VERSION 5.8 ;
BUSBITCHARS "[]" ;
DIVIDERCHAR "/" ;
UNITS
    DATABASE MICRONS 1000 ;
END UNITS

VIA ino_exec_entier_via1_2_1000_440_1_2_410_410
  VIARULE via1Array ;
  CUTSIZE 0.19 0.19 ;
  LAYERS Metal1 Via1 Metal2 ;
  CUTSPACING 0.22 0.22 ;
  ENCLOSURE 0.05 0.125 0.005 0.05 ;
  ROWCOL 1 2 ;
END ino_exec_entier_via1_2_1000_440_1_2_410_410

VIA ino_exec_entier_via2_3_1000_440_1_2_410_410
  VIARULE via2Array ;
  CUTSIZE 0.19 0.19 ;
  LAYERS Metal2 Via2 Metal3 ;
  CUTSPACING 0.22 0.22 ;
  ENCLOSURE 0.005 0.05 0.05 0.005 ;
  ROWCOL 1 2 ;
END ino_exec_entier_via2_3_1000_440_1_2_410_410

VIA ino_exec_entier_via3_4_1000_440_1_2_410_410
  VIARULE via3Array ;
  CUTSIZE 0.19 0.19 ;
  LAYERS Metal3 Via3 Metal4 ;
  CUTSPACING 0.22 0.22 ;
  ENCLOSURE 0.05 0.005 0.2 0.05 ;
  ROWCOL 1 2 ;
END ino_exec_entier_via3_4_1000_440_1_2_410_410

VIA ino_exec_entier_via4_5_1000_2000_1_1_840_840
  VIARULE viaTop1Array ;
  CUTSIZE 0.42 0.42 ;
  LAYERS Metal4 TopVia1 TopMetal1 ;
  CUTSPACING 0.42 0.42 ;
  ENCLOSURE 0.29 0.1 0.42 0.79 ;
END ino_exec_entier_via4_5_1000_2000_1_1_840_840

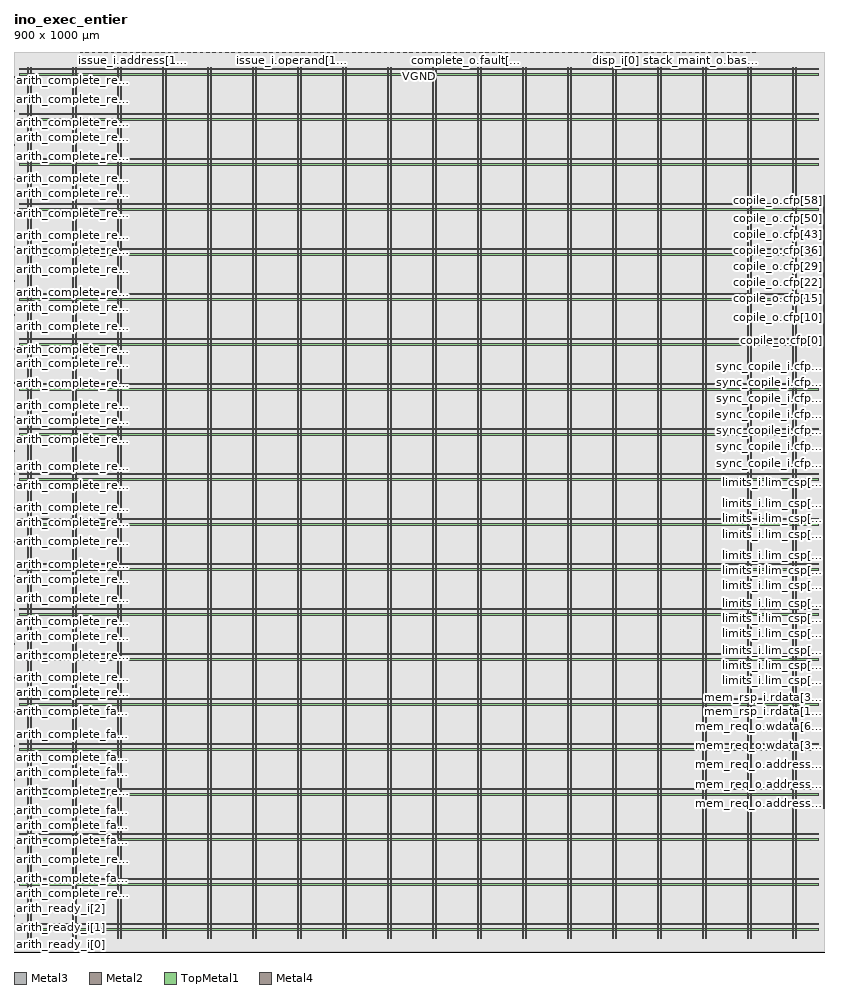
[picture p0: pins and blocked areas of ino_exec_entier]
MACRO ino_exec_entier
  FOREIGN ino_exec_entier 0 0 ;
  CLASS BLOCK ;
  SIZE 900 BY 1000 ;
  PIN arith_complete_fault_i.code[0]
    DIRECTION INPUT ;
    USE SIGNAL ;
    PORT
      LAYER Metal3 ;
        RECT  0 90.1 0.4 90.5 ;
    END
  END arith_complete_fault_i.code[0]
  PIN arith_complete_fault_i.code[1]
    DIRECTION INPUT ;
    USE SIGNAL ;
    PORT
      LAYER Metal3 ;
        RECT  0 115.3 0.4 115.7 ;
    END
  END arith_complete_fault_i.code[1]
  PIN arith_complete_fault_i.code[2]
    DIRECTION INPUT ;
    USE SIGNAL ;
    PORT
      LAYER Metal3 ;
        RECT  0 140.5 0.4 140.9 ;
    END
  END arith_complete_fault_i.code[2]
  PIN arith_complete_fault_i.code[3]
    DIRECTION INPUT ;
    USE SIGNAL ;
    PORT
      LAYER Metal3 ;
        RECT  0 165.7 0.4 166.1 ;
    END
  END arith_complete_fault_i.code[3]
  PIN arith_complete_fault_i.code[4]
    DIRECTION INPUT ;
    USE SIGNAL ;
    PORT
      LAYER Metal3 ;
        RECT  0 190.9 0.4 191.3 ;
    END
  END arith_complete_fault_i.code[4]
  PIN arith_complete_fault_i.code[5]
    DIRECTION INPUT ;
    USE SIGNAL ;
    PORT
      LAYER Metal3 ;
        RECT  0 216.1 0.4 216.5 ;
    END
  END arith_complete_fault_i.code[5]
  PIN arith_complete_fault_i.code[6]
    DIRECTION INPUT ;
    USE SIGNAL ;
    PORT
      LAYER Metal3 ;
        RECT  0 241.3 0.4 241.7 ;
    END
  END arith_complete_fault_i.code[6]
  PIN arith_complete_fault_i.code[7]
    DIRECTION INPUT ;
    USE SIGNAL ;
    PORT
      LAYER Metal3 ;
        RECT  0 266.5 0.4 266.9 ;
    END
  END arith_complete_fault_i.code[7]
  PIN arith_complete_fault_i.valid
    DIRECTION INPUT ;
    USE SIGNAL ;
    PORT
      LAYER Metal3 ;
        RECT  0 52.3 0.4 52.7 ;
    END
  END arith_complete_fault_i.valid
  PIN arith_complete_result_i[0]
    DIRECTION INPUT ;
    USE SIGNAL ;
    PORT
      LAYER Metal3 ;
        RECT  0 102.7 0.4 103.1 ;
    END
  END arith_complete_result_i[0]
  PIN arith_complete_result_i[10]
    DIRECTION INPUT ;
    USE SIGNAL ;
    PORT
      LAYER Metal3 ;
        RECT  0 316.9 0.4 317.3 ;
    END
  END arith_complete_result_i[10]
  PIN arith_complete_result_i[11]
    DIRECTION INPUT ;
    USE SIGNAL ;
    PORT
      LAYER Metal3 ;
        RECT  0 329.5 0.4 329.9 ;
    END
  END arith_complete_result_i[11]
  PIN arith_complete_result_i[12]
    DIRECTION INPUT ;
    USE SIGNAL ;
    PORT
      LAYER Metal3 ;
        RECT  0 342.1 0.4 342.5 ;
    END
  END arith_complete_result_i[12]
  PIN arith_complete_result_i[13]
    DIRECTION INPUT ;
    USE SIGNAL ;
    PORT
      LAYER Metal3 ;
        RECT  0 354.7 0.4 355.1 ;
    END
  END arith_complete_result_i[13]
  PIN arith_complete_result_i[14]
    DIRECTION INPUT ;
    USE SIGNAL ;
    PORT
      LAYER Metal3 ;
        RECT  0 367.3 0.4 367.7 ;
    END
  END arith_complete_result_i[14]
  PIN arith_complete_result_i[15]
    DIRECTION INPUT ;
    USE SIGNAL ;
    PORT
      LAYER Metal3 ;
        RECT  0 379.9 0.4 380.3 ;
    END
  END arith_complete_result_i[15]
  PIN arith_complete_result_i[16]
    DIRECTION INPUT ;
    USE SIGNAL ;
    PORT
      LAYER Metal3 ;
        RECT  0 392.5 0.4 392.9 ;
    END
  END arith_complete_result_i[16]
  PIN arith_complete_result_i[17]
    DIRECTION INPUT ;
    USE SIGNAL ;
    PORT
      LAYER Metal3 ;
        RECT  0 405.1 0.4 405.5 ;
    END
  END arith_complete_result_i[17]
  PIN arith_complete_result_i[18]
    DIRECTION INPUT ;
    USE SIGNAL ;
    PORT
      LAYER Metal3 ;
        RECT  0 417.7 0.4 418.1 ;
    END
  END arith_complete_result_i[18]
  PIN arith_complete_result_i[19]
    DIRECTION INPUT ;
    USE SIGNAL ;
    PORT
      LAYER Metal3 ;
        RECT  0 430.3 0.4 430.7 ;
    END
  END arith_complete_result_i[19]
  PIN arith_complete_result_i[1]
    DIRECTION INPUT ;
    USE SIGNAL ;
    PORT
      LAYER Metal3 ;
        RECT  0 127.9 0.4 128.3 ;
    END
  END arith_complete_result_i[1]
  PIN arith_complete_result_i[20]
    DIRECTION INPUT ;
    USE SIGNAL ;
    PORT
      LAYER Metal3 ;
        RECT  0 442.9 0.4 443.3 ;
    END
  END arith_complete_result_i[20]
  PIN arith_complete_result_i[21]
    DIRECTION INPUT ;
    USE SIGNAL ;
    PORT
      LAYER Metal3 ;
        RECT  0 455.5 0.4 455.9 ;
    END
  END arith_complete_result_i[21]
  PIN arith_complete_result_i[22]
    DIRECTION INPUT ;
    USE SIGNAL ;
    PORT
      LAYER Metal3 ;
        RECT  0 468.1 0.4 468.5 ;
    END
  END arith_complete_result_i[22]
  PIN arith_complete_result_i[23]
    DIRECTION INPUT ;
    USE SIGNAL ;
    PORT
      LAYER Metal3 ;
        RECT  0 480.7 0.4 481.1 ;
    END
  END arith_complete_result_i[23]
  PIN arith_complete_result_i[24]
    DIRECTION INPUT ;
    USE SIGNAL ;
    PORT
      LAYER Metal3 ;
        RECT  0 493.3 0.4 493.7 ;
    END
  END arith_complete_result_i[24]
  PIN arith_complete_result_i[25]
    DIRECTION INPUT ;
    USE SIGNAL ;
    PORT
      LAYER Metal3 ;
        RECT  0 505.9 0.4 506.3 ;
    END
  END arith_complete_result_i[25]
  PIN arith_complete_result_i[26]
    DIRECTION INPUT ;
    USE SIGNAL ;
    PORT
      LAYER Metal3 ;
        RECT  0 518.5 0.4 518.9 ;
    END
  END arith_complete_result_i[26]
  PIN arith_complete_result_i[27]
    DIRECTION INPUT ;
    USE SIGNAL ;
    PORT
      LAYER Metal3 ;
        RECT  0 531.1 0.4 531.5 ;
    END
  END arith_complete_result_i[27]
  PIN arith_complete_result_i[28]
    DIRECTION INPUT ;
    USE SIGNAL ;
    PORT
      LAYER Metal3 ;
        RECT  0 543.7 0.4 544.1 ;
    END
  END arith_complete_result_i[28]
  PIN arith_complete_result_i[29]
    DIRECTION INPUT ;
    USE SIGNAL ;
    PORT
      LAYER Metal3 ;
        RECT  0 556.3 0.4 556.7 ;
    END
  END arith_complete_result_i[29]
  PIN arith_complete_result_i[2]
    DIRECTION INPUT ;
    USE SIGNAL ;
    PORT
      LAYER Metal3 ;
        RECT  0 153.1 0.4 153.5 ;
    END
  END arith_complete_result_i[2]
  PIN arith_complete_result_i[30]
    DIRECTION INPUT ;
    USE SIGNAL ;
    PORT
      LAYER Metal3 ;
        RECT  0 568.9 0.4 569.3 ;
    END
  END arith_complete_result_i[30]
  PIN arith_complete_result_i[31]
    DIRECTION INPUT ;
    USE SIGNAL ;
    PORT
      LAYER Metal3 ;
        RECT  0 581.5 0.4 581.9 ;
    END
  END arith_complete_result_i[31]
  PIN arith_complete_result_i[32]
    DIRECTION INPUT ;
    USE SIGNAL ;
    PORT
      LAYER Metal3 ;
        RECT  0 594.1 0.4 594.5 ;
    END
  END arith_complete_result_i[32]
  PIN arith_complete_result_i[33]
    DIRECTION INPUT ;
    USE SIGNAL ;
    PORT
      LAYER Metal3 ;
        RECT  0 606.7 0.4 607.1 ;
    END
  END arith_complete_result_i[33]
  PIN arith_complete_result_i[34]
    DIRECTION INPUT ;
    USE SIGNAL ;
    PORT
      LAYER Metal3 ;
        RECT  0 619.3 0.4 619.7 ;
    END
  END arith_complete_result_i[34]
  PIN arith_complete_result_i[35]
    DIRECTION INPUT ;
    USE SIGNAL ;
    PORT
      LAYER Metal3 ;
        RECT  0 631.9 0.4 632.3 ;
    END
  END arith_complete_result_i[35]
  PIN arith_complete_result_i[36]
    DIRECTION INPUT ;
    USE SIGNAL ;
    PORT
      LAYER Metal3 ;
        RECT  0 644.5 0.4 644.9 ;
    END
  END arith_complete_result_i[36]
  PIN arith_complete_result_i[37]
    DIRECTION INPUT ;
    USE SIGNAL ;
    PORT
      LAYER Metal3 ;
        RECT  0 657.1 0.4 657.5 ;
    END
  END arith_complete_result_i[37]
  PIN arith_complete_result_i[38]
    DIRECTION INPUT ;
    USE SIGNAL ;
    PORT
      LAYER Metal3 ;
        RECT  0 669.7 0.4 670.1 ;
    END
  END arith_complete_result_i[38]
  PIN arith_complete_result_i[39]
    DIRECTION INPUT ;
    USE SIGNAL ;
    PORT
      LAYER Metal3 ;
        RECT  0 682.3 0.4 682.7 ;
    END
  END arith_complete_result_i[39]
  PIN arith_complete_result_i[3]
    DIRECTION INPUT ;
    USE SIGNAL ;
    PORT
      LAYER Metal3 ;
        RECT  0 178.3 0.4 178.7 ;
    END
  END arith_complete_result_i[3]
  PIN arith_complete_result_i[40]
    DIRECTION INPUT ;
    USE SIGNAL ;
    PORT
      LAYER Metal3 ;
        RECT  0 694.9 0.4 695.3 ;
    END
  END arith_complete_result_i[40]
  PIN arith_complete_result_i[41]
    DIRECTION INPUT ;
    USE SIGNAL ;
    PORT
      LAYER Metal3 ;
        RECT  0 707.5 0.4 707.9 ;
    END
  END arith_complete_result_i[41]
  PIN arith_complete_result_i[42]
    DIRECTION INPUT ;
    USE SIGNAL ;
    PORT
      LAYER Metal3 ;
        RECT  0 720.1 0.4 720.5 ;
    END
  END arith_complete_result_i[42]
  PIN arith_complete_result_i[43]
    DIRECTION INPUT ;
    USE SIGNAL ;
    PORT
      LAYER Metal3 ;
        RECT  0 732.7 0.4 733.1 ;
    END
  END arith_complete_result_i[43]
  PIN arith_complete_result_i[44]
    DIRECTION INPUT ;
    USE SIGNAL ;
    PORT
      LAYER Metal3 ;
        RECT  0 745.3 0.4 745.7 ;
    END
  END arith_complete_result_i[44]
  PIN arith_complete_result_i[45]
    DIRECTION INPUT ;
    USE SIGNAL ;
    PORT
      LAYER Metal3 ;
        RECT  0 757.9 0.4 758.3 ;
    END
  END arith_complete_result_i[45]
  PIN arith_complete_result_i[46]
    DIRECTION INPUT ;
    USE SIGNAL ;
    PORT
      LAYER Metal3 ;
        RECT  0 770.5 0.4 770.9 ;
    END
  END arith_complete_result_i[46]
  PIN arith_complete_result_i[47]
    DIRECTION INPUT ;
    USE SIGNAL ;
    PORT
      LAYER Metal3 ;
        RECT  0 783.1 0.4 783.5 ;
    END
  END arith_complete_result_i[47]
  PIN arith_complete_result_i[48]
    DIRECTION INPUT ;
    USE SIGNAL ;
    PORT
      LAYER Metal3 ;
        RECT  0 795.7 0.4 796.1 ;
    END
  END arith_complete_result_i[48]
  PIN arith_complete_result_i[49]
    DIRECTION INPUT ;
    USE SIGNAL ;
    PORT
      LAYER Metal3 ;
        RECT  0 808.3 0.4 808.7 ;
    END
  END arith_complete_result_i[49]
  PIN arith_complete_result_i[4]
    DIRECTION INPUT ;
    USE SIGNAL ;
    PORT
      LAYER Metal3 ;
        RECT  0 203.5 0.4 203.9 ;
    END
  END arith_complete_result_i[4]
  PIN arith_complete_result_i[50]
    DIRECTION INPUT ;
    USE SIGNAL ;
    PORT
      LAYER Metal3 ;
        RECT  0 820.9 0.4 821.3 ;
    END
  END arith_complete_result_i[50]
  PIN arith_complete_result_i[51]
    DIRECTION INPUT ;
    USE SIGNAL ;
    PORT
      LAYER Metal3 ;
        RECT  0 833.5 0.4 833.9 ;
    END
  END arith_complete_result_i[51]
  PIN arith_complete_result_i[52]
    DIRECTION INPUT ;
    USE SIGNAL ;
    PORT
      LAYER Metal3 ;
        RECT  0 846.1 0.4 846.5 ;
    END
  END arith_complete_result_i[52]
  PIN arith_complete_result_i[53]
    DIRECTION INPUT ;
    USE SIGNAL ;
    PORT
      LAYER Metal3 ;
        RECT  0 858.7 0.4 859.1 ;
    END
  END arith_complete_result_i[53]
  PIN arith_complete_result_i[54]
    DIRECTION INPUT ;
    USE SIGNAL ;
    PORT
      LAYER Metal3 ;
        RECT  0 871.3 0.4 871.7 ;
    END
  END arith_complete_result_i[54]
  PIN arith_complete_result_i[55]
    DIRECTION INPUT ;
    USE SIGNAL ;
    PORT
      LAYER Metal3 ;
        RECT  0 883.9 0.4 884.3 ;
    END
  END arith_complete_result_i[55]
  PIN arith_complete_result_i[56]
    DIRECTION INPUT ;
    USE SIGNAL ;
    PORT
      LAYER Metal3 ;
        RECT  0 896.5 0.4 896.9 ;
    END
  END arith_complete_result_i[56]
  PIN arith_complete_result_i[57]
    DIRECTION INPUT ;
    USE SIGNAL ;
    PORT
      LAYER Metal3 ;
        RECT  0 909.1 0.4 909.5 ;
    END
  END arith_complete_result_i[57]
  PIN arith_complete_result_i[58]
    DIRECTION INPUT ;
    USE SIGNAL ;
    PORT
      LAYER Metal3 ;
        RECT  0 921.7 0.4 922.1 ;
    END
  END arith_complete_result_i[58]
  PIN arith_complete_result_i[59]
    DIRECTION INPUT ;
    USE SIGNAL ;
    PORT
      LAYER Metal3 ;
        RECT  0 934.3 0.4 934.7 ;
    END
  END arith_complete_result_i[59]
  PIN arith_complete_result_i[5]
    DIRECTION INPUT ;
    USE SIGNAL ;
    PORT
      LAYER Metal3 ;
        RECT  0 228.7 0.4 229.1 ;
    END
  END arith_complete_result_i[5]
  PIN arith_complete_result_i[60]
    DIRECTION INPUT ;
    USE SIGNAL ;
    PORT
      LAYER Metal3 ;
        RECT  0 946.9 0.4 947.3 ;
    END
  END arith_complete_result_i[60]
  PIN arith_complete_result_i[61]
    DIRECTION INPUT ;
    USE SIGNAL ;
    PORT
      LAYER Metal3 ;
        RECT  0 959.5 0.4 959.9 ;
    END
  END arith_complete_result_i[61]
  PIN arith_complete_result_i[62]
    DIRECTION INPUT ;
    USE SIGNAL ;
    PORT
      LAYER Metal3 ;
        RECT  0 972.1 0.4 972.5 ;
    END
  END arith_complete_result_i[62]
  PIN arith_complete_result_i[63]
    DIRECTION INPUT ;
    USE SIGNAL ;
    PORT
      LAYER Metal3 ;
        RECT  0 984.7 0.4 985.1 ;
    END
  END arith_complete_result_i[63]
  PIN arith_complete_result_i[6]
    DIRECTION INPUT ;
    USE SIGNAL ;
    PORT
      LAYER Metal3 ;
        RECT  0 253.9 0.4 254.3 ;
    END
  END arith_complete_result_i[6]
  PIN arith_complete_result_i[7]
    DIRECTION INPUT ;
    USE SIGNAL ;
    PORT
      LAYER Metal3 ;
        RECT  0 279.1 0.4 279.5 ;
    END
  END arith_complete_result_i[7]
  PIN arith_complete_result_i[8]
    DIRECTION INPUT ;
    USE SIGNAL ;
    PORT
      LAYER Metal3 ;
        RECT  0 291.7 0.4 292.1 ;
    END
  END arith_complete_result_i[8]
  PIN arith_complete_result_i[9]
    DIRECTION INPUT ;
    USE SIGNAL ;
    PORT
      LAYER Metal3 ;
        RECT  0 304.3 0.4 304.7 ;
    END
  END arith_complete_result_i[9]
  PIN arith_complete_result_valid_i
    DIRECTION INPUT ;
    USE SIGNAL ;
    PORT
      LAYER Metal3 ;
        RECT  0 64.9 0.4 65.3 ;
    END
  END arith_complete_result_valid_i
  PIN arith_complete_valid_i
    DIRECTION INPUT ;
    USE SIGNAL ;
    PORT
      LAYER Metal3 ;
        RECT  0 77.5 0.4 77.9 ;
    END
  END arith_complete_valid_i
  PIN arith_ready_i[0]
    DIRECTION INPUT ;
    USE SIGNAL ;
    PORT
      LAYER Metal3 ;
        RECT  0 14.5 0.4 14.9 ;
    END
  END arith_ready_i[0]
  PIN arith_ready_i[1]
    DIRECTION INPUT ;
    USE SIGNAL ;
    PORT
      LAYER Metal3 ;
        RECT  0 27.1 0.4 27.5 ;
    END
  END arith_ready_i[1]
  PIN arith_ready_i[2]
    DIRECTION INPUT ;
    USE SIGNAL ;
    PORT
      LAYER Metal3 ;
        RECT  0 39.7 0.4 40.1 ;
    END
  END arith_ready_i[2]
  PIN clk_i
    DIRECTION INPUT ;
    USE SIGNAL ;
    PORT
      LAYER Metal2 ;
        RECT  75.16 999.6 75.56 1000 ;
    END
  END clk_i
  PIN complete_o.fault[0]
    DIRECTION OUTPUT ;
    USE SIGNAL ;
    PORT
      LAYER Metal2 ;
        RECT  502.36 999.6 502.76 1000 ;
    END
  END complete_o.fault[0]
  PIN complete_o.fault[1]
    DIRECTION OUTPUT ;
    USE SIGNAL ;
    PORT
      LAYER Metal2 ;
        RECT  505.24 999.6 505.64 1000 ;
    END
  END complete_o.fault[1]
  PIN complete_o.fault[2]
    DIRECTION OUTPUT ;
    USE SIGNAL ;
    PORT
      LAYER Metal2 ;
        RECT  508.12 999.6 508.52 1000 ;
    END
  END complete_o.fault[2]
  PIN complete_o.fault[3]
    DIRECTION OUTPUT ;
    USE SIGNAL ;
    PORT
      LAYER Metal2 ;
        RECT  511 999.6 511.4 1000 ;
    END
  END complete_o.fault[3]
  PIN complete_o.fault[4]
    DIRECTION OUTPUT ;
    USE SIGNAL ;
    PORT
      LAYER Metal2 ;
        RECT  513.88 999.6 514.28 1000 ;
    END
  END complete_o.fault[4]
  PIN complete_o.fault[5]
    DIRECTION OUTPUT ;
    USE SIGNAL ;
    PORT
      LAYER Metal2 ;
        RECT  516.76 999.6 517.16 1000 ;
    END
  END complete_o.fault[5]
  PIN complete_o.fault[6]
    DIRECTION OUTPUT ;
    USE SIGNAL ;
    PORT
      LAYER Metal2 ;
        RECT  519.64 999.6 520.04 1000 ;
    END
  END complete_o.fault[6]
  PIN complete_o.fault[7]
    DIRECTION OUTPUT ;
    USE SIGNAL ;
    PORT
      LAYER Metal2 ;
        RECT  522.52 999.6 522.92 1000 ;
    END
  END complete_o.fault[7]
  PIN complete_o.fault[8]
    DIRECTION OUTPUT ;
    USE SIGNAL ;
    PORT
      LAYER Metal2 ;
        RECT  525.4 999.6 525.8 1000 ;
    END
  END complete_o.fault[8]
  PIN complete_o.result[0]
    DIRECTION OUTPUT ;
    USE SIGNAL ;
    PORT
      LAYER Metal2 ;
        RECT  503.32 999.6 503.72 1000 ;
    END
  END complete_o.result[0]
  PIN complete_o.result[10]
    DIRECTION OUTPUT ;
    USE SIGNAL ;
    PORT
      LAYER Metal2 ;
        RECT  530.2 999.6 530.6 1000 ;
    END
  END complete_o.result[10]
  PIN complete_o.result[11]
    DIRECTION OUTPUT ;
    USE SIGNAL ;
    PORT
      LAYER Metal2 ;
        RECT  532.12 999.6 532.52 1000 ;
    END
  END complete_o.result[11]
  PIN complete_o.result[12]
    DIRECTION OUTPUT ;
    USE SIGNAL ;
    PORT
      LAYER Metal2 ;
        RECT  534.04 999.6 534.44 1000 ;
    END
  END complete_o.result[12]
  PIN complete_o.result[13]
    DIRECTION OUTPUT ;
    USE SIGNAL ;
    PORT
      LAYER Metal2 ;
        RECT  535.96 999.6 536.36 1000 ;
    END
  END complete_o.result[13]
  PIN complete_o.result[14]
    DIRECTION OUTPUT ;
    USE SIGNAL ;
    PORT
      LAYER Metal2 ;
        RECT  537.88 999.6 538.28 1000 ;
    END
  END complete_o.result[14]
  PIN complete_o.result[15]
    DIRECTION OUTPUT ;
    USE SIGNAL ;
    PORT
      LAYER Metal2 ;
        RECT  539.8 999.6 540.2 1000 ;
    END
  END complete_o.result[15]
  PIN complete_o.result[16]
    DIRECTION OUTPUT ;
    USE SIGNAL ;
    PORT
      LAYER Metal2 ;
        RECT  541.72 999.6 542.12 1000 ;
    END
  END complete_o.result[16]
  PIN complete_o.result[17]
    DIRECTION OUTPUT ;
    USE SIGNAL ;
    PORT
      LAYER Metal2 ;
        RECT  543.64 999.6 544.04 1000 ;
    END
  END complete_o.result[17]
  PIN complete_o.result[18]
    DIRECTION OUTPUT ;
    USE SIGNAL ;
    PORT
      LAYER Metal2 ;
        RECT  545.56 999.6 545.96 1000 ;
    END
  END complete_o.result[18]
  PIN complete_o.result[19]
    DIRECTION OUTPUT ;
    USE SIGNAL ;
    PORT
      LAYER Metal2 ;
        RECT  547.48 999.6 547.88 1000 ;
    END
  END complete_o.result[19]
  PIN complete_o.result[1]
    DIRECTION OUTPUT ;
    USE SIGNAL ;
    PORT
      LAYER Metal2 ;
        RECT  506.2 999.6 506.6 1000 ;
    END
  END complete_o.result[1]
  PIN complete_o.result[20]
    DIRECTION OUTPUT ;
    USE SIGNAL ;
    PORT
      LAYER Metal2 ;
        RECT  549.4 999.6 549.8 1000 ;
    END
  END complete_o.result[20]
  PIN complete_o.result[21]
    DIRECTION OUTPUT ;
    USE SIGNAL ;
    PORT
      LAYER Metal2 ;
        RECT  551.32 999.6 551.72 1000 ;
    END
  END complete_o.result[21]
  PIN complete_o.result[22]
    DIRECTION OUTPUT ;
    USE SIGNAL ;
    PORT
      LAYER Metal2 ;
        RECT  553.24 999.6 553.64 1000 ;
    END
  END complete_o.result[22]
  PIN complete_o.result[23]
    DIRECTION OUTPUT ;
    USE SIGNAL ;
    PORT
      LAYER Metal2 ;
        RECT  555.16 999.6 555.56 1000 ;
    END
  END complete_o.result[23]
  PIN complete_o.result[24]
    DIRECTION OUTPUT ;
    USE SIGNAL ;
    PORT
      LAYER Metal2 ;
        RECT  557.08 999.6 557.48 1000 ;
    END
  END complete_o.result[24]
  PIN complete_o.result[25]
    DIRECTION OUTPUT ;
    USE SIGNAL ;
    PORT
      LAYER Metal2 ;
        RECT  559 999.6 559.4 1000 ;
    END
  END complete_o.result[25]
  PIN complete_o.result[26]
    DIRECTION OUTPUT ;
    USE SIGNAL ;
    PORT
      LAYER Metal2 ;
        RECT  560.92 999.6 561.32 1000 ;
    END
  END complete_o.result[26]
  PIN complete_o.result[27]
    DIRECTION OUTPUT ;
    USE SIGNAL ;
    PORT
      LAYER Metal2 ;
        RECT  562.84 999.6 563.24 1000 ;
    END
  END complete_o.result[27]
  PIN complete_o.result[28]
    DIRECTION OUTPUT ;
    USE SIGNAL ;
    PORT
      LAYER Metal2 ;
        RECT  564.76 999.6 565.16 1000 ;
    END
  END complete_o.result[28]
  PIN complete_o.result[29]
    DIRECTION OUTPUT ;
    USE SIGNAL ;
    PORT
      LAYER Metal2 ;
        RECT  566.68 999.6 567.08 1000 ;
    END
  END complete_o.result[29]
  PIN complete_o.result[2]
    DIRECTION OUTPUT ;
    USE SIGNAL ;
    PORT
      LAYER Metal2 ;
        RECT  509.08 999.6 509.48 1000 ;
    END
  END complete_o.result[2]
  PIN complete_o.result[30]
    DIRECTION OUTPUT ;
    USE SIGNAL ;
    PORT
      LAYER Metal2 ;
        RECT  568.6 999.6 569 1000 ;
    END
  END complete_o.result[30]
  PIN complete_o.result[31]
    DIRECTION OUTPUT ;
    USE SIGNAL ;
    PORT
      LAYER Metal2 ;
        RECT  570.52 999.6 570.92 1000 ;
    END
  END complete_o.result[31]
  PIN complete_o.result[32]
    DIRECTION OUTPUT ;
    USE SIGNAL ;
    PORT
      LAYER Metal2 ;
        RECT  572.44 999.6 572.84 1000 ;
    END
  END complete_o.result[32]
  PIN complete_o.result[33]
    DIRECTION OUTPUT ;
    USE SIGNAL ;
    PORT
      LAYER Metal2 ;
        RECT  573.4 999.6 573.8 1000 ;
    END
  END complete_o.result[33]
  PIN complete_o.result[34]
    DIRECTION OUTPUT ;
    USE SIGNAL ;
    PORT
      LAYER Metal2 ;
        RECT  574.36 999.6 574.76 1000 ;
    END
  END complete_o.result[34]
  PIN complete_o.result[35]
    DIRECTION OUTPUT ;
    USE SIGNAL ;
    PORT
      LAYER Metal2 ;
        RECT  575.32 999.6 575.72 1000 ;
    END
  END complete_o.result[35]
  PIN complete_o.result[36]
    DIRECTION OUTPUT ;
    USE SIGNAL ;
    PORT
      LAYER Metal2 ;
        RECT  576.28 999.6 576.68 1000 ;
    END
  END complete_o.result[36]
  PIN complete_o.result[37]
    DIRECTION OUTPUT ;
    USE SIGNAL ;
    PORT
      LAYER Metal2 ;
        RECT  577.24 999.6 577.64 1000 ;
    END
  END complete_o.result[37]
  PIN complete_o.result[38]
    DIRECTION OUTPUT ;
    USE SIGNAL ;
    PORT
      LAYER Metal2 ;
        RECT  578.2 999.6 578.6 1000 ;
    END
  END complete_o.result[38]
  PIN complete_o.result[39]
    DIRECTION OUTPUT ;
    USE SIGNAL ;
    PORT
      LAYER Metal2 ;
        RECT  579.16 999.6 579.56 1000 ;
    END
  END complete_o.result[39]
  PIN complete_o.result[3]
    DIRECTION OUTPUT ;
    USE SIGNAL ;
    PORT
      LAYER Metal2 ;
        RECT  511.96 999.6 512.36 1000 ;
    END
  END complete_o.result[3]
  PIN complete_o.result[40]
    DIRECTION OUTPUT ;
    USE SIGNAL ;
    PORT
      LAYER Metal2 ;
        RECT  580.12 999.6 580.52 1000 ;
    END
  END complete_o.result[40]
  PIN complete_o.result[41]
    DIRECTION OUTPUT ;
    USE SIGNAL ;
    PORT
      LAYER Metal2 ;
        RECT  581.08 999.6 581.48 1000 ;
    END
  END complete_o.result[41]
  PIN complete_o.result[42]
    DIRECTION OUTPUT ;
    USE SIGNAL ;
    PORT
      LAYER Metal2 ;
        RECT  582.04 999.6 582.44 1000 ;
    END
  END complete_o.result[42]
  PIN complete_o.result[43]
    DIRECTION OUTPUT ;
    USE SIGNAL ;
    PORT
      LAYER Metal2 ;
        RECT  583 999.6 583.4 1000 ;
    END
  END complete_o.result[43]
  PIN complete_o.result[44]
    DIRECTION OUTPUT ;
    USE SIGNAL ;
    PORT
      LAYER Metal2 ;
        RECT  583.96 999.6 584.36 1000 ;
    END
  END complete_o.result[44]
  PIN complete_o.result[45]
    DIRECTION OUTPUT ;
    USE SIGNAL ;
    PORT
      LAYER Metal2 ;
        RECT  584.92 999.6 585.32 1000 ;
    END
  END complete_o.result[45]
  PIN complete_o.result[46]
    DIRECTION OUTPUT ;
    USE SIGNAL ;
    PORT
      LAYER Metal2 ;
        RECT  585.88 999.6 586.28 1000 ;
    END
  END complete_o.result[46]
  PIN complete_o.result[47]
    DIRECTION OUTPUT ;
    USE SIGNAL ;
    PORT
      LAYER Metal2 ;
        RECT  586.84 999.6 587.24 1000 ;
    END
  END complete_o.result[47]
  PIN complete_o.result[48]
    DIRECTION OUTPUT ;
    USE SIGNAL ;
    PORT
      LAYER Metal2 ;
        RECT  587.8 999.6 588.2 1000 ;
    END
  END complete_o.result[48]
  PIN complete_o.result[49]
    DIRECTION OUTPUT ;
    USE SIGNAL ;
    PORT
      LAYER Metal2 ;
        RECT  588.76 999.6 589.16 1000 ;
    END
  END complete_o.result[49]
  PIN complete_o.result[4]
    DIRECTION OUTPUT ;
    USE SIGNAL ;
    PORT
      LAYER Metal2 ;
        RECT  514.84 999.6 515.24 1000 ;
    END
  END complete_o.result[4]
  PIN complete_o.result[50]
    DIRECTION OUTPUT ;
    USE SIGNAL ;
    PORT
      LAYER Metal2 ;
        RECT  589.72 999.6 590.12 1000 ;
    END
  END complete_o.result[50]
  PIN complete_o.result[51]
    DIRECTION OUTPUT ;
    USE SIGNAL ;
    PORT
      LAYER Metal2 ;
        RECT  590.68 999.6 591.08 1000 ;
    END
  END complete_o.result[51]
  PIN complete_o.result[52]
    DIRECTION OUTPUT ;
    USE SIGNAL ;
    PORT
      LAYER Metal2 ;
        RECT  591.64 999.6 592.04 1000 ;
    END
  END complete_o.result[52]
  PIN complete_o.result[53]
    DIRECTION OUTPUT ;
    USE SIGNAL ;
    PORT
      LAYER Metal2 ;
        RECT  592.6 999.6 593 1000 ;
    END
  END complete_o.result[53]
  PIN complete_o.result[54]
    DIRECTION OUTPUT ;
    USE SIGNAL ;
    PORT
      LAYER Metal2 ;
        RECT  593.56 999.6 593.96 1000 ;
    END
  END complete_o.result[54]
  PIN complete_o.result[55]
    DIRECTION OUTPUT ;
    USE SIGNAL ;
    PORT
      LAYER Metal2 ;
        RECT  594.52 999.6 594.92 1000 ;
    END
  END complete_o.result[55]
  PIN complete_o.result[56]
    DIRECTION OUTPUT ;
    USE SIGNAL ;
    PORT
      LAYER Metal2 ;
        RECT  595.48 999.6 595.88 1000 ;
    END
  END complete_o.result[56]
  PIN complete_o.result[57]
    DIRECTION OUTPUT ;
    USE SIGNAL ;
    PORT
      LAYER Metal2 ;
        RECT  596.44 999.6 596.84 1000 ;
    END
  END complete_o.result[57]
  PIN complete_o.result[58]
    DIRECTION OUTPUT ;
    USE SIGNAL ;
    PORT
      LAYER Metal2 ;
        RECT  597.4 999.6 597.8 1000 ;
    END
  END complete_o.result[58]
  PIN complete_o.result[59]
    DIRECTION OUTPUT ;
    USE SIGNAL ;
    PORT
      LAYER Metal2 ;
        RECT  598.36 999.6 598.76 1000 ;
    END
  END complete_o.result[59]
  PIN complete_o.result[5]
    DIRECTION OUTPUT ;
    USE SIGNAL ;
    PORT
      LAYER Metal2 ;
        RECT  517.72 999.6 518.12 1000 ;
    END
  END complete_o.result[5]
  PIN complete_o.result[60]
    DIRECTION OUTPUT ;
    USE SIGNAL ;
    PORT
      LAYER Metal2 ;
        RECT  599.32 999.6 599.72 1000 ;
    END
  END complete_o.result[60]
  PIN complete_o.result[61]
    DIRECTION OUTPUT ;
    USE SIGNAL ;
    PORT
      LAYER Metal2 ;
        RECT  600.28 999.6 600.68 1000 ;
    END
  END complete_o.result[61]
  PIN complete_o.result[62]
    DIRECTION OUTPUT ;
    USE SIGNAL ;
    PORT
      LAYER Metal2 ;
        RECT  601.24 999.6 601.64 1000 ;
    END
  END complete_o.result[62]
  PIN complete_o.result[63]
    DIRECTION OUTPUT ;
    USE SIGNAL ;
    PORT
      LAYER Metal2 ;
        RECT  602.2 999.6 602.6 1000 ;
    END
  END complete_o.result[63]
  PIN complete_o.result[6]
    DIRECTION OUTPUT ;
    USE SIGNAL ;
    PORT
      LAYER Metal2 ;
        RECT  520.6 999.6 521 1000 ;
    END
  END complete_o.result[6]
  PIN complete_o.result[7]
    DIRECTION OUTPUT ;
    USE SIGNAL ;
    PORT
      LAYER Metal2 ;
        RECT  523.48 999.6 523.88 1000 ;
    END
  END complete_o.result[7]
  PIN complete_o.result[8]
    DIRECTION OUTPUT ;
    USE SIGNAL ;
    PORT
      LAYER Metal2 ;
        RECT  526.36 999.6 526.76 1000 ;
    END
  END complete_o.result[8]
  PIN complete_o.result[9]
    DIRECTION OUTPUT ;
    USE SIGNAL ;
    PORT
      LAYER Metal2 ;
        RECT  528.28 999.6 528.68 1000 ;
    END
  END complete_o.result[9]
  PIN complete_o.result_valid
    DIRECTION OUTPUT ;
    USE SIGNAL ;
    PORT
      LAYER Metal2 ;
        RECT  499.48 999.6 499.88 1000 ;
    END
  END complete_o.result_valid
  PIN complete_o.taken
    DIRECTION OUTPUT ;
    USE SIGNAL ;
    PORT
      LAYER Metal2 ;
        RECT  500.44 999.6 500.84 1000 ;
    END
  END complete_o.taken
  PIN complete_o.target[0]
    DIRECTION OUTPUT ;
    USE SIGNAL ;
    PORT
      LAYER Metal2 ;
        RECT  504.28 999.6 504.68 1000 ;
    END
  END complete_o.target[0]
  PIN complete_o.target[10]
    DIRECTION OUTPUT ;
    USE SIGNAL ;
    PORT
      LAYER Metal2 ;
        RECT  531.16 999.6 531.56 1000 ;
    END
  END complete_o.target[10]
  PIN complete_o.target[11]
    DIRECTION OUTPUT ;
    USE SIGNAL ;
    PORT
      LAYER Metal2 ;
        RECT  533.08 999.6 533.48 1000 ;
    END
  END complete_o.target[11]
  PIN complete_o.target[12]
    DIRECTION OUTPUT ;
    USE SIGNAL ;
    PORT
      LAYER Metal2 ;
        RECT  535 999.6 535.4 1000 ;
    END
  END complete_o.target[12]
  PIN complete_o.target[13]
    DIRECTION OUTPUT ;
    USE SIGNAL ;
    PORT
      LAYER Metal2 ;
        RECT  536.92 999.6 537.32 1000 ;
    END
  END complete_o.target[13]
  PIN complete_o.target[14]
    DIRECTION OUTPUT ;
    USE SIGNAL ;
    PORT
      LAYER Metal2 ;
        RECT  538.84 999.6 539.24 1000 ;
    END
  END complete_o.target[14]
  PIN complete_o.target[15]
    DIRECTION OUTPUT ;
    USE SIGNAL ;
    PORT
      LAYER Metal2 ;
        RECT  540.76 999.6 541.16 1000 ;
    END
  END complete_o.target[15]
  PIN complete_o.target[16]
    DIRECTION OUTPUT ;
    USE SIGNAL ;
    PORT
      LAYER Metal2 ;
        RECT  542.68 999.6 543.08 1000 ;
    END
  END complete_o.target[16]
  PIN complete_o.target[17]
    DIRECTION OUTPUT ;
    USE SIGNAL ;
    PORT
      LAYER Metal2 ;
        RECT  544.6 999.6 545 1000 ;
    END
  END complete_o.target[17]
  PIN complete_o.target[18]
    DIRECTION OUTPUT ;
    USE SIGNAL ;
    PORT
      LAYER Metal2 ;
        RECT  546.52 999.6 546.92 1000 ;
    END
  END complete_o.target[18]
  PIN complete_o.target[19]
    DIRECTION OUTPUT ;
    USE SIGNAL ;
    PORT
      LAYER Metal2 ;
        RECT  548.44 999.6 548.84 1000 ;
    END
  END complete_o.target[19]
  PIN complete_o.target[1]
    DIRECTION OUTPUT ;
    USE SIGNAL ;
    PORT
      LAYER Metal2 ;
        RECT  507.16 999.6 507.56 1000 ;
    END
  END complete_o.target[1]
  PIN complete_o.target[20]
    DIRECTION OUTPUT ;
    USE SIGNAL ;
    PORT
      LAYER Metal2 ;
        RECT  550.36 999.6 550.76 1000 ;
    END
  END complete_o.target[20]
  PIN complete_o.target[21]
    DIRECTION OUTPUT ;
    USE SIGNAL ;
    PORT
      LAYER Metal2 ;
        RECT  552.28 999.6 552.68 1000 ;
    END
  END complete_o.target[21]
  PIN complete_o.target[22]
    DIRECTION OUTPUT ;
    USE SIGNAL ;
    PORT
      LAYER Metal2 ;
        RECT  554.2 999.6 554.6 1000 ;
    END
  END complete_o.target[22]
  PIN complete_o.target[23]
    DIRECTION OUTPUT ;
    USE SIGNAL ;
    PORT
      LAYER Metal2 ;
        RECT  556.12 999.6 556.52 1000 ;
    END
  END complete_o.target[23]
  PIN complete_o.target[24]
    DIRECTION OUTPUT ;
    USE SIGNAL ;
    PORT
      LAYER Metal2 ;
        RECT  558.04 999.6 558.44 1000 ;
    END
  END complete_o.target[24]
  PIN complete_o.target[25]
    DIRECTION OUTPUT ;
    USE SIGNAL ;
    PORT
      LAYER Metal2 ;
        RECT  559.96 999.6 560.36 1000 ;
    END
  END complete_o.target[25]
  PIN complete_o.target[26]
    DIRECTION OUTPUT ;
    USE SIGNAL ;
    PORT
      LAYER Metal2 ;
        RECT  561.88 999.6 562.28 1000 ;
    END
  END complete_o.target[26]
  PIN complete_o.target[27]
    DIRECTION OUTPUT ;
    USE SIGNAL ;
    PORT
      LAYER Metal2 ;
        RECT  563.8 999.6 564.2 1000 ;
    END
  END complete_o.target[27]
  PIN complete_o.target[28]
    DIRECTION OUTPUT ;
    USE SIGNAL ;
    PORT
      LAYER Metal2 ;
        RECT  565.72 999.6 566.12 1000 ;
    END
  END complete_o.target[28]
  PIN complete_o.target[29]
    DIRECTION OUTPUT ;
    USE SIGNAL ;
    PORT
      LAYER Metal2 ;
        RECT  567.64 999.6 568.04 1000 ;
    END
  END complete_o.target[29]
  PIN complete_o.target[2]
    DIRECTION OUTPUT ;
    USE SIGNAL ;
    PORT
      LAYER Metal2 ;
        RECT  510.04 999.6 510.44 1000 ;
    END
  END complete_o.target[2]
  PIN complete_o.target[30]
    DIRECTION OUTPUT ;
    USE SIGNAL ;
    PORT
      LAYER Metal2 ;
        RECT  569.56 999.6 569.96 1000 ;
    END
  END complete_o.target[30]
  PIN complete_o.target[31]
    DIRECTION OUTPUT ;
    USE SIGNAL ;
    PORT
      LAYER Metal2 ;
        RECT  571.48 999.6 571.88 1000 ;
    END
  END complete_o.target[31]
  PIN complete_o.target[3]
    DIRECTION OUTPUT ;
    USE SIGNAL ;
    PORT
      LAYER Metal2 ;
        RECT  512.92 999.6 513.32 1000 ;
    END
  END complete_o.target[3]
  PIN complete_o.target[4]
    DIRECTION OUTPUT ;
    USE SIGNAL ;
    PORT
      LAYER Metal2 ;
        RECT  515.8 999.6 516.2 1000 ;
    END
  END complete_o.target[4]
  PIN complete_o.target[5]
    DIRECTION OUTPUT ;
    USE SIGNAL ;
    PORT
      LAYER Metal2 ;
        RECT  518.68 999.6 519.08 1000 ;
    END
  END complete_o.target[5]
  PIN complete_o.target[6]
    DIRECTION OUTPUT ;
    USE SIGNAL ;
    PORT
      LAYER Metal2 ;
        RECT  521.56 999.6 521.96 1000 ;
    END
  END complete_o.target[6]
  PIN complete_o.target[7]
    DIRECTION OUTPUT ;
    USE SIGNAL ;
    PORT
      LAYER Metal2 ;
        RECT  524.44 999.6 524.84 1000 ;
    END
  END complete_o.target[7]
  PIN complete_o.target[8]
    DIRECTION OUTPUT ;
    USE SIGNAL ;
    PORT
      LAYER Metal2 ;
        RECT  527.32 999.6 527.72 1000 ;
    END
  END complete_o.target[8]
  PIN complete_o.target[9]
    DIRECTION OUTPUT ;
    USE SIGNAL ;
    PORT
      LAYER Metal2 ;
        RECT  529.24 999.6 529.64 1000 ;
    END
  END complete_o.target[9]
  PIN complete_o.valid
    DIRECTION OUTPUT ;
    USE SIGNAL ;
    PORT
      LAYER Metal2 ;
        RECT  501.4 999.6 501.8 1000 ;
    END
  END complete_o.valid
  PIN copile_o.cfp[0]
    DIRECTION OUTPUT ;
    USE SIGNAL ;
    PORT
      LAYER Metal3 ;
        RECT  899.6 679.78 900 680.18 ;
    END
  END copile_o.cfp[0]
  PIN copile_o.cfp[10]
    DIRECTION OUTPUT ;
    USE SIGNAL ;
    PORT
      LAYER Metal3 ;
        RECT  899.6 704.98 900 705.38 ;
    END
  END copile_o.cfp[10]
  PIN copile_o.cfp[11]
    DIRECTION OUTPUT ;
    USE SIGNAL ;
    PORT
      LAYER Metal3 ;
        RECT  899.6 707.5 900 707.9 ;
    END
  END copile_o.cfp[11]
  PIN copile_o.cfp[12]
    DIRECTION OUTPUT ;
    USE SIGNAL ;
    PORT
      LAYER Metal3 ;
        RECT  899.6 710.02 900 710.42 ;
    END
  END copile_o.cfp[12]
  PIN copile_o.cfp[13]
    DIRECTION OUTPUT ;
    USE SIGNAL ;
    PORT
      LAYER Metal3 ;
        RECT  899.6 712.54 900 712.94 ;
    END
  END copile_o.cfp[13]
  PIN copile_o.cfp[14]
    DIRECTION OUTPUT ;
    USE SIGNAL ;
    PORT
      LAYER Metal3 ;
        RECT  899.6 715.06 900 715.46 ;
    END
  END copile_o.cfp[14]
  PIN copile_o.cfp[15]
    DIRECTION OUTPUT ;
    USE SIGNAL ;
    PORT
      LAYER Metal3 ;
        RECT  899.6 717.58 900 717.98 ;
    END
  END copile_o.cfp[15]
  PIN copile_o.cfp[16]
    DIRECTION OUTPUT ;
    USE SIGNAL ;
    PORT
      LAYER Metal3 ;
        RECT  899.6 720.1 900 720.5 ;
    END
  END copile_o.cfp[16]
  PIN copile_o.cfp[17]
    DIRECTION OUTPUT ;
    USE SIGNAL ;
    PORT
      LAYER Metal3 ;
        RECT  899.6 722.62 900 723.02 ;
    END
  END copile_o.cfp[17]
  PIN copile_o.cfp[18]
    DIRECTION OUTPUT ;
    USE SIGNAL ;
    PORT
      LAYER Metal3 ;
        RECT  899.6 725.14 900 725.54 ;
    END
  END copile_o.cfp[18]
  PIN copile_o.cfp[19]
    DIRECTION OUTPUT ;
    USE SIGNAL ;
    PORT
      LAYER Metal3 ;
        RECT  899.6 727.66 900 728.06 ;
    END
  END copile_o.cfp[19]
  PIN copile_o.cfp[1]
    DIRECTION OUTPUT ;
    USE SIGNAL ;
    PORT
      LAYER Metal3 ;
        RECT  899.6 682.3 900 682.7 ;
    END
  END copile_o.cfp[1]
  PIN copile_o.cfp[20]
    DIRECTION OUTPUT ;
    USE SIGNAL ;
    PORT
      LAYER Metal3 ;
        RECT  899.6 730.18 900 730.58 ;
    END
  END copile_o.cfp[20]
  PIN copile_o.cfp[21]
    DIRECTION OUTPUT ;
    USE SIGNAL ;
    PORT
      LAYER Metal3 ;
        RECT  899.6 732.7 900 733.1 ;
    END
  END copile_o.cfp[21]
  PIN copile_o.cfp[22]
    DIRECTION OUTPUT ;
    USE SIGNAL ;
    PORT
      LAYER Metal3 ;
        RECT  899.6 735.22 900 735.62 ;
    END
  END copile_o.cfp[22]
  PIN copile_o.cfp[23]
    DIRECTION OUTPUT ;
    USE SIGNAL ;
    PORT
      LAYER Metal3 ;
        RECT  899.6 737.74 900 738.14 ;
    END
  END copile_o.cfp[23]
  PIN copile_o.cfp[24]
    DIRECTION OUTPUT ;
    USE SIGNAL ;
    PORT
      LAYER Metal3 ;
        RECT  899.6 740.26 900 740.66 ;
    END
  END copile_o.cfp[24]
  PIN copile_o.cfp[25]
    DIRECTION OUTPUT ;
    USE SIGNAL ;
    PORT
      LAYER Metal3 ;
        RECT  899.6 742.78 900 743.18 ;
    END
  END copile_o.cfp[25]
  PIN copile_o.cfp[26]
    DIRECTION OUTPUT ;
    USE SIGNAL ;
    PORT
      LAYER Metal3 ;
        RECT  899.6 745.3 900 745.7 ;
    END
  END copile_o.cfp[26]
  PIN copile_o.cfp[27]
    DIRECTION OUTPUT ;
    USE SIGNAL ;
    PORT
      LAYER Metal3 ;
        RECT  899.6 747.82 900 748.22 ;
    END
  END copile_o.cfp[27]
  PIN copile_o.cfp[28]
    DIRECTION OUTPUT ;
    USE SIGNAL ;
    PORT
      LAYER Metal3 ;
        RECT  899.6 750.34 900 750.74 ;
    END
  END copile_o.cfp[28]
  PIN copile_o.cfp[29]
    DIRECTION OUTPUT ;
    USE SIGNAL ;
    PORT
      LAYER Metal3 ;
        RECT  899.6 752.86 900 753.26 ;
    END
  END copile_o.cfp[29]
  PIN copile_o.cfp[2]
    DIRECTION OUTPUT ;
    USE SIGNAL ;
    PORT
      LAYER Metal3 ;
        RECT  899.6 684.82 900 685.22 ;
    END
  END copile_o.cfp[2]
  PIN copile_o.cfp[30]
    DIRECTION OUTPUT ;
    USE SIGNAL ;
    PORT
      LAYER Metal3 ;
        RECT  899.6 755.38 900 755.78 ;
    END
  END copile_o.cfp[30]
  PIN copile_o.cfp[31]
    DIRECTION OUTPUT ;
    USE SIGNAL ;
    PORT
      LAYER Metal3 ;
        RECT  899.6 757.9 900 758.3 ;
    END
  END copile_o.cfp[31]
  PIN copile_o.cfp[32]
    DIRECTION OUTPUT ;
    USE SIGNAL ;
    PORT
      LAYER Metal3 ;
        RECT  899.6 760.42 900 760.82 ;
    END
  END copile_o.cfp[32]
  PIN copile_o.cfp[33]
    DIRECTION OUTPUT ;
    USE SIGNAL ;
    PORT
      LAYER Metal3 ;
        RECT  899.6 762.94 900 763.34 ;
    END
  END copile_o.cfp[33]
  PIN copile_o.cfp[34]
    DIRECTION OUTPUT ;
    USE SIGNAL ;
    PORT
      LAYER Metal3 ;
        RECT  899.6 765.46 900 765.86 ;
    END
  END copile_o.cfp[34]
  PIN copile_o.cfp[35]
    DIRECTION OUTPUT ;
    USE SIGNAL ;
    PORT
      LAYER Metal3 ;
        RECT  899.6 767.98 900 768.38 ;
    END
  END copile_o.cfp[35]
  PIN copile_o.cfp[36]
    DIRECTION OUTPUT ;
    USE SIGNAL ;
    PORT
      LAYER Metal3 ;
        RECT  899.6 770.5 900 770.9 ;
    END
  END copile_o.cfp[36]
  PIN copile_o.cfp[37]
    DIRECTION OUTPUT ;
    USE SIGNAL ;
    PORT
      LAYER Metal3 ;
        RECT  899.6 773.02 900 773.42 ;
    END
  END copile_o.cfp[37]
  PIN copile_o.cfp[38]
    DIRECTION OUTPUT ;
    USE SIGNAL ;
    PORT
      LAYER Metal3 ;
        RECT  899.6 775.54 900 775.94 ;
    END
  END copile_o.cfp[38]
  PIN copile_o.cfp[39]
    DIRECTION OUTPUT ;
    USE SIGNAL ;
    PORT
      LAYER Metal3 ;
        RECT  899.6 778.06 900 778.46 ;
    END
  END copile_o.cfp[39]
  PIN copile_o.cfp[3]
    DIRECTION OUTPUT ;
    USE SIGNAL ;
    PORT
      LAYER Metal3 ;
        RECT  899.6 687.34 900 687.74 ;
    END
  END copile_o.cfp[3]
  PIN copile_o.cfp[40]
    DIRECTION OUTPUT ;
    USE SIGNAL ;
    PORT
      LAYER Metal3 ;
        RECT  899.6 780.58 900 780.98 ;
    END
  END copile_o.cfp[40]
  PIN copile_o.cfp[41]
    DIRECTION OUTPUT ;
    USE SIGNAL ;
    PORT
      LAYER Metal3 ;
        RECT  899.6 783.1 900 783.5 ;
    END
  END copile_o.cfp[41]
  PIN copile_o.cfp[42]
    DIRECTION OUTPUT ;
    USE SIGNAL ;
    PORT
      LAYER Metal3 ;
        RECT  899.6 785.62 900 786.02 ;
    END
  END copile_o.cfp[42]
  PIN copile_o.cfp[43]
    DIRECTION OUTPUT ;
    USE SIGNAL ;
    PORT
      LAYER Metal3 ;
        RECT  899.6 788.14 900 788.54 ;
    END
  END copile_o.cfp[43]
  PIN copile_o.cfp[44]
    DIRECTION OUTPUT ;
    USE SIGNAL ;
    PORT
      LAYER Metal3 ;
        RECT  899.6 790.66 900 791.06 ;
    END
  END copile_o.cfp[44]
  PIN copile_o.cfp[45]
    DIRECTION OUTPUT ;
    USE SIGNAL ;
    PORT
      LAYER Metal3 ;
        RECT  899.6 793.18 900 793.58 ;
    END
  END copile_o.cfp[45]
  PIN copile_o.cfp[46]
    DIRECTION OUTPUT ;
    USE SIGNAL ;
    PORT
      LAYER Metal3 ;
        RECT  899.6 795.7 900 796.1 ;
    END
  END copile_o.cfp[46]
  PIN copile_o.cfp[47]
    DIRECTION OUTPUT ;
    USE SIGNAL ;
    PORT
      LAYER Metal3 ;
        RECT  899.6 798.22 900 798.62 ;
    END
  END copile_o.cfp[47]
  PIN copile_o.cfp[48]
    DIRECTION OUTPUT ;
    USE SIGNAL ;
    PORT
      LAYER Metal3 ;
        RECT  899.6 800.74 900 801.14 ;
    END
  END copile_o.cfp[48]
  PIN copile_o.cfp[49]
    DIRECTION OUTPUT ;
    USE SIGNAL ;
    PORT
      LAYER Metal3 ;
        RECT  899.6 803.26 900 803.66 ;
    END
  END copile_o.cfp[49]
  PIN copile_o.cfp[4]
    DIRECTION OUTPUT ;
    USE SIGNAL ;
    PORT
      LAYER Metal3 ;
        RECT  899.6 689.86 900 690.26 ;
    END
  END copile_o.cfp[4]
  PIN copile_o.cfp[50]
    DIRECTION OUTPUT ;
    USE SIGNAL ;
    PORT
      LAYER Metal3 ;
        RECT  899.6 805.78 900 806.18 ;
    END
  END copile_o.cfp[50]
  PIN copile_o.cfp[51]
    DIRECTION OUTPUT ;
    USE SIGNAL ;
    PORT
      LAYER Metal3 ;
        RECT  899.6 808.3 900 808.7 ;
    END
  END copile_o.cfp[51]
  PIN copile_o.cfp[52]
    DIRECTION OUTPUT ;
    USE SIGNAL ;
    PORT
      LAYER Metal3 ;
        RECT  899.6 810.82 900 811.22 ;
    END
  END copile_o.cfp[52]
  PIN copile_o.cfp[53]
    DIRECTION OUTPUT ;
    USE SIGNAL ;
    PORT
      LAYER Metal3 ;
        RECT  899.6 813.34 900 813.74 ;
    END
  END copile_o.cfp[53]
  PIN copile_o.cfp[54]
    DIRECTION OUTPUT ;
    USE SIGNAL ;
    PORT
      LAYER Metal3 ;
        RECT  899.6 815.86 900 816.26 ;
    END
  END copile_o.cfp[54]
  PIN copile_o.cfp[55]
    DIRECTION OUTPUT ;
    USE SIGNAL ;
    PORT
      LAYER Metal3 ;
        RECT  899.6 818.38 900 818.78 ;
    END
  END copile_o.cfp[55]
  PIN copile_o.cfp[56]
    DIRECTION OUTPUT ;
    USE SIGNAL ;
    PORT
      LAYER Metal3 ;
        RECT  899.6 820.9 900 821.3 ;
    END
  END copile_o.cfp[56]
  PIN copile_o.cfp[57]
    DIRECTION OUTPUT ;
    USE SIGNAL ;
    PORT
      LAYER Metal3 ;
        RECT  899.6 823.42 900 823.82 ;
    END
  END copile_o.cfp[57]
  PIN copile_o.cfp[58]
    DIRECTION OUTPUT ;
    USE SIGNAL ;
    PORT
      LAYER Metal3 ;
        RECT  899.6 825.94 900 826.34 ;
    END
  END copile_o.cfp[58]
  PIN copile_o.cfp[59]
    DIRECTION OUTPUT ;
    USE SIGNAL ;
    PORT
      LAYER Metal3 ;
        RECT  899.6 828.46 900 828.86 ;
    END
  END copile_o.cfp[59]
  PIN copile_o.cfp[5]
    DIRECTION OUTPUT ;
    USE SIGNAL ;
    PORT
      LAYER Metal3 ;
        RECT  899.6 692.38 900 692.78 ;
    END
  END copile_o.cfp[5]
  PIN copile_o.cfp[60]
    DIRECTION OUTPUT ;
    USE SIGNAL ;
    PORT
      LAYER Metal3 ;
        RECT  899.6 830.98 900 831.38 ;
    END
  END copile_o.cfp[60]
  PIN copile_o.cfp[61]
    DIRECTION OUTPUT ;
    USE SIGNAL ;
    PORT
      LAYER Metal3 ;
        RECT  899.6 833.5 900 833.9 ;
    END
  END copile_o.cfp[61]
  PIN copile_o.cfp[62]
    DIRECTION OUTPUT ;
    USE SIGNAL ;
    PORT
      LAYER Metal3 ;
        RECT  899.6 836.02 900 836.42 ;
    END
  END copile_o.cfp[62]
  PIN copile_o.cfp[63]
    DIRECTION OUTPUT ;
    USE SIGNAL ;
    PORT
      LAYER Metal3 ;
        RECT  899.6 838.54 900 838.94 ;
    END
  END copile_o.cfp[63]
  PIN copile_o.cfp[6]
    DIRECTION OUTPUT ;
    USE SIGNAL ;
    PORT
      LAYER Metal3 ;
        RECT  899.6 694.9 900 695.3 ;
    END
  END copile_o.cfp[6]
  PIN copile_o.cfp[7]
    DIRECTION OUTPUT ;
    USE SIGNAL ;
    PORT
      LAYER Metal3 ;
        RECT  899.6 697.42 900 697.82 ;
    END
  END copile_o.cfp[7]
  PIN copile_o.cfp[8]
    DIRECTION OUTPUT ;
    USE SIGNAL ;
    PORT
      LAYER Metal3 ;
        RECT  899.6 699.94 900 700.34 ;
    END
  END copile_o.cfp[8]
  PIN copile_o.cfp[9]
    DIRECTION OUTPUT ;
    USE SIGNAL ;
    PORT
      LAYER Metal3 ;
        RECT  899.6 702.46 900 702.86 ;
    END
  END copile_o.cfp[9]
  PIN copile_o.csp[0]
    DIRECTION OUTPUT ;
    USE SIGNAL ;
    PORT
      LAYER Metal3 ;
        RECT  899.6 680.62 900 681.02 ;
    END
  END copile_o.csp[0]
  PIN copile_o.csp[10]
    DIRECTION OUTPUT ;
    USE SIGNAL ;
    PORT
      LAYER Metal3 ;
        RECT  899.6 705.82 900 706.22 ;
    END
  END copile_o.csp[10]
  PIN copile_o.csp[11]
    DIRECTION OUTPUT ;
    USE SIGNAL ;
    PORT
      LAYER Metal3 ;
        RECT  899.6 708.34 900 708.74 ;
    END
  END copile_o.csp[11]
  PIN copile_o.csp[12]
    DIRECTION OUTPUT ;
    USE SIGNAL ;
    PORT
      LAYER Metal3 ;
        RECT  899.6 710.86 900 711.26 ;
    END
  END copile_o.csp[12]
  PIN copile_o.csp[13]
    DIRECTION OUTPUT ;
    USE SIGNAL ;
    PORT
      LAYER Metal3 ;
        RECT  899.6 713.38 900 713.78 ;
    END
  END copile_o.csp[13]
  PIN copile_o.csp[14]
    DIRECTION OUTPUT ;
    USE SIGNAL ;
    PORT
      LAYER Metal3 ;
        RECT  899.6 715.9 900 716.3 ;
    END
  END copile_o.csp[14]
  PIN copile_o.csp[15]
    DIRECTION OUTPUT ;
    USE SIGNAL ;
    PORT
      LAYER Metal3 ;
        RECT  899.6 718.42 900 718.82 ;
    END
  END copile_o.csp[15]
  PIN copile_o.csp[16]
    DIRECTION OUTPUT ;
    USE SIGNAL ;
    PORT
      LAYER Metal3 ;
        RECT  899.6 720.94 900 721.34 ;
    END
  END copile_o.csp[16]
  PIN copile_o.csp[17]
    DIRECTION OUTPUT ;
    USE SIGNAL ;
    PORT
      LAYER Metal3 ;
        RECT  899.6 723.46 900 723.86 ;
    END
  END copile_o.csp[17]
  PIN copile_o.csp[18]
    DIRECTION OUTPUT ;
    USE SIGNAL ;
    PORT
      LAYER Metal3 ;
        RECT  899.6 725.98 900 726.38 ;
    END
  END copile_o.csp[18]
  PIN copile_o.csp[19]
    DIRECTION OUTPUT ;
    USE SIGNAL ;
    PORT
      LAYER Metal3 ;
        RECT  899.6 728.5 900 728.9 ;
    END
  END copile_o.csp[19]
  PIN copile_o.csp[1]
    DIRECTION OUTPUT ;
    USE SIGNAL ;
    PORT
      LAYER Metal3 ;
        RECT  899.6 683.14 900 683.54 ;
    END
  END copile_o.csp[1]
  PIN copile_o.csp[20]
    DIRECTION OUTPUT ;
    USE SIGNAL ;
    PORT
      LAYER Metal3 ;
        RECT  899.6 731.02 900 731.42 ;
    END
  END copile_o.csp[20]
  PIN copile_o.csp[21]
    DIRECTION OUTPUT ;
    USE SIGNAL ;
    PORT
      LAYER Metal3 ;
        RECT  899.6 733.54 900 733.94 ;
    END
  END copile_o.csp[21]
  PIN copile_o.csp[22]
    DIRECTION OUTPUT ;
    USE SIGNAL ;
    PORT
      LAYER Metal3 ;
        RECT  899.6 736.06 900 736.46 ;
    END
  END copile_o.csp[22]
  PIN copile_o.csp[23]
    DIRECTION OUTPUT ;
    USE SIGNAL ;
    PORT
      LAYER Metal3 ;
        RECT  899.6 738.58 900 738.98 ;
    END
  END copile_o.csp[23]
  PIN copile_o.csp[24]
    DIRECTION OUTPUT ;
    USE SIGNAL ;
    PORT
      LAYER Metal3 ;
        RECT  899.6 741.1 900 741.5 ;
    END
  END copile_o.csp[24]
  PIN copile_o.csp[25]
    DIRECTION OUTPUT ;
    USE SIGNAL ;
    PORT
      LAYER Metal3 ;
        RECT  899.6 743.62 900 744.02 ;
    END
  END copile_o.csp[25]
  PIN copile_o.csp[26]
    DIRECTION OUTPUT ;
    USE SIGNAL ;
    PORT
      LAYER Metal3 ;
        RECT  899.6 746.14 900 746.54 ;
    END
  END copile_o.csp[26]
  PIN copile_o.csp[27]
    DIRECTION OUTPUT ;
    USE SIGNAL ;
    PORT
      LAYER Metal3 ;
        RECT  899.6 748.66 900 749.06 ;
    END
  END copile_o.csp[27]
  PIN copile_o.csp[28]
    DIRECTION OUTPUT ;
    USE SIGNAL ;
    PORT
      LAYER Metal3 ;
        RECT  899.6 751.18 900 751.58 ;
    END
  END copile_o.csp[28]
  PIN copile_o.csp[29]
    DIRECTION OUTPUT ;
    USE SIGNAL ;
    PORT
      LAYER Metal3 ;
        RECT  899.6 753.7 900 754.1 ;
    END
  END copile_o.csp[29]
  PIN copile_o.csp[2]
    DIRECTION OUTPUT ;
    USE SIGNAL ;
    PORT
      LAYER Metal3 ;
        RECT  899.6 685.66 900 686.06 ;
    END
  END copile_o.csp[2]
  PIN copile_o.csp[30]
    DIRECTION OUTPUT ;
    USE SIGNAL ;
    PORT
      LAYER Metal3 ;
        RECT  899.6 756.22 900 756.62 ;
    END
  END copile_o.csp[30]
  PIN copile_o.csp[31]
    DIRECTION OUTPUT ;
    USE SIGNAL ;
    PORT
      LAYER Metal3 ;
        RECT  899.6 758.74 900 759.14 ;
    END
  END copile_o.csp[31]
  PIN copile_o.csp[32]
    DIRECTION OUTPUT ;
    USE SIGNAL ;
    PORT
      LAYER Metal3 ;
        RECT  899.6 761.26 900 761.66 ;
    END
  END copile_o.csp[32]
  PIN copile_o.csp[33]
    DIRECTION OUTPUT ;
    USE SIGNAL ;
    PORT
      LAYER Metal3 ;
        RECT  899.6 763.78 900 764.18 ;
    END
  END copile_o.csp[33]
  PIN copile_o.csp[34]
    DIRECTION OUTPUT ;
    USE SIGNAL ;
    PORT
      LAYER Metal3 ;
        RECT  899.6 766.3 900 766.7 ;
    END
  END copile_o.csp[34]
  PIN copile_o.csp[35]
    DIRECTION OUTPUT ;
    USE SIGNAL ;
    PORT
      LAYER Metal3 ;
        RECT  899.6 768.82 900 769.22 ;
    END
  END copile_o.csp[35]
  PIN copile_o.csp[36]
    DIRECTION OUTPUT ;
    USE SIGNAL ;
    PORT
      LAYER Metal3 ;
        RECT  899.6 771.34 900 771.74 ;
    END
  END copile_o.csp[36]
  PIN copile_o.csp[37]
    DIRECTION OUTPUT ;
    USE SIGNAL ;
    PORT
      LAYER Metal3 ;
        RECT  899.6 773.86 900 774.26 ;
    END
  END copile_o.csp[37]
  PIN copile_o.csp[38]
    DIRECTION OUTPUT ;
    USE SIGNAL ;
    PORT
      LAYER Metal3 ;
        RECT  899.6 776.38 900 776.78 ;
    END
  END copile_o.csp[38]
  PIN copile_o.csp[39]
    DIRECTION OUTPUT ;
    USE SIGNAL ;
    PORT
      LAYER Metal3 ;
        RECT  899.6 778.9 900 779.3 ;
    END
  END copile_o.csp[39]
  PIN copile_o.csp[3]
    DIRECTION OUTPUT ;
    USE SIGNAL ;
    PORT
      LAYER Metal3 ;
        RECT  899.6 688.18 900 688.58 ;
    END
  END copile_o.csp[3]
  PIN copile_o.csp[40]
    DIRECTION OUTPUT ;
    USE SIGNAL ;
    PORT
      LAYER Metal3 ;
        RECT  899.6 781.42 900 781.82 ;
    END
  END copile_o.csp[40]
  PIN copile_o.csp[41]
    DIRECTION OUTPUT ;
    USE SIGNAL ;
    PORT
      LAYER Metal3 ;
        RECT  899.6 783.94 900 784.34 ;
    END
  END copile_o.csp[41]
  PIN copile_o.csp[42]
    DIRECTION OUTPUT ;
    USE SIGNAL ;
    PORT
      LAYER Metal3 ;
        RECT  899.6 786.46 900 786.86 ;
    END
  END copile_o.csp[42]
  PIN copile_o.csp[43]
    DIRECTION OUTPUT ;
    USE SIGNAL ;
    PORT
      LAYER Metal3 ;
        RECT  899.6 788.98 900 789.38 ;
    END
  END copile_o.csp[43]
  PIN copile_o.csp[44]
    DIRECTION OUTPUT ;
    USE SIGNAL ;
    PORT
      LAYER Metal3 ;
        RECT  899.6 791.5 900 791.9 ;
    END
  END copile_o.csp[44]
  PIN copile_o.csp[45]
    DIRECTION OUTPUT ;
    USE SIGNAL ;
    PORT
      LAYER Metal3 ;
        RECT  899.6 794.02 900 794.42 ;
    END
  END copile_o.csp[45]
  PIN copile_o.csp[46]
    DIRECTION OUTPUT ;
    USE SIGNAL ;
    PORT
      LAYER Metal3 ;
        RECT  899.6 796.54 900 796.94 ;
    END
  END copile_o.csp[46]
  PIN copile_o.csp[47]
    DIRECTION OUTPUT ;
    USE SIGNAL ;
    PORT
      LAYER Metal3 ;
        RECT  899.6 799.06 900 799.46 ;
    END
  END copile_o.csp[47]
  PIN copile_o.csp[48]
    DIRECTION OUTPUT ;
    USE SIGNAL ;
    PORT
      LAYER Metal3 ;
        RECT  899.6 801.58 900 801.98 ;
    END
  END copile_o.csp[48]
  PIN copile_o.csp[49]
    DIRECTION OUTPUT ;
    USE SIGNAL ;
    PORT
      LAYER Metal3 ;
        RECT  899.6 804.1 900 804.5 ;
    END
  END copile_o.csp[49]
  PIN copile_o.csp[4]
    DIRECTION OUTPUT ;
    USE SIGNAL ;
    PORT
      LAYER Metal3 ;
        RECT  899.6 690.7 900 691.1 ;
    END
  END copile_o.csp[4]
  PIN copile_o.csp[50]
    DIRECTION OUTPUT ;
    USE SIGNAL ;
    PORT
      LAYER Metal3 ;
        RECT  899.6 806.62 900 807.02 ;
    END
  END copile_o.csp[50]
  PIN copile_o.csp[51]
    DIRECTION OUTPUT ;
    USE SIGNAL ;
    PORT
      LAYER Metal3 ;
        RECT  899.6 809.14 900 809.54 ;
    END
  END copile_o.csp[51]
  PIN copile_o.csp[52]
    DIRECTION OUTPUT ;
    USE SIGNAL ;
    PORT
      LAYER Metal3 ;
        RECT  899.6 811.66 900 812.06 ;
    END
  END copile_o.csp[52]
  PIN copile_o.csp[53]
    DIRECTION OUTPUT ;
    USE SIGNAL ;
    PORT
      LAYER Metal3 ;
        RECT  899.6 814.18 900 814.58 ;
    END
  END copile_o.csp[53]
  PIN copile_o.csp[54]
    DIRECTION OUTPUT ;
    USE SIGNAL ;
    PORT
      LAYER Metal3 ;
        RECT  899.6 816.7 900 817.1 ;
    END
  END copile_o.csp[54]
  PIN copile_o.csp[55]
    DIRECTION OUTPUT ;
    USE SIGNAL ;
    PORT
      LAYER Metal3 ;
        RECT  899.6 819.22 900 819.62 ;
    END
  END copile_o.csp[55]
  PIN copile_o.csp[56]
    DIRECTION OUTPUT ;
    USE SIGNAL ;
    PORT
      LAYER Metal3 ;
        RECT  899.6 821.74 900 822.14 ;
    END
  END copile_o.csp[56]
  PIN copile_o.csp[57]
    DIRECTION OUTPUT ;
    USE SIGNAL ;
    PORT
      LAYER Metal3 ;
        RECT  899.6 824.26 900 824.66 ;
    END
  END copile_o.csp[57]
  PIN copile_o.csp[58]
    DIRECTION OUTPUT ;
    USE SIGNAL ;
    PORT
      LAYER Metal3 ;
        RECT  899.6 826.78 900 827.18 ;
    END
  END copile_o.csp[58]
  PIN copile_o.csp[59]
    DIRECTION OUTPUT ;
    USE SIGNAL ;
    PORT
      LAYER Metal3 ;
        RECT  899.6 829.3 900 829.7 ;
    END
  END copile_o.csp[59]
  PIN copile_o.csp[5]
    DIRECTION OUTPUT ;
    USE SIGNAL ;
    PORT
      LAYER Metal3 ;
        RECT  899.6 693.22 900 693.62 ;
    END
  END copile_o.csp[5]
  PIN copile_o.csp[60]
    DIRECTION OUTPUT ;
    USE SIGNAL ;
    PORT
      LAYER Metal3 ;
        RECT  899.6 831.82 900 832.22 ;
    END
  END copile_o.csp[60]
  PIN copile_o.csp[61]
    DIRECTION OUTPUT ;
    USE SIGNAL ;
    PORT
      LAYER Metal3 ;
        RECT  899.6 834.34 900 834.74 ;
    END
  END copile_o.csp[61]
  PIN copile_o.csp[62]
    DIRECTION OUTPUT ;
    USE SIGNAL ;
    PORT
      LAYER Metal3 ;
        RECT  899.6 836.86 900 837.26 ;
    END
  END copile_o.csp[62]
  PIN copile_o.csp[63]
    DIRECTION OUTPUT ;
    USE SIGNAL ;
    PORT
      LAYER Metal3 ;
        RECT  899.6 839.38 900 839.78 ;
    END
  END copile_o.csp[63]
  PIN copile_o.csp[6]
    DIRECTION OUTPUT ;
    USE SIGNAL ;
    PORT
      LAYER Metal3 ;
        RECT  899.6 695.74 900 696.14 ;
    END
  END copile_o.csp[6]
  PIN copile_o.csp[7]
    DIRECTION OUTPUT ;
    USE SIGNAL ;
    PORT
      LAYER Metal3 ;
        RECT  899.6 698.26 900 698.66 ;
    END
  END copile_o.csp[7]
  PIN copile_o.csp[8]
    DIRECTION OUTPUT ;
    USE SIGNAL ;
    PORT
      LAYER Metal3 ;
        RECT  899.6 700.78 900 701.18 ;
    END
  END copile_o.csp[8]
  PIN copile_o.csp[9]
    DIRECTION OUTPUT ;
    USE SIGNAL ;
    PORT
      LAYER Metal3 ;
        RECT  899.6 703.3 900 703.7 ;
    END
  END copile_o.csp[9]
  PIN copile_o.hp[0]
    DIRECTION OUTPUT ;
    USE SIGNAL ;
    PORT
      LAYER Metal3 ;
        RECT  899.6 681.46 900 681.86 ;
    END
  END copile_o.hp[0]
  PIN copile_o.hp[10]
    DIRECTION OUTPUT ;
    USE SIGNAL ;
    PORT
      LAYER Metal3 ;
        RECT  899.6 706.66 900 707.06 ;
    END
  END copile_o.hp[10]
  PIN copile_o.hp[11]
    DIRECTION OUTPUT ;
    USE SIGNAL ;
    PORT
      LAYER Metal3 ;
        RECT  899.6 709.18 900 709.58 ;
    END
  END copile_o.hp[11]
  PIN copile_o.hp[12]
    DIRECTION OUTPUT ;
    USE SIGNAL ;
    PORT
      LAYER Metal3 ;
        RECT  899.6 711.7 900 712.1 ;
    END
  END copile_o.hp[12]
  PIN copile_o.hp[13]
    DIRECTION OUTPUT ;
    USE SIGNAL ;
    PORT
      LAYER Metal3 ;
        RECT  899.6 714.22 900 714.62 ;
    END
  END copile_o.hp[13]
  PIN copile_o.hp[14]
    DIRECTION OUTPUT ;
    USE SIGNAL ;
    PORT
      LAYER Metal3 ;
        RECT  899.6 716.74 900 717.14 ;
    END
  END copile_o.hp[14]
  PIN copile_o.hp[15]
    DIRECTION OUTPUT ;
    USE SIGNAL ;
    PORT
      LAYER Metal3 ;
        RECT  899.6 719.26 900 719.66 ;
    END
  END copile_o.hp[15]
  PIN copile_o.hp[16]
    DIRECTION OUTPUT ;
    USE SIGNAL ;
    PORT
      LAYER Metal3 ;
        RECT  899.6 721.78 900 722.18 ;
    END
  END copile_o.hp[16]
  PIN copile_o.hp[17]
    DIRECTION OUTPUT ;
    USE SIGNAL ;
    PORT
      LAYER Metal3 ;
        RECT  899.6 724.3 900 724.7 ;
    END
  END copile_o.hp[17]
  PIN copile_o.hp[18]
    DIRECTION OUTPUT ;
    USE SIGNAL ;
    PORT
      LAYER Metal3 ;
        RECT  899.6 726.82 900 727.22 ;
    END
  END copile_o.hp[18]
  PIN copile_o.hp[19]
    DIRECTION OUTPUT ;
    USE SIGNAL ;
    PORT
      LAYER Metal3 ;
        RECT  899.6 729.34 900 729.74 ;
    END
  END copile_o.hp[19]
  PIN copile_o.hp[1]
    DIRECTION OUTPUT ;
    USE SIGNAL ;
    PORT
      LAYER Metal3 ;
        RECT  899.6 683.98 900 684.38 ;
    END
  END copile_o.hp[1]
  PIN copile_o.hp[20]
    DIRECTION OUTPUT ;
    USE SIGNAL ;
    PORT
      LAYER Metal3 ;
        RECT  899.6 731.86 900 732.26 ;
    END
  END copile_o.hp[20]
  PIN copile_o.hp[21]
    DIRECTION OUTPUT ;
    USE SIGNAL ;
    PORT
      LAYER Metal3 ;
        RECT  899.6 734.38 900 734.78 ;
    END
  END copile_o.hp[21]
  PIN copile_o.hp[22]
    DIRECTION OUTPUT ;
    USE SIGNAL ;
    PORT
      LAYER Metal3 ;
        RECT  899.6 736.9 900 737.3 ;
    END
  END copile_o.hp[22]
  PIN copile_o.hp[23]
    DIRECTION OUTPUT ;
    USE SIGNAL ;
    PORT
      LAYER Metal3 ;
        RECT  899.6 739.42 900 739.82 ;
    END
  END copile_o.hp[23]
  PIN copile_o.hp[24]
    DIRECTION OUTPUT ;
    USE SIGNAL ;
    PORT
      LAYER Metal3 ;
        RECT  899.6 741.94 900 742.34 ;
    END
  END copile_o.hp[24]
  PIN copile_o.hp[25]
    DIRECTION OUTPUT ;
    USE SIGNAL ;
    PORT
      LAYER Metal3 ;
        RECT  899.6 744.46 900 744.86 ;
    END
  END copile_o.hp[25]
  PIN copile_o.hp[26]
    DIRECTION OUTPUT ;
    USE SIGNAL ;
    PORT
      LAYER Metal3 ;
        RECT  899.6 746.98 900 747.38 ;
    END
  END copile_o.hp[26]
  PIN copile_o.hp[27]
    DIRECTION OUTPUT ;
    USE SIGNAL ;
    PORT
      LAYER Metal3 ;
        RECT  899.6 749.5 900 749.9 ;
    END
  END copile_o.hp[27]
  PIN copile_o.hp[28]
    DIRECTION OUTPUT ;
    USE SIGNAL ;
    PORT
      LAYER Metal3 ;
        RECT  899.6 752.02 900 752.42 ;
    END
  END copile_o.hp[28]
  PIN copile_o.hp[29]
    DIRECTION OUTPUT ;
    USE SIGNAL ;
    PORT
      LAYER Metal3 ;
        RECT  899.6 754.54 900 754.94 ;
    END
  END copile_o.hp[29]
  PIN copile_o.hp[2]
    DIRECTION OUTPUT ;
    USE SIGNAL ;
    PORT
      LAYER Metal3 ;
        RECT  899.6 686.5 900 686.9 ;
    END
  END copile_o.hp[2]
  PIN copile_o.hp[30]
    DIRECTION OUTPUT ;
    USE SIGNAL ;
    PORT
      LAYER Metal3 ;
        RECT  899.6 757.06 900 757.46 ;
    END
  END copile_o.hp[30]
  PIN copile_o.hp[31]
    DIRECTION OUTPUT ;
    USE SIGNAL ;
    PORT
      LAYER Metal3 ;
        RECT  899.6 759.58 900 759.98 ;
    END
  END copile_o.hp[31]
  PIN copile_o.hp[32]
    DIRECTION OUTPUT ;
    USE SIGNAL ;
    PORT
      LAYER Metal3 ;
        RECT  899.6 762.1 900 762.5 ;
    END
  END copile_o.hp[32]
  PIN copile_o.hp[33]
    DIRECTION OUTPUT ;
    USE SIGNAL ;
    PORT
      LAYER Metal3 ;
        RECT  899.6 764.62 900 765.02 ;
    END
  END copile_o.hp[33]
  PIN copile_o.hp[34]
    DIRECTION OUTPUT ;
    USE SIGNAL ;
    PORT
      LAYER Metal3 ;
        RECT  899.6 767.14 900 767.54 ;
    END
  END copile_o.hp[34]
  PIN copile_o.hp[35]
    DIRECTION OUTPUT ;
    USE SIGNAL ;
    PORT
      LAYER Metal3 ;
        RECT  899.6 769.66 900 770.06 ;
    END
  END copile_o.hp[35]
  PIN copile_o.hp[36]
    DIRECTION OUTPUT ;
    USE SIGNAL ;
    PORT
      LAYER Metal3 ;
        RECT  899.6 772.18 900 772.58 ;
    END
  END copile_o.hp[36]
  PIN copile_o.hp[37]
    DIRECTION OUTPUT ;
    USE SIGNAL ;
    PORT
      LAYER Metal3 ;
        RECT  899.6 774.7 900 775.1 ;
    END
  END copile_o.hp[37]
  PIN copile_o.hp[38]
    DIRECTION OUTPUT ;
    USE SIGNAL ;
    PORT
      LAYER Metal3 ;
        RECT  899.6 777.22 900 777.62 ;
    END
  END copile_o.hp[38]
  PIN copile_o.hp[39]
    DIRECTION OUTPUT ;
    USE SIGNAL ;
    PORT
      LAYER Metal3 ;
        RECT  899.6 779.74 900 780.14 ;
    END
  END copile_o.hp[39]
  PIN copile_o.hp[3]
    DIRECTION OUTPUT ;
    USE SIGNAL ;
    PORT
      LAYER Metal3 ;
        RECT  899.6 689.02 900 689.42 ;
    END
  END copile_o.hp[3]
  PIN copile_o.hp[40]
    DIRECTION OUTPUT ;
    USE SIGNAL ;
    PORT
      LAYER Metal3 ;
        RECT  899.6 782.26 900 782.66 ;
    END
  END copile_o.hp[40]
  PIN copile_o.hp[41]
    DIRECTION OUTPUT ;
    USE SIGNAL ;
    PORT
      LAYER Metal3 ;
        RECT  899.6 784.78 900 785.18 ;
    END
  END copile_o.hp[41]
  PIN copile_o.hp[42]
    DIRECTION OUTPUT ;
    USE SIGNAL ;
    PORT
      LAYER Metal3 ;
        RECT  899.6 787.3 900 787.7 ;
    END
  END copile_o.hp[42]
  PIN copile_o.hp[43]
    DIRECTION OUTPUT ;
    USE SIGNAL ;
    PORT
      LAYER Metal3 ;
        RECT  899.6 789.82 900 790.22 ;
    END
  END copile_o.hp[43]
  PIN copile_o.hp[44]
    DIRECTION OUTPUT ;
    USE SIGNAL ;
    PORT
      LAYER Metal3 ;
        RECT  899.6 792.34 900 792.74 ;
    END
  END copile_o.hp[44]
  PIN copile_o.hp[45]
    DIRECTION OUTPUT ;
    USE SIGNAL ;
    PORT
      LAYER Metal3 ;
        RECT  899.6 794.86 900 795.26 ;
    END
  END copile_o.hp[45]
  PIN copile_o.hp[46]
    DIRECTION OUTPUT ;
    USE SIGNAL ;
    PORT
      LAYER Metal3 ;
        RECT  899.6 797.38 900 797.78 ;
    END
  END copile_o.hp[46]
  PIN copile_o.hp[47]
    DIRECTION OUTPUT ;
    USE SIGNAL ;
    PORT
      LAYER Metal3 ;
        RECT  899.6 799.9 900 800.3 ;
    END
  END copile_o.hp[47]
  PIN copile_o.hp[48]
    DIRECTION OUTPUT ;
    USE SIGNAL ;
    PORT
      LAYER Metal3 ;
        RECT  899.6 802.42 900 802.82 ;
    END
  END copile_o.hp[48]
  PIN copile_o.hp[49]
    DIRECTION OUTPUT ;
    USE SIGNAL ;
    PORT
      LAYER Metal3 ;
        RECT  899.6 804.94 900 805.34 ;
    END
  END copile_o.hp[49]
  PIN copile_o.hp[4]
    DIRECTION OUTPUT ;
    USE SIGNAL ;
    PORT
      LAYER Metal3 ;
        RECT  899.6 691.54 900 691.94 ;
    END
  END copile_o.hp[4]
  PIN copile_o.hp[50]
    DIRECTION OUTPUT ;
    USE SIGNAL ;
    PORT
      LAYER Metal3 ;
        RECT  899.6 807.46 900 807.86 ;
    END
  END copile_o.hp[50]
  PIN copile_o.hp[51]
    DIRECTION OUTPUT ;
    USE SIGNAL ;
    PORT
      LAYER Metal3 ;
        RECT  899.6 809.98 900 810.38 ;
    END
  END copile_o.hp[51]
  PIN copile_o.hp[52]
    DIRECTION OUTPUT ;
    USE SIGNAL ;
    PORT
      LAYER Metal3 ;
        RECT  899.6 812.5 900 812.9 ;
    END
  END copile_o.hp[52]
  PIN copile_o.hp[53]
    DIRECTION OUTPUT ;
    USE SIGNAL ;
    PORT
      LAYER Metal3 ;
        RECT  899.6 815.02 900 815.42 ;
    END
  END copile_o.hp[53]
  PIN copile_o.hp[54]
    DIRECTION OUTPUT ;
    USE SIGNAL ;
    PORT
      LAYER Metal3 ;
        RECT  899.6 817.54 900 817.94 ;
    END
  END copile_o.hp[54]
  PIN copile_o.hp[55]
    DIRECTION OUTPUT ;
    USE SIGNAL ;
    PORT
      LAYER Metal3 ;
        RECT  899.6 820.06 900 820.46 ;
    END
  END copile_o.hp[55]
  PIN copile_o.hp[56]
    DIRECTION OUTPUT ;
    USE SIGNAL ;
    PORT
      LAYER Metal3 ;
        RECT  899.6 822.58 900 822.98 ;
    END
  END copile_o.hp[56]
  PIN copile_o.hp[57]
    DIRECTION OUTPUT ;
    USE SIGNAL ;
    PORT
      LAYER Metal3 ;
        RECT  899.6 825.1 900 825.5 ;
    END
  END copile_o.hp[57]
  PIN copile_o.hp[58]
    DIRECTION OUTPUT ;
    USE SIGNAL ;
    PORT
      LAYER Metal3 ;
        RECT  899.6 827.62 900 828.02 ;
    END
  END copile_o.hp[58]
  PIN copile_o.hp[59]
    DIRECTION OUTPUT ;
    USE SIGNAL ;
    PORT
      LAYER Metal3 ;
        RECT  899.6 830.14 900 830.54 ;
    END
  END copile_o.hp[59]
  PIN copile_o.hp[5]
    DIRECTION OUTPUT ;
    USE SIGNAL ;
    PORT
      LAYER Metal3 ;
        RECT  899.6 694.06 900 694.46 ;
    END
  END copile_o.hp[5]
  PIN copile_o.hp[60]
    DIRECTION OUTPUT ;
    USE SIGNAL ;
    PORT
      LAYER Metal3 ;
        RECT  899.6 832.66 900 833.06 ;
    END
  END copile_o.hp[60]
  PIN copile_o.hp[61]
    DIRECTION OUTPUT ;
    USE SIGNAL ;
    PORT
      LAYER Metal3 ;
        RECT  899.6 835.18 900 835.58 ;
    END
  END copile_o.hp[61]
  PIN copile_o.hp[62]
    DIRECTION OUTPUT ;
    USE SIGNAL ;
    PORT
      LAYER Metal3 ;
        RECT  899.6 837.7 900 838.1 ;
    END
  END copile_o.hp[62]
  PIN copile_o.hp[63]
    DIRECTION OUTPUT ;
    USE SIGNAL ;
    PORT
      LAYER Metal3 ;
        RECT  899.6 840.22 900 840.62 ;
    END
  END copile_o.hp[63]
  PIN copile_o.hp[6]
    DIRECTION OUTPUT ;
    USE SIGNAL ;
    PORT
      LAYER Metal3 ;
        RECT  899.6 696.58 900 696.98 ;
    END
  END copile_o.hp[6]
  PIN copile_o.hp[7]
    DIRECTION OUTPUT ;
    USE SIGNAL ;
    PORT
      LAYER Metal3 ;
        RECT  899.6 699.1 900 699.5 ;
    END
  END copile_o.hp[7]
  PIN copile_o.hp[8]
    DIRECTION OUTPUT ;
    USE SIGNAL ;
    PORT
      LAYER Metal3 ;
        RECT  899.6 701.62 900 702.02 ;
    END
  END copile_o.hp[8]
  PIN copile_o.hp[9]
    DIRECTION OUTPUT ;
    USE SIGNAL ;
    PORT
      LAYER Metal3 ;
        RECT  899.6 704.14 900 704.54 ;
    END
  END copile_o.hp[9]
  PIN copile_o.hp_valid
    DIRECTION OUTPUT ;
    USE SIGNAL ;
    PORT
      LAYER Metal3 ;
        RECT  899.6 678.94 900 679.34 ;
    END
  END copile_o.hp_valid
  PIN disp_i[0]
    DIRECTION INPUT ;
    USE SIGNAL ;
    PORT
      LAYER Metal2 ;
        RECT  668.44 999.6 668.84 1000 ;
    END
  END disp_i[0]
  PIN disp_i[10]
    DIRECTION INPUT ;
    USE SIGNAL ;
    PORT
      LAYER Metal2 ;
        RECT  678.04 999.6 678.44 1000 ;
    END
  END disp_i[10]
  PIN disp_i[11]
    DIRECTION INPUT ;
    USE SIGNAL ;
    PORT
      LAYER Metal2 ;
        RECT  679 999.6 679.4 1000 ;
    END
  END disp_i[11]
  PIN disp_i[12]
    DIRECTION INPUT ;
    USE SIGNAL ;
    PORT
      LAYER Metal2 ;
        RECT  679.96 999.6 680.36 1000 ;
    END
  END disp_i[12]
  PIN disp_i[13]
    DIRECTION INPUT ;
    USE SIGNAL ;
    PORT
      LAYER Metal2 ;
        RECT  680.92 999.6 681.32 1000 ;
    END
  END disp_i[13]
  PIN disp_i[14]
    DIRECTION INPUT ;
    USE SIGNAL ;
    PORT
      LAYER Metal2 ;
        RECT  681.88 999.6 682.28 1000 ;
    END
  END disp_i[14]
  PIN disp_i[15]
    DIRECTION INPUT ;
    USE SIGNAL ;
    PORT
      LAYER Metal2 ;
        RECT  682.84 999.6 683.24 1000 ;
    END
  END disp_i[15]
  PIN disp_i[16]
    DIRECTION INPUT ;
    USE SIGNAL ;
    PORT
      LAYER Metal2 ;
        RECT  683.8 999.6 684.2 1000 ;
    END
  END disp_i[16]
  PIN disp_i[17]
    DIRECTION INPUT ;
    USE SIGNAL ;
    PORT
      LAYER Metal2 ;
        RECT  684.76 999.6 685.16 1000 ;
    END
  END disp_i[17]
  PIN disp_i[18]
    DIRECTION INPUT ;
    USE SIGNAL ;
    PORT
      LAYER Metal2 ;
        RECT  685.72 999.6 686.12 1000 ;
    END
  END disp_i[18]
  PIN disp_i[19]
    DIRECTION INPUT ;
    USE SIGNAL ;
    PORT
      LAYER Metal2 ;
        RECT  686.68 999.6 687.08 1000 ;
    END
  END disp_i[19]
  PIN disp_i[1]
    DIRECTION INPUT ;
    USE SIGNAL ;
    PORT
      LAYER Metal2 ;
        RECT  669.4 999.6 669.8 1000 ;
    END
  END disp_i[1]
  PIN disp_i[20]
    DIRECTION INPUT ;
    USE SIGNAL ;
    PORT
      LAYER Metal2 ;
        RECT  687.64 999.6 688.04 1000 ;
    END
  END disp_i[20]
  PIN disp_i[21]
    DIRECTION INPUT ;
    USE SIGNAL ;
    PORT
      LAYER Metal2 ;
        RECT  688.6 999.6 689 1000 ;
    END
  END disp_i[21]
  PIN disp_i[22]
    DIRECTION INPUT ;
    USE SIGNAL ;
    PORT
      LAYER Metal2 ;
        RECT  689.56 999.6 689.96 1000 ;
    END
  END disp_i[22]
  PIN disp_i[23]
    DIRECTION INPUT ;
    USE SIGNAL ;
    PORT
      LAYER Metal2 ;
        RECT  690.52 999.6 690.92 1000 ;
    END
  END disp_i[23]
  PIN disp_i[24]
    DIRECTION INPUT ;
    USE SIGNAL ;
    PORT
      LAYER Metal2 ;
        RECT  691.48 999.6 691.88 1000 ;
    END
  END disp_i[24]
  PIN disp_i[25]
    DIRECTION INPUT ;
    USE SIGNAL ;
    PORT
      LAYER Metal2 ;
        RECT  692.44 999.6 692.84 1000 ;
    END
  END disp_i[25]
  PIN disp_i[26]
    DIRECTION INPUT ;
    USE SIGNAL ;
    PORT
      LAYER Metal2 ;
        RECT  693.4 999.6 693.8 1000 ;
    END
  END disp_i[26]
  PIN disp_i[27]
    DIRECTION INPUT ;
    USE SIGNAL ;
    PORT
      LAYER Metal2 ;
        RECT  694.36 999.6 694.76 1000 ;
    END
  END disp_i[27]
  PIN disp_i[28]
    DIRECTION INPUT ;
    USE SIGNAL ;
    PORT
      LAYER Metal2 ;
        RECT  695.32 999.6 695.72 1000 ;
    END
  END disp_i[28]
  PIN disp_i[29]
    DIRECTION INPUT ;
    USE SIGNAL ;
    PORT
      LAYER Metal2 ;
        RECT  696.28 999.6 696.68 1000 ;
    END
  END disp_i[29]
  PIN disp_i[2]
    DIRECTION INPUT ;
    USE SIGNAL ;
    PORT
      LAYER Metal2 ;
        RECT  670.36 999.6 670.76 1000 ;
    END
  END disp_i[2]
  PIN disp_i[30]
    DIRECTION INPUT ;
    USE SIGNAL ;
    PORT
      LAYER Metal2 ;
        RECT  697.24 999.6 697.64 1000 ;
    END
  END disp_i[30]
  PIN disp_i[31]
    DIRECTION INPUT ;
    USE SIGNAL ;
    PORT
      LAYER Metal2 ;
        RECT  698.2 999.6 698.6 1000 ;
    END
  END disp_i[31]
  PIN disp_i[3]
    DIRECTION INPUT ;
    USE SIGNAL ;
    PORT
      LAYER Metal2 ;
        RECT  671.32 999.6 671.72 1000 ;
    END
  END disp_i[3]
  PIN disp_i[4]
    DIRECTION INPUT ;
    USE SIGNAL ;
    PORT
      LAYER Metal2 ;
        RECT  672.28 999.6 672.68 1000 ;
    END
  END disp_i[4]
  PIN disp_i[5]
    DIRECTION INPUT ;
    USE SIGNAL ;
    PORT
      LAYER Metal2 ;
        RECT  673.24 999.6 673.64 1000 ;
    END
  END disp_i[5]
  PIN disp_i[6]
    DIRECTION INPUT ;
    USE SIGNAL ;
    PORT
      LAYER Metal2 ;
        RECT  674.2 999.6 674.6 1000 ;
    END
  END disp_i[6]
  PIN disp_i[7]
    DIRECTION INPUT ;
    USE SIGNAL ;
    PORT
      LAYER Metal2 ;
        RECT  675.16 999.6 675.56 1000 ;
    END
  END disp_i[7]
  PIN disp_i[8]
    DIRECTION INPUT ;
    USE SIGNAL ;
    PORT
      LAYER Metal2 ;
        RECT  676.12 999.6 676.52 1000 ;
    END
  END disp_i[8]
  PIN disp_i[9]
    DIRECTION INPUT ;
    USE SIGNAL ;
    PORT
      LAYER Metal2 ;
        RECT  677.08 999.6 677.48 1000 ;
    END
  END disp_i[9]
  PIN disp_sel_o[0]
    DIRECTION OUTPUT ;
    USE SIGNAL ;
    PORT
      LAYER Metal2 ;
        RECT  664.6 999.6 665 1000 ;
    END
  END disp_sel_o[0]
  PIN disp_sel_o[1]
    DIRECTION OUTPUT ;
    USE SIGNAL ;
    PORT
      LAYER Metal2 ;
        RECT  665.56 999.6 665.96 1000 ;
    END
  END disp_sel_o[1]
  PIN disp_sel_o[2]
    DIRECTION OUTPUT ;
    USE SIGNAL ;
    PORT
      LAYER Metal2 ;
        RECT  666.52 999.6 666.92 1000 ;
    END
  END disp_sel_o[2]
  PIN disp_sel_o[3]
    DIRECTION OUTPUT ;
    USE SIGNAL ;
    PORT
      LAYER Metal2 ;
        RECT  667.48 999.6 667.88 1000 ;
    END
  END disp_sel_o[3]
  PIN frame_dsp_i[0]
    DIRECTION INPUT ;
    USE SIGNAL ;
    PORT
      LAYER Metal2 ;
        RECT  603.16 999.6 603.56 1000 ;
    END
  END frame_dsp_i[0]
  PIN frame_dsp_i[10]
    DIRECTION INPUT ;
    USE SIGNAL ;
    PORT
      LAYER Metal2 ;
        RECT  612.76 999.6 613.16 1000 ;
    END
  END frame_dsp_i[10]
  PIN frame_dsp_i[11]
    DIRECTION INPUT ;
    USE SIGNAL ;
    PORT
      LAYER Metal2 ;
        RECT  613.72 999.6 614.12 1000 ;
    END
  END frame_dsp_i[11]
  PIN frame_dsp_i[12]
    DIRECTION INPUT ;
    USE SIGNAL ;
    PORT
      LAYER Metal2 ;
        RECT  614.68 999.6 615.08 1000 ;
    END
  END frame_dsp_i[12]
  PIN frame_dsp_i[13]
    DIRECTION INPUT ;
    USE SIGNAL ;
    PORT
      LAYER Metal2 ;
        RECT  615.64 999.6 616.04 1000 ;
    END
  END frame_dsp_i[13]
  PIN frame_dsp_i[14]
    DIRECTION INPUT ;
    USE SIGNAL ;
    PORT
      LAYER Metal2 ;
        RECT  616.6 999.6 617 1000 ;
    END
  END frame_dsp_i[14]
  PIN frame_dsp_i[15]
    DIRECTION INPUT ;
    USE SIGNAL ;
    PORT
      LAYER Metal2 ;
        RECT  617.56 999.6 617.96 1000 ;
    END
  END frame_dsp_i[15]
  PIN frame_dsp_i[16]
    DIRECTION INPUT ;
    USE SIGNAL ;
    PORT
      LAYER Metal2 ;
        RECT  618.52 999.6 618.92 1000 ;
    END
  END frame_dsp_i[16]
  PIN frame_dsp_i[17]
    DIRECTION INPUT ;
    USE SIGNAL ;
    PORT
      LAYER Metal2 ;
        RECT  619.48 999.6 619.88 1000 ;
    END
  END frame_dsp_i[17]
  PIN frame_dsp_i[18]
    DIRECTION INPUT ;
    USE SIGNAL ;
    PORT
      LAYER Metal2 ;
        RECT  620.44 999.6 620.84 1000 ;
    END
  END frame_dsp_i[18]
  PIN frame_dsp_i[19]
    DIRECTION INPUT ;
    USE SIGNAL ;
    PORT
      LAYER Metal2 ;
        RECT  621.4 999.6 621.8 1000 ;
    END
  END frame_dsp_i[19]
  PIN frame_dsp_i[1]
    DIRECTION INPUT ;
    USE SIGNAL ;
    PORT
      LAYER Metal2 ;
        RECT  604.12 999.6 604.52 1000 ;
    END
  END frame_dsp_i[1]
  PIN frame_dsp_i[20]
    DIRECTION INPUT ;
    USE SIGNAL ;
    PORT
      LAYER Metal2 ;
        RECT  622.36 999.6 622.76 1000 ;
    END
  END frame_dsp_i[20]
  PIN frame_dsp_i[21]
    DIRECTION INPUT ;
    USE SIGNAL ;
    PORT
      LAYER Metal2 ;
        RECT  623.32 999.6 623.72 1000 ;
    END
  END frame_dsp_i[21]
  PIN frame_dsp_i[22]
    DIRECTION INPUT ;
    USE SIGNAL ;
    PORT
      LAYER Metal2 ;
        RECT  624.28 999.6 624.68 1000 ;
    END
  END frame_dsp_i[22]
  PIN frame_dsp_i[23]
    DIRECTION INPUT ;
    USE SIGNAL ;
    PORT
      LAYER Metal2 ;
        RECT  625.24 999.6 625.64 1000 ;
    END
  END frame_dsp_i[23]
  PIN frame_dsp_i[24]
    DIRECTION INPUT ;
    USE SIGNAL ;
    PORT
      LAYER Metal2 ;
        RECT  626.2 999.6 626.6 1000 ;
    END
  END frame_dsp_i[24]
  PIN frame_dsp_i[25]
    DIRECTION INPUT ;
    USE SIGNAL ;
    PORT
      LAYER Metal2 ;
        RECT  627.16 999.6 627.56 1000 ;
    END
  END frame_dsp_i[25]
  PIN frame_dsp_i[26]
    DIRECTION INPUT ;
    USE SIGNAL ;
    PORT
      LAYER Metal2 ;
        RECT  628.12 999.6 628.52 1000 ;
    END
  END frame_dsp_i[26]
  PIN frame_dsp_i[27]
    DIRECTION INPUT ;
    USE SIGNAL ;
    PORT
      LAYER Metal2 ;
        RECT  629.08 999.6 629.48 1000 ;
    END
  END frame_dsp_i[27]
  PIN frame_dsp_i[28]
    DIRECTION INPUT ;
    USE SIGNAL ;
    PORT
      LAYER Metal2 ;
        RECT  630.04 999.6 630.44 1000 ;
    END
  END frame_dsp_i[28]
  PIN frame_dsp_i[29]
    DIRECTION INPUT ;
    USE SIGNAL ;
    PORT
      LAYER Metal2 ;
        RECT  631 999.6 631.4 1000 ;
    END
  END frame_dsp_i[29]
  PIN frame_dsp_i[2]
    DIRECTION INPUT ;
    USE SIGNAL ;
    PORT
      LAYER Metal2 ;
        RECT  605.08 999.6 605.48 1000 ;
    END
  END frame_dsp_i[2]
  PIN frame_dsp_i[30]
    DIRECTION INPUT ;
    USE SIGNAL ;
    PORT
      LAYER Metal2 ;
        RECT  631.96 999.6 632.36 1000 ;
    END
  END frame_dsp_i[30]
  PIN frame_dsp_i[31]
    DIRECTION INPUT ;
    USE SIGNAL ;
    PORT
      LAYER Metal2 ;
        RECT  632.92 999.6 633.32 1000 ;
    END
  END frame_dsp_i[31]
  PIN frame_dsp_i[3]
    DIRECTION INPUT ;
    USE SIGNAL ;
    PORT
      LAYER Metal2 ;
        RECT  606.04 999.6 606.44 1000 ;
    END
  END frame_dsp_i[3]
  PIN frame_dsp_i[4]
    DIRECTION INPUT ;
    USE SIGNAL ;
    PORT
      LAYER Metal2 ;
        RECT  607 999.6 607.4 1000 ;
    END
  END frame_dsp_i[4]
  PIN frame_dsp_i[5]
    DIRECTION INPUT ;
    USE SIGNAL ;
    PORT
      LAYER Metal2 ;
        RECT  607.96 999.6 608.36 1000 ;
    END
  END frame_dsp_i[5]
  PIN frame_dsp_i[6]
    DIRECTION INPUT ;
    USE SIGNAL ;
    PORT
      LAYER Metal2 ;
        RECT  608.92 999.6 609.32 1000 ;
    END
  END frame_dsp_i[6]
  PIN frame_dsp_i[7]
    DIRECTION INPUT ;
    USE SIGNAL ;
    PORT
      LAYER Metal2 ;
        RECT  609.88 999.6 610.28 1000 ;
    END
  END frame_dsp_i[7]
  PIN frame_dsp_i[8]
    DIRECTION INPUT ;
    USE SIGNAL ;
    PORT
      LAYER Metal2 ;
        RECT  610.84 999.6 611.24 1000 ;
    END
  END frame_dsp_i[8]
  PIN frame_dsp_i[9]
    DIRECTION INPUT ;
    USE SIGNAL ;
    PORT
      LAYER Metal2 ;
        RECT  611.8 999.6 612.2 1000 ;
    END
  END frame_dsp_i[9]
  PIN frame_rsp_i[0]
    DIRECTION INPUT ;
    USE SIGNAL ;
    PORT
      LAYER Metal2 ;
        RECT  633.88 999.6 634.28 1000 ;
    END
  END frame_rsp_i[0]
  PIN frame_rsp_i[10]
    DIRECTION INPUT ;
    USE SIGNAL ;
    PORT
      LAYER Metal2 ;
        RECT  643.48 999.6 643.88 1000 ;
    END
  END frame_rsp_i[10]
  PIN frame_rsp_i[11]
    DIRECTION INPUT ;
    USE SIGNAL ;
    PORT
      LAYER Metal2 ;
        RECT  644.44 999.6 644.84 1000 ;
    END
  END frame_rsp_i[11]
  PIN frame_rsp_i[12]
    DIRECTION INPUT ;
    USE SIGNAL ;
    PORT
      LAYER Metal2 ;
        RECT  645.4 999.6 645.8 1000 ;
    END
  END frame_rsp_i[12]
  PIN frame_rsp_i[13]
    DIRECTION INPUT ;
    USE SIGNAL ;
    PORT
      LAYER Metal2 ;
        RECT  646.36 999.6 646.76 1000 ;
    END
  END frame_rsp_i[13]
  PIN frame_rsp_i[14]
    DIRECTION INPUT ;
    USE SIGNAL ;
    PORT
      LAYER Metal2 ;
        RECT  647.32 999.6 647.72 1000 ;
    END
  END frame_rsp_i[14]
  PIN frame_rsp_i[15]
    DIRECTION INPUT ;
    USE SIGNAL ;
    PORT
      LAYER Metal2 ;
        RECT  648.28 999.6 648.68 1000 ;
    END
  END frame_rsp_i[15]
  PIN frame_rsp_i[16]
    DIRECTION INPUT ;
    USE SIGNAL ;
    PORT
      LAYER Metal2 ;
        RECT  649.24 999.6 649.64 1000 ;
    END
  END frame_rsp_i[16]
  PIN frame_rsp_i[17]
    DIRECTION INPUT ;
    USE SIGNAL ;
    PORT
      LAYER Metal2 ;
        RECT  650.2 999.6 650.6 1000 ;
    END
  END frame_rsp_i[17]
  PIN frame_rsp_i[18]
    DIRECTION INPUT ;
    USE SIGNAL ;
    PORT
      LAYER Metal2 ;
        RECT  651.16 999.6 651.56 1000 ;
    END
  END frame_rsp_i[18]
  PIN frame_rsp_i[19]
    DIRECTION INPUT ;
    USE SIGNAL ;
    PORT
      LAYER Metal2 ;
        RECT  652.12 999.6 652.52 1000 ;
    END
  END frame_rsp_i[19]
  PIN frame_rsp_i[1]
    DIRECTION INPUT ;
    USE SIGNAL ;
    PORT
      LAYER Metal2 ;
        RECT  634.84 999.6 635.24 1000 ;
    END
  END frame_rsp_i[1]
  PIN frame_rsp_i[20]
    DIRECTION INPUT ;
    USE SIGNAL ;
    PORT
      LAYER Metal2 ;
        RECT  653.08 999.6 653.48 1000 ;
    END
  END frame_rsp_i[20]
  PIN frame_rsp_i[21]
    DIRECTION INPUT ;
    USE SIGNAL ;
    PORT
      LAYER Metal2 ;
        RECT  654.04 999.6 654.44 1000 ;
    END
  END frame_rsp_i[21]
  PIN frame_rsp_i[22]
    DIRECTION INPUT ;
    USE SIGNAL ;
    PORT
      LAYER Metal2 ;
        RECT  655 999.6 655.4 1000 ;
    END
  END frame_rsp_i[22]
  PIN frame_rsp_i[23]
    DIRECTION INPUT ;
    USE SIGNAL ;
    PORT
      LAYER Metal2 ;
        RECT  655.96 999.6 656.36 1000 ;
    END
  END frame_rsp_i[23]
  PIN frame_rsp_i[24]
    DIRECTION INPUT ;
    USE SIGNAL ;
    PORT
      LAYER Metal2 ;
        RECT  656.92 999.6 657.32 1000 ;
    END
  END frame_rsp_i[24]
  PIN frame_rsp_i[25]
    DIRECTION INPUT ;
    USE SIGNAL ;
    PORT
      LAYER Metal2 ;
        RECT  657.88 999.6 658.28 1000 ;
    END
  END frame_rsp_i[25]
  PIN frame_rsp_i[26]
    DIRECTION INPUT ;
    USE SIGNAL ;
    PORT
      LAYER Metal2 ;
        RECT  658.84 999.6 659.24 1000 ;
    END
  END frame_rsp_i[26]
  PIN frame_rsp_i[27]
    DIRECTION INPUT ;
    USE SIGNAL ;
    PORT
      LAYER Metal2 ;
        RECT  659.8 999.6 660.2 1000 ;
    END
  END frame_rsp_i[27]
  PIN frame_rsp_i[28]
    DIRECTION INPUT ;
    USE SIGNAL ;
    PORT
      LAYER Metal2 ;
        RECT  660.76 999.6 661.16 1000 ;
    END
  END frame_rsp_i[28]
  PIN frame_rsp_i[29]
    DIRECTION INPUT ;
    USE SIGNAL ;
    PORT
      LAYER Metal2 ;
        RECT  661.72 999.6 662.12 1000 ;
    END
  END frame_rsp_i[29]
  PIN frame_rsp_i[2]
    DIRECTION INPUT ;
    USE SIGNAL ;
    PORT
      LAYER Metal2 ;
        RECT  635.8 999.6 636.2 1000 ;
    END
  END frame_rsp_i[2]
  PIN frame_rsp_i[30]
    DIRECTION INPUT ;
    USE SIGNAL ;
    PORT
      LAYER Metal2 ;
        RECT  662.68 999.6 663.08 1000 ;
    END
  END frame_rsp_i[30]
  PIN frame_rsp_i[31]
    DIRECTION INPUT ;
    USE SIGNAL ;
    PORT
      LAYER Metal2 ;
        RECT  663.64 999.6 664.04 1000 ;
    END
  END frame_rsp_i[31]
  PIN frame_rsp_i[3]
    DIRECTION INPUT ;
    USE SIGNAL ;
    PORT
      LAYER Metal2 ;
        RECT  636.76 999.6 637.16 1000 ;
    END
  END frame_rsp_i[3]
  PIN frame_rsp_i[4]
    DIRECTION INPUT ;
    USE SIGNAL ;
    PORT
      LAYER Metal2 ;
        RECT  637.72 999.6 638.12 1000 ;
    END
  END frame_rsp_i[4]
  PIN frame_rsp_i[5]
    DIRECTION INPUT ;
    USE SIGNAL ;
    PORT
      LAYER Metal2 ;
        RECT  638.68 999.6 639.08 1000 ;
    END
  END frame_rsp_i[5]
  PIN frame_rsp_i[6]
    DIRECTION INPUT ;
    USE SIGNAL ;
    PORT
      LAYER Metal2 ;
        RECT  639.64 999.6 640.04 1000 ;
    END
  END frame_rsp_i[6]
  PIN frame_rsp_i[7]
    DIRECTION INPUT ;
    USE SIGNAL ;
    PORT
      LAYER Metal2 ;
        RECT  640.6 999.6 641 1000 ;
    END
  END frame_rsp_i[7]
  PIN frame_rsp_i[8]
    DIRECTION INPUT ;
    USE SIGNAL ;
    PORT
      LAYER Metal2 ;
        RECT  641.56 999.6 641.96 1000 ;
    END
  END frame_rsp_i[8]
  PIN frame_rsp_i[9]
    DIRECTION INPUT ;
    USE SIGNAL ;
    PORT
      LAYER Metal2 ;
        RECT  642.52 999.6 642.92 1000 ;
    END
  END frame_rsp_i[9]
  PIN issue_i.address[0]
    DIRECTION INPUT ;
    USE SIGNAL ;
    PORT
      LAYER Metal2 ;
        RECT  79.96 999.6 80.36 1000 ;
    END
  END issue_i.address[0]
  PIN issue_i.address[10]
    DIRECTION INPUT ;
    USE SIGNAL ;
    PORT
      LAYER Metal2 ;
        RECT  114.52 999.6 114.92 1000 ;
    END
  END issue_i.address[10]
  PIN issue_i.address[11]
    DIRECTION INPUT ;
    USE SIGNAL ;
    PORT
      LAYER Metal2 ;
        RECT  117.4 999.6 117.8 1000 ;
    END
  END issue_i.address[11]
  PIN issue_i.address[12]
    DIRECTION INPUT ;
    USE SIGNAL ;
    PORT
      LAYER Metal2 ;
        RECT  120.28 999.6 120.68 1000 ;
    END
  END issue_i.address[12]
  PIN issue_i.address[13]
    DIRECTION INPUT ;
    USE SIGNAL ;
    PORT
      LAYER Metal2 ;
        RECT  123.16 999.6 123.56 1000 ;
    END
  END issue_i.address[13]
  PIN issue_i.address[14]
    DIRECTION INPUT ;
    USE SIGNAL ;
    PORT
      LAYER Metal2 ;
        RECT  126.04 999.6 126.44 1000 ;
    END
  END issue_i.address[14]
  PIN issue_i.address[15]
    DIRECTION INPUT ;
    USE SIGNAL ;
    PORT
      LAYER Metal2 ;
        RECT  128.92 999.6 129.32 1000 ;
    END
  END issue_i.address[15]
  PIN issue_i.address[16]
    DIRECTION INPUT ;
    USE SIGNAL ;
    PORT
      LAYER Metal2 ;
        RECT  131.8 999.6 132.2 1000 ;
    END
  END issue_i.address[16]
  PIN issue_i.address[17]
    DIRECTION INPUT ;
    USE SIGNAL ;
    PORT
      LAYER Metal2 ;
        RECT  134.68 999.6 135.08 1000 ;
    END
  END issue_i.address[17]
  PIN issue_i.address[18]
    DIRECTION INPUT ;
    USE SIGNAL ;
    PORT
      LAYER Metal2 ;
        RECT  137.56 999.6 137.96 1000 ;
    END
  END issue_i.address[18]
  PIN issue_i.address[19]
    DIRECTION INPUT ;
    USE SIGNAL ;
    PORT
      LAYER Metal2 ;
        RECT  140.44 999.6 140.84 1000 ;
    END
  END issue_i.address[19]
  PIN issue_i.address[1]
    DIRECTION INPUT ;
    USE SIGNAL ;
    PORT
      LAYER Metal2 ;
        RECT  84.76 999.6 85.16 1000 ;
    END
  END issue_i.address[1]
  PIN issue_i.address[20]
    DIRECTION INPUT ;
    USE SIGNAL ;
    PORT
      LAYER Metal2 ;
        RECT  143.32 999.6 143.72 1000 ;
    END
  END issue_i.address[20]
  PIN issue_i.address[21]
    DIRECTION INPUT ;
    USE SIGNAL ;
    PORT
      LAYER Metal2 ;
        RECT  146.2 999.6 146.6 1000 ;
    END
  END issue_i.address[21]
  PIN issue_i.address[22]
    DIRECTION INPUT ;
    USE SIGNAL ;
    PORT
      LAYER Metal2 ;
        RECT  149.08 999.6 149.48 1000 ;
    END
  END issue_i.address[22]
  PIN issue_i.address[23]
    DIRECTION INPUT ;
    USE SIGNAL ;
    PORT
      LAYER Metal2 ;
        RECT  151.96 999.6 152.36 1000 ;
    END
  END issue_i.address[23]
  PIN issue_i.address[24]
    DIRECTION INPUT ;
    USE SIGNAL ;
    PORT
      LAYER Metal2 ;
        RECT  154.84 999.6 155.24 1000 ;
    END
  END issue_i.address[24]
  PIN issue_i.address[25]
    DIRECTION INPUT ;
    USE SIGNAL ;
    PORT
      LAYER Metal2 ;
        RECT  157.72 999.6 158.12 1000 ;
    END
  END issue_i.address[25]
  PIN issue_i.address[26]
    DIRECTION INPUT ;
    USE SIGNAL ;
    PORT
      LAYER Metal2 ;
        RECT  160.6 999.6 161 1000 ;
    END
  END issue_i.address[26]
  PIN issue_i.address[27]
    DIRECTION INPUT ;
    USE SIGNAL ;
    PORT
      LAYER Metal2 ;
        RECT  163.48 999.6 163.88 1000 ;
    END
  END issue_i.address[27]
  PIN issue_i.address[28]
    DIRECTION INPUT ;
    USE SIGNAL ;
    PORT
      LAYER Metal2 ;
        RECT  166.36 999.6 166.76 1000 ;
    END
  END issue_i.address[28]
  PIN issue_i.address[29]
    DIRECTION INPUT ;
    USE SIGNAL ;
    PORT
      LAYER Metal2 ;
        RECT  169.24 999.6 169.64 1000 ;
    END
  END issue_i.address[29]
  PIN issue_i.address[2]
    DIRECTION INPUT ;
    USE SIGNAL ;
    PORT
      LAYER Metal2 ;
        RECT  89.56 999.6 89.96 1000 ;
    END
  END issue_i.address[2]
  PIN issue_i.address[30]
    DIRECTION INPUT ;
    USE SIGNAL ;
    PORT
      LAYER Metal2 ;
        RECT  172.12 999.6 172.52 1000 ;
    END
  END issue_i.address[30]
  PIN issue_i.address[31]
    DIRECTION INPUT ;
    USE SIGNAL ;
    PORT
      LAYER Metal2 ;
        RECT  175 999.6 175.4 1000 ;
    END
  END issue_i.address[31]
  PIN issue_i.address[3]
    DIRECTION INPUT ;
    USE SIGNAL ;
    PORT
      LAYER Metal2 ;
        RECT  94.36 999.6 94.76 1000 ;
    END
  END issue_i.address[3]
  PIN issue_i.address[4]
    DIRECTION INPUT ;
    USE SIGNAL ;
    PORT
      LAYER Metal2 ;
        RECT  97.24 999.6 97.64 1000 ;
    END
  END issue_i.address[4]
  PIN issue_i.address[5]
    DIRECTION INPUT ;
    USE SIGNAL ;
    PORT
      LAYER Metal2 ;
        RECT  100.12 999.6 100.52 1000 ;
    END
  END issue_i.address[5]
  PIN issue_i.address[6]
    DIRECTION INPUT ;
    USE SIGNAL ;
    PORT
      LAYER Metal2 ;
        RECT  103 999.6 103.4 1000 ;
    END
  END issue_i.address[6]
  PIN issue_i.address[7]
    DIRECTION INPUT ;
    USE SIGNAL ;
    PORT
      LAYER Metal2 ;
        RECT  105.88 999.6 106.28 1000 ;
    END
  END issue_i.address[7]
  PIN issue_i.address[8]
    DIRECTION INPUT ;
    USE SIGNAL ;
    PORT
      LAYER Metal2 ;
        RECT  108.76 999.6 109.16 1000 ;
    END
  END issue_i.address[8]
  PIN issue_i.address[9]
    DIRECTION INPUT ;
    USE SIGNAL ;
    PORT
      LAYER Metal2 ;
        RECT  111.64 999.6 112.04 1000 ;
    END
  END issue_i.address[9]
  PIN issue_i.address_known
    DIRECTION INPUT ;
    USE SIGNAL ;
    PORT
      LAYER Metal2 ;
        RECT  78.04 999.6 78.44 1000 ;
    END
  END issue_i.address_known
  PIN issue_i.address_ofs
    DIRECTION INPUT ;
    USE SIGNAL ;
    PORT
      LAYER Metal2 ;
        RECT  79 999.6 79.4 1000 ;
    END
  END issue_i.address_ofs
  PIN issue_i.issue_class[0]
    DIRECTION INPUT ;
    USE SIGNAL ;
    PORT
      LAYER Metal2 ;
        RECT  80.92 999.6 81.32 1000 ;
    END
  END issue_i.issue_class[0]
  PIN issue_i.issue_class[1]
    DIRECTION INPUT ;
    USE SIGNAL ;
    PORT
      LAYER Metal2 ;
        RECT  85.72 999.6 86.12 1000 ;
    END
  END issue_i.issue_class[1]
  PIN issue_i.issue_class[2]
    DIRECTION INPUT ;
    USE SIGNAL ;
    PORT
      LAYER Metal2 ;
        RECT  90.52 999.6 90.92 1000 ;
    END
  END issue_i.issue_class[2]
  PIN issue_i.operand[0]
    DIRECTION INPUT ;
    USE SIGNAL ;
    PORT
      LAYER Metal2 ;
        RECT  81.88 999.6 82.28 1000 ;
    END
  END issue_i.operand[0]
  PIN issue_i.operand[100]
    DIRECTION INPUT ;
    USE SIGNAL ;
    PORT
      LAYER Metal2 ;
        RECT  308.44 999.6 308.84 1000 ;
    END
  END issue_i.operand[100]
  PIN issue_i.operand[101]
    DIRECTION INPUT ;
    USE SIGNAL ;
    PORT
      LAYER Metal2 ;
        RECT  310.36 999.6 310.76 1000 ;
    END
  END issue_i.operand[101]
  PIN issue_i.operand[102]
    DIRECTION INPUT ;
    USE SIGNAL ;
    PORT
      LAYER Metal2 ;
        RECT  312.28 999.6 312.68 1000 ;
    END
  END issue_i.operand[102]
  PIN issue_i.operand[103]
    DIRECTION INPUT ;
    USE SIGNAL ;
    PORT
      LAYER Metal2 ;
        RECT  314.2 999.6 314.6 1000 ;
    END
  END issue_i.operand[103]
  PIN issue_i.operand[104]
    DIRECTION INPUT ;
    USE SIGNAL ;
    PORT
      LAYER Metal2 ;
        RECT  316.12 999.6 316.52 1000 ;
    END
  END issue_i.operand[104]
  PIN issue_i.operand[105]
    DIRECTION INPUT ;
    USE SIGNAL ;
    PORT
      LAYER Metal2 ;
        RECT  318.04 999.6 318.44 1000 ;
    END
  END issue_i.operand[105]
  PIN issue_i.operand[106]
    DIRECTION INPUT ;
    USE SIGNAL ;
    PORT
      LAYER Metal2 ;
        RECT  319.96 999.6 320.36 1000 ;
    END
  END issue_i.operand[106]
  PIN issue_i.operand[107]
    DIRECTION INPUT ;
    USE SIGNAL ;
    PORT
      LAYER Metal2 ;
        RECT  321.88 999.6 322.28 1000 ;
    END
  END issue_i.operand[107]
  PIN issue_i.operand[108]
    DIRECTION INPUT ;
    USE SIGNAL ;
    PORT
      LAYER Metal2 ;
        RECT  323.8 999.6 324.2 1000 ;
    END
  END issue_i.operand[108]
  PIN issue_i.operand[109]
    DIRECTION INPUT ;
    USE SIGNAL ;
    PORT
      LAYER Metal2 ;
        RECT  325.72 999.6 326.12 1000 ;
    END
  END issue_i.operand[109]
  PIN issue_i.operand[10]
    DIRECTION INPUT ;
    USE SIGNAL ;
    PORT
      LAYER Metal2 ;
        RECT  115.48 999.6 115.88 1000 ;
    END
  END issue_i.operand[10]
  PIN issue_i.operand[110]
    DIRECTION INPUT ;
    USE SIGNAL ;
    PORT
      LAYER Metal2 ;
        RECT  327.64 999.6 328.04 1000 ;
    END
  END issue_i.operand[110]
  PIN issue_i.operand[111]
    DIRECTION INPUT ;
    USE SIGNAL ;
    PORT
      LAYER Metal2 ;
        RECT  329.56 999.6 329.96 1000 ;
    END
  END issue_i.operand[111]
  PIN issue_i.operand[112]
    DIRECTION INPUT ;
    USE SIGNAL ;
    PORT
      LAYER Metal2 ;
        RECT  331.48 999.6 331.88 1000 ;
    END
  END issue_i.operand[112]
  PIN issue_i.operand[113]
    DIRECTION INPUT ;
    USE SIGNAL ;
    PORT
      LAYER Metal2 ;
        RECT  333.4 999.6 333.8 1000 ;
    END
  END issue_i.operand[113]
  PIN issue_i.operand[114]
    DIRECTION INPUT ;
    USE SIGNAL ;
    PORT
      LAYER Metal2 ;
        RECT  335.32 999.6 335.72 1000 ;
    END
  END issue_i.operand[114]
  PIN issue_i.operand[115]
    DIRECTION INPUT ;
    USE SIGNAL ;
    PORT
      LAYER Metal2 ;
        RECT  337.24 999.6 337.64 1000 ;
    END
  END issue_i.operand[115]
  PIN issue_i.operand[116]
    DIRECTION INPUT ;
    USE SIGNAL ;
    PORT
      LAYER Metal2 ;
        RECT  339.16 999.6 339.56 1000 ;
    END
  END issue_i.operand[116]
  PIN issue_i.operand[117]
    DIRECTION INPUT ;
    USE SIGNAL ;
    PORT
      LAYER Metal2 ;
        RECT  341.08 999.6 341.48 1000 ;
    END
  END issue_i.operand[117]
  PIN issue_i.operand[118]
    DIRECTION INPUT ;
    USE SIGNAL ;
    PORT
      LAYER Metal2 ;
        RECT  343 999.6 343.4 1000 ;
    END
  END issue_i.operand[118]
  PIN issue_i.operand[119]
    DIRECTION INPUT ;
    USE SIGNAL ;
    PORT
      LAYER Metal2 ;
        RECT  344.92 999.6 345.32 1000 ;
    END
  END issue_i.operand[119]
  PIN issue_i.operand[11]
    DIRECTION INPUT ;
    USE SIGNAL ;
    PORT
      LAYER Metal2 ;
        RECT  118.36 999.6 118.76 1000 ;
    END
  END issue_i.operand[11]
  PIN issue_i.operand[120]
    DIRECTION INPUT ;
    USE SIGNAL ;
    PORT
      LAYER Metal2 ;
        RECT  346.84 999.6 347.24 1000 ;
    END
  END issue_i.operand[120]
  PIN issue_i.operand[121]
    DIRECTION INPUT ;
    USE SIGNAL ;
    PORT
      LAYER Metal2 ;
        RECT  348.76 999.6 349.16 1000 ;
    END
  END issue_i.operand[121]
  PIN issue_i.operand[122]
    DIRECTION INPUT ;
    USE SIGNAL ;
    PORT
      LAYER Metal2 ;
        RECT  350.68 999.6 351.08 1000 ;
    END
  END issue_i.operand[122]
  PIN issue_i.operand[123]
    DIRECTION INPUT ;
    USE SIGNAL ;
    PORT
      LAYER Metal2 ;
        RECT  352.6 999.6 353 1000 ;
    END
  END issue_i.operand[123]
  PIN issue_i.operand[124]
    DIRECTION INPUT ;
    USE SIGNAL ;
    PORT
      LAYER Metal2 ;
        RECT  354.52 999.6 354.92 1000 ;
    END
  END issue_i.operand[124]
  PIN issue_i.operand[125]
    DIRECTION INPUT ;
    USE SIGNAL ;
    PORT
      LAYER Metal2 ;
        RECT  356.44 999.6 356.84 1000 ;
    END
  END issue_i.operand[125]
  PIN issue_i.operand[126]
    DIRECTION INPUT ;
    USE SIGNAL ;
    PORT
      LAYER Metal2 ;
        RECT  358.36 999.6 358.76 1000 ;
    END
  END issue_i.operand[126]
  PIN issue_i.operand[127]
    DIRECTION INPUT ;
    USE SIGNAL ;
    PORT
      LAYER Metal2 ;
        RECT  360.28 999.6 360.68 1000 ;
    END
  END issue_i.operand[127]
  PIN issue_i.operand[128]
    DIRECTION INPUT ;
    USE SIGNAL ;
    PORT
      LAYER Metal2 ;
        RECT  362.2 999.6 362.6 1000 ;
    END
  END issue_i.operand[128]
  PIN issue_i.operand[129]
    DIRECTION INPUT ;
    USE SIGNAL ;
    PORT
      LAYER Metal2 ;
        RECT  364.12 999.6 364.52 1000 ;
    END
  END issue_i.operand[129]
  PIN issue_i.operand[12]
    DIRECTION INPUT ;
    USE SIGNAL ;
    PORT
      LAYER Metal2 ;
        RECT  121.24 999.6 121.64 1000 ;
    END
  END issue_i.operand[12]
  PIN issue_i.operand[130]
    DIRECTION INPUT ;
    USE SIGNAL ;
    PORT
      LAYER Metal2 ;
        RECT  366.04 999.6 366.44 1000 ;
    END
  END issue_i.operand[130]
  PIN issue_i.operand[131]
    DIRECTION INPUT ;
    USE SIGNAL ;
    PORT
      LAYER Metal2 ;
        RECT  367.96 999.6 368.36 1000 ;
    END
  END issue_i.operand[131]
  PIN issue_i.operand[132]
    DIRECTION INPUT ;
    USE SIGNAL ;
    PORT
      LAYER Metal2 ;
        RECT  369.88 999.6 370.28 1000 ;
    END
  END issue_i.operand[132]
  PIN issue_i.operand[133]
    DIRECTION INPUT ;
    USE SIGNAL ;
    PORT
      LAYER Metal2 ;
        RECT  371.8 999.6 372.2 1000 ;
    END
  END issue_i.operand[133]
  PIN issue_i.operand[134]
    DIRECTION INPUT ;
    USE SIGNAL ;
    PORT
      LAYER Metal2 ;
        RECT  373.72 999.6 374.12 1000 ;
    END
  END issue_i.operand[134]
  PIN issue_i.operand[135]
    DIRECTION INPUT ;
    USE SIGNAL ;
    PORT
      LAYER Metal2 ;
        RECT  375.64 999.6 376.04 1000 ;
    END
  END issue_i.operand[135]
  PIN issue_i.operand[136]
    DIRECTION INPUT ;
    USE SIGNAL ;
    PORT
      LAYER Metal2 ;
        RECT  377.56 999.6 377.96 1000 ;
    END
  END issue_i.operand[136]
  PIN issue_i.operand[137]
    DIRECTION INPUT ;
    USE SIGNAL ;
    PORT
      LAYER Metal2 ;
        RECT  379.48 999.6 379.88 1000 ;
    END
  END issue_i.operand[137]
  PIN issue_i.operand[138]
    DIRECTION INPUT ;
    USE SIGNAL ;
    PORT
      LAYER Metal2 ;
        RECT  381.4 999.6 381.8 1000 ;
    END
  END issue_i.operand[138]
  PIN issue_i.operand[139]
    DIRECTION INPUT ;
    USE SIGNAL ;
    PORT
      LAYER Metal2 ;
        RECT  383.32 999.6 383.72 1000 ;
    END
  END issue_i.operand[139]
  PIN issue_i.operand[13]
    DIRECTION INPUT ;
    USE SIGNAL ;
    PORT
      LAYER Metal2 ;
        RECT  124.12 999.6 124.52 1000 ;
    END
  END issue_i.operand[13]
  PIN issue_i.operand[140]
    DIRECTION INPUT ;
    USE SIGNAL ;
    PORT
      LAYER Metal2 ;
        RECT  385.24 999.6 385.64 1000 ;
    END
  END issue_i.operand[140]
  PIN issue_i.operand[141]
    DIRECTION INPUT ;
    USE SIGNAL ;
    PORT
      LAYER Metal2 ;
        RECT  387.16 999.6 387.56 1000 ;
    END
  END issue_i.operand[141]
  PIN issue_i.operand[142]
    DIRECTION INPUT ;
    USE SIGNAL ;
    PORT
      LAYER Metal2 ;
        RECT  389.08 999.6 389.48 1000 ;
    END
  END issue_i.operand[142]
  PIN issue_i.operand[143]
    DIRECTION INPUT ;
    USE SIGNAL ;
    PORT
      LAYER Metal2 ;
        RECT  391 999.6 391.4 1000 ;
    END
  END issue_i.operand[143]
  PIN issue_i.operand[144]
    DIRECTION INPUT ;
    USE SIGNAL ;
    PORT
      LAYER Metal2 ;
        RECT  391.96 999.6 392.36 1000 ;
    END
  END issue_i.operand[144]
  PIN issue_i.operand[145]
    DIRECTION INPUT ;
    USE SIGNAL ;
    PORT
      LAYER Metal2 ;
        RECT  392.92 999.6 393.32 1000 ;
    END
  END issue_i.operand[145]
  PIN issue_i.operand[146]
    DIRECTION INPUT ;
    USE SIGNAL ;
    PORT
      LAYER Metal2 ;
        RECT  393.88 999.6 394.28 1000 ;
    END
  END issue_i.operand[146]
  PIN issue_i.operand[147]
    DIRECTION INPUT ;
    USE SIGNAL ;
    PORT
      LAYER Metal2 ;
        RECT  394.84 999.6 395.24 1000 ;
    END
  END issue_i.operand[147]
  PIN issue_i.operand[148]
    DIRECTION INPUT ;
    USE SIGNAL ;
    PORT
      LAYER Metal2 ;
        RECT  395.8 999.6 396.2 1000 ;
    END
  END issue_i.operand[148]
  PIN issue_i.operand[149]
    DIRECTION INPUT ;
    USE SIGNAL ;
    PORT
      LAYER Metal2 ;
        RECT  396.76 999.6 397.16 1000 ;
    END
  END issue_i.operand[149]
  PIN issue_i.operand[14]
    DIRECTION INPUT ;
    USE SIGNAL ;
    PORT
      LAYER Metal2 ;
        RECT  127 999.6 127.4 1000 ;
    END
  END issue_i.operand[14]
  PIN issue_i.operand[150]
    DIRECTION INPUT ;
    USE SIGNAL ;
    PORT
      LAYER Metal2 ;
        RECT  397.72 999.6 398.12 1000 ;
    END
  END issue_i.operand[150]
  PIN issue_i.operand[151]
    DIRECTION INPUT ;
    USE SIGNAL ;
    PORT
      LAYER Metal2 ;
        RECT  398.68 999.6 399.08 1000 ;
    END
  END issue_i.operand[151]
  PIN issue_i.operand[152]
    DIRECTION INPUT ;
    USE SIGNAL ;
    PORT
      LAYER Metal2 ;
        RECT  399.64 999.6 400.04 1000 ;
    END
  END issue_i.operand[152]
  PIN issue_i.operand[153]
    DIRECTION INPUT ;
    USE SIGNAL ;
    PORT
      LAYER Metal2 ;
        RECT  400.6 999.6 401 1000 ;
    END
  END issue_i.operand[153]
  PIN issue_i.operand[154]
    DIRECTION INPUT ;
    USE SIGNAL ;
    PORT
      LAYER Metal2 ;
        RECT  401.56 999.6 401.96 1000 ;
    END
  END issue_i.operand[154]
  PIN issue_i.operand[155]
    DIRECTION INPUT ;
    USE SIGNAL ;
    PORT
      LAYER Metal2 ;
        RECT  402.52 999.6 402.92 1000 ;
    END
  END issue_i.operand[155]
  PIN issue_i.operand[156]
    DIRECTION INPUT ;
    USE SIGNAL ;
    PORT
      LAYER Metal2 ;
        RECT  403.48 999.6 403.88 1000 ;
    END
  END issue_i.operand[156]
  PIN issue_i.operand[157]
    DIRECTION INPUT ;
    USE SIGNAL ;
    PORT
      LAYER Metal2 ;
        RECT  404.44 999.6 404.84 1000 ;
    END
  END issue_i.operand[157]
  PIN issue_i.operand[158]
    DIRECTION INPUT ;
    USE SIGNAL ;
    PORT
      LAYER Metal2 ;
        RECT  405.4 999.6 405.8 1000 ;
    END
  END issue_i.operand[158]
  PIN issue_i.operand[159]
    DIRECTION INPUT ;
    USE SIGNAL ;
    PORT
      LAYER Metal2 ;
        RECT  406.36 999.6 406.76 1000 ;
    END
  END issue_i.operand[159]
  PIN issue_i.operand[15]
    DIRECTION INPUT ;
    USE SIGNAL ;
    PORT
      LAYER Metal2 ;
        RECT  129.88 999.6 130.28 1000 ;
    END
  END issue_i.operand[15]
  PIN issue_i.operand[160]
    DIRECTION INPUT ;
    USE SIGNAL ;
    PORT
      LAYER Metal2 ;
        RECT  407.32 999.6 407.72 1000 ;
    END
  END issue_i.operand[160]
  PIN issue_i.operand[161]
    DIRECTION INPUT ;
    USE SIGNAL ;
    PORT
      LAYER Metal2 ;
        RECT  408.28 999.6 408.68 1000 ;
    END
  END issue_i.operand[161]
  PIN issue_i.operand[162]
    DIRECTION INPUT ;
    USE SIGNAL ;
    PORT
      LAYER Metal2 ;
        RECT  409.24 999.6 409.64 1000 ;
    END
  END issue_i.operand[162]
  PIN issue_i.operand[163]
    DIRECTION INPUT ;
    USE SIGNAL ;
    PORT
      LAYER Metal2 ;
        RECT  410.2 999.6 410.6 1000 ;
    END
  END issue_i.operand[163]
  PIN issue_i.operand[164]
    DIRECTION INPUT ;
    USE SIGNAL ;
    PORT
      LAYER Metal2 ;
        RECT  411.16 999.6 411.56 1000 ;
    END
  END issue_i.operand[164]
  PIN issue_i.operand[165]
    DIRECTION INPUT ;
    USE SIGNAL ;
    PORT
      LAYER Metal2 ;
        RECT  412.12 999.6 412.52 1000 ;
    END
  END issue_i.operand[165]
  PIN issue_i.operand[166]
    DIRECTION INPUT ;
    USE SIGNAL ;
    PORT
      LAYER Metal2 ;
        RECT  413.08 999.6 413.48 1000 ;
    END
  END issue_i.operand[166]
  PIN issue_i.operand[167]
    DIRECTION INPUT ;
    USE SIGNAL ;
    PORT
      LAYER Metal2 ;
        RECT  414.04 999.6 414.44 1000 ;
    END
  END issue_i.operand[167]
  PIN issue_i.operand[168]
    DIRECTION INPUT ;
    USE SIGNAL ;
    PORT
      LAYER Metal2 ;
        RECT  415 999.6 415.4 1000 ;
    END
  END issue_i.operand[168]
  PIN issue_i.operand[169]
    DIRECTION INPUT ;
    USE SIGNAL ;
    PORT
      LAYER Metal2 ;
        RECT  415.96 999.6 416.36 1000 ;
    END
  END issue_i.operand[169]
  PIN issue_i.operand[16]
    DIRECTION INPUT ;
    USE SIGNAL ;
    PORT
      LAYER Metal2 ;
        RECT  132.76 999.6 133.16 1000 ;
    END
  END issue_i.operand[16]
  PIN issue_i.operand[170]
    DIRECTION INPUT ;
    USE SIGNAL ;
    PORT
      LAYER Metal2 ;
        RECT  416.92 999.6 417.32 1000 ;
    END
  END issue_i.operand[170]
  PIN issue_i.operand[171]
    DIRECTION INPUT ;
    USE SIGNAL ;
    PORT
      LAYER Metal2 ;
        RECT  417.88 999.6 418.28 1000 ;
    END
  END issue_i.operand[171]
  PIN issue_i.operand[172]
    DIRECTION INPUT ;
    USE SIGNAL ;
    PORT
      LAYER Metal2 ;
        RECT  418.84 999.6 419.24 1000 ;
    END
  END issue_i.operand[172]
  PIN issue_i.operand[173]
    DIRECTION INPUT ;
    USE SIGNAL ;
    PORT
      LAYER Metal2 ;
        RECT  419.8 999.6 420.2 1000 ;
    END
  END issue_i.operand[173]
  PIN issue_i.operand[174]
    DIRECTION INPUT ;
    USE SIGNAL ;
    PORT
      LAYER Metal2 ;
        RECT  420.76 999.6 421.16 1000 ;
    END
  END issue_i.operand[174]
  PIN issue_i.operand[175]
    DIRECTION INPUT ;
    USE SIGNAL ;
    PORT
      LAYER Metal2 ;
        RECT  421.72 999.6 422.12 1000 ;
    END
  END issue_i.operand[175]
  PIN issue_i.operand[176]
    DIRECTION INPUT ;
    USE SIGNAL ;
    PORT
      LAYER Metal2 ;
        RECT  422.68 999.6 423.08 1000 ;
    END
  END issue_i.operand[176]
  PIN issue_i.operand[177]
    DIRECTION INPUT ;
    USE SIGNAL ;
    PORT
      LAYER Metal2 ;
        RECT  423.64 999.6 424.04 1000 ;
    END
  END issue_i.operand[177]
  PIN issue_i.operand[178]
    DIRECTION INPUT ;
    USE SIGNAL ;
    PORT
      LAYER Metal2 ;
        RECT  424.6 999.6 425 1000 ;
    END
  END issue_i.operand[178]
  PIN issue_i.operand[179]
    DIRECTION INPUT ;
    USE SIGNAL ;
    PORT
      LAYER Metal2 ;
        RECT  425.56 999.6 425.96 1000 ;
    END
  END issue_i.operand[179]
  PIN issue_i.operand[17]
    DIRECTION INPUT ;
    USE SIGNAL ;
    PORT
      LAYER Metal2 ;
        RECT  135.64 999.6 136.04 1000 ;
    END
  END issue_i.operand[17]
  PIN issue_i.operand[180]
    DIRECTION INPUT ;
    USE SIGNAL ;
    PORT
      LAYER Metal2 ;
        RECT  426.52 999.6 426.92 1000 ;
    END
  END issue_i.operand[180]
  PIN issue_i.operand[181]
    DIRECTION INPUT ;
    USE SIGNAL ;
    PORT
      LAYER Metal2 ;
        RECT  427.48 999.6 427.88 1000 ;
    END
  END issue_i.operand[181]
  PIN issue_i.operand[182]
    DIRECTION INPUT ;
    USE SIGNAL ;
    PORT
      LAYER Metal2 ;
        RECT  428.44 999.6 428.84 1000 ;
    END
  END issue_i.operand[182]
  PIN issue_i.operand[183]
    DIRECTION INPUT ;
    USE SIGNAL ;
    PORT
      LAYER Metal2 ;
        RECT  429.4 999.6 429.8 1000 ;
    END
  END issue_i.operand[183]
  PIN issue_i.operand[184]
    DIRECTION INPUT ;
    USE SIGNAL ;
    PORT
      LAYER Metal2 ;
        RECT  430.36 999.6 430.76 1000 ;
    END
  END issue_i.operand[184]
  PIN issue_i.operand[185]
    DIRECTION INPUT ;
    USE SIGNAL ;
    PORT
      LAYER Metal2 ;
        RECT  431.32 999.6 431.72 1000 ;
    END
  END issue_i.operand[185]
  PIN issue_i.operand[186]
    DIRECTION INPUT ;
    USE SIGNAL ;
    PORT
      LAYER Metal2 ;
        RECT  432.28 999.6 432.68 1000 ;
    END
  END issue_i.operand[186]
  PIN issue_i.operand[187]
    DIRECTION INPUT ;
    USE SIGNAL ;
    PORT
      LAYER Metal2 ;
        RECT  433.24 999.6 433.64 1000 ;
    END
  END issue_i.operand[187]
  PIN issue_i.operand[188]
    DIRECTION INPUT ;
    USE SIGNAL ;
    PORT
      LAYER Metal2 ;
        RECT  434.2 999.6 434.6 1000 ;
    END
  END issue_i.operand[188]
  PIN issue_i.operand[189]
    DIRECTION INPUT ;
    USE SIGNAL ;
    PORT
      LAYER Metal2 ;
        RECT  435.16 999.6 435.56 1000 ;
    END
  END issue_i.operand[189]
  PIN issue_i.operand[18]
    DIRECTION INPUT ;
    USE SIGNAL ;
    PORT
      LAYER Metal2 ;
        RECT  138.52 999.6 138.92 1000 ;
    END
  END issue_i.operand[18]
  PIN issue_i.operand[190]
    DIRECTION INPUT ;
    USE SIGNAL ;
    PORT
      LAYER Metal2 ;
        RECT  436.12 999.6 436.52 1000 ;
    END
  END issue_i.operand[190]
  PIN issue_i.operand[191]
    DIRECTION INPUT ;
    USE SIGNAL ;
    PORT
      LAYER Metal2 ;
        RECT  437.08 999.6 437.48 1000 ;
    END
  END issue_i.operand[191]
  PIN issue_i.operand[192]
    DIRECTION INPUT ;
    USE SIGNAL ;
    PORT
      LAYER Metal2 ;
        RECT  438.04 999.6 438.44 1000 ;
    END
  END issue_i.operand[192]
  PIN issue_i.operand[193]
    DIRECTION INPUT ;
    USE SIGNAL ;
    PORT
      LAYER Metal2 ;
        RECT  439 999.6 439.4 1000 ;
    END
  END issue_i.operand[193]
  PIN issue_i.operand[194]
    DIRECTION INPUT ;
    USE SIGNAL ;
    PORT
      LAYER Metal2 ;
        RECT  439.96 999.6 440.36 1000 ;
    END
  END issue_i.operand[194]
  PIN issue_i.operand[195]
    DIRECTION INPUT ;
    USE SIGNAL ;
    PORT
      LAYER Metal2 ;
        RECT  440.92 999.6 441.32 1000 ;
    END
  END issue_i.operand[195]
  PIN issue_i.operand[196]
    DIRECTION INPUT ;
    USE SIGNAL ;
    PORT
      LAYER Metal2 ;
        RECT  441.88 999.6 442.28 1000 ;
    END
  END issue_i.operand[196]
  PIN issue_i.operand[197]
    DIRECTION INPUT ;
    USE SIGNAL ;
    PORT
      LAYER Metal2 ;
        RECT  442.84 999.6 443.24 1000 ;
    END
  END issue_i.operand[197]
  PIN issue_i.operand[198]
    DIRECTION INPUT ;
    USE SIGNAL ;
    PORT
      LAYER Metal2 ;
        RECT  443.8 999.6 444.2 1000 ;
    END
  END issue_i.operand[198]
  PIN issue_i.operand[199]
    DIRECTION INPUT ;
    USE SIGNAL ;
    PORT
      LAYER Metal2 ;
        RECT  444.76 999.6 445.16 1000 ;
    END
  END issue_i.operand[199]
  PIN issue_i.operand[19]
    DIRECTION INPUT ;
    USE SIGNAL ;
    PORT
      LAYER Metal2 ;
        RECT  141.4 999.6 141.8 1000 ;
    END
  END issue_i.operand[19]
  PIN issue_i.operand[1]
    DIRECTION INPUT ;
    USE SIGNAL ;
    PORT
      LAYER Metal2 ;
        RECT  86.68 999.6 87.08 1000 ;
    END
  END issue_i.operand[1]
  PIN issue_i.operand[200]
    DIRECTION INPUT ;
    USE SIGNAL ;
    PORT
      LAYER Metal2 ;
        RECT  445.72 999.6 446.12 1000 ;
    END
  END issue_i.operand[200]
  PIN issue_i.operand[201]
    DIRECTION INPUT ;
    USE SIGNAL ;
    PORT
      LAYER Metal2 ;
        RECT  446.68 999.6 447.08 1000 ;
    END
  END issue_i.operand[201]
  PIN issue_i.operand[202]
    DIRECTION INPUT ;
    USE SIGNAL ;
    PORT
      LAYER Metal2 ;
        RECT  447.64 999.6 448.04 1000 ;
    END
  END issue_i.operand[202]
  PIN issue_i.operand[203]
    DIRECTION INPUT ;
    USE SIGNAL ;
    PORT
      LAYER Metal2 ;
        RECT  448.6 999.6 449 1000 ;
    END
  END issue_i.operand[203]
  PIN issue_i.operand[204]
    DIRECTION INPUT ;
    USE SIGNAL ;
    PORT
      LAYER Metal2 ;
        RECT  449.56 999.6 449.96 1000 ;
    END
  END issue_i.operand[204]
  PIN issue_i.operand[205]
    DIRECTION INPUT ;
    USE SIGNAL ;
    PORT
      LAYER Metal2 ;
        RECT  450.52 999.6 450.92 1000 ;
    END
  END issue_i.operand[205]
  PIN issue_i.operand[206]
    DIRECTION INPUT ;
    USE SIGNAL ;
    PORT
      LAYER Metal2 ;
        RECT  451.48 999.6 451.88 1000 ;
    END
  END issue_i.operand[206]
  PIN issue_i.operand[207]
    DIRECTION INPUT ;
    USE SIGNAL ;
    PORT
      LAYER Metal2 ;
        RECT  452.44 999.6 452.84 1000 ;
    END
  END issue_i.operand[207]
  PIN issue_i.operand[208]
    DIRECTION INPUT ;
    USE SIGNAL ;
    PORT
      LAYER Metal2 ;
        RECT  453.4 999.6 453.8 1000 ;
    END
  END issue_i.operand[208]
  PIN issue_i.operand[209]
    DIRECTION INPUT ;
    USE SIGNAL ;
    PORT
      LAYER Metal2 ;
        RECT  454.36 999.6 454.76 1000 ;
    END
  END issue_i.operand[209]
  PIN issue_i.operand[20]
    DIRECTION INPUT ;
    USE SIGNAL ;
    PORT
      LAYER Metal2 ;
        RECT  144.28 999.6 144.68 1000 ;
    END
  END issue_i.operand[20]
  PIN issue_i.operand[210]
    DIRECTION INPUT ;
    USE SIGNAL ;
    PORT
      LAYER Metal2 ;
        RECT  455.32 999.6 455.72 1000 ;
    END
  END issue_i.operand[210]
  PIN issue_i.operand[211]
    DIRECTION INPUT ;
    USE SIGNAL ;
    PORT
      LAYER Metal2 ;
        RECT  456.28 999.6 456.68 1000 ;
    END
  END issue_i.operand[211]
  PIN issue_i.operand[212]
    DIRECTION INPUT ;
    USE SIGNAL ;
    PORT
      LAYER Metal2 ;
        RECT  457.24 999.6 457.64 1000 ;
    END
  END issue_i.operand[212]
  PIN issue_i.operand[213]
    DIRECTION INPUT ;
    USE SIGNAL ;
    PORT
      LAYER Metal2 ;
        RECT  458.2 999.6 458.6 1000 ;
    END
  END issue_i.operand[213]
  PIN issue_i.operand[214]
    DIRECTION INPUT ;
    USE SIGNAL ;
    PORT
      LAYER Metal2 ;
        RECT  459.16 999.6 459.56 1000 ;
    END
  END issue_i.operand[214]
  PIN issue_i.operand[215]
    DIRECTION INPUT ;
    USE SIGNAL ;
    PORT
      LAYER Metal2 ;
        RECT  460.12 999.6 460.52 1000 ;
    END
  END issue_i.operand[215]
  PIN issue_i.operand[216]
    DIRECTION INPUT ;
    USE SIGNAL ;
    PORT
      LAYER Metal2 ;
        RECT  461.08 999.6 461.48 1000 ;
    END
  END issue_i.operand[216]
  PIN issue_i.operand[217]
    DIRECTION INPUT ;
    USE SIGNAL ;
    PORT
      LAYER Metal2 ;
        RECT  462.04 999.6 462.44 1000 ;
    END
  END issue_i.operand[217]
  PIN issue_i.operand[218]
    DIRECTION INPUT ;
    USE SIGNAL ;
    PORT
      LAYER Metal2 ;
        RECT  463 999.6 463.4 1000 ;
    END
  END issue_i.operand[218]
  PIN issue_i.operand[219]
    DIRECTION INPUT ;
    USE SIGNAL ;
    PORT
      LAYER Metal2 ;
        RECT  463.96 999.6 464.36 1000 ;
    END
  END issue_i.operand[219]
  PIN issue_i.operand[21]
    DIRECTION INPUT ;
    USE SIGNAL ;
    PORT
      LAYER Metal2 ;
        RECT  147.16 999.6 147.56 1000 ;
    END
  END issue_i.operand[21]
  PIN issue_i.operand[220]
    DIRECTION INPUT ;
    USE SIGNAL ;
    PORT
      LAYER Metal2 ;
        RECT  464.92 999.6 465.32 1000 ;
    END
  END issue_i.operand[220]
  PIN issue_i.operand[221]
    DIRECTION INPUT ;
    USE SIGNAL ;
    PORT
      LAYER Metal2 ;
        RECT  465.88 999.6 466.28 1000 ;
    END
  END issue_i.operand[221]
  PIN issue_i.operand[222]
    DIRECTION INPUT ;
    USE SIGNAL ;
    PORT
      LAYER Metal2 ;
        RECT  466.84 999.6 467.24 1000 ;
    END
  END issue_i.operand[222]
  PIN issue_i.operand[223]
    DIRECTION INPUT ;
    USE SIGNAL ;
    PORT
      LAYER Metal2 ;
        RECT  467.8 999.6 468.2 1000 ;
    END
  END issue_i.operand[223]
  PIN issue_i.operand[224]
    DIRECTION INPUT ;
    USE SIGNAL ;
    PORT
      LAYER Metal2 ;
        RECT  468.76 999.6 469.16 1000 ;
    END
  END issue_i.operand[224]
  PIN issue_i.operand[225]
    DIRECTION INPUT ;
    USE SIGNAL ;
    PORT
      LAYER Metal2 ;
        RECT  469.72 999.6 470.12 1000 ;
    END
  END issue_i.operand[225]
  PIN issue_i.operand[226]
    DIRECTION INPUT ;
    USE SIGNAL ;
    PORT
      LAYER Metal2 ;
        RECT  470.68 999.6 471.08 1000 ;
    END
  END issue_i.operand[226]
  PIN issue_i.operand[227]
    DIRECTION INPUT ;
    USE SIGNAL ;
    PORT
      LAYER Metal2 ;
        RECT  471.64 999.6 472.04 1000 ;
    END
  END issue_i.operand[227]
  PIN issue_i.operand[228]
    DIRECTION INPUT ;
    USE SIGNAL ;
    PORT
      LAYER Metal2 ;
        RECT  472.6 999.6 473 1000 ;
    END
  END issue_i.operand[228]
  PIN issue_i.operand[229]
    DIRECTION INPUT ;
    USE SIGNAL ;
    PORT
      LAYER Metal2 ;
        RECT  473.56 999.6 473.96 1000 ;
    END
  END issue_i.operand[229]
  PIN issue_i.operand[22]
    DIRECTION INPUT ;
    USE SIGNAL ;
    PORT
      LAYER Metal2 ;
        RECT  150.04 999.6 150.44 1000 ;
    END
  END issue_i.operand[22]
  PIN issue_i.operand[230]
    DIRECTION INPUT ;
    USE SIGNAL ;
    PORT
      LAYER Metal2 ;
        RECT  474.52 999.6 474.92 1000 ;
    END
  END issue_i.operand[230]
  PIN issue_i.operand[231]
    DIRECTION INPUT ;
    USE SIGNAL ;
    PORT
      LAYER Metal2 ;
        RECT  475.48 999.6 475.88 1000 ;
    END
  END issue_i.operand[231]
  PIN issue_i.operand[232]
    DIRECTION INPUT ;
    USE SIGNAL ;
    PORT
      LAYER Metal2 ;
        RECT  476.44 999.6 476.84 1000 ;
    END
  END issue_i.operand[232]
  PIN issue_i.operand[233]
    DIRECTION INPUT ;
    USE SIGNAL ;
    PORT
      LAYER Metal2 ;
        RECT  477.4 999.6 477.8 1000 ;
    END
  END issue_i.operand[233]
  PIN issue_i.operand[234]
    DIRECTION INPUT ;
    USE SIGNAL ;
    PORT
      LAYER Metal2 ;
        RECT  478.36 999.6 478.76 1000 ;
    END
  END issue_i.operand[234]
  PIN issue_i.operand[235]
    DIRECTION INPUT ;
    USE SIGNAL ;
    PORT
      LAYER Metal2 ;
        RECT  479.32 999.6 479.72 1000 ;
    END
  END issue_i.operand[235]
  PIN issue_i.operand[236]
    DIRECTION INPUT ;
    USE SIGNAL ;
    PORT
      LAYER Metal2 ;
        RECT  480.28 999.6 480.68 1000 ;
    END
  END issue_i.operand[236]
  PIN issue_i.operand[237]
    DIRECTION INPUT ;
    USE SIGNAL ;
    PORT
      LAYER Metal2 ;
        RECT  481.24 999.6 481.64 1000 ;
    END
  END issue_i.operand[237]
  PIN issue_i.operand[238]
    DIRECTION INPUT ;
    USE SIGNAL ;
    PORT
      LAYER Metal2 ;
        RECT  482.2 999.6 482.6 1000 ;
    END
  END issue_i.operand[238]
  PIN issue_i.operand[239]
    DIRECTION INPUT ;
    USE SIGNAL ;
    PORT
      LAYER Metal2 ;
        RECT  483.16 999.6 483.56 1000 ;
    END
  END issue_i.operand[239]
  PIN issue_i.operand[23]
    DIRECTION INPUT ;
    USE SIGNAL ;
    PORT
      LAYER Metal2 ;
        RECT  152.92 999.6 153.32 1000 ;
    END
  END issue_i.operand[23]
  PIN issue_i.operand[240]
    DIRECTION INPUT ;
    USE SIGNAL ;
    PORT
      LAYER Metal2 ;
        RECT  484.12 999.6 484.52 1000 ;
    END
  END issue_i.operand[240]
  PIN issue_i.operand[241]
    DIRECTION INPUT ;
    USE SIGNAL ;
    PORT
      LAYER Metal2 ;
        RECT  485.08 999.6 485.48 1000 ;
    END
  END issue_i.operand[241]
  PIN issue_i.operand[242]
    DIRECTION INPUT ;
    USE SIGNAL ;
    PORT
      LAYER Metal2 ;
        RECT  486.04 999.6 486.44 1000 ;
    END
  END issue_i.operand[242]
  PIN issue_i.operand[243]
    DIRECTION INPUT ;
    USE SIGNAL ;
    PORT
      LAYER Metal2 ;
        RECT  487 999.6 487.4 1000 ;
    END
  END issue_i.operand[243]
  PIN issue_i.operand[244]
    DIRECTION INPUT ;
    USE SIGNAL ;
    PORT
      LAYER Metal2 ;
        RECT  487.96 999.6 488.36 1000 ;
    END
  END issue_i.operand[244]
  PIN issue_i.operand[245]
    DIRECTION INPUT ;
    USE SIGNAL ;
    PORT
      LAYER Metal2 ;
        RECT  488.92 999.6 489.32 1000 ;
    END
  END issue_i.operand[245]
  PIN issue_i.operand[246]
    DIRECTION INPUT ;
    USE SIGNAL ;
    PORT
      LAYER Metal2 ;
        RECT  489.88 999.6 490.28 1000 ;
    END
  END issue_i.operand[246]
  PIN issue_i.operand[247]
    DIRECTION INPUT ;
    USE SIGNAL ;
    PORT
      LAYER Metal2 ;
        RECT  490.84 999.6 491.24 1000 ;
    END
  END issue_i.operand[247]
  PIN issue_i.operand[248]
    DIRECTION INPUT ;
    USE SIGNAL ;
    PORT
      LAYER Metal2 ;
        RECT  491.8 999.6 492.2 1000 ;
    END
  END issue_i.operand[248]
  PIN issue_i.operand[249]
    DIRECTION INPUT ;
    USE SIGNAL ;
    PORT
      LAYER Metal2 ;
        RECT  492.76 999.6 493.16 1000 ;
    END
  END issue_i.operand[249]
  PIN issue_i.operand[24]
    DIRECTION INPUT ;
    USE SIGNAL ;
    PORT
      LAYER Metal2 ;
        RECT  155.8 999.6 156.2 1000 ;
    END
  END issue_i.operand[24]
  PIN issue_i.operand[250]
    DIRECTION INPUT ;
    USE SIGNAL ;
    PORT
      LAYER Metal2 ;
        RECT  493.72 999.6 494.12 1000 ;
    END
  END issue_i.operand[250]
  PIN issue_i.operand[251]
    DIRECTION INPUT ;
    USE SIGNAL ;
    PORT
      LAYER Metal2 ;
        RECT  494.68 999.6 495.08 1000 ;
    END
  END issue_i.operand[251]
  PIN issue_i.operand[252]
    DIRECTION INPUT ;
    USE SIGNAL ;
    PORT
      LAYER Metal2 ;
        RECT  495.64 999.6 496.04 1000 ;
    END
  END issue_i.operand[252]
  PIN issue_i.operand[253]
    DIRECTION INPUT ;
    USE SIGNAL ;
    PORT
      LAYER Metal2 ;
        RECT  496.6 999.6 497 1000 ;
    END
  END issue_i.operand[253]
  PIN issue_i.operand[254]
    DIRECTION INPUT ;
    USE SIGNAL ;
    PORT
      LAYER Metal2 ;
        RECT  497.56 999.6 497.96 1000 ;
    END
  END issue_i.operand[254]
  PIN issue_i.operand[255]
    DIRECTION INPUT ;
    USE SIGNAL ;
    PORT
      LAYER Metal2 ;
        RECT  498.52 999.6 498.92 1000 ;
    END
  END issue_i.operand[255]
  PIN issue_i.operand[25]
    DIRECTION INPUT ;
    USE SIGNAL ;
    PORT
      LAYER Metal2 ;
        RECT  158.68 999.6 159.08 1000 ;
    END
  END issue_i.operand[25]
  PIN issue_i.operand[26]
    DIRECTION INPUT ;
    USE SIGNAL ;
    PORT
      LAYER Metal2 ;
        RECT  161.56 999.6 161.96 1000 ;
    END
  END issue_i.operand[26]
  PIN issue_i.operand[27]
    DIRECTION INPUT ;
    USE SIGNAL ;
    PORT
      LAYER Metal2 ;
        RECT  164.44 999.6 164.84 1000 ;
    END
  END issue_i.operand[27]
  PIN issue_i.operand[28]
    DIRECTION INPUT ;
    USE SIGNAL ;
    PORT
      LAYER Metal2 ;
        RECT  167.32 999.6 167.72 1000 ;
    END
  END issue_i.operand[28]
  PIN issue_i.operand[29]
    DIRECTION INPUT ;
    USE SIGNAL ;
    PORT
      LAYER Metal2 ;
        RECT  170.2 999.6 170.6 1000 ;
    END
  END issue_i.operand[29]
  PIN issue_i.operand[2]
    DIRECTION INPUT ;
    USE SIGNAL ;
    PORT
      LAYER Metal2 ;
        RECT  91.48 999.6 91.88 1000 ;
    END
  END issue_i.operand[2]
  PIN issue_i.operand[30]
    DIRECTION INPUT ;
    USE SIGNAL ;
    PORT
      LAYER Metal2 ;
        RECT  173.08 999.6 173.48 1000 ;
    END
  END issue_i.operand[30]
  PIN issue_i.operand[31]
    DIRECTION INPUT ;
    USE SIGNAL ;
    PORT
      LAYER Metal2 ;
        RECT  175.96 999.6 176.36 1000 ;
    END
  END issue_i.operand[31]
  PIN issue_i.operand[32]
    DIRECTION INPUT ;
    USE SIGNAL ;
    PORT
      LAYER Metal2 ;
        RECT  177.88 999.6 178.28 1000 ;
    END
  END issue_i.operand[32]
  PIN issue_i.operand[33]
    DIRECTION INPUT ;
    USE SIGNAL ;
    PORT
      LAYER Metal2 ;
        RECT  179.8 999.6 180.2 1000 ;
    END
  END issue_i.operand[33]
  PIN issue_i.operand[34]
    DIRECTION INPUT ;
    USE SIGNAL ;
    PORT
      LAYER Metal2 ;
        RECT  181.72 999.6 182.12 1000 ;
    END
  END issue_i.operand[34]
  PIN issue_i.operand[35]
    DIRECTION INPUT ;
    USE SIGNAL ;
    PORT
      LAYER Metal2 ;
        RECT  183.64 999.6 184.04 1000 ;
    END
  END issue_i.operand[35]
  PIN issue_i.operand[36]
    DIRECTION INPUT ;
    USE SIGNAL ;
    PORT
      LAYER Metal2 ;
        RECT  185.56 999.6 185.96 1000 ;
    END
  END issue_i.operand[36]
  PIN issue_i.operand[37]
    DIRECTION INPUT ;
    USE SIGNAL ;
    PORT
      LAYER Metal2 ;
        RECT  187.48 999.6 187.88 1000 ;
    END
  END issue_i.operand[37]
  PIN issue_i.operand[38]
    DIRECTION INPUT ;
    USE SIGNAL ;
    PORT
      LAYER Metal2 ;
        RECT  189.4 999.6 189.8 1000 ;
    END
  END issue_i.operand[38]
  PIN issue_i.operand[39]
    DIRECTION INPUT ;
    USE SIGNAL ;
    PORT
      LAYER Metal2 ;
        RECT  191.32 999.6 191.72 1000 ;
    END
  END issue_i.operand[39]
  PIN issue_i.operand[3]
    DIRECTION INPUT ;
    USE SIGNAL ;
    PORT
      LAYER Metal2 ;
        RECT  95.32 999.6 95.72 1000 ;
    END
  END issue_i.operand[3]
  PIN issue_i.operand[40]
    DIRECTION INPUT ;
    USE SIGNAL ;
    PORT
      LAYER Metal2 ;
        RECT  193.24 999.6 193.64 1000 ;
    END
  END issue_i.operand[40]
  PIN issue_i.operand[41]
    DIRECTION INPUT ;
    USE SIGNAL ;
    PORT
      LAYER Metal2 ;
        RECT  195.16 999.6 195.56 1000 ;
    END
  END issue_i.operand[41]
  PIN issue_i.operand[42]
    DIRECTION INPUT ;
    USE SIGNAL ;
    PORT
      LAYER Metal2 ;
        RECT  197.08 999.6 197.48 1000 ;
    END
  END issue_i.operand[42]
  PIN issue_i.operand[43]
    DIRECTION INPUT ;
    USE SIGNAL ;
    PORT
      LAYER Metal2 ;
        RECT  199 999.6 199.4 1000 ;
    END
  END issue_i.operand[43]
  PIN issue_i.operand[44]
    DIRECTION INPUT ;
    USE SIGNAL ;
    PORT
      LAYER Metal2 ;
        RECT  200.92 999.6 201.32 1000 ;
    END
  END issue_i.operand[44]
  PIN issue_i.operand[45]
    DIRECTION INPUT ;
    USE SIGNAL ;
    PORT
      LAYER Metal2 ;
        RECT  202.84 999.6 203.24 1000 ;
    END
  END issue_i.operand[45]
  PIN issue_i.operand[46]
    DIRECTION INPUT ;
    USE SIGNAL ;
    PORT
      LAYER Metal2 ;
        RECT  204.76 999.6 205.16 1000 ;
    END
  END issue_i.operand[46]
  PIN issue_i.operand[47]
    DIRECTION INPUT ;
    USE SIGNAL ;
    PORT
      LAYER Metal2 ;
        RECT  206.68 999.6 207.08 1000 ;
    END
  END issue_i.operand[47]
  PIN issue_i.operand[48]
    DIRECTION INPUT ;
    USE SIGNAL ;
    PORT
      LAYER Metal2 ;
        RECT  208.6 999.6 209 1000 ;
    END
  END issue_i.operand[48]
  PIN issue_i.operand[49]
    DIRECTION INPUT ;
    USE SIGNAL ;
    PORT
      LAYER Metal2 ;
        RECT  210.52 999.6 210.92 1000 ;
    END
  END issue_i.operand[49]
  PIN issue_i.operand[4]
    DIRECTION INPUT ;
    USE SIGNAL ;
    PORT
      LAYER Metal2 ;
        RECT  98.2 999.6 98.6 1000 ;
    END
  END issue_i.operand[4]
  PIN issue_i.operand[50]
    DIRECTION INPUT ;
    USE SIGNAL ;
    PORT
      LAYER Metal2 ;
        RECT  212.44 999.6 212.84 1000 ;
    END
  END issue_i.operand[50]
  PIN issue_i.operand[51]
    DIRECTION INPUT ;
    USE SIGNAL ;
    PORT
      LAYER Metal2 ;
        RECT  214.36 999.6 214.76 1000 ;
    END
  END issue_i.operand[51]
  PIN issue_i.operand[52]
    DIRECTION INPUT ;
    USE SIGNAL ;
    PORT
      LAYER Metal2 ;
        RECT  216.28 999.6 216.68 1000 ;
    END
  END issue_i.operand[52]
  PIN issue_i.operand[53]
    DIRECTION INPUT ;
    USE SIGNAL ;
    PORT
      LAYER Metal2 ;
        RECT  218.2 999.6 218.6 1000 ;
    END
  END issue_i.operand[53]
  PIN issue_i.operand[54]
    DIRECTION INPUT ;
    USE SIGNAL ;
    PORT
      LAYER Metal2 ;
        RECT  220.12 999.6 220.52 1000 ;
    END
  END issue_i.operand[54]
  PIN issue_i.operand[55]
    DIRECTION INPUT ;
    USE SIGNAL ;
    PORT
      LAYER Metal2 ;
        RECT  222.04 999.6 222.44 1000 ;
    END
  END issue_i.operand[55]
  PIN issue_i.operand[56]
    DIRECTION INPUT ;
    USE SIGNAL ;
    PORT
      LAYER Metal2 ;
        RECT  223.96 999.6 224.36 1000 ;
    END
  END issue_i.operand[56]
  PIN issue_i.operand[57]
    DIRECTION INPUT ;
    USE SIGNAL ;
    PORT
      LAYER Metal2 ;
        RECT  225.88 999.6 226.28 1000 ;
    END
  END issue_i.operand[57]
  PIN issue_i.operand[58]
    DIRECTION INPUT ;
    USE SIGNAL ;
    PORT
      LAYER Metal2 ;
        RECT  227.8 999.6 228.2 1000 ;
    END
  END issue_i.operand[58]
  PIN issue_i.operand[59]
    DIRECTION INPUT ;
    USE SIGNAL ;
    PORT
      LAYER Metal2 ;
        RECT  229.72 999.6 230.12 1000 ;
    END
  END issue_i.operand[59]
  PIN issue_i.operand[5]
    DIRECTION INPUT ;
    USE SIGNAL ;
    PORT
      LAYER Metal2 ;
        RECT  101.08 999.6 101.48 1000 ;
    END
  END issue_i.operand[5]
  PIN issue_i.operand[60]
    DIRECTION INPUT ;
    USE SIGNAL ;
    PORT
      LAYER Metal2 ;
        RECT  231.64 999.6 232.04 1000 ;
    END
  END issue_i.operand[60]
  PIN issue_i.operand[61]
    DIRECTION INPUT ;
    USE SIGNAL ;
    PORT
      LAYER Metal2 ;
        RECT  233.56 999.6 233.96 1000 ;
    END
  END issue_i.operand[61]
  PIN issue_i.operand[62]
    DIRECTION INPUT ;
    USE SIGNAL ;
    PORT
      LAYER Metal2 ;
        RECT  235.48 999.6 235.88 1000 ;
    END
  END issue_i.operand[62]
  PIN issue_i.operand[63]
    DIRECTION INPUT ;
    USE SIGNAL ;
    PORT
      LAYER Metal2 ;
        RECT  237.4 999.6 237.8 1000 ;
    END
  END issue_i.operand[63]
  PIN issue_i.operand[64]
    DIRECTION INPUT ;
    USE SIGNAL ;
    PORT
      LAYER Metal2 ;
        RECT  239.32 999.6 239.72 1000 ;
    END
  END issue_i.operand[64]
  PIN issue_i.operand[65]
    DIRECTION INPUT ;
    USE SIGNAL ;
    PORT
      LAYER Metal2 ;
        RECT  241.24 999.6 241.64 1000 ;
    END
  END issue_i.operand[65]
  PIN issue_i.operand[66]
    DIRECTION INPUT ;
    USE SIGNAL ;
    PORT
      LAYER Metal2 ;
        RECT  243.16 999.6 243.56 1000 ;
    END
  END issue_i.operand[66]
  PIN issue_i.operand[67]
    DIRECTION INPUT ;
    USE SIGNAL ;
    PORT
      LAYER Metal2 ;
        RECT  245.08 999.6 245.48 1000 ;
    END
  END issue_i.operand[67]
  PIN issue_i.operand[68]
    DIRECTION INPUT ;
    USE SIGNAL ;
    PORT
      LAYER Metal2 ;
        RECT  247 999.6 247.4 1000 ;
    END
  END issue_i.operand[68]
  PIN issue_i.operand[69]
    DIRECTION INPUT ;
    USE SIGNAL ;
    PORT
      LAYER Metal2 ;
        RECT  248.92 999.6 249.32 1000 ;
    END
  END issue_i.operand[69]
  PIN issue_i.operand[6]
    DIRECTION INPUT ;
    USE SIGNAL ;
    PORT
      LAYER Metal2 ;
        RECT  103.96 999.6 104.36 1000 ;
    END
  END issue_i.operand[6]
  PIN issue_i.operand[70]
    DIRECTION INPUT ;
    USE SIGNAL ;
    PORT
      LAYER Metal2 ;
        RECT  250.84 999.6 251.24 1000 ;
    END
  END issue_i.operand[70]
  PIN issue_i.operand[71]
    DIRECTION INPUT ;
    USE SIGNAL ;
    PORT
      LAYER Metal2 ;
        RECT  252.76 999.6 253.16 1000 ;
    END
  END issue_i.operand[71]
  PIN issue_i.operand[72]
    DIRECTION INPUT ;
    USE SIGNAL ;
    PORT
      LAYER Metal2 ;
        RECT  254.68 999.6 255.08 1000 ;
    END
  END issue_i.operand[72]
  PIN issue_i.operand[73]
    DIRECTION INPUT ;
    USE SIGNAL ;
    PORT
      LAYER Metal2 ;
        RECT  256.6 999.6 257 1000 ;
    END
  END issue_i.operand[73]
  PIN issue_i.operand[74]
    DIRECTION INPUT ;
    USE SIGNAL ;
    PORT
      LAYER Metal2 ;
        RECT  258.52 999.6 258.92 1000 ;
    END
  END issue_i.operand[74]
  PIN issue_i.operand[75]
    DIRECTION INPUT ;
    USE SIGNAL ;
    PORT
      LAYER Metal2 ;
        RECT  260.44 999.6 260.84 1000 ;
    END
  END issue_i.operand[75]
  PIN issue_i.operand[76]
    DIRECTION INPUT ;
    USE SIGNAL ;
    PORT
      LAYER Metal2 ;
        RECT  262.36 999.6 262.76 1000 ;
    END
  END issue_i.operand[76]
  PIN issue_i.operand[77]
    DIRECTION INPUT ;
    USE SIGNAL ;
    PORT
      LAYER Metal2 ;
        RECT  264.28 999.6 264.68 1000 ;
    END
  END issue_i.operand[77]
  PIN issue_i.operand[78]
    DIRECTION INPUT ;
    USE SIGNAL ;
    PORT
      LAYER Metal2 ;
        RECT  266.2 999.6 266.6 1000 ;
    END
  END issue_i.operand[78]
  PIN issue_i.operand[79]
    DIRECTION INPUT ;
    USE SIGNAL ;
    PORT
      LAYER Metal2 ;
        RECT  268.12 999.6 268.52 1000 ;
    END
  END issue_i.operand[79]
  PIN issue_i.operand[7]
    DIRECTION INPUT ;
    USE SIGNAL ;
    PORT
      LAYER Metal2 ;
        RECT  106.84 999.6 107.24 1000 ;
    END
  END issue_i.operand[7]
  PIN issue_i.operand[80]
    DIRECTION INPUT ;
    USE SIGNAL ;
    PORT
      LAYER Metal2 ;
        RECT  270.04 999.6 270.44 1000 ;
    END
  END issue_i.operand[80]
  PIN issue_i.operand[81]
    DIRECTION INPUT ;
    USE SIGNAL ;
    PORT
      LAYER Metal2 ;
        RECT  271.96 999.6 272.36 1000 ;
    END
  END issue_i.operand[81]
  PIN issue_i.operand[82]
    DIRECTION INPUT ;
    USE SIGNAL ;
    PORT
      LAYER Metal2 ;
        RECT  273.88 999.6 274.28 1000 ;
    END
  END issue_i.operand[82]
  PIN issue_i.operand[83]
    DIRECTION INPUT ;
    USE SIGNAL ;
    PORT
      LAYER Metal2 ;
        RECT  275.8 999.6 276.2 1000 ;
    END
  END issue_i.operand[83]
  PIN issue_i.operand[84]
    DIRECTION INPUT ;
    USE SIGNAL ;
    PORT
      LAYER Metal2 ;
        RECT  277.72 999.6 278.12 1000 ;
    END
  END issue_i.operand[84]
  PIN issue_i.operand[85]
    DIRECTION INPUT ;
    USE SIGNAL ;
    PORT
      LAYER Metal2 ;
        RECT  279.64 999.6 280.04 1000 ;
    END
  END issue_i.operand[85]
  PIN issue_i.operand[86]
    DIRECTION INPUT ;
    USE SIGNAL ;
    PORT
      LAYER Metal2 ;
        RECT  281.56 999.6 281.96 1000 ;
    END
  END issue_i.operand[86]
  PIN issue_i.operand[87]
    DIRECTION INPUT ;
    USE SIGNAL ;
    PORT
      LAYER Metal2 ;
        RECT  283.48 999.6 283.88 1000 ;
    END
  END issue_i.operand[87]
  PIN issue_i.operand[88]
    DIRECTION INPUT ;
    USE SIGNAL ;
    PORT
      LAYER Metal2 ;
        RECT  285.4 999.6 285.8 1000 ;
    END
  END issue_i.operand[88]
  PIN issue_i.operand[89]
    DIRECTION INPUT ;
    USE SIGNAL ;
    PORT
      LAYER Metal2 ;
        RECT  287.32 999.6 287.72 1000 ;
    END
  END issue_i.operand[89]
  PIN issue_i.operand[8]
    DIRECTION INPUT ;
    USE SIGNAL ;
    PORT
      LAYER Metal2 ;
        RECT  109.72 999.6 110.12 1000 ;
    END
  END issue_i.operand[8]
  PIN issue_i.operand[90]
    DIRECTION INPUT ;
    USE SIGNAL ;
    PORT
      LAYER Metal2 ;
        RECT  289.24 999.6 289.64 1000 ;
    END
  END issue_i.operand[90]
  PIN issue_i.operand[91]
    DIRECTION INPUT ;
    USE SIGNAL ;
    PORT
      LAYER Metal2 ;
        RECT  291.16 999.6 291.56 1000 ;
    END
  END issue_i.operand[91]
  PIN issue_i.operand[92]
    DIRECTION INPUT ;
    USE SIGNAL ;
    PORT
      LAYER Metal2 ;
        RECT  293.08 999.6 293.48 1000 ;
    END
  END issue_i.operand[92]
  PIN issue_i.operand[93]
    DIRECTION INPUT ;
    USE SIGNAL ;
    PORT
      LAYER Metal2 ;
        RECT  295 999.6 295.4 1000 ;
    END
  END issue_i.operand[93]
  PIN issue_i.operand[94]
    DIRECTION INPUT ;
    USE SIGNAL ;
    PORT
      LAYER Metal2 ;
        RECT  296.92 999.6 297.32 1000 ;
    END
  END issue_i.operand[94]
  PIN issue_i.operand[95]
    DIRECTION INPUT ;
    USE SIGNAL ;
    PORT
      LAYER Metal2 ;
        RECT  298.84 999.6 299.24 1000 ;
    END
  END issue_i.operand[95]
  PIN issue_i.operand[96]
    DIRECTION INPUT ;
    USE SIGNAL ;
    PORT
      LAYER Metal2 ;
        RECT  300.76 999.6 301.16 1000 ;
    END
  END issue_i.operand[96]
  PIN issue_i.operand[97]
    DIRECTION INPUT ;
    USE SIGNAL ;
    PORT
      LAYER Metal2 ;
        RECT  302.68 999.6 303.08 1000 ;
    END
  END issue_i.operand[97]
  PIN issue_i.operand[98]
    DIRECTION INPUT ;
    USE SIGNAL ;
    PORT
      LAYER Metal2 ;
        RECT  304.6 999.6 305 1000 ;
    END
  END issue_i.operand[98]
  PIN issue_i.operand[99]
    DIRECTION INPUT ;
    USE SIGNAL ;
    PORT
      LAYER Metal2 ;
        RECT  306.52 999.6 306.92 1000 ;
    END
  END issue_i.operand[99]
  PIN issue_i.operand[9]
    DIRECTION INPUT ;
    USE SIGNAL ;
    PORT
      LAYER Metal2 ;
        RECT  112.6 999.6 113 1000 ;
    END
  END issue_i.operand[9]
  PIN issue_i.operand_count[0]
    DIRECTION INPUT ;
    USE SIGNAL ;
    PORT
      LAYER Metal2 ;
        RECT  82.84 999.6 83.24 1000 ;
    END
  END issue_i.operand_count[0]
  PIN issue_i.operand_count[1]
    DIRECTION INPUT ;
    USE SIGNAL ;
    PORT
      LAYER Metal2 ;
        RECT  87.64 999.6 88.04 1000 ;
    END
  END issue_i.operand_count[1]
  PIN issue_i.operand_count[2]
    DIRECTION INPUT ;
    USE SIGNAL ;
    PORT
      LAYER Metal2 ;
        RECT  92.44 999.6 92.84 1000 ;
    END
  END issue_i.operand_count[2]
  PIN issue_i.slot[0]
    DIRECTION INPUT ;
    USE SIGNAL ;
    PORT
      LAYER Metal2 ;
        RECT  83.8 999.6 84.2 1000 ;
    END
  END issue_i.slot[0]
  PIN issue_i.slot[100]
    DIRECTION INPUT ;
    USE SIGNAL ;
    PORT
      LAYER Metal2 ;
        RECT  309.4 999.6 309.8 1000 ;
    END
  END issue_i.slot[100]
  PIN issue_i.slot[101]
    DIRECTION INPUT ;
    USE SIGNAL ;
    PORT
      LAYER Metal2 ;
        RECT  311.32 999.6 311.72 1000 ;
    END
  END issue_i.slot[101]
  PIN issue_i.slot[102]
    DIRECTION INPUT ;
    USE SIGNAL ;
    PORT
      LAYER Metal2 ;
        RECT  313.24 999.6 313.64 1000 ;
    END
  END issue_i.slot[102]
  PIN issue_i.slot[103]
    DIRECTION INPUT ;
    USE SIGNAL ;
    PORT
      LAYER Metal2 ;
        RECT  315.16 999.6 315.56 1000 ;
    END
  END issue_i.slot[103]
  PIN issue_i.slot[104]
    DIRECTION INPUT ;
    USE SIGNAL ;
    PORT
      LAYER Metal2 ;
        RECT  317.08 999.6 317.48 1000 ;
    END
  END issue_i.slot[104]
  PIN issue_i.slot[105]
    DIRECTION INPUT ;
    USE SIGNAL ;
    PORT
      LAYER Metal2 ;
        RECT  319 999.6 319.4 1000 ;
    END
  END issue_i.slot[105]
  PIN issue_i.slot[106]
    DIRECTION INPUT ;
    USE SIGNAL ;
    PORT
      LAYER Metal2 ;
        RECT  320.92 999.6 321.32 1000 ;
    END
  END issue_i.slot[106]
  PIN issue_i.slot[107]
    DIRECTION INPUT ;
    USE SIGNAL ;
    PORT
      LAYER Metal2 ;
        RECT  322.84 999.6 323.24 1000 ;
    END
  END issue_i.slot[107]
  PIN issue_i.slot[108]
    DIRECTION INPUT ;
    USE SIGNAL ;
    PORT
      LAYER Metal2 ;
        RECT  324.76 999.6 325.16 1000 ;
    END
  END issue_i.slot[108]
  PIN issue_i.slot[109]
    DIRECTION INPUT ;
    USE SIGNAL ;
    PORT
      LAYER Metal2 ;
        RECT  326.68 999.6 327.08 1000 ;
    END
  END issue_i.slot[109]
  PIN issue_i.slot[10]
    DIRECTION INPUT ;
    USE SIGNAL ;
    PORT
      LAYER Metal2 ;
        RECT  116.44 999.6 116.84 1000 ;
    END
  END issue_i.slot[10]
  PIN issue_i.slot[110]
    DIRECTION INPUT ;
    USE SIGNAL ;
    PORT
      LAYER Metal2 ;
        RECT  328.6 999.6 329 1000 ;
    END
  END issue_i.slot[110]
  PIN issue_i.slot[111]
    DIRECTION INPUT ;
    USE SIGNAL ;
    PORT
      LAYER Metal2 ;
        RECT  330.52 999.6 330.92 1000 ;
    END
  END issue_i.slot[111]
  PIN issue_i.slot[112]
    DIRECTION INPUT ;
    USE SIGNAL ;
    PORT
      LAYER Metal2 ;
        RECT  332.44 999.6 332.84 1000 ;
    END
  END issue_i.slot[112]
  PIN issue_i.slot[113]
    DIRECTION INPUT ;
    USE SIGNAL ;
    PORT
      LAYER Metal2 ;
        RECT  334.36 999.6 334.76 1000 ;
    END
  END issue_i.slot[113]
  PIN issue_i.slot[114]
    DIRECTION INPUT ;
    USE SIGNAL ;
    PORT
      LAYER Metal2 ;
        RECT  336.28 999.6 336.68 1000 ;
    END
  END issue_i.slot[114]
  PIN issue_i.slot[115]
    DIRECTION INPUT ;
    USE SIGNAL ;
    PORT
      LAYER Metal2 ;
        RECT  338.2 999.6 338.6 1000 ;
    END
  END issue_i.slot[115]
  PIN issue_i.slot[116]
    DIRECTION INPUT ;
    USE SIGNAL ;
    PORT
      LAYER Metal2 ;
        RECT  340.12 999.6 340.52 1000 ;
    END
  END issue_i.slot[116]
  PIN issue_i.slot[117]
    DIRECTION INPUT ;
    USE SIGNAL ;
    PORT
      LAYER Metal2 ;
        RECT  342.04 999.6 342.44 1000 ;
    END
  END issue_i.slot[117]
  PIN issue_i.slot[118]
    DIRECTION INPUT ;
    USE SIGNAL ;
    PORT
      LAYER Metal2 ;
        RECT  343.96 999.6 344.36 1000 ;
    END
  END issue_i.slot[118]
  PIN issue_i.slot[119]
    DIRECTION INPUT ;
    USE SIGNAL ;
    PORT
      LAYER Metal2 ;
        RECT  345.88 999.6 346.28 1000 ;
    END
  END issue_i.slot[119]
  PIN issue_i.slot[11]
    DIRECTION INPUT ;
    USE SIGNAL ;
    PORT
      LAYER Metal2 ;
        RECT  119.32 999.6 119.72 1000 ;
    END
  END issue_i.slot[11]
  PIN issue_i.slot[120]
    DIRECTION INPUT ;
    USE SIGNAL ;
    PORT
      LAYER Metal2 ;
        RECT  347.8 999.6 348.2 1000 ;
    END
  END issue_i.slot[120]
  PIN issue_i.slot[121]
    DIRECTION INPUT ;
    USE SIGNAL ;
    PORT
      LAYER Metal2 ;
        RECT  349.72 999.6 350.12 1000 ;
    END
  END issue_i.slot[121]
  PIN issue_i.slot[122]
    DIRECTION INPUT ;
    USE SIGNAL ;
    PORT
      LAYER Metal2 ;
        RECT  351.64 999.6 352.04 1000 ;
    END
  END issue_i.slot[122]
  PIN issue_i.slot[123]
    DIRECTION INPUT ;
    USE SIGNAL ;
    PORT
      LAYER Metal2 ;
        RECT  353.56 999.6 353.96 1000 ;
    END
  END issue_i.slot[123]
  PIN issue_i.slot[124]
    DIRECTION INPUT ;
    USE SIGNAL ;
    PORT
      LAYER Metal2 ;
        RECT  355.48 999.6 355.88 1000 ;
    END
  END issue_i.slot[124]
  PIN issue_i.slot[125]
    DIRECTION INPUT ;
    USE SIGNAL ;
    PORT
      LAYER Metal2 ;
        RECT  357.4 999.6 357.8 1000 ;
    END
  END issue_i.slot[125]
  PIN issue_i.slot[126]
    DIRECTION INPUT ;
    USE SIGNAL ;
    PORT
      LAYER Metal2 ;
        RECT  359.32 999.6 359.72 1000 ;
    END
  END issue_i.slot[126]
  PIN issue_i.slot[127]
    DIRECTION INPUT ;
    USE SIGNAL ;
    PORT
      LAYER Metal2 ;
        RECT  361.24 999.6 361.64 1000 ;
    END
  END issue_i.slot[127]
  PIN issue_i.slot[128]
    DIRECTION INPUT ;
    USE SIGNAL ;
    PORT
      LAYER Metal2 ;
        RECT  363.16 999.6 363.56 1000 ;
    END
  END issue_i.slot[128]
  PIN issue_i.slot[129]
    DIRECTION INPUT ;
    USE SIGNAL ;
    PORT
      LAYER Metal2 ;
        RECT  365.08 999.6 365.48 1000 ;
    END
  END issue_i.slot[129]
  PIN issue_i.slot[12]
    DIRECTION INPUT ;
    USE SIGNAL ;
    PORT
      LAYER Metal2 ;
        RECT  122.2 999.6 122.6 1000 ;
    END
  END issue_i.slot[12]
  PIN issue_i.slot[130]
    DIRECTION INPUT ;
    USE SIGNAL ;
    PORT
      LAYER Metal2 ;
        RECT  367 999.6 367.4 1000 ;
    END
  END issue_i.slot[130]
  PIN issue_i.slot[131]
    DIRECTION INPUT ;
    USE SIGNAL ;
    PORT
      LAYER Metal2 ;
        RECT  368.92 999.6 369.32 1000 ;
    END
  END issue_i.slot[131]
  PIN issue_i.slot[132]
    DIRECTION INPUT ;
    USE SIGNAL ;
    PORT
      LAYER Metal2 ;
        RECT  370.84 999.6 371.24 1000 ;
    END
  END issue_i.slot[132]
  PIN issue_i.slot[133]
    DIRECTION INPUT ;
    USE SIGNAL ;
    PORT
      LAYER Metal2 ;
        RECT  372.76 999.6 373.16 1000 ;
    END
  END issue_i.slot[133]
  PIN issue_i.slot[134]
    DIRECTION INPUT ;
    USE SIGNAL ;
    PORT
      LAYER Metal2 ;
        RECT  374.68 999.6 375.08 1000 ;
    END
  END issue_i.slot[134]
  PIN issue_i.slot[135]
    DIRECTION INPUT ;
    USE SIGNAL ;
    PORT
      LAYER Metal2 ;
        RECT  376.6 999.6 377 1000 ;
    END
  END issue_i.slot[135]
  PIN issue_i.slot[136]
    DIRECTION INPUT ;
    USE SIGNAL ;
    PORT
      LAYER Metal2 ;
        RECT  378.52 999.6 378.92 1000 ;
    END
  END issue_i.slot[136]
  PIN issue_i.slot[137]
    DIRECTION INPUT ;
    USE SIGNAL ;
    PORT
      LAYER Metal2 ;
        RECT  380.44 999.6 380.84 1000 ;
    END
  END issue_i.slot[137]
  PIN issue_i.slot[138]
    DIRECTION INPUT ;
    USE SIGNAL ;
    PORT
      LAYER Metal2 ;
        RECT  382.36 999.6 382.76 1000 ;
    END
  END issue_i.slot[138]
  PIN issue_i.slot[139]
    DIRECTION INPUT ;
    USE SIGNAL ;
    PORT
      LAYER Metal2 ;
        RECT  384.28 999.6 384.68 1000 ;
    END
  END issue_i.slot[139]
  PIN issue_i.slot[13]
    DIRECTION INPUT ;
    USE SIGNAL ;
    PORT
      LAYER Metal2 ;
        RECT  125.08 999.6 125.48 1000 ;
    END
  END issue_i.slot[13]
  PIN issue_i.slot[140]
    DIRECTION INPUT ;
    USE SIGNAL ;
    PORT
      LAYER Metal2 ;
        RECT  386.2 999.6 386.6 1000 ;
    END
  END issue_i.slot[140]
  PIN issue_i.slot[141]
    DIRECTION INPUT ;
    USE SIGNAL ;
    PORT
      LAYER Metal2 ;
        RECT  388.12 999.6 388.52 1000 ;
    END
  END issue_i.slot[141]
  PIN issue_i.slot[142]
    DIRECTION INPUT ;
    USE SIGNAL ;
    PORT
      LAYER Metal2 ;
        RECT  390.04 999.6 390.44 1000 ;
    END
  END issue_i.slot[142]
  PIN issue_i.slot[14]
    DIRECTION INPUT ;
    USE SIGNAL ;
    PORT
      LAYER Metal2 ;
        RECT  127.96 999.6 128.36 1000 ;
    END
  END issue_i.slot[14]
  PIN issue_i.slot[15]
    DIRECTION INPUT ;
    USE SIGNAL ;
    PORT
      LAYER Metal2 ;
        RECT  130.84 999.6 131.24 1000 ;
    END
  END issue_i.slot[15]
  PIN issue_i.slot[16]
    DIRECTION INPUT ;
    USE SIGNAL ;
    PORT
      LAYER Metal2 ;
        RECT  133.72 999.6 134.12 1000 ;
    END
  END issue_i.slot[16]
  PIN issue_i.slot[17]
    DIRECTION INPUT ;
    USE SIGNAL ;
    PORT
      LAYER Metal2 ;
        RECT  136.6 999.6 137 1000 ;
    END
  END issue_i.slot[17]
  PIN issue_i.slot[18]
    DIRECTION INPUT ;
    USE SIGNAL ;
    PORT
      LAYER Metal2 ;
        RECT  139.48 999.6 139.88 1000 ;
    END
  END issue_i.slot[18]
  PIN issue_i.slot[19]
    DIRECTION INPUT ;
    USE SIGNAL ;
    PORT
      LAYER Metal2 ;
        RECT  142.36 999.6 142.76 1000 ;
    END
  END issue_i.slot[19]
  PIN issue_i.slot[1]
    DIRECTION INPUT ;
    USE SIGNAL ;
    PORT
      LAYER Metal2 ;
        RECT  88.6 999.6 89 1000 ;
    END
  END issue_i.slot[1]
  PIN issue_i.slot[20]
    DIRECTION INPUT ;
    USE SIGNAL ;
    PORT
      LAYER Metal2 ;
        RECT  145.24 999.6 145.64 1000 ;
    END
  END issue_i.slot[20]
  PIN issue_i.slot[21]
    DIRECTION INPUT ;
    USE SIGNAL ;
    PORT
      LAYER Metal2 ;
        RECT  148.12 999.6 148.52 1000 ;
    END
  END issue_i.slot[21]
  PIN issue_i.slot[22]
    DIRECTION INPUT ;
    USE SIGNAL ;
    PORT
      LAYER Metal2 ;
        RECT  151 999.6 151.4 1000 ;
    END
  END issue_i.slot[22]
  PIN issue_i.slot[23]
    DIRECTION INPUT ;
    USE SIGNAL ;
    PORT
      LAYER Metal2 ;
        RECT  153.88 999.6 154.28 1000 ;
    END
  END issue_i.slot[23]
  PIN issue_i.slot[24]
    DIRECTION INPUT ;
    USE SIGNAL ;
    PORT
      LAYER Metal2 ;
        RECT  156.76 999.6 157.16 1000 ;
    END
  END issue_i.slot[24]
  PIN issue_i.slot[25]
    DIRECTION INPUT ;
    USE SIGNAL ;
    PORT
      LAYER Metal2 ;
        RECT  159.64 999.6 160.04 1000 ;
    END
  END issue_i.slot[25]
  PIN issue_i.slot[26]
    DIRECTION INPUT ;
    USE SIGNAL ;
    PORT
      LAYER Metal2 ;
        RECT  162.52 999.6 162.92 1000 ;
    END
  END issue_i.slot[26]
  PIN issue_i.slot[27]
    DIRECTION INPUT ;
    USE SIGNAL ;
    PORT
      LAYER Metal2 ;
        RECT  165.4 999.6 165.8 1000 ;
    END
  END issue_i.slot[27]
  PIN issue_i.slot[28]
    DIRECTION INPUT ;
    USE SIGNAL ;
    PORT
      LAYER Metal2 ;
        RECT  168.28 999.6 168.68 1000 ;
    END
  END issue_i.slot[28]
  PIN issue_i.slot[29]
    DIRECTION INPUT ;
    USE SIGNAL ;
    PORT
      LAYER Metal2 ;
        RECT  171.16 999.6 171.56 1000 ;
    END
  END issue_i.slot[29]
  PIN issue_i.slot[2]
    DIRECTION INPUT ;
    USE SIGNAL ;
    PORT
      LAYER Metal2 ;
        RECT  93.4 999.6 93.8 1000 ;
    END
  END issue_i.slot[2]
  PIN issue_i.slot[30]
    DIRECTION INPUT ;
    USE SIGNAL ;
    PORT
      LAYER Metal2 ;
        RECT  174.04 999.6 174.44 1000 ;
    END
  END issue_i.slot[30]
  PIN issue_i.slot[31]
    DIRECTION INPUT ;
    USE SIGNAL ;
    PORT
      LAYER Metal2 ;
        RECT  176.92 999.6 177.32 1000 ;
    END
  END issue_i.slot[31]
  PIN issue_i.slot[32]
    DIRECTION INPUT ;
    USE SIGNAL ;
    PORT
      LAYER Metal2 ;
        RECT  178.84 999.6 179.24 1000 ;
    END
  END issue_i.slot[32]
  PIN issue_i.slot[33]
    DIRECTION INPUT ;
    USE SIGNAL ;
    PORT
      LAYER Metal2 ;
        RECT  180.76 999.6 181.16 1000 ;
    END
  END issue_i.slot[33]
  PIN issue_i.slot[34]
    DIRECTION INPUT ;
    USE SIGNAL ;
    PORT
      LAYER Metal2 ;
        RECT  182.68 999.6 183.08 1000 ;
    END
  END issue_i.slot[34]
  PIN issue_i.slot[35]
    DIRECTION INPUT ;
    USE SIGNAL ;
    PORT
      LAYER Metal2 ;
        RECT  184.6 999.6 185 1000 ;
    END
  END issue_i.slot[35]
  PIN issue_i.slot[36]
    DIRECTION INPUT ;
    USE SIGNAL ;
    PORT
      LAYER Metal2 ;
        RECT  186.52 999.6 186.92 1000 ;
    END
  END issue_i.slot[36]
  PIN issue_i.slot[37]
    DIRECTION INPUT ;
    USE SIGNAL ;
    PORT
      LAYER Metal2 ;
        RECT  188.44 999.6 188.84 1000 ;
    END
  END issue_i.slot[37]
  PIN issue_i.slot[38]
    DIRECTION INPUT ;
    USE SIGNAL ;
    PORT
      LAYER Metal2 ;
        RECT  190.36 999.6 190.76 1000 ;
    END
  END issue_i.slot[38]
  PIN issue_i.slot[39]
    DIRECTION INPUT ;
    USE SIGNAL ;
    PORT
      LAYER Metal2 ;
        RECT  192.28 999.6 192.68 1000 ;
    END
  END issue_i.slot[39]
  PIN issue_i.slot[3]
    DIRECTION INPUT ;
    USE SIGNAL ;
    PORT
      LAYER Metal2 ;
        RECT  96.28 999.6 96.68 1000 ;
    END
  END issue_i.slot[3]
  PIN issue_i.slot[40]
    DIRECTION INPUT ;
    USE SIGNAL ;
    PORT
      LAYER Metal2 ;
        RECT  194.2 999.6 194.6 1000 ;
    END
  END issue_i.slot[40]
  PIN issue_i.slot[41]
    DIRECTION INPUT ;
    USE SIGNAL ;
    PORT
      LAYER Metal2 ;
        RECT  196.12 999.6 196.52 1000 ;
    END
  END issue_i.slot[41]
  PIN issue_i.slot[42]
    DIRECTION INPUT ;
    USE SIGNAL ;
    PORT
      LAYER Metal2 ;
        RECT  198.04 999.6 198.44 1000 ;
    END
  END issue_i.slot[42]
  PIN issue_i.slot[43]
    DIRECTION INPUT ;
    USE SIGNAL ;
    PORT
      LAYER Metal2 ;
        RECT  199.96 999.6 200.36 1000 ;
    END
  END issue_i.slot[43]
  PIN issue_i.slot[44]
    DIRECTION INPUT ;
    USE SIGNAL ;
    PORT
      LAYER Metal2 ;
        RECT  201.88 999.6 202.28 1000 ;
    END
  END issue_i.slot[44]
  PIN issue_i.slot[45]
    DIRECTION INPUT ;
    USE SIGNAL ;
    PORT
      LAYER Metal2 ;
        RECT  203.8 999.6 204.2 1000 ;
    END
  END issue_i.slot[45]
  PIN issue_i.slot[46]
    DIRECTION INPUT ;
    USE SIGNAL ;
    PORT
      LAYER Metal2 ;
        RECT  205.72 999.6 206.12 1000 ;
    END
  END issue_i.slot[46]
  PIN issue_i.slot[47]
    DIRECTION INPUT ;
    USE SIGNAL ;
    PORT
      LAYER Metal2 ;
        RECT  207.64 999.6 208.04 1000 ;
    END
  END issue_i.slot[47]
  PIN issue_i.slot[48]
    DIRECTION INPUT ;
    USE SIGNAL ;
    PORT
      LAYER Metal2 ;
        RECT  209.56 999.6 209.96 1000 ;
    END
  END issue_i.slot[48]
  PIN issue_i.slot[49]
    DIRECTION INPUT ;
    USE SIGNAL ;
    PORT
      LAYER Metal2 ;
        RECT  211.48 999.6 211.88 1000 ;
    END
  END issue_i.slot[49]
  PIN issue_i.slot[4]
    DIRECTION INPUT ;
    USE SIGNAL ;
    PORT
      LAYER Metal2 ;
        RECT  99.16 999.6 99.56 1000 ;
    END
  END issue_i.slot[4]
  PIN issue_i.slot[50]
    DIRECTION INPUT ;
    USE SIGNAL ;
    PORT
      LAYER Metal2 ;
        RECT  213.4 999.6 213.8 1000 ;
    END
  END issue_i.slot[50]
  PIN issue_i.slot[51]
    DIRECTION INPUT ;
    USE SIGNAL ;
    PORT
      LAYER Metal2 ;
        RECT  215.32 999.6 215.72 1000 ;
    END
  END issue_i.slot[51]
  PIN issue_i.slot[52]
    DIRECTION INPUT ;
    USE SIGNAL ;
    PORT
      LAYER Metal2 ;
        RECT  217.24 999.6 217.64 1000 ;
    END
  END issue_i.slot[52]
  PIN issue_i.slot[53]
    DIRECTION INPUT ;
    USE SIGNAL ;
    PORT
      LAYER Metal2 ;
        RECT  219.16 999.6 219.56 1000 ;
    END
  END issue_i.slot[53]
  PIN issue_i.slot[54]
    DIRECTION INPUT ;
    USE SIGNAL ;
    PORT
      LAYER Metal2 ;
        RECT  221.08 999.6 221.48 1000 ;
    END
  END issue_i.slot[54]
  PIN issue_i.slot[55]
    DIRECTION INPUT ;
    USE SIGNAL ;
    PORT
      LAYER Metal2 ;
        RECT  223 999.6 223.4 1000 ;
    END
  END issue_i.slot[55]
  PIN issue_i.slot[56]
    DIRECTION INPUT ;
    USE SIGNAL ;
    PORT
      LAYER Metal2 ;
        RECT  224.92 999.6 225.32 1000 ;
    END
  END issue_i.slot[56]
  PIN issue_i.slot[57]
    DIRECTION INPUT ;
    USE SIGNAL ;
    PORT
      LAYER Metal2 ;
        RECT  226.84 999.6 227.24 1000 ;
    END
  END issue_i.slot[57]
  PIN issue_i.slot[58]
    DIRECTION INPUT ;
    USE SIGNAL ;
    PORT
      LAYER Metal2 ;
        RECT  228.76 999.6 229.16 1000 ;
    END
  END issue_i.slot[58]
  PIN issue_i.slot[59]
    DIRECTION INPUT ;
    USE SIGNAL ;
    PORT
      LAYER Metal2 ;
        RECT  230.68 999.6 231.08 1000 ;
    END
  END issue_i.slot[59]
  PIN issue_i.slot[5]
    DIRECTION INPUT ;
    USE SIGNAL ;
    PORT
      LAYER Metal2 ;
        RECT  102.04 999.6 102.44 1000 ;
    END
  END issue_i.slot[5]
  PIN issue_i.slot[60]
    DIRECTION INPUT ;
    USE SIGNAL ;
    PORT
      LAYER Metal2 ;
        RECT  232.6 999.6 233 1000 ;
    END
  END issue_i.slot[60]
  PIN issue_i.slot[61]
    DIRECTION INPUT ;
    USE SIGNAL ;
    PORT
      LAYER Metal2 ;
        RECT  234.52 999.6 234.92 1000 ;
    END
  END issue_i.slot[61]
  PIN issue_i.slot[62]
    DIRECTION INPUT ;
    USE SIGNAL ;
    PORT
      LAYER Metal2 ;
        RECT  236.44 999.6 236.84 1000 ;
    END
  END issue_i.slot[62]
  PIN issue_i.slot[63]
    DIRECTION INPUT ;
    USE SIGNAL ;
    PORT
      LAYER Metal2 ;
        RECT  238.36 999.6 238.76 1000 ;
    END
  END issue_i.slot[63]
  PIN issue_i.slot[64]
    DIRECTION INPUT ;
    USE SIGNAL ;
    PORT
      LAYER Metal2 ;
        RECT  240.28 999.6 240.68 1000 ;
    END
  END issue_i.slot[64]
  PIN issue_i.slot[65]
    DIRECTION INPUT ;
    USE SIGNAL ;
    PORT
      LAYER Metal2 ;
        RECT  242.2 999.6 242.6 1000 ;
    END
  END issue_i.slot[65]
  PIN issue_i.slot[66]
    DIRECTION INPUT ;
    USE SIGNAL ;
    PORT
      LAYER Metal2 ;
        RECT  244.12 999.6 244.52 1000 ;
    END
  END issue_i.slot[66]
  PIN issue_i.slot[67]
    DIRECTION INPUT ;
    USE SIGNAL ;
    PORT
      LAYER Metal2 ;
        RECT  246.04 999.6 246.44 1000 ;
    END
  END issue_i.slot[67]
  PIN issue_i.slot[68]
    DIRECTION INPUT ;
    USE SIGNAL ;
    PORT
      LAYER Metal2 ;
        RECT  247.96 999.6 248.36 1000 ;
    END
  END issue_i.slot[68]
  PIN issue_i.slot[69]
    DIRECTION INPUT ;
    USE SIGNAL ;
    PORT
      LAYER Metal2 ;
        RECT  249.88 999.6 250.28 1000 ;
    END
  END issue_i.slot[69]
  PIN issue_i.slot[6]
    DIRECTION INPUT ;
    USE SIGNAL ;
    PORT
      LAYER Metal2 ;
        RECT  104.92 999.6 105.32 1000 ;
    END
  END issue_i.slot[6]
  PIN issue_i.slot[70]
    DIRECTION INPUT ;
    USE SIGNAL ;
    PORT
      LAYER Metal2 ;
        RECT  251.8 999.6 252.2 1000 ;
    END
  END issue_i.slot[70]
  PIN issue_i.slot[71]
    DIRECTION INPUT ;
    USE SIGNAL ;
    PORT
      LAYER Metal2 ;
        RECT  253.72 999.6 254.12 1000 ;
    END
  END issue_i.slot[71]
  PIN issue_i.slot[72]
    DIRECTION INPUT ;
    USE SIGNAL ;
    PORT
      LAYER Metal2 ;
        RECT  255.64 999.6 256.04 1000 ;
    END
  END issue_i.slot[72]
  PIN issue_i.slot[73]
    DIRECTION INPUT ;
    USE SIGNAL ;
    PORT
      LAYER Metal2 ;
        RECT  257.56 999.6 257.96 1000 ;
    END
  END issue_i.slot[73]
  PIN issue_i.slot[74]
    DIRECTION INPUT ;
    USE SIGNAL ;
    PORT
      LAYER Metal2 ;
        RECT  259.48 999.6 259.88 1000 ;
    END
  END issue_i.slot[74]
  PIN issue_i.slot[75]
    DIRECTION INPUT ;
    USE SIGNAL ;
    PORT
      LAYER Metal2 ;
        RECT  261.4 999.6 261.8 1000 ;
    END
  END issue_i.slot[75]
  PIN issue_i.slot[76]
    DIRECTION INPUT ;
    USE SIGNAL ;
    PORT
      LAYER Metal2 ;
        RECT  263.32 999.6 263.72 1000 ;
    END
  END issue_i.slot[76]
  PIN issue_i.slot[77]
    DIRECTION INPUT ;
    USE SIGNAL ;
    PORT
      LAYER Metal2 ;
        RECT  265.24 999.6 265.64 1000 ;
    END
  END issue_i.slot[77]
  PIN issue_i.slot[78]
    DIRECTION INPUT ;
    USE SIGNAL ;
    PORT
      LAYER Metal2 ;
        RECT  267.16 999.6 267.56 1000 ;
    END
  END issue_i.slot[78]
  PIN issue_i.slot[79]
    DIRECTION INPUT ;
    USE SIGNAL ;
    PORT
      LAYER Metal2 ;
        RECT  269.08 999.6 269.48 1000 ;
    END
  END issue_i.slot[79]
  PIN issue_i.slot[7]
    DIRECTION INPUT ;
    USE SIGNAL ;
    PORT
      LAYER Metal2 ;
        RECT  107.8 999.6 108.2 1000 ;
    END
  END issue_i.slot[7]
  PIN issue_i.slot[80]
    DIRECTION INPUT ;
    USE SIGNAL ;
    PORT
      LAYER Metal2 ;
        RECT  271 999.6 271.4 1000 ;
    END
  END issue_i.slot[80]
  PIN issue_i.slot[81]
    DIRECTION INPUT ;
    USE SIGNAL ;
    PORT
      LAYER Metal2 ;
        RECT  272.92 999.6 273.32 1000 ;
    END
  END issue_i.slot[81]
  PIN issue_i.slot[82]
    DIRECTION INPUT ;
    USE SIGNAL ;
    PORT
      LAYER Metal2 ;
        RECT  274.84 999.6 275.24 1000 ;
    END
  END issue_i.slot[82]
  PIN issue_i.slot[83]
    DIRECTION INPUT ;
    USE SIGNAL ;
    PORT
      LAYER Metal2 ;
        RECT  276.76 999.6 277.16 1000 ;
    END
  END issue_i.slot[83]
  PIN issue_i.slot[84]
    DIRECTION INPUT ;
    USE SIGNAL ;
    PORT
      LAYER Metal2 ;
        RECT  278.68 999.6 279.08 1000 ;
    END
  END issue_i.slot[84]
  PIN issue_i.slot[85]
    DIRECTION INPUT ;
    USE SIGNAL ;
    PORT
      LAYER Metal2 ;
        RECT  280.6 999.6 281 1000 ;
    END
  END issue_i.slot[85]
  PIN issue_i.slot[86]
    DIRECTION INPUT ;
    USE SIGNAL ;
    PORT
      LAYER Metal2 ;
        RECT  282.52 999.6 282.92 1000 ;
    END
  END issue_i.slot[86]
  PIN issue_i.slot[87]
    DIRECTION INPUT ;
    USE SIGNAL ;
    PORT
      LAYER Metal2 ;
        RECT  284.44 999.6 284.84 1000 ;
    END
  END issue_i.slot[87]
  PIN issue_i.slot[88]
    DIRECTION INPUT ;
    USE SIGNAL ;
    PORT
      LAYER Metal2 ;
        RECT  286.36 999.6 286.76 1000 ;
    END
  END issue_i.slot[88]
  PIN issue_i.slot[89]
    DIRECTION INPUT ;
    USE SIGNAL ;
    PORT
      LAYER Metal2 ;
        RECT  288.28 999.6 288.68 1000 ;
    END
  END issue_i.slot[89]
  PIN issue_i.slot[8]
    DIRECTION INPUT ;
    USE SIGNAL ;
    PORT
      LAYER Metal2 ;
        RECT  110.68 999.6 111.08 1000 ;
    END
  END issue_i.slot[8]
  PIN issue_i.slot[90]
    DIRECTION INPUT ;
    USE SIGNAL ;
    PORT
      LAYER Metal2 ;
        RECT  290.2 999.6 290.6 1000 ;
    END
  END issue_i.slot[90]
  PIN issue_i.slot[91]
    DIRECTION INPUT ;
    USE SIGNAL ;
    PORT
      LAYER Metal2 ;
        RECT  292.12 999.6 292.52 1000 ;
    END
  END issue_i.slot[91]
  PIN issue_i.slot[92]
    DIRECTION INPUT ;
    USE SIGNAL ;
    PORT
      LAYER Metal2 ;
        RECT  294.04 999.6 294.44 1000 ;
    END
  END issue_i.slot[92]
  PIN issue_i.slot[93]
    DIRECTION INPUT ;
    USE SIGNAL ;
    PORT
      LAYER Metal2 ;
        RECT  295.96 999.6 296.36 1000 ;
    END
  END issue_i.slot[93]
  PIN issue_i.slot[94]
    DIRECTION INPUT ;
    USE SIGNAL ;
    PORT
      LAYER Metal2 ;
        RECT  297.88 999.6 298.28 1000 ;
    END
  END issue_i.slot[94]
  PIN issue_i.slot[95]
    DIRECTION INPUT ;
    USE SIGNAL ;
    PORT
      LAYER Metal2 ;
        RECT  299.8 999.6 300.2 1000 ;
    END
  END issue_i.slot[95]
  PIN issue_i.slot[96]
    DIRECTION INPUT ;
    USE SIGNAL ;
    PORT
      LAYER Metal2 ;
        RECT  301.72 999.6 302.12 1000 ;
    END
  END issue_i.slot[96]
  PIN issue_i.slot[97]
    DIRECTION INPUT ;
    USE SIGNAL ;
    PORT
      LAYER Metal2 ;
        RECT  303.64 999.6 304.04 1000 ;
    END
  END issue_i.slot[97]
  PIN issue_i.slot[98]
    DIRECTION INPUT ;
    USE SIGNAL ;
    PORT
      LAYER Metal2 ;
        RECT  305.56 999.6 305.96 1000 ;
    END
  END issue_i.slot[98]
  PIN issue_i.slot[99]
    DIRECTION INPUT ;
    USE SIGNAL ;
    PORT
      LAYER Metal2 ;
        RECT  307.48 999.6 307.88 1000 ;
    END
  END issue_i.slot[99]
  PIN issue_i.slot[9]
    DIRECTION INPUT ;
    USE SIGNAL ;
    PORT
      LAYER Metal2 ;
        RECT  113.56 999.6 113.96 1000 ;
    END
  END issue_i.slot[9]
  PIN issue_ready_o
    DIRECTION OUTPUT ;
    USE SIGNAL ;
    PORT
      LAYER Metal2 ;
        RECT  77.08 999.6 77.48 1000 ;
    END
  END issue_ready_o
  PIN issue_valid_i
    DIRECTION INPUT ;
    USE SIGNAL ;
    PORT
      LAYER Metal2 ;
        RECT  76.12 999.6 76.52 1000 ;
    END
  END issue_valid_i
  PIN limits_i.lim_csp[0]
    DIRECTION INPUT ;
    USE SIGNAL ;
    PORT
      LAYER Metal3 ;
        RECT  899.6 300.94 900 301.34 ;
    END
  END limits_i.lim_csp[0]
  PIN limits_i.lim_csp[10]
    DIRECTION INPUT ;
    USE SIGNAL ;
    PORT
      LAYER Metal3 ;
        RECT  899.6 334.54 900 334.94 ;
    END
  END limits_i.lim_csp[10]
  PIN limits_i.lim_csp[11]
    DIRECTION INPUT ;
    USE SIGNAL ;
    PORT
      LAYER Metal3 ;
        RECT  899.6 337.9 900 338.3 ;
    END
  END limits_i.lim_csp[11]
  PIN limits_i.lim_csp[12]
    DIRECTION INPUT ;
    USE SIGNAL ;
    PORT
      LAYER Metal3 ;
        RECT  899.6 341.26 900 341.66 ;
    END
  END limits_i.lim_csp[12]
  PIN limits_i.lim_csp[13]
    DIRECTION INPUT ;
    USE SIGNAL ;
    PORT
      LAYER Metal3 ;
        RECT  899.6 344.62 900 345.02 ;
    END
  END limits_i.lim_csp[13]
  PIN limits_i.lim_csp[14]
    DIRECTION INPUT ;
    USE SIGNAL ;
    PORT
      LAYER Metal3 ;
        RECT  899.6 347.98 900 348.38 ;
    END
  END limits_i.lim_csp[14]
  PIN limits_i.lim_csp[15]
    DIRECTION INPUT ;
    USE SIGNAL ;
    PORT
      LAYER Metal3 ;
        RECT  899.6 351.34 900 351.74 ;
    END
  END limits_i.lim_csp[15]
  PIN limits_i.lim_csp[16]
    DIRECTION INPUT ;
    USE SIGNAL ;
    PORT
      LAYER Metal3 ;
        RECT  899.6 354.7 900 355.1 ;
    END
  END limits_i.lim_csp[16]
  PIN limits_i.lim_csp[17]
    DIRECTION INPUT ;
    USE SIGNAL ;
    PORT
      LAYER Metal3 ;
        RECT  899.6 358.06 900 358.46 ;
    END
  END limits_i.lim_csp[17]
  PIN limits_i.lim_csp[18]
    DIRECTION INPUT ;
    USE SIGNAL ;
    PORT
      LAYER Metal3 ;
        RECT  899.6 361.42 900 361.82 ;
    END
  END limits_i.lim_csp[18]
  PIN limits_i.lim_csp[19]
    DIRECTION INPUT ;
    USE SIGNAL ;
    PORT
      LAYER Metal3 ;
        RECT  899.6 364.78 900 365.18 ;
    END
  END limits_i.lim_csp[19]
  PIN limits_i.lim_csp[1]
    DIRECTION INPUT ;
    USE SIGNAL ;
    PORT
      LAYER Metal3 ;
        RECT  899.6 304.3 900 304.7 ;
    END
  END limits_i.lim_csp[1]
  PIN limits_i.lim_csp[20]
    DIRECTION INPUT ;
    USE SIGNAL ;
    PORT
      LAYER Metal3 ;
        RECT  899.6 368.14 900 368.54 ;
    END
  END limits_i.lim_csp[20]
  PIN limits_i.lim_csp[21]
    DIRECTION INPUT ;
    USE SIGNAL ;
    PORT
      LAYER Metal3 ;
        RECT  899.6 371.5 900 371.9 ;
    END
  END limits_i.lim_csp[21]
  PIN limits_i.lim_csp[22]
    DIRECTION INPUT ;
    USE SIGNAL ;
    PORT
      LAYER Metal3 ;
        RECT  899.6 374.86 900 375.26 ;
    END
  END limits_i.lim_csp[22]
  PIN limits_i.lim_csp[23]
    DIRECTION INPUT ;
    USE SIGNAL ;
    PORT
      LAYER Metal3 ;
        RECT  899.6 378.22 900 378.62 ;
    END
  END limits_i.lim_csp[23]
  PIN limits_i.lim_csp[24]
    DIRECTION INPUT ;
    USE SIGNAL ;
    PORT
      LAYER Metal3 ;
        RECT  899.6 381.58 900 381.98 ;
    END
  END limits_i.lim_csp[24]
  PIN limits_i.lim_csp[25]
    DIRECTION INPUT ;
    USE SIGNAL ;
    PORT
      LAYER Metal3 ;
        RECT  899.6 384.94 900 385.34 ;
    END
  END limits_i.lim_csp[25]
  PIN limits_i.lim_csp[26]
    DIRECTION INPUT ;
    USE SIGNAL ;
    PORT
      LAYER Metal3 ;
        RECT  899.6 388.3 900 388.7 ;
    END
  END limits_i.lim_csp[26]
  PIN limits_i.lim_csp[27]
    DIRECTION INPUT ;
    USE SIGNAL ;
    PORT
      LAYER Metal3 ;
        RECT  899.6 391.66 900 392.06 ;
    END
  END limits_i.lim_csp[27]
  PIN limits_i.lim_csp[28]
    DIRECTION INPUT ;
    USE SIGNAL ;
    PORT
      LAYER Metal3 ;
        RECT  899.6 395.02 900 395.42 ;
    END
  END limits_i.lim_csp[28]
  PIN limits_i.lim_csp[29]
    DIRECTION INPUT ;
    USE SIGNAL ;
    PORT
      LAYER Metal3 ;
        RECT  899.6 398.38 900 398.78 ;
    END
  END limits_i.lim_csp[29]
  PIN limits_i.lim_csp[2]
    DIRECTION INPUT ;
    USE SIGNAL ;
    PORT
      LAYER Metal3 ;
        RECT  899.6 307.66 900 308.06 ;
    END
  END limits_i.lim_csp[2]
  PIN limits_i.lim_csp[30]
    DIRECTION INPUT ;
    USE SIGNAL ;
    PORT
      LAYER Metal3 ;
        RECT  899.6 401.74 900 402.14 ;
    END
  END limits_i.lim_csp[30]
  PIN limits_i.lim_csp[31]
    DIRECTION INPUT ;
    USE SIGNAL ;
    PORT
      LAYER Metal3 ;
        RECT  899.6 405.1 900 405.5 ;
    END
  END limits_i.lim_csp[31]
  PIN limits_i.lim_csp[32]
    DIRECTION INPUT ;
    USE SIGNAL ;
    PORT
      LAYER Metal3 ;
        RECT  899.6 408.46 900 408.86 ;
    END
  END limits_i.lim_csp[32]
  PIN limits_i.lim_csp[33]
    DIRECTION INPUT ;
    USE SIGNAL ;
    PORT
      LAYER Metal3 ;
        RECT  899.6 411.82 900 412.22 ;
    END
  END limits_i.lim_csp[33]
  PIN limits_i.lim_csp[34]
    DIRECTION INPUT ;
    USE SIGNAL ;
    PORT
      LAYER Metal3 ;
        RECT  899.6 415.18 900 415.58 ;
    END
  END limits_i.lim_csp[34]
  PIN limits_i.lim_csp[35]
    DIRECTION INPUT ;
    USE SIGNAL ;
    PORT
      LAYER Metal3 ;
        RECT  899.6 418.54 900 418.94 ;
    END
  END limits_i.lim_csp[35]
  PIN limits_i.lim_csp[36]
    DIRECTION INPUT ;
    USE SIGNAL ;
    PORT
      LAYER Metal3 ;
        RECT  899.6 421.9 900 422.3 ;
    END
  END limits_i.lim_csp[36]
  PIN limits_i.lim_csp[37]
    DIRECTION INPUT ;
    USE SIGNAL ;
    PORT
      LAYER Metal3 ;
        RECT  899.6 425.26 900 425.66 ;
    END
  END limits_i.lim_csp[37]
  PIN limits_i.lim_csp[38]
    DIRECTION INPUT ;
    USE SIGNAL ;
    PORT
      LAYER Metal3 ;
        RECT  899.6 428.62 900 429.02 ;
    END
  END limits_i.lim_csp[38]
  PIN limits_i.lim_csp[39]
    DIRECTION INPUT ;
    USE SIGNAL ;
    PORT
      LAYER Metal3 ;
        RECT  899.6 431.98 900 432.38 ;
    END
  END limits_i.lim_csp[39]
  PIN limits_i.lim_csp[3]
    DIRECTION INPUT ;
    USE SIGNAL ;
    PORT
      LAYER Metal3 ;
        RECT  899.6 311.02 900 311.42 ;
    END
  END limits_i.lim_csp[3]
  PIN limits_i.lim_csp[40]
    DIRECTION INPUT ;
    USE SIGNAL ;
    PORT
      LAYER Metal3 ;
        RECT  899.6 435.34 900 435.74 ;
    END
  END limits_i.lim_csp[40]
  PIN limits_i.lim_csp[41]
    DIRECTION INPUT ;
    USE SIGNAL ;
    PORT
      LAYER Metal3 ;
        RECT  899.6 438.7 900 439.1 ;
    END
  END limits_i.lim_csp[41]
  PIN limits_i.lim_csp[42]
    DIRECTION INPUT ;
    USE SIGNAL ;
    PORT
      LAYER Metal3 ;
        RECT  899.6 442.06 900 442.46 ;
    END
  END limits_i.lim_csp[42]
  PIN limits_i.lim_csp[43]
    DIRECTION INPUT ;
    USE SIGNAL ;
    PORT
      LAYER Metal3 ;
        RECT  899.6 445.42 900 445.82 ;
    END
  END limits_i.lim_csp[43]
  PIN limits_i.lim_csp[44]
    DIRECTION INPUT ;
    USE SIGNAL ;
    PORT
      LAYER Metal3 ;
        RECT  899.6 448.78 900 449.18 ;
    END
  END limits_i.lim_csp[44]
  PIN limits_i.lim_csp[45]
    DIRECTION INPUT ;
    USE SIGNAL ;
    PORT
      LAYER Metal3 ;
        RECT  899.6 452.14 900 452.54 ;
    END
  END limits_i.lim_csp[45]
  PIN limits_i.lim_csp[46]
    DIRECTION INPUT ;
    USE SIGNAL ;
    PORT
      LAYER Metal3 ;
        RECT  899.6 455.5 900 455.9 ;
    END
  END limits_i.lim_csp[46]
  PIN limits_i.lim_csp[47]
    DIRECTION INPUT ;
    USE SIGNAL ;
    PORT
      LAYER Metal3 ;
        RECT  899.6 458.86 900 459.26 ;
    END
  END limits_i.lim_csp[47]
  PIN limits_i.lim_csp[48]
    DIRECTION INPUT ;
    USE SIGNAL ;
    PORT
      LAYER Metal3 ;
        RECT  899.6 462.22 900 462.62 ;
    END
  END limits_i.lim_csp[48]
  PIN limits_i.lim_csp[49]
    DIRECTION INPUT ;
    USE SIGNAL ;
    PORT
      LAYER Metal3 ;
        RECT  899.6 465.58 900 465.98 ;
    END
  END limits_i.lim_csp[49]
  PIN limits_i.lim_csp[4]
    DIRECTION INPUT ;
    USE SIGNAL ;
    PORT
      LAYER Metal3 ;
        RECT  899.6 314.38 900 314.78 ;
    END
  END limits_i.lim_csp[4]
  PIN limits_i.lim_csp[50]
    DIRECTION INPUT ;
    USE SIGNAL ;
    PORT
      LAYER Metal3 ;
        RECT  899.6 468.94 900 469.34 ;
    END
  END limits_i.lim_csp[50]
  PIN limits_i.lim_csp[51]
    DIRECTION INPUT ;
    USE SIGNAL ;
    PORT
      LAYER Metal3 ;
        RECT  899.6 472.3 900 472.7 ;
    END
  END limits_i.lim_csp[51]
  PIN limits_i.lim_csp[52]
    DIRECTION INPUT ;
    USE SIGNAL ;
    PORT
      LAYER Metal3 ;
        RECT  899.6 475.66 900 476.06 ;
    END
  END limits_i.lim_csp[52]
  PIN limits_i.lim_csp[53]
    DIRECTION INPUT ;
    USE SIGNAL ;
    PORT
      LAYER Metal3 ;
        RECT  899.6 479.02 900 479.42 ;
    END
  END limits_i.lim_csp[53]
  PIN limits_i.lim_csp[54]
    DIRECTION INPUT ;
    USE SIGNAL ;
    PORT
      LAYER Metal3 ;
        RECT  899.6 482.38 900 482.78 ;
    END
  END limits_i.lim_csp[54]
  PIN limits_i.lim_csp[55]
    DIRECTION INPUT ;
    USE SIGNAL ;
    PORT
      LAYER Metal3 ;
        RECT  899.6 485.74 900 486.14 ;
    END
  END limits_i.lim_csp[55]
  PIN limits_i.lim_csp[56]
    DIRECTION INPUT ;
    USE SIGNAL ;
    PORT
      LAYER Metal3 ;
        RECT  899.6 489.1 900 489.5 ;
    END
  END limits_i.lim_csp[56]
  PIN limits_i.lim_csp[57]
    DIRECTION INPUT ;
    USE SIGNAL ;
    PORT
      LAYER Metal3 ;
        RECT  899.6 492.46 900 492.86 ;
    END
  END limits_i.lim_csp[57]
  PIN limits_i.lim_csp[58]
    DIRECTION INPUT ;
    USE SIGNAL ;
    PORT
      LAYER Metal3 ;
        RECT  899.6 495.82 900 496.22 ;
    END
  END limits_i.lim_csp[58]
  PIN limits_i.lim_csp[59]
    DIRECTION INPUT ;
    USE SIGNAL ;
    PORT
      LAYER Metal3 ;
        RECT  899.6 499.18 900 499.58 ;
    END
  END limits_i.lim_csp[59]
  PIN limits_i.lim_csp[5]
    DIRECTION INPUT ;
    USE SIGNAL ;
    PORT
      LAYER Metal3 ;
        RECT  899.6 317.74 900 318.14 ;
    END
  END limits_i.lim_csp[5]
  PIN limits_i.lim_csp[60]
    DIRECTION INPUT ;
    USE SIGNAL ;
    PORT
      LAYER Metal3 ;
        RECT  899.6 502.54 900 502.94 ;
    END
  END limits_i.lim_csp[60]
  PIN limits_i.lim_csp[61]
    DIRECTION INPUT ;
    USE SIGNAL ;
    PORT
      LAYER Metal3 ;
        RECT  899.6 505.9 900 506.3 ;
    END
  END limits_i.lim_csp[61]
  PIN limits_i.lim_csp[62]
    DIRECTION INPUT ;
    USE SIGNAL ;
    PORT
      LAYER Metal3 ;
        RECT  899.6 509.26 900 509.66 ;
    END
  END limits_i.lim_csp[62]
  PIN limits_i.lim_csp[63]
    DIRECTION INPUT ;
    USE SIGNAL ;
    PORT
      LAYER Metal3 ;
        RECT  899.6 512.62 900 513.02 ;
    END
  END limits_i.lim_csp[63]
  PIN limits_i.lim_csp[6]
    DIRECTION INPUT ;
    USE SIGNAL ;
    PORT
      LAYER Metal3 ;
        RECT  899.6 321.1 900 321.5 ;
    END
  END limits_i.lim_csp[6]
  PIN limits_i.lim_csp[7]
    DIRECTION INPUT ;
    USE SIGNAL ;
    PORT
      LAYER Metal3 ;
        RECT  899.6 324.46 900 324.86 ;
    END
  END limits_i.lim_csp[7]
  PIN limits_i.lim_csp[8]
    DIRECTION INPUT ;
    USE SIGNAL ;
    PORT
      LAYER Metal3 ;
        RECT  899.6 327.82 900 328.22 ;
    END
  END limits_i.lim_csp[8]
  PIN limits_i.lim_csp[9]
    DIRECTION INPUT ;
    USE SIGNAL ;
    PORT
      LAYER Metal3 ;
        RECT  899.6 331.18 900 331.58 ;
    END
  END limits_i.lim_csp[9]
  PIN limits_i.lim_dsp[0]
    DIRECTION INPUT ;
    USE SIGNAL ;
    PORT
      LAYER Metal3 ;
        RECT  899.6 301.78 900 302.18 ;
    END
  END limits_i.lim_dsp[0]
  PIN limits_i.lim_dsp[10]
    DIRECTION INPUT ;
    USE SIGNAL ;
    PORT
      LAYER Metal3 ;
        RECT  899.6 335.38 900 335.78 ;
    END
  END limits_i.lim_dsp[10]
  PIN limits_i.lim_dsp[11]
    DIRECTION INPUT ;
    USE SIGNAL ;
    PORT
      LAYER Metal3 ;
        RECT  899.6 338.74 900 339.14 ;
    END
  END limits_i.lim_dsp[11]
  PIN limits_i.lim_dsp[12]
    DIRECTION INPUT ;
    USE SIGNAL ;
    PORT
      LAYER Metal3 ;
        RECT  899.6 342.1 900 342.5 ;
    END
  END limits_i.lim_dsp[12]
  PIN limits_i.lim_dsp[13]
    DIRECTION INPUT ;
    USE SIGNAL ;
    PORT
      LAYER Metal3 ;
        RECT  899.6 345.46 900 345.86 ;
    END
  END limits_i.lim_dsp[13]
  PIN limits_i.lim_dsp[14]
    DIRECTION INPUT ;
    USE SIGNAL ;
    PORT
      LAYER Metal3 ;
        RECT  899.6 348.82 900 349.22 ;
    END
  END limits_i.lim_dsp[14]
  PIN limits_i.lim_dsp[15]
    DIRECTION INPUT ;
    USE SIGNAL ;
    PORT
      LAYER Metal3 ;
        RECT  899.6 352.18 900 352.58 ;
    END
  END limits_i.lim_dsp[15]
  PIN limits_i.lim_dsp[16]
    DIRECTION INPUT ;
    USE SIGNAL ;
    PORT
      LAYER Metal3 ;
        RECT  899.6 355.54 900 355.94 ;
    END
  END limits_i.lim_dsp[16]
  PIN limits_i.lim_dsp[17]
    DIRECTION INPUT ;
    USE SIGNAL ;
    PORT
      LAYER Metal3 ;
        RECT  899.6 358.9 900 359.3 ;
    END
  END limits_i.lim_dsp[17]
  PIN limits_i.lim_dsp[18]
    DIRECTION INPUT ;
    USE SIGNAL ;
    PORT
      LAYER Metal3 ;
        RECT  899.6 362.26 900 362.66 ;
    END
  END limits_i.lim_dsp[18]
  PIN limits_i.lim_dsp[19]
    DIRECTION INPUT ;
    USE SIGNAL ;
    PORT
      LAYER Metal3 ;
        RECT  899.6 365.62 900 366.02 ;
    END
  END limits_i.lim_dsp[19]
  PIN limits_i.lim_dsp[1]
    DIRECTION INPUT ;
    USE SIGNAL ;
    PORT
      LAYER Metal3 ;
        RECT  899.6 305.14 900 305.54 ;
    END
  END limits_i.lim_dsp[1]
  PIN limits_i.lim_dsp[20]
    DIRECTION INPUT ;
    USE SIGNAL ;
    PORT
      LAYER Metal3 ;
        RECT  899.6 368.98 900 369.38 ;
    END
  END limits_i.lim_dsp[20]
  PIN limits_i.lim_dsp[21]
    DIRECTION INPUT ;
    USE SIGNAL ;
    PORT
      LAYER Metal3 ;
        RECT  899.6 372.34 900 372.74 ;
    END
  END limits_i.lim_dsp[21]
  PIN limits_i.lim_dsp[22]
    DIRECTION INPUT ;
    USE SIGNAL ;
    PORT
      LAYER Metal3 ;
        RECT  899.6 375.7 900 376.1 ;
    END
  END limits_i.lim_dsp[22]
  PIN limits_i.lim_dsp[23]
    DIRECTION INPUT ;
    USE SIGNAL ;
    PORT
      LAYER Metal3 ;
        RECT  899.6 379.06 900 379.46 ;
    END
  END limits_i.lim_dsp[23]
  PIN limits_i.lim_dsp[24]
    DIRECTION INPUT ;
    USE SIGNAL ;
    PORT
      LAYER Metal3 ;
        RECT  899.6 382.42 900 382.82 ;
    END
  END limits_i.lim_dsp[24]
  PIN limits_i.lim_dsp[25]
    DIRECTION INPUT ;
    USE SIGNAL ;
    PORT
      LAYER Metal3 ;
        RECT  899.6 385.78 900 386.18 ;
    END
  END limits_i.lim_dsp[25]
  PIN limits_i.lim_dsp[26]
    DIRECTION INPUT ;
    USE SIGNAL ;
    PORT
      LAYER Metal3 ;
        RECT  899.6 389.14 900 389.54 ;
    END
  END limits_i.lim_dsp[26]
  PIN limits_i.lim_dsp[27]
    DIRECTION INPUT ;
    USE SIGNAL ;
    PORT
      LAYER Metal3 ;
        RECT  899.6 392.5 900 392.9 ;
    END
  END limits_i.lim_dsp[27]
  PIN limits_i.lim_dsp[28]
    DIRECTION INPUT ;
    USE SIGNAL ;
    PORT
      LAYER Metal3 ;
        RECT  899.6 395.86 900 396.26 ;
    END
  END limits_i.lim_dsp[28]
  PIN limits_i.lim_dsp[29]
    DIRECTION INPUT ;
    USE SIGNAL ;
    PORT
      LAYER Metal3 ;
        RECT  899.6 399.22 900 399.62 ;
    END
  END limits_i.lim_dsp[29]
  PIN limits_i.lim_dsp[2]
    DIRECTION INPUT ;
    USE SIGNAL ;
    PORT
      LAYER Metal3 ;
        RECT  899.6 308.5 900 308.9 ;
    END
  END limits_i.lim_dsp[2]
  PIN limits_i.lim_dsp[30]
    DIRECTION INPUT ;
    USE SIGNAL ;
    PORT
      LAYER Metal3 ;
        RECT  899.6 402.58 900 402.98 ;
    END
  END limits_i.lim_dsp[30]
  PIN limits_i.lim_dsp[31]
    DIRECTION INPUT ;
    USE SIGNAL ;
    PORT
      LAYER Metal3 ;
        RECT  899.6 405.94 900 406.34 ;
    END
  END limits_i.lim_dsp[31]
  PIN limits_i.lim_dsp[32]
    DIRECTION INPUT ;
    USE SIGNAL ;
    PORT
      LAYER Metal3 ;
        RECT  899.6 409.3 900 409.7 ;
    END
  END limits_i.lim_dsp[32]
  PIN limits_i.lim_dsp[33]
    DIRECTION INPUT ;
    USE SIGNAL ;
    PORT
      LAYER Metal3 ;
        RECT  899.6 412.66 900 413.06 ;
    END
  END limits_i.lim_dsp[33]
  PIN limits_i.lim_dsp[34]
    DIRECTION INPUT ;
    USE SIGNAL ;
    PORT
      LAYER Metal3 ;
        RECT  899.6 416.02 900 416.42 ;
    END
  END limits_i.lim_dsp[34]
  PIN limits_i.lim_dsp[35]
    DIRECTION INPUT ;
    USE SIGNAL ;
    PORT
      LAYER Metal3 ;
        RECT  899.6 419.38 900 419.78 ;
    END
  END limits_i.lim_dsp[35]
  PIN limits_i.lim_dsp[36]
    DIRECTION INPUT ;
    USE SIGNAL ;
    PORT
      LAYER Metal3 ;
        RECT  899.6 422.74 900 423.14 ;
    END
  END limits_i.lim_dsp[36]
  PIN limits_i.lim_dsp[37]
    DIRECTION INPUT ;
    USE SIGNAL ;
    PORT
      LAYER Metal3 ;
        RECT  899.6 426.1 900 426.5 ;
    END
  END limits_i.lim_dsp[37]
  PIN limits_i.lim_dsp[38]
    DIRECTION INPUT ;
    USE SIGNAL ;
    PORT
      LAYER Metal3 ;
        RECT  899.6 429.46 900 429.86 ;
    END
  END limits_i.lim_dsp[38]
  PIN limits_i.lim_dsp[39]
    DIRECTION INPUT ;
    USE SIGNAL ;
    PORT
      LAYER Metal3 ;
        RECT  899.6 432.82 900 433.22 ;
    END
  END limits_i.lim_dsp[39]
  PIN limits_i.lim_dsp[3]
    DIRECTION INPUT ;
    USE SIGNAL ;
    PORT
      LAYER Metal3 ;
        RECT  899.6 311.86 900 312.26 ;
    END
  END limits_i.lim_dsp[3]
  PIN limits_i.lim_dsp[40]
    DIRECTION INPUT ;
    USE SIGNAL ;
    PORT
      LAYER Metal3 ;
        RECT  899.6 436.18 900 436.58 ;
    END
  END limits_i.lim_dsp[40]
  PIN limits_i.lim_dsp[41]
    DIRECTION INPUT ;
    USE SIGNAL ;
    PORT
      LAYER Metal3 ;
        RECT  899.6 439.54 900 439.94 ;
    END
  END limits_i.lim_dsp[41]
  PIN limits_i.lim_dsp[42]
    DIRECTION INPUT ;
    USE SIGNAL ;
    PORT
      LAYER Metal3 ;
        RECT  899.6 442.9 900 443.3 ;
    END
  END limits_i.lim_dsp[42]
  PIN limits_i.lim_dsp[43]
    DIRECTION INPUT ;
    USE SIGNAL ;
    PORT
      LAYER Metal3 ;
        RECT  899.6 446.26 900 446.66 ;
    END
  END limits_i.lim_dsp[43]
  PIN limits_i.lim_dsp[44]
    DIRECTION INPUT ;
    USE SIGNAL ;
    PORT
      LAYER Metal3 ;
        RECT  899.6 449.62 900 450.02 ;
    END
  END limits_i.lim_dsp[44]
  PIN limits_i.lim_dsp[45]
    DIRECTION INPUT ;
    USE SIGNAL ;
    PORT
      LAYER Metal3 ;
        RECT  899.6 452.98 900 453.38 ;
    END
  END limits_i.lim_dsp[45]
  PIN limits_i.lim_dsp[46]
    DIRECTION INPUT ;
    USE SIGNAL ;
    PORT
      LAYER Metal3 ;
        RECT  899.6 456.34 900 456.74 ;
    END
  END limits_i.lim_dsp[46]
  PIN limits_i.lim_dsp[47]
    DIRECTION INPUT ;
    USE SIGNAL ;
    PORT
      LAYER Metal3 ;
        RECT  899.6 459.7 900 460.1 ;
    END
  END limits_i.lim_dsp[47]
  PIN limits_i.lim_dsp[48]
    DIRECTION INPUT ;
    USE SIGNAL ;
    PORT
      LAYER Metal3 ;
        RECT  899.6 463.06 900 463.46 ;
    END
  END limits_i.lim_dsp[48]
  PIN limits_i.lim_dsp[49]
    DIRECTION INPUT ;
    USE SIGNAL ;
    PORT
      LAYER Metal3 ;
        RECT  899.6 466.42 900 466.82 ;
    END
  END limits_i.lim_dsp[49]
  PIN limits_i.lim_dsp[4]
    DIRECTION INPUT ;
    USE SIGNAL ;
    PORT
      LAYER Metal3 ;
        RECT  899.6 315.22 900 315.62 ;
    END
  END limits_i.lim_dsp[4]
  PIN limits_i.lim_dsp[50]
    DIRECTION INPUT ;
    USE SIGNAL ;
    PORT
      LAYER Metal3 ;
        RECT  899.6 469.78 900 470.18 ;
    END
  END limits_i.lim_dsp[50]
  PIN limits_i.lim_dsp[51]
    DIRECTION INPUT ;
    USE SIGNAL ;
    PORT
      LAYER Metal3 ;
        RECT  899.6 473.14 900 473.54 ;
    END
  END limits_i.lim_dsp[51]
  PIN limits_i.lim_dsp[52]
    DIRECTION INPUT ;
    USE SIGNAL ;
    PORT
      LAYER Metal3 ;
        RECT  899.6 476.5 900 476.9 ;
    END
  END limits_i.lim_dsp[52]
  PIN limits_i.lim_dsp[53]
    DIRECTION INPUT ;
    USE SIGNAL ;
    PORT
      LAYER Metal3 ;
        RECT  899.6 479.86 900 480.26 ;
    END
  END limits_i.lim_dsp[53]
  PIN limits_i.lim_dsp[54]
    DIRECTION INPUT ;
    USE SIGNAL ;
    PORT
      LAYER Metal3 ;
        RECT  899.6 483.22 900 483.62 ;
    END
  END limits_i.lim_dsp[54]
  PIN limits_i.lim_dsp[55]
    DIRECTION INPUT ;
    USE SIGNAL ;
    PORT
      LAYER Metal3 ;
        RECT  899.6 486.58 900 486.98 ;
    END
  END limits_i.lim_dsp[55]
  PIN limits_i.lim_dsp[56]
    DIRECTION INPUT ;
    USE SIGNAL ;
    PORT
      LAYER Metal3 ;
        RECT  899.6 489.94 900 490.34 ;
    END
  END limits_i.lim_dsp[56]
  PIN limits_i.lim_dsp[57]
    DIRECTION INPUT ;
    USE SIGNAL ;
    PORT
      LAYER Metal3 ;
        RECT  899.6 493.3 900 493.7 ;
    END
  END limits_i.lim_dsp[57]
  PIN limits_i.lim_dsp[58]
    DIRECTION INPUT ;
    USE SIGNAL ;
    PORT
      LAYER Metal3 ;
        RECT  899.6 496.66 900 497.06 ;
    END
  END limits_i.lim_dsp[58]
  PIN limits_i.lim_dsp[59]
    DIRECTION INPUT ;
    USE SIGNAL ;
    PORT
      LAYER Metal3 ;
        RECT  899.6 500.02 900 500.42 ;
    END
  END limits_i.lim_dsp[59]
  PIN limits_i.lim_dsp[5]
    DIRECTION INPUT ;
    USE SIGNAL ;
    PORT
      LAYER Metal3 ;
        RECT  899.6 318.58 900 318.98 ;
    END
  END limits_i.lim_dsp[5]
  PIN limits_i.lim_dsp[60]
    DIRECTION INPUT ;
    USE SIGNAL ;
    PORT
      LAYER Metal3 ;
        RECT  899.6 503.38 900 503.78 ;
    END
  END limits_i.lim_dsp[60]
  PIN limits_i.lim_dsp[61]
    DIRECTION INPUT ;
    USE SIGNAL ;
    PORT
      LAYER Metal3 ;
        RECT  899.6 506.74 900 507.14 ;
    END
  END limits_i.lim_dsp[61]
  PIN limits_i.lim_dsp[62]
    DIRECTION INPUT ;
    USE SIGNAL ;
    PORT
      LAYER Metal3 ;
        RECT  899.6 510.1 900 510.5 ;
    END
  END limits_i.lim_dsp[62]
  PIN limits_i.lim_dsp[63]
    DIRECTION INPUT ;
    USE SIGNAL ;
    PORT
      LAYER Metal3 ;
        RECT  899.6 513.46 900 513.86 ;
    END
  END limits_i.lim_dsp[63]
  PIN limits_i.lim_dsp[6]
    DIRECTION INPUT ;
    USE SIGNAL ;
    PORT
      LAYER Metal3 ;
        RECT  899.6 321.94 900 322.34 ;
    END
  END limits_i.lim_dsp[6]
  PIN limits_i.lim_dsp[7]
    DIRECTION INPUT ;
    USE SIGNAL ;
    PORT
      LAYER Metal3 ;
        RECT  899.6 325.3 900 325.7 ;
    END
  END limits_i.lim_dsp[7]
  PIN limits_i.lim_dsp[8]
    DIRECTION INPUT ;
    USE SIGNAL ;
    PORT
      LAYER Metal3 ;
        RECT  899.6 328.66 900 329.06 ;
    END
  END limits_i.lim_dsp[8]
  PIN limits_i.lim_dsp[9]
    DIRECTION INPUT ;
    USE SIGNAL ;
    PORT
      LAYER Metal3 ;
        RECT  899.6 332.02 900 332.42 ;
    END
  END limits_i.lim_dsp[9]
  PIN limits_i.lim_hp[0]
    DIRECTION INPUT ;
    USE SIGNAL ;
    PORT
      LAYER Metal3 ;
        RECT  899.6 302.62 900 303.02 ;
    END
  END limits_i.lim_hp[0]
  PIN limits_i.lim_hp[10]
    DIRECTION INPUT ;
    USE SIGNAL ;
    PORT
      LAYER Metal3 ;
        RECT  899.6 336.22 900 336.62 ;
    END
  END limits_i.lim_hp[10]
  PIN limits_i.lim_hp[11]
    DIRECTION INPUT ;
    USE SIGNAL ;
    PORT
      LAYER Metal3 ;
        RECT  899.6 339.58 900 339.98 ;
    END
  END limits_i.lim_hp[11]
  PIN limits_i.lim_hp[12]
    DIRECTION INPUT ;
    USE SIGNAL ;
    PORT
      LAYER Metal3 ;
        RECT  899.6 342.94 900 343.34 ;
    END
  END limits_i.lim_hp[12]
  PIN limits_i.lim_hp[13]
    DIRECTION INPUT ;
    USE SIGNAL ;
    PORT
      LAYER Metal3 ;
        RECT  899.6 346.3 900 346.7 ;
    END
  END limits_i.lim_hp[13]
  PIN limits_i.lim_hp[14]
    DIRECTION INPUT ;
    USE SIGNAL ;
    PORT
      LAYER Metal3 ;
        RECT  899.6 349.66 900 350.06 ;
    END
  END limits_i.lim_hp[14]
  PIN limits_i.lim_hp[15]
    DIRECTION INPUT ;
    USE SIGNAL ;
    PORT
      LAYER Metal3 ;
        RECT  899.6 353.02 900 353.42 ;
    END
  END limits_i.lim_hp[15]
  PIN limits_i.lim_hp[16]
    DIRECTION INPUT ;
    USE SIGNAL ;
    PORT
      LAYER Metal3 ;
        RECT  899.6 356.38 900 356.78 ;
    END
  END limits_i.lim_hp[16]
  PIN limits_i.lim_hp[17]
    DIRECTION INPUT ;
    USE SIGNAL ;
    PORT
      LAYER Metal3 ;
        RECT  899.6 359.74 900 360.14 ;
    END
  END limits_i.lim_hp[17]
  PIN limits_i.lim_hp[18]
    DIRECTION INPUT ;
    USE SIGNAL ;
    PORT
      LAYER Metal3 ;
        RECT  899.6 363.1 900 363.5 ;
    END
  END limits_i.lim_hp[18]
  PIN limits_i.lim_hp[19]
    DIRECTION INPUT ;
    USE SIGNAL ;
    PORT
      LAYER Metal3 ;
        RECT  899.6 366.46 900 366.86 ;
    END
  END limits_i.lim_hp[19]
  PIN limits_i.lim_hp[1]
    DIRECTION INPUT ;
    USE SIGNAL ;
    PORT
      LAYER Metal3 ;
        RECT  899.6 305.98 900 306.38 ;
    END
  END limits_i.lim_hp[1]
  PIN limits_i.lim_hp[20]
    DIRECTION INPUT ;
    USE SIGNAL ;
    PORT
      LAYER Metal3 ;
        RECT  899.6 369.82 900 370.22 ;
    END
  END limits_i.lim_hp[20]
  PIN limits_i.lim_hp[21]
    DIRECTION INPUT ;
    USE SIGNAL ;
    PORT
      LAYER Metal3 ;
        RECT  899.6 373.18 900 373.58 ;
    END
  END limits_i.lim_hp[21]
  PIN limits_i.lim_hp[22]
    DIRECTION INPUT ;
    USE SIGNAL ;
    PORT
      LAYER Metal3 ;
        RECT  899.6 376.54 900 376.94 ;
    END
  END limits_i.lim_hp[22]
  PIN limits_i.lim_hp[23]
    DIRECTION INPUT ;
    USE SIGNAL ;
    PORT
      LAYER Metal3 ;
        RECT  899.6 379.9 900 380.3 ;
    END
  END limits_i.lim_hp[23]
  PIN limits_i.lim_hp[24]
    DIRECTION INPUT ;
    USE SIGNAL ;
    PORT
      LAYER Metal3 ;
        RECT  899.6 383.26 900 383.66 ;
    END
  END limits_i.lim_hp[24]
  PIN limits_i.lim_hp[25]
    DIRECTION INPUT ;
    USE SIGNAL ;
    PORT
      LAYER Metal3 ;
        RECT  899.6 386.62 900 387.02 ;
    END
  END limits_i.lim_hp[25]
  PIN limits_i.lim_hp[26]
    DIRECTION INPUT ;
    USE SIGNAL ;
    PORT
      LAYER Metal3 ;
        RECT  899.6 389.98 900 390.38 ;
    END
  END limits_i.lim_hp[26]
  PIN limits_i.lim_hp[27]
    DIRECTION INPUT ;
    USE SIGNAL ;
    PORT
      LAYER Metal3 ;
        RECT  899.6 393.34 900 393.74 ;
    END
  END limits_i.lim_hp[27]
  PIN limits_i.lim_hp[28]
    DIRECTION INPUT ;
    USE SIGNAL ;
    PORT
      LAYER Metal3 ;
        RECT  899.6 396.7 900 397.1 ;
    END
  END limits_i.lim_hp[28]
  PIN limits_i.lim_hp[29]
    DIRECTION INPUT ;
    USE SIGNAL ;
    PORT
      LAYER Metal3 ;
        RECT  899.6 400.06 900 400.46 ;
    END
  END limits_i.lim_hp[29]
  PIN limits_i.lim_hp[2]
    DIRECTION INPUT ;
    USE SIGNAL ;
    PORT
      LAYER Metal3 ;
        RECT  899.6 309.34 900 309.74 ;
    END
  END limits_i.lim_hp[2]
  PIN limits_i.lim_hp[30]
    DIRECTION INPUT ;
    USE SIGNAL ;
    PORT
      LAYER Metal3 ;
        RECT  899.6 403.42 900 403.82 ;
    END
  END limits_i.lim_hp[30]
  PIN limits_i.lim_hp[31]
    DIRECTION INPUT ;
    USE SIGNAL ;
    PORT
      LAYER Metal3 ;
        RECT  899.6 406.78 900 407.18 ;
    END
  END limits_i.lim_hp[31]
  PIN limits_i.lim_hp[32]
    DIRECTION INPUT ;
    USE SIGNAL ;
    PORT
      LAYER Metal3 ;
        RECT  899.6 410.14 900 410.54 ;
    END
  END limits_i.lim_hp[32]
  PIN limits_i.lim_hp[33]
    DIRECTION INPUT ;
    USE SIGNAL ;
    PORT
      LAYER Metal3 ;
        RECT  899.6 413.5 900 413.9 ;
    END
  END limits_i.lim_hp[33]
  PIN limits_i.lim_hp[34]
    DIRECTION INPUT ;
    USE SIGNAL ;
    PORT
      LAYER Metal3 ;
        RECT  899.6 416.86 900 417.26 ;
    END
  END limits_i.lim_hp[34]
  PIN limits_i.lim_hp[35]
    DIRECTION INPUT ;
    USE SIGNAL ;
    PORT
      LAYER Metal3 ;
        RECT  899.6 420.22 900 420.62 ;
    END
  END limits_i.lim_hp[35]
  PIN limits_i.lim_hp[36]
    DIRECTION INPUT ;
    USE SIGNAL ;
    PORT
      LAYER Metal3 ;
        RECT  899.6 423.58 900 423.98 ;
    END
  END limits_i.lim_hp[36]
  PIN limits_i.lim_hp[37]
    DIRECTION INPUT ;
    USE SIGNAL ;
    PORT
      LAYER Metal3 ;
        RECT  899.6 426.94 900 427.34 ;
    END
  END limits_i.lim_hp[37]
  PIN limits_i.lim_hp[38]
    DIRECTION INPUT ;
    USE SIGNAL ;
    PORT
      LAYER Metal3 ;
        RECT  899.6 430.3 900 430.7 ;
    END
  END limits_i.lim_hp[38]
  PIN limits_i.lim_hp[39]
    DIRECTION INPUT ;
    USE SIGNAL ;
    PORT
      LAYER Metal3 ;
        RECT  899.6 433.66 900 434.06 ;
    END
  END limits_i.lim_hp[39]
  PIN limits_i.lim_hp[3]
    DIRECTION INPUT ;
    USE SIGNAL ;
    PORT
      LAYER Metal3 ;
        RECT  899.6 312.7 900 313.1 ;
    END
  END limits_i.lim_hp[3]
  PIN limits_i.lim_hp[40]
    DIRECTION INPUT ;
    USE SIGNAL ;
    PORT
      LAYER Metal3 ;
        RECT  899.6 437.02 900 437.42 ;
    END
  END limits_i.lim_hp[40]
  PIN limits_i.lim_hp[41]
    DIRECTION INPUT ;
    USE SIGNAL ;
    PORT
      LAYER Metal3 ;
        RECT  899.6 440.38 900 440.78 ;
    END
  END limits_i.lim_hp[41]
  PIN limits_i.lim_hp[42]
    DIRECTION INPUT ;
    USE SIGNAL ;
    PORT
      LAYER Metal3 ;
        RECT  899.6 443.74 900 444.14 ;
    END
  END limits_i.lim_hp[42]
  PIN limits_i.lim_hp[43]
    DIRECTION INPUT ;
    USE SIGNAL ;
    PORT
      LAYER Metal3 ;
        RECT  899.6 447.1 900 447.5 ;
    END
  END limits_i.lim_hp[43]
  PIN limits_i.lim_hp[44]
    DIRECTION INPUT ;
    USE SIGNAL ;
    PORT
      LAYER Metal3 ;
        RECT  899.6 450.46 900 450.86 ;
    END
  END limits_i.lim_hp[44]
  PIN limits_i.lim_hp[45]
    DIRECTION INPUT ;
    USE SIGNAL ;
    PORT
      LAYER Metal3 ;
        RECT  899.6 453.82 900 454.22 ;
    END
  END limits_i.lim_hp[45]
  PIN limits_i.lim_hp[46]
    DIRECTION INPUT ;
    USE SIGNAL ;
    PORT
      LAYER Metal3 ;
        RECT  899.6 457.18 900 457.58 ;
    END
  END limits_i.lim_hp[46]
  PIN limits_i.lim_hp[47]
    DIRECTION INPUT ;
    USE SIGNAL ;
    PORT
      LAYER Metal3 ;
        RECT  899.6 460.54 900 460.94 ;
    END
  END limits_i.lim_hp[47]
  PIN limits_i.lim_hp[48]
    DIRECTION INPUT ;
    USE SIGNAL ;
    PORT
      LAYER Metal3 ;
        RECT  899.6 463.9 900 464.3 ;
    END
  END limits_i.lim_hp[48]
  PIN limits_i.lim_hp[49]
    DIRECTION INPUT ;
    USE SIGNAL ;
    PORT
      LAYER Metal3 ;
        RECT  899.6 467.26 900 467.66 ;
    END
  END limits_i.lim_hp[49]
  PIN limits_i.lim_hp[4]
    DIRECTION INPUT ;
    USE SIGNAL ;
    PORT
      LAYER Metal3 ;
        RECT  899.6 316.06 900 316.46 ;
    END
  END limits_i.lim_hp[4]
  PIN limits_i.lim_hp[50]
    DIRECTION INPUT ;
    USE SIGNAL ;
    PORT
      LAYER Metal3 ;
        RECT  899.6 470.62 900 471.02 ;
    END
  END limits_i.lim_hp[50]
  PIN limits_i.lim_hp[51]
    DIRECTION INPUT ;
    USE SIGNAL ;
    PORT
      LAYER Metal3 ;
        RECT  899.6 473.98 900 474.38 ;
    END
  END limits_i.lim_hp[51]
  PIN limits_i.lim_hp[52]
    DIRECTION INPUT ;
    USE SIGNAL ;
    PORT
      LAYER Metal3 ;
        RECT  899.6 477.34 900 477.74 ;
    END
  END limits_i.lim_hp[52]
  PIN limits_i.lim_hp[53]
    DIRECTION INPUT ;
    USE SIGNAL ;
    PORT
      LAYER Metal3 ;
        RECT  899.6 480.7 900 481.1 ;
    END
  END limits_i.lim_hp[53]
  PIN limits_i.lim_hp[54]
    DIRECTION INPUT ;
    USE SIGNAL ;
    PORT
      LAYER Metal3 ;
        RECT  899.6 484.06 900 484.46 ;
    END
  END limits_i.lim_hp[54]
  PIN limits_i.lim_hp[55]
    DIRECTION INPUT ;
    USE SIGNAL ;
    PORT
      LAYER Metal3 ;
        RECT  899.6 487.42 900 487.82 ;
    END
  END limits_i.lim_hp[55]
  PIN limits_i.lim_hp[56]
    DIRECTION INPUT ;
    USE SIGNAL ;
    PORT
      LAYER Metal3 ;
        RECT  899.6 490.78 900 491.18 ;
    END
  END limits_i.lim_hp[56]
  PIN limits_i.lim_hp[57]
    DIRECTION INPUT ;
    USE SIGNAL ;
    PORT
      LAYER Metal3 ;
        RECT  899.6 494.14 900 494.54 ;
    END
  END limits_i.lim_hp[57]
  PIN limits_i.lim_hp[58]
    DIRECTION INPUT ;
    USE SIGNAL ;
    PORT
      LAYER Metal3 ;
        RECT  899.6 497.5 900 497.9 ;
    END
  END limits_i.lim_hp[58]
  PIN limits_i.lim_hp[59]
    DIRECTION INPUT ;
    USE SIGNAL ;
    PORT
      LAYER Metal3 ;
        RECT  899.6 500.86 900 501.26 ;
    END
  END limits_i.lim_hp[59]
  PIN limits_i.lim_hp[5]
    DIRECTION INPUT ;
    USE SIGNAL ;
    PORT
      LAYER Metal3 ;
        RECT  899.6 319.42 900 319.82 ;
    END
  END limits_i.lim_hp[5]
  PIN limits_i.lim_hp[60]
    DIRECTION INPUT ;
    USE SIGNAL ;
    PORT
      LAYER Metal3 ;
        RECT  899.6 504.22 900 504.62 ;
    END
  END limits_i.lim_hp[60]
  PIN limits_i.lim_hp[61]
    DIRECTION INPUT ;
    USE SIGNAL ;
    PORT
      LAYER Metal3 ;
        RECT  899.6 507.58 900 507.98 ;
    END
  END limits_i.lim_hp[61]
  PIN limits_i.lim_hp[62]
    DIRECTION INPUT ;
    USE SIGNAL ;
    PORT
      LAYER Metal3 ;
        RECT  899.6 510.94 900 511.34 ;
    END
  END limits_i.lim_hp[62]
  PIN limits_i.lim_hp[63]
    DIRECTION INPUT ;
    USE SIGNAL ;
    PORT
      LAYER Metal3 ;
        RECT  899.6 514.3 900 514.7 ;
    END
  END limits_i.lim_hp[63]
  PIN limits_i.lim_hp[6]
    DIRECTION INPUT ;
    USE SIGNAL ;
    PORT
      LAYER Metal3 ;
        RECT  899.6 322.78 900 323.18 ;
    END
  END limits_i.lim_hp[6]
  PIN limits_i.lim_hp[7]
    DIRECTION INPUT ;
    USE SIGNAL ;
    PORT
      LAYER Metal3 ;
        RECT  899.6 326.14 900 326.54 ;
    END
  END limits_i.lim_hp[7]
  PIN limits_i.lim_hp[8]
    DIRECTION INPUT ;
    USE SIGNAL ;
    PORT
      LAYER Metal3 ;
        RECT  899.6 329.5 900 329.9 ;
    END
  END limits_i.lim_hp[8]
  PIN limits_i.lim_hp[9]
    DIRECTION INPUT ;
    USE SIGNAL ;
    PORT
      LAYER Metal3 ;
        RECT  899.6 332.86 900 333.26 ;
    END
  END limits_i.lim_hp[9]
  PIN limits_i.lim_rsp[0]
    DIRECTION INPUT ;
    USE SIGNAL ;
    PORT
      LAYER Metal3 ;
        RECT  899.6 303.46 900 303.86 ;
    END
  END limits_i.lim_rsp[0]
  PIN limits_i.lim_rsp[10]
    DIRECTION INPUT ;
    USE SIGNAL ;
    PORT
      LAYER Metal3 ;
        RECT  899.6 337.06 900 337.46 ;
    END
  END limits_i.lim_rsp[10]
  PIN limits_i.lim_rsp[11]
    DIRECTION INPUT ;
    USE SIGNAL ;
    PORT
      LAYER Metal3 ;
        RECT  899.6 340.42 900 340.82 ;
    END
  END limits_i.lim_rsp[11]
  PIN limits_i.lim_rsp[12]
    DIRECTION INPUT ;
    USE SIGNAL ;
    PORT
      LAYER Metal3 ;
        RECT  899.6 343.78 900 344.18 ;
    END
  END limits_i.lim_rsp[12]
  PIN limits_i.lim_rsp[13]
    DIRECTION INPUT ;
    USE SIGNAL ;
    PORT
      LAYER Metal3 ;
        RECT  899.6 347.14 900 347.54 ;
    END
  END limits_i.lim_rsp[13]
  PIN limits_i.lim_rsp[14]
    DIRECTION INPUT ;
    USE SIGNAL ;
    PORT
      LAYER Metal3 ;
        RECT  899.6 350.5 900 350.9 ;
    END
  END limits_i.lim_rsp[14]
  PIN limits_i.lim_rsp[15]
    DIRECTION INPUT ;
    USE SIGNAL ;
    PORT
      LAYER Metal3 ;
        RECT  899.6 353.86 900 354.26 ;
    END
  END limits_i.lim_rsp[15]
  PIN limits_i.lim_rsp[16]
    DIRECTION INPUT ;
    USE SIGNAL ;
    PORT
      LAYER Metal3 ;
        RECT  899.6 357.22 900 357.62 ;
    END
  END limits_i.lim_rsp[16]
  PIN limits_i.lim_rsp[17]
    DIRECTION INPUT ;
    USE SIGNAL ;
    PORT
      LAYER Metal3 ;
        RECT  899.6 360.58 900 360.98 ;
    END
  END limits_i.lim_rsp[17]
  PIN limits_i.lim_rsp[18]
    DIRECTION INPUT ;
    USE SIGNAL ;
    PORT
      LAYER Metal3 ;
        RECT  899.6 363.94 900 364.34 ;
    END
  END limits_i.lim_rsp[18]
  PIN limits_i.lim_rsp[19]
    DIRECTION INPUT ;
    USE SIGNAL ;
    PORT
      LAYER Metal3 ;
        RECT  899.6 367.3 900 367.7 ;
    END
  END limits_i.lim_rsp[19]
  PIN limits_i.lim_rsp[1]
    DIRECTION INPUT ;
    USE SIGNAL ;
    PORT
      LAYER Metal3 ;
        RECT  899.6 306.82 900 307.22 ;
    END
  END limits_i.lim_rsp[1]
  PIN limits_i.lim_rsp[20]
    DIRECTION INPUT ;
    USE SIGNAL ;
    PORT
      LAYER Metal3 ;
        RECT  899.6 370.66 900 371.06 ;
    END
  END limits_i.lim_rsp[20]
  PIN limits_i.lim_rsp[21]
    DIRECTION INPUT ;
    USE SIGNAL ;
    PORT
      LAYER Metal3 ;
        RECT  899.6 374.02 900 374.42 ;
    END
  END limits_i.lim_rsp[21]
  PIN limits_i.lim_rsp[22]
    DIRECTION INPUT ;
    USE SIGNAL ;
    PORT
      LAYER Metal3 ;
        RECT  899.6 377.38 900 377.78 ;
    END
  END limits_i.lim_rsp[22]
  PIN limits_i.lim_rsp[23]
    DIRECTION INPUT ;
    USE SIGNAL ;
    PORT
      LAYER Metal3 ;
        RECT  899.6 380.74 900 381.14 ;
    END
  END limits_i.lim_rsp[23]
  PIN limits_i.lim_rsp[24]
    DIRECTION INPUT ;
    USE SIGNAL ;
    PORT
      LAYER Metal3 ;
        RECT  899.6 384.1 900 384.5 ;
    END
  END limits_i.lim_rsp[24]
  PIN limits_i.lim_rsp[25]
    DIRECTION INPUT ;
    USE SIGNAL ;
    PORT
      LAYER Metal3 ;
        RECT  899.6 387.46 900 387.86 ;
    END
  END limits_i.lim_rsp[25]
  PIN limits_i.lim_rsp[26]
    DIRECTION INPUT ;
    USE SIGNAL ;
    PORT
      LAYER Metal3 ;
        RECT  899.6 390.82 900 391.22 ;
    END
  END limits_i.lim_rsp[26]
  PIN limits_i.lim_rsp[27]
    DIRECTION INPUT ;
    USE SIGNAL ;
    PORT
      LAYER Metal3 ;
        RECT  899.6 394.18 900 394.58 ;
    END
  END limits_i.lim_rsp[27]
  PIN limits_i.lim_rsp[28]
    DIRECTION INPUT ;
    USE SIGNAL ;
    PORT
      LAYER Metal3 ;
        RECT  899.6 397.54 900 397.94 ;
    END
  END limits_i.lim_rsp[28]
  PIN limits_i.lim_rsp[29]
    DIRECTION INPUT ;
    USE SIGNAL ;
    PORT
      LAYER Metal3 ;
        RECT  899.6 400.9 900 401.3 ;
    END
  END limits_i.lim_rsp[29]
  PIN limits_i.lim_rsp[2]
    DIRECTION INPUT ;
    USE SIGNAL ;
    PORT
      LAYER Metal3 ;
        RECT  899.6 310.18 900 310.58 ;
    END
  END limits_i.lim_rsp[2]
  PIN limits_i.lim_rsp[30]
    DIRECTION INPUT ;
    USE SIGNAL ;
    PORT
      LAYER Metal3 ;
        RECT  899.6 404.26 900 404.66 ;
    END
  END limits_i.lim_rsp[30]
  PIN limits_i.lim_rsp[31]
    DIRECTION INPUT ;
    USE SIGNAL ;
    PORT
      LAYER Metal3 ;
        RECT  899.6 407.62 900 408.02 ;
    END
  END limits_i.lim_rsp[31]
  PIN limits_i.lim_rsp[32]
    DIRECTION INPUT ;
    USE SIGNAL ;
    PORT
      LAYER Metal3 ;
        RECT  899.6 410.98 900 411.38 ;
    END
  END limits_i.lim_rsp[32]
  PIN limits_i.lim_rsp[33]
    DIRECTION INPUT ;
    USE SIGNAL ;
    PORT
      LAYER Metal3 ;
        RECT  899.6 414.34 900 414.74 ;
    END
  END limits_i.lim_rsp[33]
  PIN limits_i.lim_rsp[34]
    DIRECTION INPUT ;
    USE SIGNAL ;
    PORT
      LAYER Metal3 ;
        RECT  899.6 417.7 900 418.1 ;
    END
  END limits_i.lim_rsp[34]
  PIN limits_i.lim_rsp[35]
    DIRECTION INPUT ;
    USE SIGNAL ;
    PORT
      LAYER Metal3 ;
        RECT  899.6 421.06 900 421.46 ;
    END
  END limits_i.lim_rsp[35]
  PIN limits_i.lim_rsp[36]
    DIRECTION INPUT ;
    USE SIGNAL ;
    PORT
      LAYER Metal3 ;
        RECT  899.6 424.42 900 424.82 ;
    END
  END limits_i.lim_rsp[36]
  PIN limits_i.lim_rsp[37]
    DIRECTION INPUT ;
    USE SIGNAL ;
    PORT
      LAYER Metal3 ;
        RECT  899.6 427.78 900 428.18 ;
    END
  END limits_i.lim_rsp[37]
  PIN limits_i.lim_rsp[38]
    DIRECTION INPUT ;
    USE SIGNAL ;
    PORT
      LAYER Metal3 ;
        RECT  899.6 431.14 900 431.54 ;
    END
  END limits_i.lim_rsp[38]
  PIN limits_i.lim_rsp[39]
    DIRECTION INPUT ;
    USE SIGNAL ;
    PORT
      LAYER Metal3 ;
        RECT  899.6 434.5 900 434.9 ;
    END
  END limits_i.lim_rsp[39]
  PIN limits_i.lim_rsp[3]
    DIRECTION INPUT ;
    USE SIGNAL ;
    PORT
      LAYER Metal3 ;
        RECT  899.6 313.54 900 313.94 ;
    END
  END limits_i.lim_rsp[3]
  PIN limits_i.lim_rsp[40]
    DIRECTION INPUT ;
    USE SIGNAL ;
    PORT
      LAYER Metal3 ;
        RECT  899.6 437.86 900 438.26 ;
    END
  END limits_i.lim_rsp[40]
  PIN limits_i.lim_rsp[41]
    DIRECTION INPUT ;
    USE SIGNAL ;
    PORT
      LAYER Metal3 ;
        RECT  899.6 441.22 900 441.62 ;
    END
  END limits_i.lim_rsp[41]
  PIN limits_i.lim_rsp[42]
    DIRECTION INPUT ;
    USE SIGNAL ;
    PORT
      LAYER Metal3 ;
        RECT  899.6 444.58 900 444.98 ;
    END
  END limits_i.lim_rsp[42]
  PIN limits_i.lim_rsp[43]
    DIRECTION INPUT ;
    USE SIGNAL ;
    PORT
      LAYER Metal3 ;
        RECT  899.6 447.94 900 448.34 ;
    END
  END limits_i.lim_rsp[43]
  PIN limits_i.lim_rsp[44]
    DIRECTION INPUT ;
    USE SIGNAL ;
    PORT
      LAYER Metal3 ;
        RECT  899.6 451.3 900 451.7 ;
    END
  END limits_i.lim_rsp[44]
  PIN limits_i.lim_rsp[45]
    DIRECTION INPUT ;
    USE SIGNAL ;
    PORT
      LAYER Metal3 ;
        RECT  899.6 454.66 900 455.06 ;
    END
  END limits_i.lim_rsp[45]
  PIN limits_i.lim_rsp[46]
    DIRECTION INPUT ;
    USE SIGNAL ;
    PORT
      LAYER Metal3 ;
        RECT  899.6 458.02 900 458.42 ;
    END
  END limits_i.lim_rsp[46]
  PIN limits_i.lim_rsp[47]
    DIRECTION INPUT ;
    USE SIGNAL ;
    PORT
      LAYER Metal3 ;
        RECT  899.6 461.38 900 461.78 ;
    END
  END limits_i.lim_rsp[47]
  PIN limits_i.lim_rsp[48]
    DIRECTION INPUT ;
    USE SIGNAL ;
    PORT
      LAYER Metal3 ;
        RECT  899.6 464.74 900 465.14 ;
    END
  END limits_i.lim_rsp[48]
  PIN limits_i.lim_rsp[49]
    DIRECTION INPUT ;
    USE SIGNAL ;
    PORT
      LAYER Metal3 ;
        RECT  899.6 468.1 900 468.5 ;
    END
  END limits_i.lim_rsp[49]
  PIN limits_i.lim_rsp[4]
    DIRECTION INPUT ;
    USE SIGNAL ;
    PORT
      LAYER Metal3 ;
        RECT  899.6 316.9 900 317.3 ;
    END
  END limits_i.lim_rsp[4]
  PIN limits_i.lim_rsp[50]
    DIRECTION INPUT ;
    USE SIGNAL ;
    PORT
      LAYER Metal3 ;
        RECT  899.6 471.46 900 471.86 ;
    END
  END limits_i.lim_rsp[50]
  PIN limits_i.lim_rsp[51]
    DIRECTION INPUT ;
    USE SIGNAL ;
    PORT
      LAYER Metal3 ;
        RECT  899.6 474.82 900 475.22 ;
    END
  END limits_i.lim_rsp[51]
  PIN limits_i.lim_rsp[52]
    DIRECTION INPUT ;
    USE SIGNAL ;
    PORT
      LAYER Metal3 ;
        RECT  899.6 478.18 900 478.58 ;
    END
  END limits_i.lim_rsp[52]
  PIN limits_i.lim_rsp[53]
    DIRECTION INPUT ;
    USE SIGNAL ;
    PORT
      LAYER Metal3 ;
        RECT  899.6 481.54 900 481.94 ;
    END
  END limits_i.lim_rsp[53]
  PIN limits_i.lim_rsp[54]
    DIRECTION INPUT ;
    USE SIGNAL ;
    PORT
      LAYER Metal3 ;
        RECT  899.6 484.9 900 485.3 ;
    END
  END limits_i.lim_rsp[54]
  PIN limits_i.lim_rsp[55]
    DIRECTION INPUT ;
    USE SIGNAL ;
    PORT
      LAYER Metal3 ;
        RECT  899.6 488.26 900 488.66 ;
    END
  END limits_i.lim_rsp[55]
  PIN limits_i.lim_rsp[56]
    DIRECTION INPUT ;
    USE SIGNAL ;
    PORT
      LAYER Metal3 ;
        RECT  899.6 491.62 900 492.02 ;
    END
  END limits_i.lim_rsp[56]
  PIN limits_i.lim_rsp[57]
    DIRECTION INPUT ;
    USE SIGNAL ;
    PORT
      LAYER Metal3 ;
        RECT  899.6 494.98 900 495.38 ;
    END
  END limits_i.lim_rsp[57]
  PIN limits_i.lim_rsp[58]
    DIRECTION INPUT ;
    USE SIGNAL ;
    PORT
      LAYER Metal3 ;
        RECT  899.6 498.34 900 498.74 ;
    END
  END limits_i.lim_rsp[58]
  PIN limits_i.lim_rsp[59]
    DIRECTION INPUT ;
    USE SIGNAL ;
    PORT
      LAYER Metal3 ;
        RECT  899.6 501.7 900 502.1 ;
    END
  END limits_i.lim_rsp[59]
  PIN limits_i.lim_rsp[5]
    DIRECTION INPUT ;
    USE SIGNAL ;
    PORT
      LAYER Metal3 ;
        RECT  899.6 320.26 900 320.66 ;
    END
  END limits_i.lim_rsp[5]
  PIN limits_i.lim_rsp[60]
    DIRECTION INPUT ;
    USE SIGNAL ;
    PORT
      LAYER Metal3 ;
        RECT  899.6 505.06 900 505.46 ;
    END
  END limits_i.lim_rsp[60]
  PIN limits_i.lim_rsp[61]
    DIRECTION INPUT ;
    USE SIGNAL ;
    PORT
      LAYER Metal3 ;
        RECT  899.6 508.42 900 508.82 ;
    END
  END limits_i.lim_rsp[61]
  PIN limits_i.lim_rsp[62]
    DIRECTION INPUT ;
    USE SIGNAL ;
    PORT
      LAYER Metal3 ;
        RECT  899.6 511.78 900 512.18 ;
    END
  END limits_i.lim_rsp[62]
  PIN limits_i.lim_rsp[63]
    DIRECTION INPUT ;
    USE SIGNAL ;
    PORT
      LAYER Metal3 ;
        RECT  899.6 515.14 900 515.54 ;
    END
  END limits_i.lim_rsp[63]
  PIN limits_i.lim_rsp[6]
    DIRECTION INPUT ;
    USE SIGNAL ;
    PORT
      LAYER Metal3 ;
        RECT  899.6 323.62 900 324.02 ;
    END
  END limits_i.lim_rsp[6]
  PIN limits_i.lim_rsp[7]
    DIRECTION INPUT ;
    USE SIGNAL ;
    PORT
      LAYER Metal3 ;
        RECT  899.6 326.98 900 327.38 ;
    END
  END limits_i.lim_rsp[7]
  PIN limits_i.lim_rsp[8]
    DIRECTION INPUT ;
    USE SIGNAL ;
    PORT
      LAYER Metal3 ;
        RECT  899.6 330.34 900 330.74 ;
    END
  END limits_i.lim_rsp[8]
  PIN limits_i.lim_rsp[9]
    DIRECTION INPUT ;
    USE SIGNAL ;
    PORT
      LAYER Metal3 ;
        RECT  899.6 333.7 900 334.1 ;
    END
  END limits_i.lim_rsp[9]
  PIN mem_ready_i
    DIRECTION INPUT ;
    USE SIGNAL ;
    PORT
      LAYER Metal3 ;
        RECT  899.6 244.66 900 245.06 ;
    END
  END mem_ready_i
  PIN mem_req_o.address[0]
    DIRECTION OUTPUT ;
    USE SIGNAL ;
    PORT
      LAYER Metal3 ;
        RECT  899.6 162.34 900 162.74 ;
    END
  END mem_req_o.address[0]
  PIN mem_req_o.address[10]
    DIRECTION OUTPUT ;
    USE SIGNAL ;
    PORT
      LAYER Metal3 ;
        RECT  899.6 180.82 900 181.22 ;
    END
  END mem_req_o.address[10]
  PIN mem_req_o.address[11]
    DIRECTION OUTPUT ;
    USE SIGNAL ;
    PORT
      LAYER Metal3 ;
        RECT  899.6 182.5 900 182.9 ;
    END
  END mem_req_o.address[11]
  PIN mem_req_o.address[12]
    DIRECTION OUTPUT ;
    USE SIGNAL ;
    PORT
      LAYER Metal3 ;
        RECT  899.6 184.18 900 184.58 ;
    END
  END mem_req_o.address[12]
  PIN mem_req_o.address[13]
    DIRECTION OUTPUT ;
    USE SIGNAL ;
    PORT
      LAYER Metal3 ;
        RECT  899.6 185.86 900 186.26 ;
    END
  END mem_req_o.address[13]
  PIN mem_req_o.address[14]
    DIRECTION OUTPUT ;
    USE SIGNAL ;
    PORT
      LAYER Metal3 ;
        RECT  899.6 187.54 900 187.94 ;
    END
  END mem_req_o.address[14]
  PIN mem_req_o.address[15]
    DIRECTION OUTPUT ;
    USE SIGNAL ;
    PORT
      LAYER Metal3 ;
        RECT  899.6 189.22 900 189.62 ;
    END
  END mem_req_o.address[15]
  PIN mem_req_o.address[16]
    DIRECTION OUTPUT ;
    USE SIGNAL ;
    PORT
      LAYER Metal3 ;
        RECT  899.6 190.9 900 191.3 ;
    END
  END mem_req_o.address[16]
  PIN mem_req_o.address[17]
    DIRECTION OUTPUT ;
    USE SIGNAL ;
    PORT
      LAYER Metal3 ;
        RECT  899.6 192.58 900 192.98 ;
    END
  END mem_req_o.address[17]
  PIN mem_req_o.address[18]
    DIRECTION OUTPUT ;
    USE SIGNAL ;
    PORT
      LAYER Metal3 ;
        RECT  899.6 194.26 900 194.66 ;
    END
  END mem_req_o.address[18]
  PIN mem_req_o.address[19]
    DIRECTION OUTPUT ;
    USE SIGNAL ;
    PORT
      LAYER Metal3 ;
        RECT  899.6 195.94 900 196.34 ;
    END
  END mem_req_o.address[19]
  PIN mem_req_o.address[1]
    DIRECTION OUTPUT ;
    USE SIGNAL ;
    PORT
      LAYER Metal3 ;
        RECT  899.6 164.86 900 165.26 ;
    END
  END mem_req_o.address[1]
  PIN mem_req_o.address[20]
    DIRECTION OUTPUT ;
    USE SIGNAL ;
    PORT
      LAYER Metal3 ;
        RECT  899.6 197.62 900 198.02 ;
    END
  END mem_req_o.address[20]
  PIN mem_req_o.address[21]
    DIRECTION OUTPUT ;
    USE SIGNAL ;
    PORT
      LAYER Metal3 ;
        RECT  899.6 199.3 900 199.7 ;
    END
  END mem_req_o.address[21]
  PIN mem_req_o.address[22]
    DIRECTION OUTPUT ;
    USE SIGNAL ;
    PORT
      LAYER Metal3 ;
        RECT  899.6 200.98 900 201.38 ;
    END
  END mem_req_o.address[22]
  PIN mem_req_o.address[23]
    DIRECTION OUTPUT ;
    USE SIGNAL ;
    PORT
      LAYER Metal3 ;
        RECT  899.6 202.66 900 203.06 ;
    END
  END mem_req_o.address[23]
  PIN mem_req_o.address[24]
    DIRECTION OUTPUT ;
    USE SIGNAL ;
    PORT
      LAYER Metal3 ;
        RECT  899.6 204.34 900 204.74 ;
    END
  END mem_req_o.address[24]
  PIN mem_req_o.address[25]
    DIRECTION OUTPUT ;
    USE SIGNAL ;
    PORT
      LAYER Metal3 ;
        RECT  899.6 206.02 900 206.42 ;
    END
  END mem_req_o.address[25]
  PIN mem_req_o.address[26]
    DIRECTION OUTPUT ;
    USE SIGNAL ;
    PORT
      LAYER Metal3 ;
        RECT  899.6 207.7 900 208.1 ;
    END
  END mem_req_o.address[26]
  PIN mem_req_o.address[27]
    DIRECTION OUTPUT ;
    USE SIGNAL ;
    PORT
      LAYER Metal3 ;
        RECT  899.6 209.38 900 209.78 ;
    END
  END mem_req_o.address[27]
  PIN mem_req_o.address[28]
    DIRECTION OUTPUT ;
    USE SIGNAL ;
    PORT
      LAYER Metal3 ;
        RECT  899.6 211.06 900 211.46 ;
    END
  END mem_req_o.address[28]
  PIN mem_req_o.address[29]
    DIRECTION OUTPUT ;
    USE SIGNAL ;
    PORT
      LAYER Metal3 ;
        RECT  899.6 212.74 900 213.14 ;
    END
  END mem_req_o.address[29]
  PIN mem_req_o.address[2]
    DIRECTION OUTPUT ;
    USE SIGNAL ;
    PORT
      LAYER Metal3 ;
        RECT  899.6 167.38 900 167.78 ;
    END
  END mem_req_o.address[2]
  PIN mem_req_o.address[30]
    DIRECTION OUTPUT ;
    USE SIGNAL ;
    PORT
      LAYER Metal3 ;
        RECT  899.6 214.42 900 214.82 ;
    END
  END mem_req_o.address[30]
  PIN mem_req_o.address[31]
    DIRECTION OUTPUT ;
    USE SIGNAL ;
    PORT
      LAYER Metal3 ;
        RECT  899.6 216.1 900 216.5 ;
    END
  END mem_req_o.address[31]
  PIN mem_req_o.address[3]
    DIRECTION OUTPUT ;
    USE SIGNAL ;
    PORT
      LAYER Metal3 ;
        RECT  899.6 169.06 900 169.46 ;
    END
  END mem_req_o.address[3]
  PIN mem_req_o.address[4]
    DIRECTION OUTPUT ;
    USE SIGNAL ;
    PORT
      LAYER Metal3 ;
        RECT  899.6 170.74 900 171.14 ;
    END
  END mem_req_o.address[4]
  PIN mem_req_o.address[5]
    DIRECTION OUTPUT ;
    USE SIGNAL ;
    PORT
      LAYER Metal3 ;
        RECT  899.6 172.42 900 172.82 ;
    END
  END mem_req_o.address[5]
  PIN mem_req_o.address[6]
    DIRECTION OUTPUT ;
    USE SIGNAL ;
    PORT
      LAYER Metal3 ;
        RECT  899.6 174.1 900 174.5 ;
    END
  END mem_req_o.address[6]
  PIN mem_req_o.address[7]
    DIRECTION OUTPUT ;
    USE SIGNAL ;
    PORT
      LAYER Metal3 ;
        RECT  899.6 175.78 900 176.18 ;
    END
  END mem_req_o.address[7]
  PIN mem_req_o.address[8]
    DIRECTION OUTPUT ;
    USE SIGNAL ;
    PORT
      LAYER Metal3 ;
        RECT  899.6 177.46 900 177.86 ;
    END
  END mem_req_o.address[8]
  PIN mem_req_o.address[9]
    DIRECTION OUTPUT ;
    USE SIGNAL ;
    PORT
      LAYER Metal3 ;
        RECT  899.6 179.14 900 179.54 ;
    END
  END mem_req_o.address[9]
  PIN mem_req_o.outside
    DIRECTION OUTPUT ;
    USE SIGNAL ;
    PORT
      LAYER Metal3 ;
        RECT  899.6 158.98 900 159.38 ;
    END
  END mem_req_o.outside
  PIN mem_req_o.probe
    DIRECTION OUTPUT ;
    USE SIGNAL ;
    PORT
      LAYER Metal3 ;
        RECT  899.6 159.82 900 160.22 ;
    END
  END mem_req_o.probe
  PIN mem_req_o.size[0]
    DIRECTION OUTPUT ;
    USE SIGNAL ;
    PORT
      LAYER Metal3 ;
        RECT  899.6 163.18 900 163.58 ;
    END
  END mem_req_o.size[0]
  PIN mem_req_o.size[1]
    DIRECTION OUTPUT ;
    USE SIGNAL ;
    PORT
      LAYER Metal3 ;
        RECT  899.6 165.7 900 166.1 ;
    END
  END mem_req_o.size[1]
  PIN mem_req_o.valid
    DIRECTION OUTPUT ;
    USE SIGNAL ;
    PORT
      LAYER Metal3 ;
        RECT  899.6 160.66 900 161.06 ;
    END
  END mem_req_o.valid
  PIN mem_req_o.wdata[0]
    DIRECTION OUTPUT ;
    USE SIGNAL ;
    PORT
      LAYER Metal3 ;
        RECT  899.6 164.02 900 164.42 ;
    END
  END mem_req_o.wdata[0]
  PIN mem_req_o.wdata[10]
    DIRECTION OUTPUT ;
    USE SIGNAL ;
    PORT
      LAYER Metal3 ;
        RECT  899.6 181.66 900 182.06 ;
    END
  END mem_req_o.wdata[10]
  PIN mem_req_o.wdata[11]
    DIRECTION OUTPUT ;
    USE SIGNAL ;
    PORT
      LAYER Metal3 ;
        RECT  899.6 183.34 900 183.74 ;
    END
  END mem_req_o.wdata[11]
  PIN mem_req_o.wdata[12]
    DIRECTION OUTPUT ;
    USE SIGNAL ;
    PORT
      LAYER Metal3 ;
        RECT  899.6 185.02 900 185.42 ;
    END
  END mem_req_o.wdata[12]
  PIN mem_req_o.wdata[13]
    DIRECTION OUTPUT ;
    USE SIGNAL ;
    PORT
      LAYER Metal3 ;
        RECT  899.6 186.7 900 187.1 ;
    END
  END mem_req_o.wdata[13]
  PIN mem_req_o.wdata[14]
    DIRECTION OUTPUT ;
    USE SIGNAL ;
    PORT
      LAYER Metal3 ;
        RECT  899.6 188.38 900 188.78 ;
    END
  END mem_req_o.wdata[14]
  PIN mem_req_o.wdata[15]
    DIRECTION OUTPUT ;
    USE SIGNAL ;
    PORT
      LAYER Metal3 ;
        RECT  899.6 190.06 900 190.46 ;
    END
  END mem_req_o.wdata[15]
  PIN mem_req_o.wdata[16]
    DIRECTION OUTPUT ;
    USE SIGNAL ;
    PORT
      LAYER Metal3 ;
        RECT  899.6 191.74 900 192.14 ;
    END
  END mem_req_o.wdata[16]
  PIN mem_req_o.wdata[17]
    DIRECTION OUTPUT ;
    USE SIGNAL ;
    PORT
      LAYER Metal3 ;
        RECT  899.6 193.42 900 193.82 ;
    END
  END mem_req_o.wdata[17]
  PIN mem_req_o.wdata[18]
    DIRECTION OUTPUT ;
    USE SIGNAL ;
    PORT
      LAYER Metal3 ;
        RECT  899.6 195.1 900 195.5 ;
    END
  END mem_req_o.wdata[18]
  PIN mem_req_o.wdata[19]
    DIRECTION OUTPUT ;
    USE SIGNAL ;
    PORT
      LAYER Metal3 ;
        RECT  899.6 196.78 900 197.18 ;
    END
  END mem_req_o.wdata[19]
  PIN mem_req_o.wdata[1]
    DIRECTION OUTPUT ;
    USE SIGNAL ;
    PORT
      LAYER Metal3 ;
        RECT  899.6 166.54 900 166.94 ;
    END
  END mem_req_o.wdata[1]
  PIN mem_req_o.wdata[20]
    DIRECTION OUTPUT ;
    USE SIGNAL ;
    PORT
      LAYER Metal3 ;
        RECT  899.6 198.46 900 198.86 ;
    END
  END mem_req_o.wdata[20]
  PIN mem_req_o.wdata[21]
    DIRECTION OUTPUT ;
    USE SIGNAL ;
    PORT
      LAYER Metal3 ;
        RECT  899.6 200.14 900 200.54 ;
    END
  END mem_req_o.wdata[21]
  PIN mem_req_o.wdata[22]
    DIRECTION OUTPUT ;
    USE SIGNAL ;
    PORT
      LAYER Metal3 ;
        RECT  899.6 201.82 900 202.22 ;
    END
  END mem_req_o.wdata[22]
  PIN mem_req_o.wdata[23]
    DIRECTION OUTPUT ;
    USE SIGNAL ;
    PORT
      LAYER Metal3 ;
        RECT  899.6 203.5 900 203.9 ;
    END
  END mem_req_o.wdata[23]
  PIN mem_req_o.wdata[24]
    DIRECTION OUTPUT ;
    USE SIGNAL ;
    PORT
      LAYER Metal3 ;
        RECT  899.6 205.18 900 205.58 ;
    END
  END mem_req_o.wdata[24]
  PIN mem_req_o.wdata[25]
    DIRECTION OUTPUT ;
    USE SIGNAL ;
    PORT
      LAYER Metal3 ;
        RECT  899.6 206.86 900 207.26 ;
    END
  END mem_req_o.wdata[25]
  PIN mem_req_o.wdata[26]
    DIRECTION OUTPUT ;
    USE SIGNAL ;
    PORT
      LAYER Metal3 ;
        RECT  899.6 208.54 900 208.94 ;
    END
  END mem_req_o.wdata[26]
  PIN mem_req_o.wdata[27]
    DIRECTION OUTPUT ;
    USE SIGNAL ;
    PORT
      LAYER Metal3 ;
        RECT  899.6 210.22 900 210.62 ;
    END
  END mem_req_o.wdata[27]
  PIN mem_req_o.wdata[28]
    DIRECTION OUTPUT ;
    USE SIGNAL ;
    PORT
      LAYER Metal3 ;
        RECT  899.6 211.9 900 212.3 ;
    END
  END mem_req_o.wdata[28]
  PIN mem_req_o.wdata[29]
    DIRECTION OUTPUT ;
    USE SIGNAL ;
    PORT
      LAYER Metal3 ;
        RECT  899.6 213.58 900 213.98 ;
    END
  END mem_req_o.wdata[29]
  PIN mem_req_o.wdata[2]
    DIRECTION OUTPUT ;
    USE SIGNAL ;
    PORT
      LAYER Metal3 ;
        RECT  899.6 168.22 900 168.62 ;
    END
  END mem_req_o.wdata[2]
  PIN mem_req_o.wdata[30]
    DIRECTION OUTPUT ;
    USE SIGNAL ;
    PORT
      LAYER Metal3 ;
        RECT  899.6 215.26 900 215.66 ;
    END
  END mem_req_o.wdata[30]
  PIN mem_req_o.wdata[31]
    DIRECTION OUTPUT ;
    USE SIGNAL ;
    PORT
      LAYER Metal3 ;
        RECT  899.6 216.94 900 217.34 ;
    END
  END mem_req_o.wdata[31]
  PIN mem_req_o.wdata[32]
    DIRECTION OUTPUT ;
    USE SIGNAL ;
    PORT
      LAYER Metal3 ;
        RECT  899.6 217.78 900 218.18 ;
    END
  END mem_req_o.wdata[32]
  PIN mem_req_o.wdata[33]
    DIRECTION OUTPUT ;
    USE SIGNAL ;
    PORT
      LAYER Metal3 ;
        RECT  899.6 218.62 900 219.02 ;
    END
  END mem_req_o.wdata[33]
  PIN mem_req_o.wdata[34]
    DIRECTION OUTPUT ;
    USE SIGNAL ;
    PORT
      LAYER Metal3 ;
        RECT  899.6 219.46 900 219.86 ;
    END
  END mem_req_o.wdata[34]
  PIN mem_req_o.wdata[35]
    DIRECTION OUTPUT ;
    USE SIGNAL ;
    PORT
      LAYER Metal3 ;
        RECT  899.6 220.3 900 220.7 ;
    END
  END mem_req_o.wdata[35]
  PIN mem_req_o.wdata[36]
    DIRECTION OUTPUT ;
    USE SIGNAL ;
    PORT
      LAYER Metal3 ;
        RECT  899.6 221.14 900 221.54 ;
    END
  END mem_req_o.wdata[36]
  PIN mem_req_o.wdata[37]
    DIRECTION OUTPUT ;
    USE SIGNAL ;
    PORT
      LAYER Metal3 ;
        RECT  899.6 221.98 900 222.38 ;
    END
  END mem_req_o.wdata[37]
  PIN mem_req_o.wdata[38]
    DIRECTION OUTPUT ;
    USE SIGNAL ;
    PORT
      LAYER Metal3 ;
        RECT  899.6 222.82 900 223.22 ;
    END
  END mem_req_o.wdata[38]
  PIN mem_req_o.wdata[39]
    DIRECTION OUTPUT ;
    USE SIGNAL ;
    PORT
      LAYER Metal3 ;
        RECT  899.6 223.66 900 224.06 ;
    END
  END mem_req_o.wdata[39]
  PIN mem_req_o.wdata[3]
    DIRECTION OUTPUT ;
    USE SIGNAL ;
    PORT
      LAYER Metal3 ;
        RECT  899.6 169.9 900 170.3 ;
    END
  END mem_req_o.wdata[3]
  PIN mem_req_o.wdata[40]
    DIRECTION OUTPUT ;
    USE SIGNAL ;
    PORT
      LAYER Metal3 ;
        RECT  899.6 224.5 900 224.9 ;
    END
  END mem_req_o.wdata[40]
  PIN mem_req_o.wdata[41]
    DIRECTION OUTPUT ;
    USE SIGNAL ;
    PORT
      LAYER Metal3 ;
        RECT  899.6 225.34 900 225.74 ;
    END
  END mem_req_o.wdata[41]
  PIN mem_req_o.wdata[42]
    DIRECTION OUTPUT ;
    USE SIGNAL ;
    PORT
      LAYER Metal3 ;
        RECT  899.6 226.18 900 226.58 ;
    END
  END mem_req_o.wdata[42]
  PIN mem_req_o.wdata[43]
    DIRECTION OUTPUT ;
    USE SIGNAL ;
    PORT
      LAYER Metal3 ;
        RECT  899.6 227.02 900 227.42 ;
    END
  END mem_req_o.wdata[43]
  PIN mem_req_o.wdata[44]
    DIRECTION OUTPUT ;
    USE SIGNAL ;
    PORT
      LAYER Metal3 ;
        RECT  899.6 227.86 900 228.26 ;
    END
  END mem_req_o.wdata[44]
  PIN mem_req_o.wdata[45]
    DIRECTION OUTPUT ;
    USE SIGNAL ;
    PORT
      LAYER Metal3 ;
        RECT  899.6 228.7 900 229.1 ;
    END
  END mem_req_o.wdata[45]
  PIN mem_req_o.wdata[46]
    DIRECTION OUTPUT ;
    USE SIGNAL ;
    PORT
      LAYER Metal3 ;
        RECT  899.6 229.54 900 229.94 ;
    END
  END mem_req_o.wdata[46]
  PIN mem_req_o.wdata[47]
    DIRECTION OUTPUT ;
    USE SIGNAL ;
    PORT
      LAYER Metal3 ;
        RECT  899.6 230.38 900 230.78 ;
    END
  END mem_req_o.wdata[47]
  PIN mem_req_o.wdata[48]
    DIRECTION OUTPUT ;
    USE SIGNAL ;
    PORT
      LAYER Metal3 ;
        RECT  899.6 231.22 900 231.62 ;
    END
  END mem_req_o.wdata[48]
  PIN mem_req_o.wdata[49]
    DIRECTION OUTPUT ;
    USE SIGNAL ;
    PORT
      LAYER Metal3 ;
        RECT  899.6 232.06 900 232.46 ;
    END
  END mem_req_o.wdata[49]
  PIN mem_req_o.wdata[4]
    DIRECTION OUTPUT ;
    USE SIGNAL ;
    PORT
      LAYER Metal3 ;
        RECT  899.6 171.58 900 171.98 ;
    END
  END mem_req_o.wdata[4]
  PIN mem_req_o.wdata[50]
    DIRECTION OUTPUT ;
    USE SIGNAL ;
    PORT
      LAYER Metal3 ;
        RECT  899.6 232.9 900 233.3 ;
    END
  END mem_req_o.wdata[50]
  PIN mem_req_o.wdata[51]
    DIRECTION OUTPUT ;
    USE SIGNAL ;
    PORT
      LAYER Metal3 ;
        RECT  899.6 233.74 900 234.14 ;
    END
  END mem_req_o.wdata[51]
  PIN mem_req_o.wdata[52]
    DIRECTION OUTPUT ;
    USE SIGNAL ;
    PORT
      LAYER Metal3 ;
        RECT  899.6 234.58 900 234.98 ;
    END
  END mem_req_o.wdata[52]
  PIN mem_req_o.wdata[53]
    DIRECTION OUTPUT ;
    USE SIGNAL ;
    PORT
      LAYER Metal3 ;
        RECT  899.6 235.42 900 235.82 ;
    END
  END mem_req_o.wdata[53]
  PIN mem_req_o.wdata[54]
    DIRECTION OUTPUT ;
    USE SIGNAL ;
    PORT
      LAYER Metal3 ;
        RECT  899.6 236.26 900 236.66 ;
    END
  END mem_req_o.wdata[54]
  PIN mem_req_o.wdata[55]
    DIRECTION OUTPUT ;
    USE SIGNAL ;
    PORT
      LAYER Metal3 ;
        RECT  899.6 237.1 900 237.5 ;
    END
  END mem_req_o.wdata[55]
  PIN mem_req_o.wdata[56]
    DIRECTION OUTPUT ;
    USE SIGNAL ;
    PORT
      LAYER Metal3 ;
        RECT  899.6 237.94 900 238.34 ;
    END
  END mem_req_o.wdata[56]
  PIN mem_req_o.wdata[57]
    DIRECTION OUTPUT ;
    USE SIGNAL ;
    PORT
      LAYER Metal3 ;
        RECT  899.6 238.78 900 239.18 ;
    END
  END mem_req_o.wdata[57]
  PIN mem_req_o.wdata[58]
    DIRECTION OUTPUT ;
    USE SIGNAL ;
    PORT
      LAYER Metal3 ;
        RECT  899.6 239.62 900 240.02 ;
    END
  END mem_req_o.wdata[58]
  PIN mem_req_o.wdata[59]
    DIRECTION OUTPUT ;
    USE SIGNAL ;
    PORT
      LAYER Metal3 ;
        RECT  899.6 240.46 900 240.86 ;
    END
  END mem_req_o.wdata[59]
  PIN mem_req_o.wdata[5]
    DIRECTION OUTPUT ;
    USE SIGNAL ;
    PORT
      LAYER Metal3 ;
        RECT  899.6 173.26 900 173.66 ;
    END
  END mem_req_o.wdata[5]
  PIN mem_req_o.wdata[60]
    DIRECTION OUTPUT ;
    USE SIGNAL ;
    PORT
      LAYER Metal3 ;
        RECT  899.6 241.3 900 241.7 ;
    END
  END mem_req_o.wdata[60]
  PIN mem_req_o.wdata[61]
    DIRECTION OUTPUT ;
    USE SIGNAL ;
    PORT
      LAYER Metal3 ;
        RECT  899.6 242.14 900 242.54 ;
    END
  END mem_req_o.wdata[61]
  PIN mem_req_o.wdata[62]
    DIRECTION OUTPUT ;
    USE SIGNAL ;
    PORT
      LAYER Metal3 ;
        RECT  899.6 242.98 900 243.38 ;
    END
  END mem_req_o.wdata[62]
  PIN mem_req_o.wdata[63]
    DIRECTION OUTPUT ;
    USE SIGNAL ;
    PORT
      LAYER Metal3 ;
        RECT  899.6 243.82 900 244.22 ;
    END
  END mem_req_o.wdata[63]
  PIN mem_req_o.wdata[6]
    DIRECTION OUTPUT ;
    USE SIGNAL ;
    PORT
      LAYER Metal3 ;
        RECT  899.6 174.94 900 175.34 ;
    END
  END mem_req_o.wdata[6]
  PIN mem_req_o.wdata[7]
    DIRECTION OUTPUT ;
    USE SIGNAL ;
    PORT
      LAYER Metal3 ;
        RECT  899.6 176.62 900 177.02 ;
    END
  END mem_req_o.wdata[7]
  PIN mem_req_o.wdata[8]
    DIRECTION OUTPUT ;
    USE SIGNAL ;
    PORT
      LAYER Metal3 ;
        RECT  899.6 178.3 900 178.7 ;
    END
  END mem_req_o.wdata[8]
  PIN mem_req_o.wdata[9]
    DIRECTION OUTPUT ;
    USE SIGNAL ;
    PORT
      LAYER Metal3 ;
        RECT  899.6 179.98 900 180.38 ;
    END
  END mem_req_o.wdata[9]
  PIN mem_req_o.write
    DIRECTION OUTPUT ;
    USE SIGNAL ;
    PORT
      LAYER Metal3 ;
        RECT  899.6 161.5 900 161.9 ;
    END
  END mem_req_o.write
  PIN mem_rsp_i.fault
    DIRECTION INPUT ;
    USE SIGNAL ;
    PORT
      LAYER Metal3 ;
        RECT  899.6 245.5 900 245.9 ;
    END
  END mem_rsp_i.fault
  PIN mem_rsp_i.rdata[0]
    DIRECTION INPUT ;
    USE SIGNAL ;
    PORT
      LAYER Metal3 ;
        RECT  899.6 247.18 900 247.58 ;
    END
  END mem_rsp_i.rdata[0]
  PIN mem_rsp_i.rdata[10]
    DIRECTION INPUT ;
    USE SIGNAL ;
    PORT
      LAYER Metal3 ;
        RECT  899.6 255.58 900 255.98 ;
    END
  END mem_rsp_i.rdata[10]
  PIN mem_rsp_i.rdata[11]
    DIRECTION INPUT ;
    USE SIGNAL ;
    PORT
      LAYER Metal3 ;
        RECT  899.6 256.42 900 256.82 ;
    END
  END mem_rsp_i.rdata[11]
  PIN mem_rsp_i.rdata[12]
    DIRECTION INPUT ;
    USE SIGNAL ;
    PORT
      LAYER Metal3 ;
        RECT  899.6 257.26 900 257.66 ;
    END
  END mem_rsp_i.rdata[12]
  PIN mem_rsp_i.rdata[13]
    DIRECTION INPUT ;
    USE SIGNAL ;
    PORT
      LAYER Metal3 ;
        RECT  899.6 258.1 900 258.5 ;
    END
  END mem_rsp_i.rdata[13]
  PIN mem_rsp_i.rdata[14]
    DIRECTION INPUT ;
    USE SIGNAL ;
    PORT
      LAYER Metal3 ;
        RECT  899.6 258.94 900 259.34 ;
    END
  END mem_rsp_i.rdata[14]
  PIN mem_rsp_i.rdata[15]
    DIRECTION INPUT ;
    USE SIGNAL ;
    PORT
      LAYER Metal3 ;
        RECT  899.6 259.78 900 260.18 ;
    END
  END mem_rsp_i.rdata[15]
  PIN mem_rsp_i.rdata[16]
    DIRECTION INPUT ;
    USE SIGNAL ;
    PORT
      LAYER Metal3 ;
        RECT  899.6 260.62 900 261.02 ;
    END
  END mem_rsp_i.rdata[16]
  PIN mem_rsp_i.rdata[17]
    DIRECTION INPUT ;
    USE SIGNAL ;
    PORT
      LAYER Metal3 ;
        RECT  899.6 261.46 900 261.86 ;
    END
  END mem_rsp_i.rdata[17]
  PIN mem_rsp_i.rdata[18]
    DIRECTION INPUT ;
    USE SIGNAL ;
    PORT
      LAYER Metal3 ;
        RECT  899.6 262.3 900 262.7 ;
    END
  END mem_rsp_i.rdata[18]
  PIN mem_rsp_i.rdata[19]
    DIRECTION INPUT ;
    USE SIGNAL ;
    PORT
      LAYER Metal3 ;
        RECT  899.6 263.14 900 263.54 ;
    END
  END mem_rsp_i.rdata[19]
  PIN mem_rsp_i.rdata[1]
    DIRECTION INPUT ;
    USE SIGNAL ;
    PORT
      LAYER Metal3 ;
        RECT  899.6 248.02 900 248.42 ;
    END
  END mem_rsp_i.rdata[1]
  PIN mem_rsp_i.rdata[20]
    DIRECTION INPUT ;
    USE SIGNAL ;
    PORT
      LAYER Metal3 ;
        RECT  899.6 263.98 900 264.38 ;
    END
  END mem_rsp_i.rdata[20]
  PIN mem_rsp_i.rdata[21]
    DIRECTION INPUT ;
    USE SIGNAL ;
    PORT
      LAYER Metal3 ;
        RECT  899.6 264.82 900 265.22 ;
    END
  END mem_rsp_i.rdata[21]
  PIN mem_rsp_i.rdata[22]
    DIRECTION INPUT ;
    USE SIGNAL ;
    PORT
      LAYER Metal3 ;
        RECT  899.6 265.66 900 266.06 ;
    END
  END mem_rsp_i.rdata[22]
  PIN mem_rsp_i.rdata[23]
    DIRECTION INPUT ;
    USE SIGNAL ;
    PORT
      LAYER Metal3 ;
        RECT  899.6 266.5 900 266.9 ;
    END
  END mem_rsp_i.rdata[23]
  PIN mem_rsp_i.rdata[24]
    DIRECTION INPUT ;
    USE SIGNAL ;
    PORT
      LAYER Metal3 ;
        RECT  899.6 267.34 900 267.74 ;
    END
  END mem_rsp_i.rdata[24]
  PIN mem_rsp_i.rdata[25]
    DIRECTION INPUT ;
    USE SIGNAL ;
    PORT
      LAYER Metal3 ;
        RECT  899.6 268.18 900 268.58 ;
    END
  END mem_rsp_i.rdata[25]
  PIN mem_rsp_i.rdata[26]
    DIRECTION INPUT ;
    USE SIGNAL ;
    PORT
      LAYER Metal3 ;
        RECT  899.6 269.02 900 269.42 ;
    END
  END mem_rsp_i.rdata[26]
  PIN mem_rsp_i.rdata[27]
    DIRECTION INPUT ;
    USE SIGNAL ;
    PORT
      LAYER Metal3 ;
        RECT  899.6 269.86 900 270.26 ;
    END
  END mem_rsp_i.rdata[27]
  PIN mem_rsp_i.rdata[28]
    DIRECTION INPUT ;
    USE SIGNAL ;
    PORT
      LAYER Metal3 ;
        RECT  899.6 270.7 900 271.1 ;
    END
  END mem_rsp_i.rdata[28]
  PIN mem_rsp_i.rdata[29]
    DIRECTION INPUT ;
    USE SIGNAL ;
    PORT
      LAYER Metal3 ;
        RECT  899.6 271.54 900 271.94 ;
    END
  END mem_rsp_i.rdata[29]
  PIN mem_rsp_i.rdata[2]
    DIRECTION INPUT ;
    USE SIGNAL ;
    PORT
      LAYER Metal3 ;
        RECT  899.6 248.86 900 249.26 ;
    END
  END mem_rsp_i.rdata[2]
  PIN mem_rsp_i.rdata[30]
    DIRECTION INPUT ;
    USE SIGNAL ;
    PORT
      LAYER Metal3 ;
        RECT  899.6 272.38 900 272.78 ;
    END
  END mem_rsp_i.rdata[30]
  PIN mem_rsp_i.rdata[31]
    DIRECTION INPUT ;
    USE SIGNAL ;
    PORT
      LAYER Metal3 ;
        RECT  899.6 273.22 900 273.62 ;
    END
  END mem_rsp_i.rdata[31]
  PIN mem_rsp_i.rdata[32]
    DIRECTION INPUT ;
    USE SIGNAL ;
    PORT
      LAYER Metal3 ;
        RECT  899.6 274.06 900 274.46 ;
    END
  END mem_rsp_i.rdata[32]
  PIN mem_rsp_i.rdata[33]
    DIRECTION INPUT ;
    USE SIGNAL ;
    PORT
      LAYER Metal3 ;
        RECT  899.6 274.9 900 275.3 ;
    END
  END mem_rsp_i.rdata[33]
  PIN mem_rsp_i.rdata[34]
    DIRECTION INPUT ;
    USE SIGNAL ;
    PORT
      LAYER Metal3 ;
        RECT  899.6 275.74 900 276.14 ;
    END
  END mem_rsp_i.rdata[34]
  PIN mem_rsp_i.rdata[35]
    DIRECTION INPUT ;
    USE SIGNAL ;
    PORT
      LAYER Metal3 ;
        RECT  899.6 276.58 900 276.98 ;
    END
  END mem_rsp_i.rdata[35]
  PIN mem_rsp_i.rdata[36]
    DIRECTION INPUT ;
    USE SIGNAL ;
    PORT
      LAYER Metal3 ;
        RECT  899.6 277.42 900 277.82 ;
    END
  END mem_rsp_i.rdata[36]
  PIN mem_rsp_i.rdata[37]
    DIRECTION INPUT ;
    USE SIGNAL ;
    PORT
      LAYER Metal3 ;
        RECT  899.6 278.26 900 278.66 ;
    END
  END mem_rsp_i.rdata[37]
  PIN mem_rsp_i.rdata[38]
    DIRECTION INPUT ;
    USE SIGNAL ;
    PORT
      LAYER Metal3 ;
        RECT  899.6 279.1 900 279.5 ;
    END
  END mem_rsp_i.rdata[38]
  PIN mem_rsp_i.rdata[39]
    DIRECTION INPUT ;
    USE SIGNAL ;
    PORT
      LAYER Metal3 ;
        RECT  899.6 279.94 900 280.34 ;
    END
  END mem_rsp_i.rdata[39]
  PIN mem_rsp_i.rdata[3]
    DIRECTION INPUT ;
    USE SIGNAL ;
    PORT
      LAYER Metal3 ;
        RECT  899.6 249.7 900 250.1 ;
    END
  END mem_rsp_i.rdata[3]
  PIN mem_rsp_i.rdata[40]
    DIRECTION INPUT ;
    USE SIGNAL ;
    PORT
      LAYER Metal3 ;
        RECT  899.6 280.78 900 281.18 ;
    END
  END mem_rsp_i.rdata[40]
  PIN mem_rsp_i.rdata[41]
    DIRECTION INPUT ;
    USE SIGNAL ;
    PORT
      LAYER Metal3 ;
        RECT  899.6 281.62 900 282.02 ;
    END
  END mem_rsp_i.rdata[41]
  PIN mem_rsp_i.rdata[42]
    DIRECTION INPUT ;
    USE SIGNAL ;
    PORT
      LAYER Metal3 ;
        RECT  899.6 282.46 900 282.86 ;
    END
  END mem_rsp_i.rdata[42]
  PIN mem_rsp_i.rdata[43]
    DIRECTION INPUT ;
    USE SIGNAL ;
    PORT
      LAYER Metal3 ;
        RECT  899.6 283.3 900 283.7 ;
    END
  END mem_rsp_i.rdata[43]
  PIN mem_rsp_i.rdata[44]
    DIRECTION INPUT ;
    USE SIGNAL ;
    PORT
      LAYER Metal3 ;
        RECT  899.6 284.14 900 284.54 ;
    END
  END mem_rsp_i.rdata[44]
  PIN mem_rsp_i.rdata[45]
    DIRECTION INPUT ;
    USE SIGNAL ;
    PORT
      LAYER Metal3 ;
        RECT  899.6 284.98 900 285.38 ;
    END
  END mem_rsp_i.rdata[45]
  PIN mem_rsp_i.rdata[46]
    DIRECTION INPUT ;
    USE SIGNAL ;
    PORT
      LAYER Metal3 ;
        RECT  899.6 285.82 900 286.22 ;
    END
  END mem_rsp_i.rdata[46]
  PIN mem_rsp_i.rdata[47]
    DIRECTION INPUT ;
    USE SIGNAL ;
    PORT
      LAYER Metal3 ;
        RECT  899.6 286.66 900 287.06 ;
    END
  END mem_rsp_i.rdata[47]
  PIN mem_rsp_i.rdata[48]
    DIRECTION INPUT ;
    USE SIGNAL ;
    PORT
      LAYER Metal3 ;
        RECT  899.6 287.5 900 287.9 ;
    END
  END mem_rsp_i.rdata[48]
  PIN mem_rsp_i.rdata[49]
    DIRECTION INPUT ;
    USE SIGNAL ;
    PORT
      LAYER Metal3 ;
        RECT  899.6 288.34 900 288.74 ;
    END
  END mem_rsp_i.rdata[49]
  PIN mem_rsp_i.rdata[4]
    DIRECTION INPUT ;
    USE SIGNAL ;
    PORT
      LAYER Metal3 ;
        RECT  899.6 250.54 900 250.94 ;
    END
  END mem_rsp_i.rdata[4]
  PIN mem_rsp_i.rdata[50]
    DIRECTION INPUT ;
    USE SIGNAL ;
    PORT
      LAYER Metal3 ;
        RECT  899.6 289.18 900 289.58 ;
    END
  END mem_rsp_i.rdata[50]
  PIN mem_rsp_i.rdata[51]
    DIRECTION INPUT ;
    USE SIGNAL ;
    PORT
      LAYER Metal3 ;
        RECT  899.6 290.02 900 290.42 ;
    END
  END mem_rsp_i.rdata[51]
  PIN mem_rsp_i.rdata[52]
    DIRECTION INPUT ;
    USE SIGNAL ;
    PORT
      LAYER Metal3 ;
        RECT  899.6 290.86 900 291.26 ;
    END
  END mem_rsp_i.rdata[52]
  PIN mem_rsp_i.rdata[53]
    DIRECTION INPUT ;
    USE SIGNAL ;
    PORT
      LAYER Metal3 ;
        RECT  899.6 291.7 900 292.1 ;
    END
  END mem_rsp_i.rdata[53]
  PIN mem_rsp_i.rdata[54]
    DIRECTION INPUT ;
    USE SIGNAL ;
    PORT
      LAYER Metal3 ;
        RECT  899.6 292.54 900 292.94 ;
    END
  END mem_rsp_i.rdata[54]
  PIN mem_rsp_i.rdata[55]
    DIRECTION INPUT ;
    USE SIGNAL ;
    PORT
      LAYER Metal3 ;
        RECT  899.6 293.38 900 293.78 ;
    END
  END mem_rsp_i.rdata[55]
  PIN mem_rsp_i.rdata[56]
    DIRECTION INPUT ;
    USE SIGNAL ;
    PORT
      LAYER Metal3 ;
        RECT  899.6 294.22 900 294.62 ;
    END
  END mem_rsp_i.rdata[56]
  PIN mem_rsp_i.rdata[57]
    DIRECTION INPUT ;
    USE SIGNAL ;
    PORT
      LAYER Metal3 ;
        RECT  899.6 295.06 900 295.46 ;
    END
  END mem_rsp_i.rdata[57]
  PIN mem_rsp_i.rdata[58]
    DIRECTION INPUT ;
    USE SIGNAL ;
    PORT
      LAYER Metal3 ;
        RECT  899.6 295.9 900 296.3 ;
    END
  END mem_rsp_i.rdata[58]
  PIN mem_rsp_i.rdata[59]
    DIRECTION INPUT ;
    USE SIGNAL ;
    PORT
      LAYER Metal3 ;
        RECT  899.6 296.74 900 297.14 ;
    END
  END mem_rsp_i.rdata[59]
  PIN mem_rsp_i.rdata[5]
    DIRECTION INPUT ;
    USE SIGNAL ;
    PORT
      LAYER Metal3 ;
        RECT  899.6 251.38 900 251.78 ;
    END
  END mem_rsp_i.rdata[5]
  PIN mem_rsp_i.rdata[60]
    DIRECTION INPUT ;
    USE SIGNAL ;
    PORT
      LAYER Metal3 ;
        RECT  899.6 297.58 900 297.98 ;
    END
  END mem_rsp_i.rdata[60]
  PIN mem_rsp_i.rdata[61]
    DIRECTION INPUT ;
    USE SIGNAL ;
    PORT
      LAYER Metal3 ;
        RECT  899.6 298.42 900 298.82 ;
    END
  END mem_rsp_i.rdata[61]
  PIN mem_rsp_i.rdata[62]
    DIRECTION INPUT ;
    USE SIGNAL ;
    PORT
      LAYER Metal3 ;
        RECT  899.6 299.26 900 299.66 ;
    END
  END mem_rsp_i.rdata[62]
  PIN mem_rsp_i.rdata[63]
    DIRECTION INPUT ;
    USE SIGNAL ;
    PORT
      LAYER Metal3 ;
        RECT  899.6 300.1 900 300.5 ;
    END
  END mem_rsp_i.rdata[63]
  PIN mem_rsp_i.rdata[6]
    DIRECTION INPUT ;
    USE SIGNAL ;
    PORT
      LAYER Metal3 ;
        RECT  899.6 252.22 900 252.62 ;
    END
  END mem_rsp_i.rdata[6]
  PIN mem_rsp_i.rdata[7]
    DIRECTION INPUT ;
    USE SIGNAL ;
    PORT
      LAYER Metal3 ;
        RECT  899.6 253.06 900 253.46 ;
    END
  END mem_rsp_i.rdata[7]
  PIN mem_rsp_i.rdata[8]
    DIRECTION INPUT ;
    USE SIGNAL ;
    PORT
      LAYER Metal3 ;
        RECT  899.6 253.9 900 254.3 ;
    END
  END mem_rsp_i.rdata[8]
  PIN mem_rsp_i.rdata[9]
    DIRECTION INPUT ;
    USE SIGNAL ;
    PORT
      LAYER Metal3 ;
        RECT  899.6 254.74 900 255.14 ;
    END
  END mem_rsp_i.rdata[9]
  PIN mem_rsp_i.valid
    DIRECTION INPUT ;
    USE SIGNAL ;
    PORT
      LAYER Metal3 ;
        RECT  899.6 246.34 900 246.74 ;
    END
  END mem_rsp_i.valid
  PIN reset_i
    DIRECTION INPUT ;
    USE SIGNAL ;
    PORT
      LAYER Metal2 ;
        RECT  74.2 999.6 74.6 1000 ;
    END
  END reset_i
  PIN stack_maint_done_i
    DIRECTION INPUT ;
    USE SIGNAL ;
    PORT
      LAYER Metal2 ;
        RECT  824.92 999.6 825.32 1000 ;
    END
  END stack_maint_done_i
  PIN stack_maint_o.base[0]
    DIRECTION OUTPUT ;
    USE SIGNAL ;
    PORT
      LAYER Metal2 ;
        RECT  700.12 999.6 700.52 1000 ;
    END
  END stack_maint_o.base[0]
  PIN stack_maint_o.base[10]
    DIRECTION OUTPUT ;
    USE SIGNAL ;
    PORT
      LAYER Metal2 ;
        RECT  721.24 999.6 721.64 1000 ;
    END
  END stack_maint_o.base[10]
  PIN stack_maint_o.base[11]
    DIRECTION OUTPUT ;
    USE SIGNAL ;
    PORT
      LAYER Metal2 ;
        RECT  723.16 999.6 723.56 1000 ;
    END
  END stack_maint_o.base[11]
  PIN stack_maint_o.base[12]
    DIRECTION OUTPUT ;
    USE SIGNAL ;
    PORT
      LAYER Metal2 ;
        RECT  725.08 999.6 725.48 1000 ;
    END
  END stack_maint_o.base[12]
  PIN stack_maint_o.base[13]
    DIRECTION OUTPUT ;
    USE SIGNAL ;
    PORT
      LAYER Metal2 ;
        RECT  727 999.6 727.4 1000 ;
    END
  END stack_maint_o.base[13]
  PIN stack_maint_o.base[14]
    DIRECTION OUTPUT ;
    USE SIGNAL ;
    PORT
      LAYER Metal2 ;
        RECT  728.92 999.6 729.32 1000 ;
    END
  END stack_maint_o.base[14]
  PIN stack_maint_o.base[15]
    DIRECTION OUTPUT ;
    USE SIGNAL ;
    PORT
      LAYER Metal2 ;
        RECT  730.84 999.6 731.24 1000 ;
    END
  END stack_maint_o.base[15]
  PIN stack_maint_o.base[16]
    DIRECTION OUTPUT ;
    USE SIGNAL ;
    PORT
      LAYER Metal2 ;
        RECT  732.76 999.6 733.16 1000 ;
    END
  END stack_maint_o.base[16]
  PIN stack_maint_o.base[17]
    DIRECTION OUTPUT ;
    USE SIGNAL ;
    PORT
      LAYER Metal2 ;
        RECT  734.68 999.6 735.08 1000 ;
    END
  END stack_maint_o.base[17]
  PIN stack_maint_o.base[18]
    DIRECTION OUTPUT ;
    USE SIGNAL ;
    PORT
      LAYER Metal2 ;
        RECT  736.6 999.6 737 1000 ;
    END
  END stack_maint_o.base[18]
  PIN stack_maint_o.base[19]
    DIRECTION OUTPUT ;
    USE SIGNAL ;
    PORT
      LAYER Metal2 ;
        RECT  738.52 999.6 738.92 1000 ;
    END
  END stack_maint_o.base[19]
  PIN stack_maint_o.base[1]
    DIRECTION OUTPUT ;
    USE SIGNAL ;
    PORT
      LAYER Metal2 ;
        RECT  703 999.6 703.4 1000 ;
    END
  END stack_maint_o.base[1]
  PIN stack_maint_o.base[20]
    DIRECTION OUTPUT ;
    USE SIGNAL ;
    PORT
      LAYER Metal2 ;
        RECT  740.44 999.6 740.84 1000 ;
    END
  END stack_maint_o.base[20]
  PIN stack_maint_o.base[21]
    DIRECTION OUTPUT ;
    USE SIGNAL ;
    PORT
      LAYER Metal2 ;
        RECT  742.36 999.6 742.76 1000 ;
    END
  END stack_maint_o.base[21]
  PIN stack_maint_o.base[22]
    DIRECTION OUTPUT ;
    USE SIGNAL ;
    PORT
      LAYER Metal2 ;
        RECT  744.28 999.6 744.68 1000 ;
    END
  END stack_maint_o.base[22]
  PIN stack_maint_o.base[23]
    DIRECTION OUTPUT ;
    USE SIGNAL ;
    PORT
      LAYER Metal2 ;
        RECT  746.2 999.6 746.6 1000 ;
    END
  END stack_maint_o.base[23]
  PIN stack_maint_o.base[24]
    DIRECTION OUTPUT ;
    USE SIGNAL ;
    PORT
      LAYER Metal2 ;
        RECT  748.12 999.6 748.52 1000 ;
    END
  END stack_maint_o.base[24]
  PIN stack_maint_o.base[25]
    DIRECTION OUTPUT ;
    USE SIGNAL ;
    PORT
      LAYER Metal2 ;
        RECT  750.04 999.6 750.44 1000 ;
    END
  END stack_maint_o.base[25]
  PIN stack_maint_o.base[26]
    DIRECTION OUTPUT ;
    USE SIGNAL ;
    PORT
      LAYER Metal2 ;
        RECT  751.96 999.6 752.36 1000 ;
    END
  END stack_maint_o.base[26]
  PIN stack_maint_o.base[27]
    DIRECTION OUTPUT ;
    USE SIGNAL ;
    PORT
      LAYER Metal2 ;
        RECT  753.88 999.6 754.28 1000 ;
    END
  END stack_maint_o.base[27]
  PIN stack_maint_o.base[28]
    DIRECTION OUTPUT ;
    USE SIGNAL ;
    PORT
      LAYER Metal2 ;
        RECT  755.8 999.6 756.2 1000 ;
    END
  END stack_maint_o.base[28]
  PIN stack_maint_o.base[29]
    DIRECTION OUTPUT ;
    USE SIGNAL ;
    PORT
      LAYER Metal2 ;
        RECT  757.72 999.6 758.12 1000 ;
    END
  END stack_maint_o.base[29]
  PIN stack_maint_o.base[2]
    DIRECTION OUTPUT ;
    USE SIGNAL ;
    PORT
      LAYER Metal2 ;
        RECT  705.88 999.6 706.28 1000 ;
    END
  END stack_maint_o.base[2]
  PIN stack_maint_o.base[30]
    DIRECTION OUTPUT ;
    USE SIGNAL ;
    PORT
      LAYER Metal2 ;
        RECT  759.64 999.6 760.04 1000 ;
    END
  END stack_maint_o.base[30]
  PIN stack_maint_o.base[31]
    DIRECTION OUTPUT ;
    USE SIGNAL ;
    PORT
      LAYER Metal2 ;
        RECT  761.56 999.6 761.96 1000 ;
    END
  END stack_maint_o.base[31]
  PIN stack_maint_o.base[32]
    DIRECTION OUTPUT ;
    USE SIGNAL ;
    PORT
      LAYER Metal2 ;
        RECT  763.48 999.6 763.88 1000 ;
    END
  END stack_maint_o.base[32]
  PIN stack_maint_o.base[33]
    DIRECTION OUTPUT ;
    USE SIGNAL ;
    PORT
      LAYER Metal2 ;
        RECT  765.4 999.6 765.8 1000 ;
    END
  END stack_maint_o.base[33]
  PIN stack_maint_o.base[34]
    DIRECTION OUTPUT ;
    USE SIGNAL ;
    PORT
      LAYER Metal2 ;
        RECT  767.32 999.6 767.72 1000 ;
    END
  END stack_maint_o.base[34]
  PIN stack_maint_o.base[35]
    DIRECTION OUTPUT ;
    USE SIGNAL ;
    PORT
      LAYER Metal2 ;
        RECT  769.24 999.6 769.64 1000 ;
    END
  END stack_maint_o.base[35]
  PIN stack_maint_o.base[36]
    DIRECTION OUTPUT ;
    USE SIGNAL ;
    PORT
      LAYER Metal2 ;
        RECT  771.16 999.6 771.56 1000 ;
    END
  END stack_maint_o.base[36]
  PIN stack_maint_o.base[37]
    DIRECTION OUTPUT ;
    USE SIGNAL ;
    PORT
      LAYER Metal2 ;
        RECT  773.08 999.6 773.48 1000 ;
    END
  END stack_maint_o.base[37]
  PIN stack_maint_o.base[38]
    DIRECTION OUTPUT ;
    USE SIGNAL ;
    PORT
      LAYER Metal2 ;
        RECT  775 999.6 775.4 1000 ;
    END
  END stack_maint_o.base[38]
  PIN stack_maint_o.base[39]
    DIRECTION OUTPUT ;
    USE SIGNAL ;
    PORT
      LAYER Metal2 ;
        RECT  776.92 999.6 777.32 1000 ;
    END
  END stack_maint_o.base[39]
  PIN stack_maint_o.base[3]
    DIRECTION OUTPUT ;
    USE SIGNAL ;
    PORT
      LAYER Metal2 ;
        RECT  707.8 999.6 708.2 1000 ;
    END
  END stack_maint_o.base[3]
  PIN stack_maint_o.base[40]
    DIRECTION OUTPUT ;
    USE SIGNAL ;
    PORT
      LAYER Metal2 ;
        RECT  778.84 999.6 779.24 1000 ;
    END
  END stack_maint_o.base[40]
  PIN stack_maint_o.base[41]
    DIRECTION OUTPUT ;
    USE SIGNAL ;
    PORT
      LAYER Metal2 ;
        RECT  780.76 999.6 781.16 1000 ;
    END
  END stack_maint_o.base[41]
  PIN stack_maint_o.base[42]
    DIRECTION OUTPUT ;
    USE SIGNAL ;
    PORT
      LAYER Metal2 ;
        RECT  782.68 999.6 783.08 1000 ;
    END
  END stack_maint_o.base[42]
  PIN stack_maint_o.base[43]
    DIRECTION OUTPUT ;
    USE SIGNAL ;
    PORT
      LAYER Metal2 ;
        RECT  784.6 999.6 785 1000 ;
    END
  END stack_maint_o.base[43]
  PIN stack_maint_o.base[44]
    DIRECTION OUTPUT ;
    USE SIGNAL ;
    PORT
      LAYER Metal2 ;
        RECT  786.52 999.6 786.92 1000 ;
    END
  END stack_maint_o.base[44]
  PIN stack_maint_o.base[45]
    DIRECTION OUTPUT ;
    USE SIGNAL ;
    PORT
      LAYER Metal2 ;
        RECT  788.44 999.6 788.84 1000 ;
    END
  END stack_maint_o.base[45]
  PIN stack_maint_o.base[46]
    DIRECTION OUTPUT ;
    USE SIGNAL ;
    PORT
      LAYER Metal2 ;
        RECT  790.36 999.6 790.76 1000 ;
    END
  END stack_maint_o.base[46]
  PIN stack_maint_o.base[47]
    DIRECTION OUTPUT ;
    USE SIGNAL ;
    PORT
      LAYER Metal2 ;
        RECT  792.28 999.6 792.68 1000 ;
    END
  END stack_maint_o.base[47]
  PIN stack_maint_o.base[48]
    DIRECTION OUTPUT ;
    USE SIGNAL ;
    PORT
      LAYER Metal2 ;
        RECT  794.2 999.6 794.6 1000 ;
    END
  END stack_maint_o.base[48]
  PIN stack_maint_o.base[49]
    DIRECTION OUTPUT ;
    USE SIGNAL ;
    PORT
      LAYER Metal2 ;
        RECT  796.12 999.6 796.52 1000 ;
    END
  END stack_maint_o.base[49]
  PIN stack_maint_o.base[4]
    DIRECTION OUTPUT ;
    USE SIGNAL ;
    PORT
      LAYER Metal2 ;
        RECT  709.72 999.6 710.12 1000 ;
    END
  END stack_maint_o.base[4]
  PIN stack_maint_o.base[50]
    DIRECTION OUTPUT ;
    USE SIGNAL ;
    PORT
      LAYER Metal2 ;
        RECT  798.04 999.6 798.44 1000 ;
    END
  END stack_maint_o.base[50]
  PIN stack_maint_o.base[51]
    DIRECTION OUTPUT ;
    USE SIGNAL ;
    PORT
      LAYER Metal2 ;
        RECT  799.96 999.6 800.36 1000 ;
    END
  END stack_maint_o.base[51]
  PIN stack_maint_o.base[52]
    DIRECTION OUTPUT ;
    USE SIGNAL ;
    PORT
      LAYER Metal2 ;
        RECT  801.88 999.6 802.28 1000 ;
    END
  END stack_maint_o.base[52]
  PIN stack_maint_o.base[53]
    DIRECTION OUTPUT ;
    USE SIGNAL ;
    PORT
      LAYER Metal2 ;
        RECT  803.8 999.6 804.2 1000 ;
    END
  END stack_maint_o.base[53]
  PIN stack_maint_o.base[54]
    DIRECTION OUTPUT ;
    USE SIGNAL ;
    PORT
      LAYER Metal2 ;
        RECT  805.72 999.6 806.12 1000 ;
    END
  END stack_maint_o.base[54]
  PIN stack_maint_o.base[55]
    DIRECTION OUTPUT ;
    USE SIGNAL ;
    PORT
      LAYER Metal2 ;
        RECT  807.64 999.6 808.04 1000 ;
    END
  END stack_maint_o.base[55]
  PIN stack_maint_o.base[56]
    DIRECTION OUTPUT ;
    USE SIGNAL ;
    PORT
      LAYER Metal2 ;
        RECT  809.56 999.6 809.96 1000 ;
    END
  END stack_maint_o.base[56]
  PIN stack_maint_o.base[57]
    DIRECTION OUTPUT ;
    USE SIGNAL ;
    PORT
      LAYER Metal2 ;
        RECT  811.48 999.6 811.88 1000 ;
    END
  END stack_maint_o.base[57]
  PIN stack_maint_o.base[58]
    DIRECTION OUTPUT ;
    USE SIGNAL ;
    PORT
      LAYER Metal2 ;
        RECT  813.4 999.6 813.8 1000 ;
    END
  END stack_maint_o.base[58]
  PIN stack_maint_o.base[59]
    DIRECTION OUTPUT ;
    USE SIGNAL ;
    PORT
      LAYER Metal2 ;
        RECT  815.32 999.6 815.72 1000 ;
    END
  END stack_maint_o.base[59]
  PIN stack_maint_o.base[5]
    DIRECTION OUTPUT ;
    USE SIGNAL ;
    PORT
      LAYER Metal2 ;
        RECT  711.64 999.6 712.04 1000 ;
    END
  END stack_maint_o.base[5]
  PIN stack_maint_o.base[60]
    DIRECTION OUTPUT ;
    USE SIGNAL ;
    PORT
      LAYER Metal2 ;
        RECT  817.24 999.6 817.64 1000 ;
    END
  END stack_maint_o.base[60]
  PIN stack_maint_o.base[61]
    DIRECTION OUTPUT ;
    USE SIGNAL ;
    PORT
      LAYER Metal2 ;
        RECT  819.16 999.6 819.56 1000 ;
    END
  END stack_maint_o.base[61]
  PIN stack_maint_o.base[62]
    DIRECTION OUTPUT ;
    USE SIGNAL ;
    PORT
      LAYER Metal2 ;
        RECT  821.08 999.6 821.48 1000 ;
    END
  END stack_maint_o.base[62]
  PIN stack_maint_o.base[63]
    DIRECTION OUTPUT ;
    USE SIGNAL ;
    PORT
      LAYER Metal2 ;
        RECT  823 999.6 823.4 1000 ;
    END
  END stack_maint_o.base[63]
  PIN stack_maint_o.base[6]
    DIRECTION OUTPUT ;
    USE SIGNAL ;
    PORT
      LAYER Metal2 ;
        RECT  713.56 999.6 713.96 1000 ;
    END
  END stack_maint_o.base[6]
  PIN stack_maint_o.base[7]
    DIRECTION OUTPUT ;
    USE SIGNAL ;
    PORT
      LAYER Metal2 ;
        RECT  715.48 999.6 715.88 1000 ;
    END
  END stack_maint_o.base[7]
  PIN stack_maint_o.base[8]
    DIRECTION OUTPUT ;
    USE SIGNAL ;
    PORT
      LAYER Metal2 ;
        RECT  717.4 999.6 717.8 1000 ;
    END
  END stack_maint_o.base[8]
  PIN stack_maint_o.base[9]
    DIRECTION OUTPUT ;
    USE SIGNAL ;
    PORT
      LAYER Metal2 ;
        RECT  719.32 999.6 719.72 1000 ;
    END
  END stack_maint_o.base[9]
  PIN stack_maint_o.kind[0]
    DIRECTION OUTPUT ;
    USE SIGNAL ;
    PORT
      LAYER Metal2 ;
        RECT  701.08 999.6 701.48 1000 ;
    END
  END stack_maint_o.kind[0]
  PIN stack_maint_o.kind[1]
    DIRECTION OUTPUT ;
    USE SIGNAL ;
    PORT
      LAYER Metal2 ;
        RECT  703.96 999.6 704.36 1000 ;
    END
  END stack_maint_o.kind[1]
  PIN stack_maint_o.length[0]
    DIRECTION OUTPUT ;
    USE SIGNAL ;
    PORT
      LAYER Metal2 ;
        RECT  702.04 999.6 702.44 1000 ;
    END
  END stack_maint_o.length[0]
  PIN stack_maint_o.length[10]
    DIRECTION OUTPUT ;
    USE SIGNAL ;
    PORT
      LAYER Metal2 ;
        RECT  722.2 999.6 722.6 1000 ;
    END
  END stack_maint_o.length[10]
  PIN stack_maint_o.length[11]
    DIRECTION OUTPUT ;
    USE SIGNAL ;
    PORT
      LAYER Metal2 ;
        RECT  724.12 999.6 724.52 1000 ;
    END
  END stack_maint_o.length[11]
  PIN stack_maint_o.length[12]
    DIRECTION OUTPUT ;
    USE SIGNAL ;
    PORT
      LAYER Metal2 ;
        RECT  726.04 999.6 726.44 1000 ;
    END
  END stack_maint_o.length[12]
  PIN stack_maint_o.length[13]
    DIRECTION OUTPUT ;
    USE SIGNAL ;
    PORT
      LAYER Metal2 ;
        RECT  727.96 999.6 728.36 1000 ;
    END
  END stack_maint_o.length[13]
  PIN stack_maint_o.length[14]
    DIRECTION OUTPUT ;
    USE SIGNAL ;
    PORT
      LAYER Metal2 ;
        RECT  729.88 999.6 730.28 1000 ;
    END
  END stack_maint_o.length[14]
  PIN stack_maint_o.length[15]
    DIRECTION OUTPUT ;
    USE SIGNAL ;
    PORT
      LAYER Metal2 ;
        RECT  731.8 999.6 732.2 1000 ;
    END
  END stack_maint_o.length[15]
  PIN stack_maint_o.length[16]
    DIRECTION OUTPUT ;
    USE SIGNAL ;
    PORT
      LAYER Metal2 ;
        RECT  733.72 999.6 734.12 1000 ;
    END
  END stack_maint_o.length[16]
  PIN stack_maint_o.length[17]
    DIRECTION OUTPUT ;
    USE SIGNAL ;
    PORT
      LAYER Metal2 ;
        RECT  735.64 999.6 736.04 1000 ;
    END
  END stack_maint_o.length[17]
  PIN stack_maint_o.length[18]
    DIRECTION OUTPUT ;
    USE SIGNAL ;
    PORT
      LAYER Metal2 ;
        RECT  737.56 999.6 737.96 1000 ;
    END
  END stack_maint_o.length[18]
  PIN stack_maint_o.length[19]
    DIRECTION OUTPUT ;
    USE SIGNAL ;
    PORT
      LAYER Metal2 ;
        RECT  739.48 999.6 739.88 1000 ;
    END
  END stack_maint_o.length[19]
  PIN stack_maint_o.length[1]
    DIRECTION OUTPUT ;
    USE SIGNAL ;
    PORT
      LAYER Metal2 ;
        RECT  704.92 999.6 705.32 1000 ;
    END
  END stack_maint_o.length[1]
  PIN stack_maint_o.length[20]
    DIRECTION OUTPUT ;
    USE SIGNAL ;
    PORT
      LAYER Metal2 ;
        RECT  741.4 999.6 741.8 1000 ;
    END
  END stack_maint_o.length[20]
  PIN stack_maint_o.length[21]
    DIRECTION OUTPUT ;
    USE SIGNAL ;
    PORT
      LAYER Metal2 ;
        RECT  743.32 999.6 743.72 1000 ;
    END
  END stack_maint_o.length[21]
  PIN stack_maint_o.length[22]
    DIRECTION OUTPUT ;
    USE SIGNAL ;
    PORT
      LAYER Metal2 ;
        RECT  745.24 999.6 745.64 1000 ;
    END
  END stack_maint_o.length[22]
  PIN stack_maint_o.length[23]
    DIRECTION OUTPUT ;
    USE SIGNAL ;
    PORT
      LAYER Metal2 ;
        RECT  747.16 999.6 747.56 1000 ;
    END
  END stack_maint_o.length[23]
  PIN stack_maint_o.length[24]
    DIRECTION OUTPUT ;
    USE SIGNAL ;
    PORT
      LAYER Metal2 ;
        RECT  749.08 999.6 749.48 1000 ;
    END
  END stack_maint_o.length[24]
  PIN stack_maint_o.length[25]
    DIRECTION OUTPUT ;
    USE SIGNAL ;
    PORT
      LAYER Metal2 ;
        RECT  751 999.6 751.4 1000 ;
    END
  END stack_maint_o.length[25]
  PIN stack_maint_o.length[26]
    DIRECTION OUTPUT ;
    USE SIGNAL ;
    PORT
      LAYER Metal2 ;
        RECT  752.92 999.6 753.32 1000 ;
    END
  END stack_maint_o.length[26]
  PIN stack_maint_o.length[27]
    DIRECTION OUTPUT ;
    USE SIGNAL ;
    PORT
      LAYER Metal2 ;
        RECT  754.84 999.6 755.24 1000 ;
    END
  END stack_maint_o.length[27]
  PIN stack_maint_o.length[28]
    DIRECTION OUTPUT ;
    USE SIGNAL ;
    PORT
      LAYER Metal2 ;
        RECT  756.76 999.6 757.16 1000 ;
    END
  END stack_maint_o.length[28]
  PIN stack_maint_o.length[29]
    DIRECTION OUTPUT ;
    USE SIGNAL ;
    PORT
      LAYER Metal2 ;
        RECT  758.68 999.6 759.08 1000 ;
    END
  END stack_maint_o.length[29]
  PIN stack_maint_o.length[2]
    DIRECTION OUTPUT ;
    USE SIGNAL ;
    PORT
      LAYER Metal2 ;
        RECT  706.84 999.6 707.24 1000 ;
    END
  END stack_maint_o.length[2]
  PIN stack_maint_o.length[30]
    DIRECTION OUTPUT ;
    USE SIGNAL ;
    PORT
      LAYER Metal2 ;
        RECT  760.6 999.6 761 1000 ;
    END
  END stack_maint_o.length[30]
  PIN stack_maint_o.length[31]
    DIRECTION OUTPUT ;
    USE SIGNAL ;
    PORT
      LAYER Metal2 ;
        RECT  762.52 999.6 762.92 1000 ;
    END
  END stack_maint_o.length[31]
  PIN stack_maint_o.length[32]
    DIRECTION OUTPUT ;
    USE SIGNAL ;
    PORT
      LAYER Metal2 ;
        RECT  764.44 999.6 764.84 1000 ;
    END
  END stack_maint_o.length[32]
  PIN stack_maint_o.length[33]
    DIRECTION OUTPUT ;
    USE SIGNAL ;
    PORT
      LAYER Metal2 ;
        RECT  766.36 999.6 766.76 1000 ;
    END
  END stack_maint_o.length[33]
  PIN stack_maint_o.length[34]
    DIRECTION OUTPUT ;
    USE SIGNAL ;
    PORT
      LAYER Metal2 ;
        RECT  768.28 999.6 768.68 1000 ;
    END
  END stack_maint_o.length[34]
  PIN stack_maint_o.length[35]
    DIRECTION OUTPUT ;
    USE SIGNAL ;
    PORT
      LAYER Metal2 ;
        RECT  770.2 999.6 770.6 1000 ;
    END
  END stack_maint_o.length[35]
  PIN stack_maint_o.length[36]
    DIRECTION OUTPUT ;
    USE SIGNAL ;
    PORT
      LAYER Metal2 ;
        RECT  772.12 999.6 772.52 1000 ;
    END
  END stack_maint_o.length[36]
  PIN stack_maint_o.length[37]
    DIRECTION OUTPUT ;
    USE SIGNAL ;
    PORT
      LAYER Metal2 ;
        RECT  774.04 999.6 774.44 1000 ;
    END
  END stack_maint_o.length[37]
  PIN stack_maint_o.length[38]
    DIRECTION OUTPUT ;
    USE SIGNAL ;
    PORT
      LAYER Metal2 ;
        RECT  775.96 999.6 776.36 1000 ;
    END
  END stack_maint_o.length[38]
  PIN stack_maint_o.length[39]
    DIRECTION OUTPUT ;
    USE SIGNAL ;
    PORT
      LAYER Metal2 ;
        RECT  777.88 999.6 778.28 1000 ;
    END
  END stack_maint_o.length[39]
  PIN stack_maint_o.length[3]
    DIRECTION OUTPUT ;
    USE SIGNAL ;
    PORT
      LAYER Metal2 ;
        RECT  708.76 999.6 709.16 1000 ;
    END
  END stack_maint_o.length[3]
  PIN stack_maint_o.length[40]
    DIRECTION OUTPUT ;
    USE SIGNAL ;
    PORT
      LAYER Metal2 ;
        RECT  779.8 999.6 780.2 1000 ;
    END
  END stack_maint_o.length[40]
  PIN stack_maint_o.length[41]
    DIRECTION OUTPUT ;
    USE SIGNAL ;
    PORT
      LAYER Metal2 ;
        RECT  781.72 999.6 782.12 1000 ;
    END
  END stack_maint_o.length[41]
  PIN stack_maint_o.length[42]
    DIRECTION OUTPUT ;
    USE SIGNAL ;
    PORT
      LAYER Metal2 ;
        RECT  783.64 999.6 784.04 1000 ;
    END
  END stack_maint_o.length[42]
  PIN stack_maint_o.length[43]
    DIRECTION OUTPUT ;
    USE SIGNAL ;
    PORT
      LAYER Metal2 ;
        RECT  785.56 999.6 785.96 1000 ;
    END
  END stack_maint_o.length[43]
  PIN stack_maint_o.length[44]
    DIRECTION OUTPUT ;
    USE SIGNAL ;
    PORT
      LAYER Metal2 ;
        RECT  787.48 999.6 787.88 1000 ;
    END
  END stack_maint_o.length[44]
  PIN stack_maint_o.length[45]
    DIRECTION OUTPUT ;
    USE SIGNAL ;
    PORT
      LAYER Metal2 ;
        RECT  789.4 999.6 789.8 1000 ;
    END
  END stack_maint_o.length[45]
  PIN stack_maint_o.length[46]
    DIRECTION OUTPUT ;
    USE SIGNAL ;
    PORT
      LAYER Metal2 ;
        RECT  791.32 999.6 791.72 1000 ;
    END
  END stack_maint_o.length[46]
  PIN stack_maint_o.length[47]
    DIRECTION OUTPUT ;
    USE SIGNAL ;
    PORT
      LAYER Metal2 ;
        RECT  793.24 999.6 793.64 1000 ;
    END
  END stack_maint_o.length[47]
  PIN stack_maint_o.length[48]
    DIRECTION OUTPUT ;
    USE SIGNAL ;
    PORT
      LAYER Metal2 ;
        RECT  795.16 999.6 795.56 1000 ;
    END
  END stack_maint_o.length[48]
  PIN stack_maint_o.length[49]
    DIRECTION OUTPUT ;
    USE SIGNAL ;
    PORT
      LAYER Metal2 ;
        RECT  797.08 999.6 797.48 1000 ;
    END
  END stack_maint_o.length[49]
  PIN stack_maint_o.length[4]
    DIRECTION OUTPUT ;
    USE SIGNAL ;
    PORT
      LAYER Metal2 ;
        RECT  710.68 999.6 711.08 1000 ;
    END
  END stack_maint_o.length[4]
  PIN stack_maint_o.length[50]
    DIRECTION OUTPUT ;
    USE SIGNAL ;
    PORT
      LAYER Metal2 ;
        RECT  799 999.6 799.4 1000 ;
    END
  END stack_maint_o.length[50]
  PIN stack_maint_o.length[51]
    DIRECTION OUTPUT ;
    USE SIGNAL ;
    PORT
      LAYER Metal2 ;
        RECT  800.92 999.6 801.32 1000 ;
    END
  END stack_maint_o.length[51]
  PIN stack_maint_o.length[52]
    DIRECTION OUTPUT ;
    USE SIGNAL ;
    PORT
      LAYER Metal2 ;
        RECT  802.84 999.6 803.24 1000 ;
    END
  END stack_maint_o.length[52]
  PIN stack_maint_o.length[53]
    DIRECTION OUTPUT ;
    USE SIGNAL ;
    PORT
      LAYER Metal2 ;
        RECT  804.76 999.6 805.16 1000 ;
    END
  END stack_maint_o.length[53]
  PIN stack_maint_o.length[54]
    DIRECTION OUTPUT ;
    USE SIGNAL ;
    PORT
      LAYER Metal2 ;
        RECT  806.68 999.6 807.08 1000 ;
    END
  END stack_maint_o.length[54]
  PIN stack_maint_o.length[55]
    DIRECTION OUTPUT ;
    USE SIGNAL ;
    PORT
      LAYER Metal2 ;
        RECT  808.6 999.6 809 1000 ;
    END
  END stack_maint_o.length[55]
  PIN stack_maint_o.length[56]
    DIRECTION OUTPUT ;
    USE SIGNAL ;
    PORT
      LAYER Metal2 ;
        RECT  810.52 999.6 810.92 1000 ;
    END
  END stack_maint_o.length[56]
  PIN stack_maint_o.length[57]
    DIRECTION OUTPUT ;
    USE SIGNAL ;
    PORT
      LAYER Metal2 ;
        RECT  812.44 999.6 812.84 1000 ;
    END
  END stack_maint_o.length[57]
  PIN stack_maint_o.length[58]
    DIRECTION OUTPUT ;
    USE SIGNAL ;
    PORT
      LAYER Metal2 ;
        RECT  814.36 999.6 814.76 1000 ;
    END
  END stack_maint_o.length[58]
  PIN stack_maint_o.length[59]
    DIRECTION OUTPUT ;
    USE SIGNAL ;
    PORT
      LAYER Metal2 ;
        RECT  816.28 999.6 816.68 1000 ;
    END
  END stack_maint_o.length[59]
  PIN stack_maint_o.length[5]
    DIRECTION OUTPUT ;
    USE SIGNAL ;
    PORT
      LAYER Metal2 ;
        RECT  712.6 999.6 713 1000 ;
    END
  END stack_maint_o.length[5]
  PIN stack_maint_o.length[60]
    DIRECTION OUTPUT ;
    USE SIGNAL ;
    PORT
      LAYER Metal2 ;
        RECT  818.2 999.6 818.6 1000 ;
    END
  END stack_maint_o.length[60]
  PIN stack_maint_o.length[61]
    DIRECTION OUTPUT ;
    USE SIGNAL ;
    PORT
      LAYER Metal2 ;
        RECT  820.12 999.6 820.52 1000 ;
    END
  END stack_maint_o.length[61]
  PIN stack_maint_o.length[62]
    DIRECTION OUTPUT ;
    USE SIGNAL ;
    PORT
      LAYER Metal2 ;
        RECT  822.04 999.6 822.44 1000 ;
    END
  END stack_maint_o.length[62]
  PIN stack_maint_o.length[63]
    DIRECTION OUTPUT ;
    USE SIGNAL ;
    PORT
      LAYER Metal2 ;
        RECT  823.96 999.6 824.36 1000 ;
    END
  END stack_maint_o.length[63]
  PIN stack_maint_o.length[6]
    DIRECTION OUTPUT ;
    USE SIGNAL ;
    PORT
      LAYER Metal2 ;
        RECT  714.52 999.6 714.92 1000 ;
    END
  END stack_maint_o.length[6]
  PIN stack_maint_o.length[7]
    DIRECTION OUTPUT ;
    USE SIGNAL ;
    PORT
      LAYER Metal2 ;
        RECT  716.44 999.6 716.84 1000 ;
    END
  END stack_maint_o.length[7]
  PIN stack_maint_o.length[8]
    DIRECTION OUTPUT ;
    USE SIGNAL ;
    PORT
      LAYER Metal2 ;
        RECT  718.36 999.6 718.76 1000 ;
    END
  END stack_maint_o.length[8]
  PIN stack_maint_o.length[9]
    DIRECTION OUTPUT ;
    USE SIGNAL ;
    PORT
      LAYER Metal2 ;
        RECT  720.28 999.6 720.68 1000 ;
    END
  END stack_maint_o.length[9]
  PIN stack_maint_o.valid
    DIRECTION OUTPUT ;
    USE SIGNAL ;
    PORT
      LAYER Metal2 ;
        RECT  699.16 999.6 699.56 1000 ;
    END
  END stack_maint_o.valid
  PIN sync_copile_i.cfp[0]
    DIRECTION INPUT ;
    USE SIGNAL ;
    PORT
      LAYER Metal3 ;
        RECT  899.6 517.66 900 518.06 ;
    END
  END sync_copile_i.cfp[0]
  PIN sync_copile_i.cfp[10]
    DIRECTION INPUT ;
    USE SIGNAL ;
    PORT
      LAYER Metal3 ;
        RECT  899.6 542.86 900 543.26 ;
    END
  END sync_copile_i.cfp[10]
  PIN sync_copile_i.cfp[11]
    DIRECTION INPUT ;
    USE SIGNAL ;
    PORT
      LAYER Metal3 ;
        RECT  899.6 545.38 900 545.78 ;
    END
  END sync_copile_i.cfp[11]
  PIN sync_copile_i.cfp[12]
    DIRECTION INPUT ;
    USE SIGNAL ;
    PORT
      LAYER Metal3 ;
        RECT  899.6 547.9 900 548.3 ;
    END
  END sync_copile_i.cfp[12]
  PIN sync_copile_i.cfp[13]
    DIRECTION INPUT ;
    USE SIGNAL ;
    PORT
      LAYER Metal3 ;
        RECT  899.6 550.42 900 550.82 ;
    END
  END sync_copile_i.cfp[13]
  PIN sync_copile_i.cfp[14]
    DIRECTION INPUT ;
    USE SIGNAL ;
    PORT
      LAYER Metal3 ;
        RECT  899.6 552.94 900 553.34 ;
    END
  END sync_copile_i.cfp[14]
  PIN sync_copile_i.cfp[15]
    DIRECTION INPUT ;
    USE SIGNAL ;
    PORT
      LAYER Metal3 ;
        RECT  899.6 555.46 900 555.86 ;
    END
  END sync_copile_i.cfp[15]
  PIN sync_copile_i.cfp[16]
    DIRECTION INPUT ;
    USE SIGNAL ;
    PORT
      LAYER Metal3 ;
        RECT  899.6 557.98 900 558.38 ;
    END
  END sync_copile_i.cfp[16]
  PIN sync_copile_i.cfp[17]
    DIRECTION INPUT ;
    USE SIGNAL ;
    PORT
      LAYER Metal3 ;
        RECT  899.6 560.5 900 560.9 ;
    END
  END sync_copile_i.cfp[17]
  PIN sync_copile_i.cfp[18]
    DIRECTION INPUT ;
    USE SIGNAL ;
    PORT
      LAYER Metal3 ;
        RECT  899.6 563.02 900 563.42 ;
    END
  END sync_copile_i.cfp[18]
  PIN sync_copile_i.cfp[19]
    DIRECTION INPUT ;
    USE SIGNAL ;
    PORT
      LAYER Metal3 ;
        RECT  899.6 565.54 900 565.94 ;
    END
  END sync_copile_i.cfp[19]
  PIN sync_copile_i.cfp[1]
    DIRECTION INPUT ;
    USE SIGNAL ;
    PORT
      LAYER Metal3 ;
        RECT  899.6 520.18 900 520.58 ;
    END
  END sync_copile_i.cfp[1]
  PIN sync_copile_i.cfp[20]
    DIRECTION INPUT ;
    USE SIGNAL ;
    PORT
      LAYER Metal3 ;
        RECT  899.6 568.06 900 568.46 ;
    END
  END sync_copile_i.cfp[20]
  PIN sync_copile_i.cfp[21]
    DIRECTION INPUT ;
    USE SIGNAL ;
    PORT
      LAYER Metal3 ;
        RECT  899.6 570.58 900 570.98 ;
    END
  END sync_copile_i.cfp[21]
  PIN sync_copile_i.cfp[22]
    DIRECTION INPUT ;
    USE SIGNAL ;
    PORT
      LAYER Metal3 ;
        RECT  899.6 573.1 900 573.5 ;
    END
  END sync_copile_i.cfp[22]
  PIN sync_copile_i.cfp[23]
    DIRECTION INPUT ;
    USE SIGNAL ;
    PORT
      LAYER Metal3 ;
        RECT  899.6 575.62 900 576.02 ;
    END
  END sync_copile_i.cfp[23]
  PIN sync_copile_i.cfp[24]
    DIRECTION INPUT ;
    USE SIGNAL ;
    PORT
      LAYER Metal3 ;
        RECT  899.6 578.14 900 578.54 ;
    END
  END sync_copile_i.cfp[24]
  PIN sync_copile_i.cfp[25]
    DIRECTION INPUT ;
    USE SIGNAL ;
    PORT
      LAYER Metal3 ;
        RECT  899.6 580.66 900 581.06 ;
    END
  END sync_copile_i.cfp[25]
  PIN sync_copile_i.cfp[26]
    DIRECTION INPUT ;
    USE SIGNAL ;
    PORT
      LAYER Metal3 ;
        RECT  899.6 583.18 900 583.58 ;
    END
  END sync_copile_i.cfp[26]
  PIN sync_copile_i.cfp[27]
    DIRECTION INPUT ;
    USE SIGNAL ;
    PORT
      LAYER Metal3 ;
        RECT  899.6 585.7 900 586.1 ;
    END
  END sync_copile_i.cfp[27]
  PIN sync_copile_i.cfp[28]
    DIRECTION INPUT ;
    USE SIGNAL ;
    PORT
      LAYER Metal3 ;
        RECT  899.6 588.22 900 588.62 ;
    END
  END sync_copile_i.cfp[28]
  PIN sync_copile_i.cfp[29]
    DIRECTION INPUT ;
    USE SIGNAL ;
    PORT
      LAYER Metal3 ;
        RECT  899.6 590.74 900 591.14 ;
    END
  END sync_copile_i.cfp[29]
  PIN sync_copile_i.cfp[2]
    DIRECTION INPUT ;
    USE SIGNAL ;
    PORT
      LAYER Metal3 ;
        RECT  899.6 522.7 900 523.1 ;
    END
  END sync_copile_i.cfp[2]
  PIN sync_copile_i.cfp[30]
    DIRECTION INPUT ;
    USE SIGNAL ;
    PORT
      LAYER Metal3 ;
        RECT  899.6 593.26 900 593.66 ;
    END
  END sync_copile_i.cfp[30]
  PIN sync_copile_i.cfp[31]
    DIRECTION INPUT ;
    USE SIGNAL ;
    PORT
      LAYER Metal3 ;
        RECT  899.6 595.78 900 596.18 ;
    END
  END sync_copile_i.cfp[31]
  PIN sync_copile_i.cfp[32]
    DIRECTION INPUT ;
    USE SIGNAL ;
    PORT
      LAYER Metal3 ;
        RECT  899.6 598.3 900 598.7 ;
    END
  END sync_copile_i.cfp[32]
  PIN sync_copile_i.cfp[33]
    DIRECTION INPUT ;
    USE SIGNAL ;
    PORT
      LAYER Metal3 ;
        RECT  899.6 600.82 900 601.22 ;
    END
  END sync_copile_i.cfp[33]
  PIN sync_copile_i.cfp[34]
    DIRECTION INPUT ;
    USE SIGNAL ;
    PORT
      LAYER Metal3 ;
        RECT  899.6 603.34 900 603.74 ;
    END
  END sync_copile_i.cfp[34]
  PIN sync_copile_i.cfp[35]
    DIRECTION INPUT ;
    USE SIGNAL ;
    PORT
      LAYER Metal3 ;
        RECT  899.6 605.86 900 606.26 ;
    END
  END sync_copile_i.cfp[35]
  PIN sync_copile_i.cfp[36]
    DIRECTION INPUT ;
    USE SIGNAL ;
    PORT
      LAYER Metal3 ;
        RECT  899.6 608.38 900 608.78 ;
    END
  END sync_copile_i.cfp[36]
  PIN sync_copile_i.cfp[37]
    DIRECTION INPUT ;
    USE SIGNAL ;
    PORT
      LAYER Metal3 ;
        RECT  899.6 610.9 900 611.3 ;
    END
  END sync_copile_i.cfp[37]
  PIN sync_copile_i.cfp[38]
    DIRECTION INPUT ;
    USE SIGNAL ;
    PORT
      LAYER Metal3 ;
        RECT  899.6 613.42 900 613.82 ;
    END
  END sync_copile_i.cfp[38]
  PIN sync_copile_i.cfp[39]
    DIRECTION INPUT ;
    USE SIGNAL ;
    PORT
      LAYER Metal3 ;
        RECT  899.6 615.94 900 616.34 ;
    END
  END sync_copile_i.cfp[39]
  PIN sync_copile_i.cfp[3]
    DIRECTION INPUT ;
    USE SIGNAL ;
    PORT
      LAYER Metal3 ;
        RECT  899.6 525.22 900 525.62 ;
    END
  END sync_copile_i.cfp[3]
  PIN sync_copile_i.cfp[40]
    DIRECTION INPUT ;
    USE SIGNAL ;
    PORT
      LAYER Metal3 ;
        RECT  899.6 618.46 900 618.86 ;
    END
  END sync_copile_i.cfp[40]
  PIN sync_copile_i.cfp[41]
    DIRECTION INPUT ;
    USE SIGNAL ;
    PORT
      LAYER Metal3 ;
        RECT  899.6 620.98 900 621.38 ;
    END
  END sync_copile_i.cfp[41]
  PIN sync_copile_i.cfp[42]
    DIRECTION INPUT ;
    USE SIGNAL ;
    PORT
      LAYER Metal3 ;
        RECT  899.6 623.5 900 623.9 ;
    END
  END sync_copile_i.cfp[42]
  PIN sync_copile_i.cfp[43]
    DIRECTION INPUT ;
    USE SIGNAL ;
    PORT
      LAYER Metal3 ;
        RECT  899.6 626.02 900 626.42 ;
    END
  END sync_copile_i.cfp[43]
  PIN sync_copile_i.cfp[44]
    DIRECTION INPUT ;
    USE SIGNAL ;
    PORT
      LAYER Metal3 ;
        RECT  899.6 628.54 900 628.94 ;
    END
  END sync_copile_i.cfp[44]
  PIN sync_copile_i.cfp[45]
    DIRECTION INPUT ;
    USE SIGNAL ;
    PORT
      LAYER Metal3 ;
        RECT  899.6 631.06 900 631.46 ;
    END
  END sync_copile_i.cfp[45]
  PIN sync_copile_i.cfp[46]
    DIRECTION INPUT ;
    USE SIGNAL ;
    PORT
      LAYER Metal3 ;
        RECT  899.6 633.58 900 633.98 ;
    END
  END sync_copile_i.cfp[46]
  PIN sync_copile_i.cfp[47]
    DIRECTION INPUT ;
    USE SIGNAL ;
    PORT
      LAYER Metal3 ;
        RECT  899.6 636.1 900 636.5 ;
    END
  END sync_copile_i.cfp[47]
  PIN sync_copile_i.cfp[48]
    DIRECTION INPUT ;
    USE SIGNAL ;
    PORT
      LAYER Metal3 ;
        RECT  899.6 638.62 900 639.02 ;
    END
  END sync_copile_i.cfp[48]
  PIN sync_copile_i.cfp[49]
    DIRECTION INPUT ;
    USE SIGNAL ;
    PORT
      LAYER Metal3 ;
        RECT  899.6 641.14 900 641.54 ;
    END
  END sync_copile_i.cfp[49]
  PIN sync_copile_i.cfp[4]
    DIRECTION INPUT ;
    USE SIGNAL ;
    PORT
      LAYER Metal3 ;
        RECT  899.6 527.74 900 528.14 ;
    END
  END sync_copile_i.cfp[4]
  PIN sync_copile_i.cfp[50]
    DIRECTION INPUT ;
    USE SIGNAL ;
    PORT
      LAYER Metal3 ;
        RECT  899.6 643.66 900 644.06 ;
    END
  END sync_copile_i.cfp[50]
  PIN sync_copile_i.cfp[51]
    DIRECTION INPUT ;
    USE SIGNAL ;
    PORT
      LAYER Metal3 ;
        RECT  899.6 646.18 900 646.58 ;
    END
  END sync_copile_i.cfp[51]
  PIN sync_copile_i.cfp[52]
    DIRECTION INPUT ;
    USE SIGNAL ;
    PORT
      LAYER Metal3 ;
        RECT  899.6 648.7 900 649.1 ;
    END
  END sync_copile_i.cfp[52]
  PIN sync_copile_i.cfp[53]
    DIRECTION INPUT ;
    USE SIGNAL ;
    PORT
      LAYER Metal3 ;
        RECT  899.6 651.22 900 651.62 ;
    END
  END sync_copile_i.cfp[53]
  PIN sync_copile_i.cfp[54]
    DIRECTION INPUT ;
    USE SIGNAL ;
    PORT
      LAYER Metal3 ;
        RECT  899.6 653.74 900 654.14 ;
    END
  END sync_copile_i.cfp[54]
  PIN sync_copile_i.cfp[55]
    DIRECTION INPUT ;
    USE SIGNAL ;
    PORT
      LAYER Metal3 ;
        RECT  899.6 656.26 900 656.66 ;
    END
  END sync_copile_i.cfp[55]
  PIN sync_copile_i.cfp[56]
    DIRECTION INPUT ;
    USE SIGNAL ;
    PORT
      LAYER Metal3 ;
        RECT  899.6 658.78 900 659.18 ;
    END
  END sync_copile_i.cfp[56]
  PIN sync_copile_i.cfp[57]
    DIRECTION INPUT ;
    USE SIGNAL ;
    PORT
      LAYER Metal3 ;
        RECT  899.6 661.3 900 661.7 ;
    END
  END sync_copile_i.cfp[57]
  PIN sync_copile_i.cfp[58]
    DIRECTION INPUT ;
    USE SIGNAL ;
    PORT
      LAYER Metal3 ;
        RECT  899.6 663.82 900 664.22 ;
    END
  END sync_copile_i.cfp[58]
  PIN sync_copile_i.cfp[59]
    DIRECTION INPUT ;
    USE SIGNAL ;
    PORT
      LAYER Metal3 ;
        RECT  899.6 666.34 900 666.74 ;
    END
  END sync_copile_i.cfp[59]
  PIN sync_copile_i.cfp[5]
    DIRECTION INPUT ;
    USE SIGNAL ;
    PORT
      LAYER Metal3 ;
        RECT  899.6 530.26 900 530.66 ;
    END
  END sync_copile_i.cfp[5]
  PIN sync_copile_i.cfp[60]
    DIRECTION INPUT ;
    USE SIGNAL ;
    PORT
      LAYER Metal3 ;
        RECT  899.6 668.86 900 669.26 ;
    END
  END sync_copile_i.cfp[60]
  PIN sync_copile_i.cfp[61]
    DIRECTION INPUT ;
    USE SIGNAL ;
    PORT
      LAYER Metal3 ;
        RECT  899.6 671.38 900 671.78 ;
    END
  END sync_copile_i.cfp[61]
  PIN sync_copile_i.cfp[62]
    DIRECTION INPUT ;
    USE SIGNAL ;
    PORT
      LAYER Metal3 ;
        RECT  899.6 673.9 900 674.3 ;
    END
  END sync_copile_i.cfp[62]
  PIN sync_copile_i.cfp[63]
    DIRECTION INPUT ;
    USE SIGNAL ;
    PORT
      LAYER Metal3 ;
        RECT  899.6 676.42 900 676.82 ;
    END
  END sync_copile_i.cfp[63]
  PIN sync_copile_i.cfp[6]
    DIRECTION INPUT ;
    USE SIGNAL ;
    PORT
      LAYER Metal3 ;
        RECT  899.6 532.78 900 533.18 ;
    END
  END sync_copile_i.cfp[6]
  PIN sync_copile_i.cfp[7]
    DIRECTION INPUT ;
    USE SIGNAL ;
    PORT
      LAYER Metal3 ;
        RECT  899.6 535.3 900 535.7 ;
    END
  END sync_copile_i.cfp[7]
  PIN sync_copile_i.cfp[8]
    DIRECTION INPUT ;
    USE SIGNAL ;
    PORT
      LAYER Metal3 ;
        RECT  899.6 537.82 900 538.22 ;
    END
  END sync_copile_i.cfp[8]
  PIN sync_copile_i.cfp[9]
    DIRECTION INPUT ;
    USE SIGNAL ;
    PORT
      LAYER Metal3 ;
        RECT  899.6 540.34 900 540.74 ;
    END
  END sync_copile_i.cfp[9]
  PIN sync_copile_i.csp[0]
    DIRECTION INPUT ;
    USE SIGNAL ;
    PORT
      LAYER Metal3 ;
        RECT  899.6 518.5 900 518.9 ;
    END
  END sync_copile_i.csp[0]
  PIN sync_copile_i.csp[10]
    DIRECTION INPUT ;
    USE SIGNAL ;
    PORT
      LAYER Metal3 ;
        RECT  899.6 543.7 900 544.1 ;
    END
  END sync_copile_i.csp[10]
  PIN sync_copile_i.csp[11]
    DIRECTION INPUT ;
    USE SIGNAL ;
    PORT
      LAYER Metal3 ;
        RECT  899.6 546.22 900 546.62 ;
    END
  END sync_copile_i.csp[11]
  PIN sync_copile_i.csp[12]
    DIRECTION INPUT ;
    USE SIGNAL ;
    PORT
      LAYER Metal3 ;
        RECT  899.6 548.74 900 549.14 ;
    END
  END sync_copile_i.csp[12]
  PIN sync_copile_i.csp[13]
    DIRECTION INPUT ;
    USE SIGNAL ;
    PORT
      LAYER Metal3 ;
        RECT  899.6 551.26 900 551.66 ;
    END
  END sync_copile_i.csp[13]
  PIN sync_copile_i.csp[14]
    DIRECTION INPUT ;
    USE SIGNAL ;
    PORT
      LAYER Metal3 ;
        RECT  899.6 553.78 900 554.18 ;
    END
  END sync_copile_i.csp[14]
  PIN sync_copile_i.csp[15]
    DIRECTION INPUT ;
    USE SIGNAL ;
    PORT
      LAYER Metal3 ;
        RECT  899.6 556.3 900 556.7 ;
    END
  END sync_copile_i.csp[15]
  PIN sync_copile_i.csp[16]
    DIRECTION INPUT ;
    USE SIGNAL ;
    PORT
      LAYER Metal3 ;
        RECT  899.6 558.82 900 559.22 ;
    END
  END sync_copile_i.csp[16]
  PIN sync_copile_i.csp[17]
    DIRECTION INPUT ;
    USE SIGNAL ;
    PORT
      LAYER Metal3 ;
        RECT  899.6 561.34 900 561.74 ;
    END
  END sync_copile_i.csp[17]
  PIN sync_copile_i.csp[18]
    DIRECTION INPUT ;
    USE SIGNAL ;
    PORT
      LAYER Metal3 ;
        RECT  899.6 563.86 900 564.26 ;
    END
  END sync_copile_i.csp[18]
  PIN sync_copile_i.csp[19]
    DIRECTION INPUT ;
    USE SIGNAL ;
    PORT
      LAYER Metal3 ;
        RECT  899.6 566.38 900 566.78 ;
    END
  END sync_copile_i.csp[19]
  PIN sync_copile_i.csp[1]
    DIRECTION INPUT ;
    USE SIGNAL ;
    PORT
      LAYER Metal3 ;
        RECT  899.6 521.02 900 521.42 ;
    END
  END sync_copile_i.csp[1]
  PIN sync_copile_i.csp[20]
    DIRECTION INPUT ;
    USE SIGNAL ;
    PORT
      LAYER Metal3 ;
        RECT  899.6 568.9 900 569.3 ;
    END
  END sync_copile_i.csp[20]
  PIN sync_copile_i.csp[21]
    DIRECTION INPUT ;
    USE SIGNAL ;
    PORT
      LAYER Metal3 ;
        RECT  899.6 571.42 900 571.82 ;
    END
  END sync_copile_i.csp[21]
  PIN sync_copile_i.csp[22]
    DIRECTION INPUT ;
    USE SIGNAL ;
    PORT
      LAYER Metal3 ;
        RECT  899.6 573.94 900 574.34 ;
    END
  END sync_copile_i.csp[22]
  PIN sync_copile_i.csp[23]
    DIRECTION INPUT ;
    USE SIGNAL ;
    PORT
      LAYER Metal3 ;
        RECT  899.6 576.46 900 576.86 ;
    END
  END sync_copile_i.csp[23]
  PIN sync_copile_i.csp[24]
    DIRECTION INPUT ;
    USE SIGNAL ;
    PORT
      LAYER Metal3 ;
        RECT  899.6 578.98 900 579.38 ;
    END
  END sync_copile_i.csp[24]
  PIN sync_copile_i.csp[25]
    DIRECTION INPUT ;
    USE SIGNAL ;
    PORT
      LAYER Metal3 ;
        RECT  899.6 581.5 900 581.9 ;
    END
  END sync_copile_i.csp[25]
  PIN sync_copile_i.csp[26]
    DIRECTION INPUT ;
    USE SIGNAL ;
    PORT
      LAYER Metal3 ;
        RECT  899.6 584.02 900 584.42 ;
    END
  END sync_copile_i.csp[26]
  PIN sync_copile_i.csp[27]
    DIRECTION INPUT ;
    USE SIGNAL ;
    PORT
      LAYER Metal3 ;
        RECT  899.6 586.54 900 586.94 ;
    END
  END sync_copile_i.csp[27]
  PIN sync_copile_i.csp[28]
    DIRECTION INPUT ;
    USE SIGNAL ;
    PORT
      LAYER Metal3 ;
        RECT  899.6 589.06 900 589.46 ;
    END
  END sync_copile_i.csp[28]
  PIN sync_copile_i.csp[29]
    DIRECTION INPUT ;
    USE SIGNAL ;
    PORT
      LAYER Metal3 ;
        RECT  899.6 591.58 900 591.98 ;
    END
  END sync_copile_i.csp[29]
  PIN sync_copile_i.csp[2]
    DIRECTION INPUT ;
    USE SIGNAL ;
    PORT
      LAYER Metal3 ;
        RECT  899.6 523.54 900 523.94 ;
    END
  END sync_copile_i.csp[2]
  PIN sync_copile_i.csp[30]
    DIRECTION INPUT ;
    USE SIGNAL ;
    PORT
      LAYER Metal3 ;
        RECT  899.6 594.1 900 594.5 ;
    END
  END sync_copile_i.csp[30]
  PIN sync_copile_i.csp[31]
    DIRECTION INPUT ;
    USE SIGNAL ;
    PORT
      LAYER Metal3 ;
        RECT  899.6 596.62 900 597.02 ;
    END
  END sync_copile_i.csp[31]
  PIN sync_copile_i.csp[32]
    DIRECTION INPUT ;
    USE SIGNAL ;
    PORT
      LAYER Metal3 ;
        RECT  899.6 599.14 900 599.54 ;
    END
  END sync_copile_i.csp[32]
  PIN sync_copile_i.csp[33]
    DIRECTION INPUT ;
    USE SIGNAL ;
    PORT
      LAYER Metal3 ;
        RECT  899.6 601.66 900 602.06 ;
    END
  END sync_copile_i.csp[33]
  PIN sync_copile_i.csp[34]
    DIRECTION INPUT ;
    USE SIGNAL ;
    PORT
      LAYER Metal3 ;
        RECT  899.6 604.18 900 604.58 ;
    END
  END sync_copile_i.csp[34]
  PIN sync_copile_i.csp[35]
    DIRECTION INPUT ;
    USE SIGNAL ;
    PORT
      LAYER Metal3 ;
        RECT  899.6 606.7 900 607.1 ;
    END
  END sync_copile_i.csp[35]
  PIN sync_copile_i.csp[36]
    DIRECTION INPUT ;
    USE SIGNAL ;
    PORT
      LAYER Metal3 ;
        RECT  899.6 609.22 900 609.62 ;
    END
  END sync_copile_i.csp[36]
  PIN sync_copile_i.csp[37]
    DIRECTION INPUT ;
    USE SIGNAL ;
    PORT
      LAYER Metal3 ;
        RECT  899.6 611.74 900 612.14 ;
    END
  END sync_copile_i.csp[37]
  PIN sync_copile_i.csp[38]
    DIRECTION INPUT ;
    USE SIGNAL ;
    PORT
      LAYER Metal3 ;
        RECT  899.6 614.26 900 614.66 ;
    END
  END sync_copile_i.csp[38]
  PIN sync_copile_i.csp[39]
    DIRECTION INPUT ;
    USE SIGNAL ;
    PORT
      LAYER Metal3 ;
        RECT  899.6 616.78 900 617.18 ;
    END
  END sync_copile_i.csp[39]
  PIN sync_copile_i.csp[3]
    DIRECTION INPUT ;
    USE SIGNAL ;
    PORT
      LAYER Metal3 ;
        RECT  899.6 526.06 900 526.46 ;
    END
  END sync_copile_i.csp[3]
  PIN sync_copile_i.csp[40]
    DIRECTION INPUT ;
    USE SIGNAL ;
    PORT
      LAYER Metal3 ;
        RECT  899.6 619.3 900 619.7 ;
    END
  END sync_copile_i.csp[40]
  PIN sync_copile_i.csp[41]
    DIRECTION INPUT ;
    USE SIGNAL ;
    PORT
      LAYER Metal3 ;
        RECT  899.6 621.82 900 622.22 ;
    END
  END sync_copile_i.csp[41]
  PIN sync_copile_i.csp[42]
    DIRECTION INPUT ;
    USE SIGNAL ;
    PORT
      LAYER Metal3 ;
        RECT  899.6 624.34 900 624.74 ;
    END
  END sync_copile_i.csp[42]
  PIN sync_copile_i.csp[43]
    DIRECTION INPUT ;
    USE SIGNAL ;
    PORT
      LAYER Metal3 ;
        RECT  899.6 626.86 900 627.26 ;
    END
  END sync_copile_i.csp[43]
  PIN sync_copile_i.csp[44]
    DIRECTION INPUT ;
    USE SIGNAL ;
    PORT
      LAYER Metal3 ;
        RECT  899.6 629.38 900 629.78 ;
    END
  END sync_copile_i.csp[44]
  PIN sync_copile_i.csp[45]
    DIRECTION INPUT ;
    USE SIGNAL ;
    PORT
      LAYER Metal3 ;
        RECT  899.6 631.9 900 632.3 ;
    END
  END sync_copile_i.csp[45]
  PIN sync_copile_i.csp[46]
    DIRECTION INPUT ;
    USE SIGNAL ;
    PORT
      LAYER Metal3 ;
        RECT  899.6 634.42 900 634.82 ;
    END
  END sync_copile_i.csp[46]
  PIN sync_copile_i.csp[47]
    DIRECTION INPUT ;
    USE SIGNAL ;
    PORT
      LAYER Metal3 ;
        RECT  899.6 636.94 900 637.34 ;
    END
  END sync_copile_i.csp[47]
  PIN sync_copile_i.csp[48]
    DIRECTION INPUT ;
    USE SIGNAL ;
    PORT
      LAYER Metal3 ;
        RECT  899.6 639.46 900 639.86 ;
    END
  END sync_copile_i.csp[48]
  PIN sync_copile_i.csp[49]
    DIRECTION INPUT ;
    USE SIGNAL ;
    PORT
      LAYER Metal3 ;
        RECT  899.6 641.98 900 642.38 ;
    END
  END sync_copile_i.csp[49]
  PIN sync_copile_i.csp[4]
    DIRECTION INPUT ;
    USE SIGNAL ;
    PORT
      LAYER Metal3 ;
        RECT  899.6 528.58 900 528.98 ;
    END
  END sync_copile_i.csp[4]
  PIN sync_copile_i.csp[50]
    DIRECTION INPUT ;
    USE SIGNAL ;
    PORT
      LAYER Metal3 ;
        RECT  899.6 644.5 900 644.9 ;
    END
  END sync_copile_i.csp[50]
  PIN sync_copile_i.csp[51]
    DIRECTION INPUT ;
    USE SIGNAL ;
    PORT
      LAYER Metal3 ;
        RECT  899.6 647.02 900 647.42 ;
    END
  END sync_copile_i.csp[51]
  PIN sync_copile_i.csp[52]
    DIRECTION INPUT ;
    USE SIGNAL ;
    PORT
      LAYER Metal3 ;
        RECT  899.6 649.54 900 649.94 ;
    END
  END sync_copile_i.csp[52]
  PIN sync_copile_i.csp[53]
    DIRECTION INPUT ;
    USE SIGNAL ;
    PORT
      LAYER Metal3 ;
        RECT  899.6 652.06 900 652.46 ;
    END
  END sync_copile_i.csp[53]
  PIN sync_copile_i.csp[54]
    DIRECTION INPUT ;
    USE SIGNAL ;
    PORT
      LAYER Metal3 ;
        RECT  899.6 654.58 900 654.98 ;
    END
  END sync_copile_i.csp[54]
  PIN sync_copile_i.csp[55]
    DIRECTION INPUT ;
    USE SIGNAL ;
    PORT
      LAYER Metal3 ;
        RECT  899.6 657.1 900 657.5 ;
    END
  END sync_copile_i.csp[55]
  PIN sync_copile_i.csp[56]
    DIRECTION INPUT ;
    USE SIGNAL ;
    PORT
      LAYER Metal3 ;
        RECT  899.6 659.62 900 660.02 ;
    END
  END sync_copile_i.csp[56]
  PIN sync_copile_i.csp[57]
    DIRECTION INPUT ;
    USE SIGNAL ;
    PORT
      LAYER Metal3 ;
        RECT  899.6 662.14 900 662.54 ;
    END
  END sync_copile_i.csp[57]
  PIN sync_copile_i.csp[58]
    DIRECTION INPUT ;
    USE SIGNAL ;
    PORT
      LAYER Metal3 ;
        RECT  899.6 664.66 900 665.06 ;
    END
  END sync_copile_i.csp[58]
  PIN sync_copile_i.csp[59]
    DIRECTION INPUT ;
    USE SIGNAL ;
    PORT
      LAYER Metal3 ;
        RECT  899.6 667.18 900 667.58 ;
    END
  END sync_copile_i.csp[59]
  PIN sync_copile_i.csp[5]
    DIRECTION INPUT ;
    USE SIGNAL ;
    PORT
      LAYER Metal3 ;
        RECT  899.6 531.1 900 531.5 ;
    END
  END sync_copile_i.csp[5]
  PIN sync_copile_i.csp[60]
    DIRECTION INPUT ;
    USE SIGNAL ;
    PORT
      LAYER Metal3 ;
        RECT  899.6 669.7 900 670.1 ;
    END
  END sync_copile_i.csp[60]
  PIN sync_copile_i.csp[61]
    DIRECTION INPUT ;
    USE SIGNAL ;
    PORT
      LAYER Metal3 ;
        RECT  899.6 672.22 900 672.62 ;
    END
  END sync_copile_i.csp[61]
  PIN sync_copile_i.csp[62]
    DIRECTION INPUT ;
    USE SIGNAL ;
    PORT
      LAYER Metal3 ;
        RECT  899.6 674.74 900 675.14 ;
    END
  END sync_copile_i.csp[62]
  PIN sync_copile_i.csp[63]
    DIRECTION INPUT ;
    USE SIGNAL ;
    PORT
      LAYER Metal3 ;
        RECT  899.6 677.26 900 677.66 ;
    END
  END sync_copile_i.csp[63]
  PIN sync_copile_i.csp[6]
    DIRECTION INPUT ;
    USE SIGNAL ;
    PORT
      LAYER Metal3 ;
        RECT  899.6 533.62 900 534.02 ;
    END
  END sync_copile_i.csp[6]
  PIN sync_copile_i.csp[7]
    DIRECTION INPUT ;
    USE SIGNAL ;
    PORT
      LAYER Metal3 ;
        RECT  899.6 536.14 900 536.54 ;
    END
  END sync_copile_i.csp[7]
  PIN sync_copile_i.csp[8]
    DIRECTION INPUT ;
    USE SIGNAL ;
    PORT
      LAYER Metal3 ;
        RECT  899.6 538.66 900 539.06 ;
    END
  END sync_copile_i.csp[8]
  PIN sync_copile_i.csp[9]
    DIRECTION INPUT ;
    USE SIGNAL ;
    PORT
      LAYER Metal3 ;
        RECT  899.6 541.18 900 541.58 ;
    END
  END sync_copile_i.csp[9]
  PIN sync_copile_i.hp[0]
    DIRECTION INPUT ;
    USE SIGNAL ;
    PORT
      LAYER Metal3 ;
        RECT  899.6 519.34 900 519.74 ;
    END
  END sync_copile_i.hp[0]
  PIN sync_copile_i.hp[10]
    DIRECTION INPUT ;
    USE SIGNAL ;
    PORT
      LAYER Metal3 ;
        RECT  899.6 544.54 900 544.94 ;
    END
  END sync_copile_i.hp[10]
  PIN sync_copile_i.hp[11]
    DIRECTION INPUT ;
    USE SIGNAL ;
    PORT
      LAYER Metal3 ;
        RECT  899.6 547.06 900 547.46 ;
    END
  END sync_copile_i.hp[11]
  PIN sync_copile_i.hp[12]
    DIRECTION INPUT ;
    USE SIGNAL ;
    PORT
      LAYER Metal3 ;
        RECT  899.6 549.58 900 549.98 ;
    END
  END sync_copile_i.hp[12]
  PIN sync_copile_i.hp[13]
    DIRECTION INPUT ;
    USE SIGNAL ;
    PORT
      LAYER Metal3 ;
        RECT  899.6 552.1 900 552.5 ;
    END
  END sync_copile_i.hp[13]
  PIN sync_copile_i.hp[14]
    DIRECTION INPUT ;
    USE SIGNAL ;
    PORT
      LAYER Metal3 ;
        RECT  899.6 554.62 900 555.02 ;
    END
  END sync_copile_i.hp[14]
  PIN sync_copile_i.hp[15]
    DIRECTION INPUT ;
    USE SIGNAL ;
    PORT
      LAYER Metal3 ;
        RECT  899.6 557.14 900 557.54 ;
    END
  END sync_copile_i.hp[15]
  PIN sync_copile_i.hp[16]
    DIRECTION INPUT ;
    USE SIGNAL ;
    PORT
      LAYER Metal3 ;
        RECT  899.6 559.66 900 560.06 ;
    END
  END sync_copile_i.hp[16]
  PIN sync_copile_i.hp[17]
    DIRECTION INPUT ;
    USE SIGNAL ;
    PORT
      LAYER Metal3 ;
        RECT  899.6 562.18 900 562.58 ;
    END
  END sync_copile_i.hp[17]
  PIN sync_copile_i.hp[18]
    DIRECTION INPUT ;
    USE SIGNAL ;
    PORT
      LAYER Metal3 ;
        RECT  899.6 564.7 900 565.1 ;
    END
  END sync_copile_i.hp[18]
  PIN sync_copile_i.hp[19]
    DIRECTION INPUT ;
    USE SIGNAL ;
    PORT
      LAYER Metal3 ;
        RECT  899.6 567.22 900 567.62 ;
    END
  END sync_copile_i.hp[19]
  PIN sync_copile_i.hp[1]
    DIRECTION INPUT ;
    USE SIGNAL ;
    PORT
      LAYER Metal3 ;
        RECT  899.6 521.86 900 522.26 ;
    END
  END sync_copile_i.hp[1]
  PIN sync_copile_i.hp[20]
    DIRECTION INPUT ;
    USE SIGNAL ;
    PORT
      LAYER Metal3 ;
        RECT  899.6 569.74 900 570.14 ;
    END
  END sync_copile_i.hp[20]
  PIN sync_copile_i.hp[21]
    DIRECTION INPUT ;
    USE SIGNAL ;
    PORT
      LAYER Metal3 ;
        RECT  899.6 572.26 900 572.66 ;
    END
  END sync_copile_i.hp[21]
  PIN sync_copile_i.hp[22]
    DIRECTION INPUT ;
    USE SIGNAL ;
    PORT
      LAYER Metal3 ;
        RECT  899.6 574.78 900 575.18 ;
    END
  END sync_copile_i.hp[22]
  PIN sync_copile_i.hp[23]
    DIRECTION INPUT ;
    USE SIGNAL ;
    PORT
      LAYER Metal3 ;
        RECT  899.6 577.3 900 577.7 ;
    END
  END sync_copile_i.hp[23]
  PIN sync_copile_i.hp[24]
    DIRECTION INPUT ;
    USE SIGNAL ;
    PORT
      LAYER Metal3 ;
        RECT  899.6 579.82 900 580.22 ;
    END
  END sync_copile_i.hp[24]
  PIN sync_copile_i.hp[25]
    DIRECTION INPUT ;
    USE SIGNAL ;
    PORT
      LAYER Metal3 ;
        RECT  899.6 582.34 900 582.74 ;
    END
  END sync_copile_i.hp[25]
  PIN sync_copile_i.hp[26]
    DIRECTION INPUT ;
    USE SIGNAL ;
    PORT
      LAYER Metal3 ;
        RECT  899.6 584.86 900 585.26 ;
    END
  END sync_copile_i.hp[26]
  PIN sync_copile_i.hp[27]
    DIRECTION INPUT ;
    USE SIGNAL ;
    PORT
      LAYER Metal3 ;
        RECT  899.6 587.38 900 587.78 ;
    END
  END sync_copile_i.hp[27]
  PIN sync_copile_i.hp[28]
    DIRECTION INPUT ;
    USE SIGNAL ;
    PORT
      LAYER Metal3 ;
        RECT  899.6 589.9 900 590.3 ;
    END
  END sync_copile_i.hp[28]
  PIN sync_copile_i.hp[29]
    DIRECTION INPUT ;
    USE SIGNAL ;
    PORT
      LAYER Metal3 ;
        RECT  899.6 592.42 900 592.82 ;
    END
  END sync_copile_i.hp[29]
  PIN sync_copile_i.hp[2]
    DIRECTION INPUT ;
    USE SIGNAL ;
    PORT
      LAYER Metal3 ;
        RECT  899.6 524.38 900 524.78 ;
    END
  END sync_copile_i.hp[2]
  PIN sync_copile_i.hp[30]
    DIRECTION INPUT ;
    USE SIGNAL ;
    PORT
      LAYER Metal3 ;
        RECT  899.6 594.94 900 595.34 ;
    END
  END sync_copile_i.hp[30]
  PIN sync_copile_i.hp[31]
    DIRECTION INPUT ;
    USE SIGNAL ;
    PORT
      LAYER Metal3 ;
        RECT  899.6 597.46 900 597.86 ;
    END
  END sync_copile_i.hp[31]
  PIN sync_copile_i.hp[32]
    DIRECTION INPUT ;
    USE SIGNAL ;
    PORT
      LAYER Metal3 ;
        RECT  899.6 599.98 900 600.38 ;
    END
  END sync_copile_i.hp[32]
  PIN sync_copile_i.hp[33]
    DIRECTION INPUT ;
    USE SIGNAL ;
    PORT
      LAYER Metal3 ;
        RECT  899.6 602.5 900 602.9 ;
    END
  END sync_copile_i.hp[33]
  PIN sync_copile_i.hp[34]
    DIRECTION INPUT ;
    USE SIGNAL ;
    PORT
      LAYER Metal3 ;
        RECT  899.6 605.02 900 605.42 ;
    END
  END sync_copile_i.hp[34]
  PIN sync_copile_i.hp[35]
    DIRECTION INPUT ;
    USE SIGNAL ;
    PORT
      LAYER Metal3 ;
        RECT  899.6 607.54 900 607.94 ;
    END
  END sync_copile_i.hp[35]
  PIN sync_copile_i.hp[36]
    DIRECTION INPUT ;
    USE SIGNAL ;
    PORT
      LAYER Metal3 ;
        RECT  899.6 610.06 900 610.46 ;
    END
  END sync_copile_i.hp[36]
  PIN sync_copile_i.hp[37]
    DIRECTION INPUT ;
    USE SIGNAL ;
    PORT
      LAYER Metal3 ;
        RECT  899.6 612.58 900 612.98 ;
    END
  END sync_copile_i.hp[37]
  PIN sync_copile_i.hp[38]
    DIRECTION INPUT ;
    USE SIGNAL ;
    PORT
      LAYER Metal3 ;
        RECT  899.6 615.1 900 615.5 ;
    END
  END sync_copile_i.hp[38]
  PIN sync_copile_i.hp[39]
    DIRECTION INPUT ;
    USE SIGNAL ;
    PORT
      LAYER Metal3 ;
        RECT  899.6 617.62 900 618.02 ;
    END
  END sync_copile_i.hp[39]
  PIN sync_copile_i.hp[3]
    DIRECTION INPUT ;
    USE SIGNAL ;
    PORT
      LAYER Metal3 ;
        RECT  899.6 526.9 900 527.3 ;
    END
  END sync_copile_i.hp[3]
  PIN sync_copile_i.hp[40]
    DIRECTION INPUT ;
    USE SIGNAL ;
    PORT
      LAYER Metal3 ;
        RECT  899.6 620.14 900 620.54 ;
    END
  END sync_copile_i.hp[40]
  PIN sync_copile_i.hp[41]
    DIRECTION INPUT ;
    USE SIGNAL ;
    PORT
      LAYER Metal3 ;
        RECT  899.6 622.66 900 623.06 ;
    END
  END sync_copile_i.hp[41]
  PIN sync_copile_i.hp[42]
    DIRECTION INPUT ;
    USE SIGNAL ;
    PORT
      LAYER Metal3 ;
        RECT  899.6 625.18 900 625.58 ;
    END
  END sync_copile_i.hp[42]
  PIN sync_copile_i.hp[43]
    DIRECTION INPUT ;
    USE SIGNAL ;
    PORT
      LAYER Metal3 ;
        RECT  899.6 627.7 900 628.1 ;
    END
  END sync_copile_i.hp[43]
  PIN sync_copile_i.hp[44]
    DIRECTION INPUT ;
    USE SIGNAL ;
    PORT
      LAYER Metal3 ;
        RECT  899.6 630.22 900 630.62 ;
    END
  END sync_copile_i.hp[44]
  PIN sync_copile_i.hp[45]
    DIRECTION INPUT ;
    USE SIGNAL ;
    PORT
      LAYER Metal3 ;
        RECT  899.6 632.74 900 633.14 ;
    END
  END sync_copile_i.hp[45]
  PIN sync_copile_i.hp[46]
    DIRECTION INPUT ;
    USE SIGNAL ;
    PORT
      LAYER Metal3 ;
        RECT  899.6 635.26 900 635.66 ;
    END
  END sync_copile_i.hp[46]
  PIN sync_copile_i.hp[47]
    DIRECTION INPUT ;
    USE SIGNAL ;
    PORT
      LAYER Metal3 ;
        RECT  899.6 637.78 900 638.18 ;
    END
  END sync_copile_i.hp[47]
  PIN sync_copile_i.hp[48]
    DIRECTION INPUT ;
    USE SIGNAL ;
    PORT
      LAYER Metal3 ;
        RECT  899.6 640.3 900 640.7 ;
    END
  END sync_copile_i.hp[48]
  PIN sync_copile_i.hp[49]
    DIRECTION INPUT ;
    USE SIGNAL ;
    PORT
      LAYER Metal3 ;
        RECT  899.6 642.82 900 643.22 ;
    END
  END sync_copile_i.hp[49]
  PIN sync_copile_i.hp[4]
    DIRECTION INPUT ;
    USE SIGNAL ;
    PORT
      LAYER Metal3 ;
        RECT  899.6 529.42 900 529.82 ;
    END
  END sync_copile_i.hp[4]
  PIN sync_copile_i.hp[50]
    DIRECTION INPUT ;
    USE SIGNAL ;
    PORT
      LAYER Metal3 ;
        RECT  899.6 645.34 900 645.74 ;
    END
  END sync_copile_i.hp[50]
  PIN sync_copile_i.hp[51]
    DIRECTION INPUT ;
    USE SIGNAL ;
    PORT
      LAYER Metal3 ;
        RECT  899.6 647.86 900 648.26 ;
    END
  END sync_copile_i.hp[51]
  PIN sync_copile_i.hp[52]
    DIRECTION INPUT ;
    USE SIGNAL ;
    PORT
      LAYER Metal3 ;
        RECT  899.6 650.38 900 650.78 ;
    END
  END sync_copile_i.hp[52]
  PIN sync_copile_i.hp[53]
    DIRECTION INPUT ;
    USE SIGNAL ;
    PORT
      LAYER Metal3 ;
        RECT  899.6 652.9 900 653.3 ;
    END
  END sync_copile_i.hp[53]
  PIN sync_copile_i.hp[54]
    DIRECTION INPUT ;
    USE SIGNAL ;
    PORT
      LAYER Metal3 ;
        RECT  899.6 655.42 900 655.82 ;
    END
  END sync_copile_i.hp[54]
  PIN sync_copile_i.hp[55]
    DIRECTION INPUT ;
    USE SIGNAL ;
    PORT
      LAYER Metal3 ;
        RECT  899.6 657.94 900 658.34 ;
    END
  END sync_copile_i.hp[55]
  PIN sync_copile_i.hp[56]
    DIRECTION INPUT ;
    USE SIGNAL ;
    PORT
      LAYER Metal3 ;
        RECT  899.6 660.46 900 660.86 ;
    END
  END sync_copile_i.hp[56]
  PIN sync_copile_i.hp[57]
    DIRECTION INPUT ;
    USE SIGNAL ;
    PORT
      LAYER Metal3 ;
        RECT  899.6 662.98 900 663.38 ;
    END
  END sync_copile_i.hp[57]
  PIN sync_copile_i.hp[58]
    DIRECTION INPUT ;
    USE SIGNAL ;
    PORT
      LAYER Metal3 ;
        RECT  899.6 665.5 900 665.9 ;
    END
  END sync_copile_i.hp[58]
  PIN sync_copile_i.hp[59]
    DIRECTION INPUT ;
    USE SIGNAL ;
    PORT
      LAYER Metal3 ;
        RECT  899.6 668.02 900 668.42 ;
    END
  END sync_copile_i.hp[59]
  PIN sync_copile_i.hp[5]
    DIRECTION INPUT ;
    USE SIGNAL ;
    PORT
      LAYER Metal3 ;
        RECT  899.6 531.94 900 532.34 ;
    END
  END sync_copile_i.hp[5]
  PIN sync_copile_i.hp[60]
    DIRECTION INPUT ;
    USE SIGNAL ;
    PORT
      LAYER Metal3 ;
        RECT  899.6 670.54 900 670.94 ;
    END
  END sync_copile_i.hp[60]
  PIN sync_copile_i.hp[61]
    DIRECTION INPUT ;
    USE SIGNAL ;
    PORT
      LAYER Metal3 ;
        RECT  899.6 673.06 900 673.46 ;
    END
  END sync_copile_i.hp[61]
  PIN sync_copile_i.hp[62]
    DIRECTION INPUT ;
    USE SIGNAL ;
    PORT
      LAYER Metal3 ;
        RECT  899.6 675.58 900 675.98 ;
    END
  END sync_copile_i.hp[62]
  PIN sync_copile_i.hp[63]
    DIRECTION INPUT ;
    USE SIGNAL ;
    PORT
      LAYER Metal3 ;
        RECT  899.6 678.1 900 678.5 ;
    END
  END sync_copile_i.hp[63]
  PIN sync_copile_i.hp[6]
    DIRECTION INPUT ;
    USE SIGNAL ;
    PORT
      LAYER Metal3 ;
        RECT  899.6 534.46 900 534.86 ;
    END
  END sync_copile_i.hp[6]
  PIN sync_copile_i.hp[7]
    DIRECTION INPUT ;
    USE SIGNAL ;
    PORT
      LAYER Metal3 ;
        RECT  899.6 536.98 900 537.38 ;
    END
  END sync_copile_i.hp[7]
  PIN sync_copile_i.hp[8]
    DIRECTION INPUT ;
    USE SIGNAL ;
    PORT
      LAYER Metal3 ;
        RECT  899.6 539.5 900 539.9 ;
    END
  END sync_copile_i.hp[8]
  PIN sync_copile_i.hp[9]
    DIRECTION INPUT ;
    USE SIGNAL ;
    PORT
      LAYER Metal3 ;
        RECT  899.6 542.02 900 542.42 ;
    END
  END sync_copile_i.hp[9]
  PIN sync_copile_i.hp_valid
    DIRECTION INPUT ;
    USE SIGNAL ;
    PORT
      LAYER Metal3 ;
        RECT  899.6 516.82 900 517.22 ;
    END
  END sync_copile_i.hp_valid
  PIN sync_valid_i
    DIRECTION INPUT ;
    USE SIGNAL ;
    PORT
      LAYER Metal3 ;
        RECT  899.6 515.98 900 516.38 ;
    END
  END sync_valid_i
  PIN VPWR
    DIRECTION INOUT ;
    USE POWER ;
    PORT
      LAYER TopMetal1 ;
        RECT  5.76 974.12 894.24 976.12 ;
        RECT  5.76 924.12 894.24 926.12 ;
        RECT  5.76 874.12 894.24 876.12 ;
        RECT  5.76 824.12 894.24 826.12 ;
        RECT  5.76 774.12 894.24 776.12 ;
        RECT  5.76 724.12 894.24 726.12 ;
        RECT  5.76 674.12 894.24 676.12 ;
        RECT  5.76 624.12 894.24 626.12 ;
        RECT  5.76 574.12 894.24 576.12 ;
        RECT  5.76 524.12 894.24 526.12 ;
        RECT  5.76 474.12 894.24 476.12 ;
        RECT  5.76 424.12 894.24 426.12 ;
        RECT  5.76 374.12 894.24 376.12 ;
        RECT  5.76 324.12 894.24 326.12 ;
        RECT  5.76 274.12 894.24 276.12 ;
        RECT  5.76 224.12 894.24 226.12 ;
        RECT  5.76 174.12 894.24 176.12 ;
        RECT  5.76 124.12 894.24 126.12 ;
        RECT  5.76 74.12 894.24 76.12 ;
        RECT  5.76 24.12 894.24 26.12 ;
      LAYER Metal4 ;
        RECT  865.26 14.9 866.26 983.02 ;
        RECT  815.26 14.9 816.26 983.02 ;
        RECT  765.26 14.9 766.26 983.02 ;
        RECT  715.26 14.9 716.26 983.02 ;
        RECT  665.26 14.9 666.26 983.02 ;
        RECT  615.26 14.9 616.26 983.02 ;
        RECT  565.26 14.9 566.26 983.02 ;
        RECT  515.26 14.9 516.26 983.02 ;
        RECT  465.26 14.9 466.26 983.02 ;
        RECT  415.26 14.9 416.26 983.02 ;
        RECT  365.26 14.9 366.26 983.02 ;
        RECT  315.26 14.9 316.26 983.02 ;
        RECT  265.26 14.9 266.26 983.02 ;
        RECT  215.26 14.9 216.26 983.02 ;
        RECT  165.26 14.9 166.26 983.02 ;
        RECT  115.26 14.9 116.26 983.02 ;
        RECT  65.26 14.9 66.26 983.02 ;
        RECT  15.26 14.9 16.26 983.02 ;
    END
  END VPWR
  PIN VGND
    DIRECTION INOUT ;
    USE GROUND ;
    PORT
      LAYER TopMetal1 ;
        RECT  5.76 980.12 894.24 982.12 ;
        RECT  5.76 930.12 894.24 932.12 ;
        RECT  5.76 880.12 894.24 882.12 ;
        RECT  5.76 830.12 894.24 832.12 ;
        RECT  5.76 780.12 894.24 782.12 ;
        RECT  5.76 730.12 894.24 732.12 ;
        RECT  5.76 680.12 894.24 682.12 ;
        RECT  5.76 630.12 894.24 632.12 ;
        RECT  5.76 580.12 894.24 582.12 ;
        RECT  5.76 530.12 894.24 532.12 ;
        RECT  5.76 480.12 894.24 482.12 ;
        RECT  5.76 430.12 894.24 432.12 ;
        RECT  5.76 380.12 894.24 382.12 ;
        RECT  5.76 330.12 894.24 332.12 ;
        RECT  5.76 280.12 894.24 282.12 ;
        RECT  5.76 230.12 894.24 232.12 ;
        RECT  5.76 180.12 894.24 182.12 ;
        RECT  5.76 130.12 894.24 132.12 ;
        RECT  5.76 80.12 894.24 82.12 ;
        RECT  5.76 30.12 894.24 32.12 ;
      LAYER Metal4 ;
        RECT  868.26 14.9 869.26 983.02 ;
        RECT  818.26 14.9 819.26 983.02 ;
        RECT  768.26 14.9 769.26 983.02 ;
        RECT  718.26 14.9 719.26 983.02 ;
        RECT  668.26 14.9 669.26 983.02 ;
        RECT  618.26 14.9 619.26 983.02 ;
        RECT  568.26 14.9 569.26 983.02 ;
        RECT  518.26 14.9 519.26 983.02 ;
        RECT  468.26 14.9 469.26 983.02 ;
        RECT  418.26 14.9 419.26 983.02 ;
        RECT  368.26 14.9 369.26 983.02 ;
        RECT  318.26 14.9 319.26 983.02 ;
        RECT  268.26 14.9 269.26 983.02 ;
        RECT  218.26 14.9 219.26 983.02 ;
        RECT  168.26 14.9 169.26 983.02 ;
        RECT  118.26 14.9 119.26 983.02 ;
        RECT  68.26 14.9 69.26 983.02 ;
        RECT  18.26 14.9 19.26 983.02 ;
    END
  END VGND
  OBS
    LAYER Metal1 ;
     RECT  0 0.82 900 1000 ;
    LAYER Metal2 ;
     RECT  0 0.82 900 1000 ;
    LAYER Metal3 ;
     RECT  0 0.82 900 1000 ;
    LAYER Metal4 ;
     RECT  0 0.82 900 1000 ;
    LAYER TopMetal1 ;
     RECT  0 0.82 900 1000 ;
  END
END ino_exec_entier
END LIBRARY
